###############################################################
#  Generated by:      Cadence Innovus 20.13-s083_1
#  OS:                Linux x86_64(Host ID rice-503-20-north)
#  Generated on:      Sat Jun 11 21:53:26 2022
#  Design:            user_proj_example
#  Command:           write_lef_abstract -specifyTopLayer 5 -PGPinLayers {5 6} -extractBlockObs -stripePin results/user_proj_example.lef
###############################################################

VERSION 5.8 ;

BUSBITCHARS "[]" ;
DIVIDERCHAR "/" ;

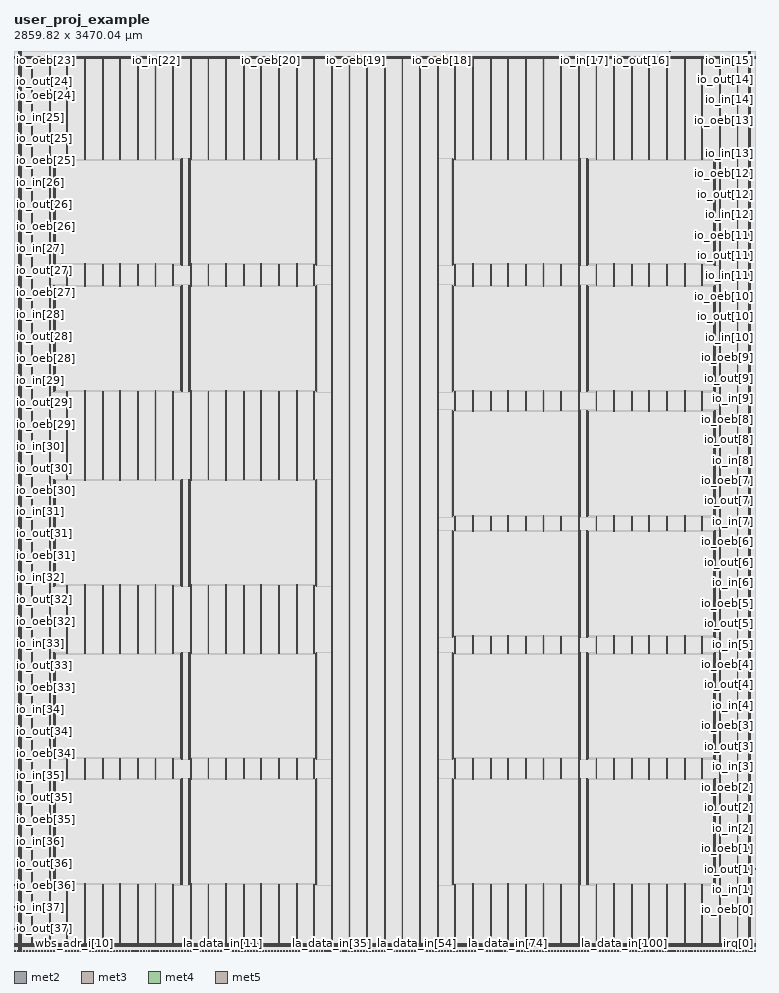
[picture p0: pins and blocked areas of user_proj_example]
MACRO user_proj_example
  CLASS BLOCK ;
  SIZE 2859.820000 BY 3470.040000 ;
  FOREIGN user_proj_example 0.000000 0.000000 ;
  ORIGIN 0 0 ;
  SYMMETRY X Y R90 ;
  PIN wb_clk_i
    DIRECTION INPUT ;
    USE SIGNAL ;
    ANTENNAPARTIALMETALAREA 4.1174 LAYER met2  ;
    ANTENNAPARTIALMETALSIDEAREA 20.426 LAYER met2  ;
    ANTENNAPARTIALCUTAREA 0.04 LAYER via2  ;
    ANTENNAPARTIALMETALAREA 8.6748 LAYER met3  ;
    ANTENNAPARTIALMETALSIDEAREA 46.736 LAYER met3  ;
    ANTENNAMODEL OXIDE1 ;
    ANTENNAGATEAREA 0.576 LAYER met3  ;
    ANTENNAMAXAREACAR 16.2276 LAYER met3  ;
    ANTENNAMAXSIDEAREACAR 83.9896 LAYER met3  ;
    ANTENNAMAXCUTCAR 0.158681 LAYER via3  ;
    PORT
      LAYER met2 ;
        RECT 0.620000 0.000000 0.760000 0.485000 ;
    END
  END wb_clk_i
  PIN wb_rst_i
    DIRECTION INPUT ;
    USE SIGNAL ;
    ANTENNAPARTIALMETALAREA 4.9795 LAYER met2  ;
    ANTENNAPARTIALMETALSIDEAREA 24.6715 LAYER met2  ;
    ANTENNAMODEL OXIDE1 ;
    ANTENNAGATEAREA 0.315 LAYER met2  ;
    ANTENNAMAXAREACAR 17.281 LAYER met2  ;
    ANTENNAMAXSIDEAREACAR 82.5778 LAYER met2  ;
    ANTENNAMAXCUTCAR 0.163175 LAYER via2  ;
    PORT
      LAYER met2 ;
        RECT 6.140000 0.000000 6.280000 0.485000 ;
    END
  END wb_rst_i
  PIN wbs_stb_i
    DIRECTION INPUT ;
    USE SIGNAL ;
    ANTENNAPARTIALMETALAREA 4.3959 LAYER met2  ;
    ANTENNAPARTIALMETALSIDEAREA 21.8715 LAYER met2  ;
    ANTENNAMODEL OXIDE1 ;
    ANTENNAGATEAREA 0.2475 LAYER met2  ;
    ANTENNAMAXAREACAR 24.3469 LAYER met2  ;
    ANTENNAMAXSIDEAREACAR 115.984 LAYER met2  ;
    ANTENNAMAXCUTCAR 0.207677 LAYER via2  ;
    PORT
      LAYER met2 ;
        RECT 23.620000 0.000000 23.760000 0.485000 ;
    END
  END wbs_stb_i
  PIN wbs_cyc_i
    DIRECTION INPUT ;
    USE SIGNAL ;
    ANTENNAPARTIALMETALAREA 4.5863 LAYER met2  ;
    ANTENNAPARTIALMETALSIDEAREA 22.8235 LAYER met2  ;
    ANTENNAMODEL OXIDE1 ;
    ANTENNAGATEAREA 0.2475 LAYER met2  ;
    ANTENNAMAXAREACAR 26.3545 LAYER met2  ;
    ANTENNAMAXSIDEAREACAR 129.685 LAYER met2  ;
    ANTENNAMAXCUTCAR 0.207677 LAYER via2  ;
    PORT
      LAYER met2 ;
        RECT 17.640000 0.000000 17.780000 0.485000 ;
    END
  END wbs_cyc_i
  PIN wbs_we_i
    DIRECTION INPUT ;
    USE SIGNAL ;
    ANTENNAPARTIALMETALAREA 5.5507 LAYER met2  ;
    ANTENNAPARTIALMETALSIDEAREA 27.5275 LAYER met2  ;
    ANTENNAMODEL OXIDE1 ;
    ANTENNAGATEAREA 0.159 LAYER met2  ;
    ANTENNAMAXAREACAR 37.6255 LAYER met2  ;
    ANTENNAMAXSIDEAREACAR 183 LAYER met2  ;
    ANTENNAMAXCUTCAR 0.32327 LAYER via2  ;
    PORT
      LAYER met2 ;
        RECT 29.600000 0.000000 29.740000 0.485000 ;
    END
  END wbs_we_i
  PIN wbs_sel_i[3]
    DIRECTION INPUT ;
    USE SIGNAL ;
    PORT
      LAYER met2 ;
        RECT 122.060000 0.000000 122.200000 0.485000 ;
    END
  END wbs_sel_i[3]
  PIN wbs_sel_i[2]
    DIRECTION INPUT ;
    USE SIGNAL ;
    PORT
      LAYER met2 ;
        RECT 99.060000 0.000000 99.200000 0.485000 ;
    END
  END wbs_sel_i[2]
  PIN wbs_sel_i[1]
    DIRECTION INPUT ;
    USE SIGNAL ;
    PORT
      LAYER met2 ;
        RECT 75.600000 0.000000 75.740000 0.485000 ;
    END
  END wbs_sel_i[1]
  PIN wbs_sel_i[0]
    DIRECTION INPUT ;
    USE SIGNAL ;
    PORT
      LAYER met2 ;
        RECT 52.600000 0.000000 52.740000 0.485000 ;
    END
  END wbs_sel_i[0]
  PIN wbs_dat_i[31]
    DIRECTION INPUT ;
    USE SIGNAL ;
    ANTENNAPARTIALMETALAREA 8.2991 LAYER met2  ;
    ANTENNAPARTIALMETALSIDEAREA 41.3875 LAYER met2  ;
    ANTENNAMODEL OXIDE1 ;
    ANTENNAGATEAREA 0.126 LAYER met2  ;
    ANTENNAMAXAREACAR 87.297 LAYER met2  ;
    ANTENNAMAXSIDEAREACAR 409.46 LAYER met2  ;
    ANTENNAMAXCUTCAR 0.407937 LAYER via2  ;
    PORT
      LAYER met2 ;
        RECT 603.680000 0.000000 603.820000 0.485000 ;
    END
  END wbs_dat_i[31]
  PIN wbs_dat_i[30]
    DIRECTION INPUT ;
    USE SIGNAL ;
    ANTENNAPARTIALMETALAREA 7.8735 LAYER met2  ;
    ANTENNAPARTIALMETALSIDEAREA 39.2595 LAYER met2  ;
    ANTENNAMODEL OXIDE1 ;
    ANTENNAGATEAREA 0.126 LAYER met2  ;
    ANTENNAMAXAREACAR 73.797 LAYER met2  ;
    ANTENNAMAXSIDEAREACAR 341.96 LAYER met2  ;
    ANTENNAMAXCUTCAR 0.407937 LAYER via2  ;
    PORT
      LAYER met2 ;
        RECT 586.200000 0.000000 586.340000 0.485000 ;
    END
  END wbs_dat_i[30]
  PIN wbs_dat_i[29]
    DIRECTION INPUT ;
    USE SIGNAL ;
    ANTENNAPARTIALMETALAREA 6.3951 LAYER met2  ;
    ANTENNAPARTIALMETALSIDEAREA 31.8675 LAYER met2  ;
    ANTENNAMODEL OXIDE1 ;
    ANTENNAGATEAREA 0.126 LAYER met2  ;
    ANTENNAMAXAREACAR 62.5748 LAYER met2  ;
    ANTENNAMAXSIDEAREACAR 285.849 LAYER met2  ;
    ANTENNAMAXCUTCAR 0.407937 LAYER via2  ;
    PORT
      LAYER met2 ;
        RECT 568.720000 0.000000 568.860000 0.485000 ;
    END
  END wbs_dat_i[29]
  PIN wbs_dat_i[28]
    DIRECTION INPUT ;
    USE SIGNAL ;
    ANTENNAPARTIALMETALAREA 7.9379 LAYER met2  ;
    ANTENNAPARTIALMETALSIDEAREA 39.5815 LAYER met2  ;
    ANTENNAMODEL OXIDE1 ;
    ANTENNAGATEAREA 0.126 LAYER met2  ;
    ANTENNAMAXAREACAR 88.8637 LAYER met2  ;
    ANTENNAMAXSIDEAREACAR 417.294 LAYER met2  ;
    ANTENNAMAXCUTCAR 0.407937 LAYER via2  ;
    PORT
      LAYER met2 ;
        RECT 551.240000 0.000000 551.380000 0.485000 ;
    END
  END wbs_dat_i[28]
  PIN wbs_dat_i[27]
    DIRECTION INPUT ;
    USE SIGNAL ;
    ANTENNAPARTIALMETALAREA 9.652 LAYER met2  ;
    ANTENNAPARTIALMETALSIDEAREA 48.034 LAYER met2  ;
    ANTENNAMODEL OXIDE1 ;
    ANTENNAGATEAREA 0.126 LAYER met2  ;
    ANTENNAMAXAREACAR 83.4272 LAYER met2  ;
    ANTENNAMAXSIDEAREACAR 389.71 LAYER met2  ;
    ANTENNAMAXCUTCAR 0.407937 LAYER via2  ;
    PORT
      LAYER met2 ;
        RECT 533.760000 0.000000 533.900000 0.485000 ;
    END
  END wbs_dat_i[27]
  PIN wbs_dat_i[26]
    DIRECTION INPUT ;
    USE SIGNAL ;
    ANTENNAPARTIALMETALAREA 9.9187 LAYER met2  ;
    ANTENNAPARTIALMETALSIDEAREA 49.3675 LAYER met2  ;
    ANTENNAMODEL OXIDE1 ;
    ANTENNAGATEAREA 0.126 LAYER met2  ;
    ANTENNAMAXAREACAR 85.5438 LAYER met2  ;
    ANTENNAMAXSIDEAREACAR 400.294 LAYER met2  ;
    ANTENNAMAXCUTCAR 0.407937 LAYER via2  ;
    PORT
      LAYER met2 ;
        RECT 516.740000 0.000000 516.880000 0.485000 ;
    END
  END wbs_dat_i[26]
  PIN wbs_dat_i[25]
    DIRECTION INPUT ;
    USE SIGNAL ;
    ANTENNAPARTIALMETALAREA 7.1831 LAYER met2  ;
    ANTENNAPARTIALMETALSIDEAREA 35.6895 LAYER met2  ;
    ANTENNAMODEL OXIDE1 ;
    ANTENNAGATEAREA 0.126 LAYER met2  ;
    ANTENNAMAXAREACAR 63.8327 LAYER met2  ;
    ANTENNAMAXSIDEAREACAR 291.738 LAYER met2  ;
    ANTENNAMAXCUTCAR 0.407937 LAYER via2  ;
    PORT
      LAYER met2 ;
        RECT 499.260000 0.000000 499.400000 0.485000 ;
    END
  END wbs_dat_i[25]
  PIN wbs_dat_i[24]
    DIRECTION INPUT ;
    USE SIGNAL ;
    ANTENNAPARTIALMETALAREA 6.8499 LAYER met2  ;
    ANTENNAPARTIALMETALSIDEAREA 34.0235 LAYER met2  ;
    ANTENNAMODEL OXIDE1 ;
    ANTENNAGATEAREA 0.126 LAYER met2  ;
    ANTENNAMAXAREACAR 80.101 LAYER met2  ;
    ANTENNAMAXSIDEAREACAR 372.544 LAYER met2  ;
    ANTENNAMAXCUTCAR 0.407937 LAYER via2  ;
    PORT
      LAYER met2 ;
        RECT 481.780000 0.000000 481.920000 0.485000 ;
    END
  END wbs_dat_i[24]
  PIN wbs_dat_i[23]
    DIRECTION INPUT ;
    USE SIGNAL ;
    ANTENNAPARTIALMETALAREA 7.9923 LAYER met2  ;
    ANTENNAPARTIALMETALSIDEAREA 39.7355 LAYER met2  ;
    ANTENNAMODEL OXIDE1 ;
    ANTENNAGATEAREA 0.126 LAYER met2  ;
    ANTENNAMAXAREACAR 70.651 LAYER met2  ;
    ANTENNAMAXSIDEAREACAR 325.294 LAYER met2  ;
    ANTENNAMAXCUTCAR 0.407937 LAYER via2  ;
    PORT
      LAYER met2 ;
        RECT 464.300000 0.000000 464.440000 0.485000 ;
    END
  END wbs_dat_i[23]
  PIN wbs_dat_i[22]
    DIRECTION INPUT ;
    USE SIGNAL ;
    ANTENNAPARTIALMETALAREA 7.9112 LAYER met2  ;
    ANTENNAPARTIALMETALSIDEAREA 39.277 LAYER met2  ;
    ANTENNAPARTIALCUTAREA 0.04 LAYER via2  ;
    ANTENNAPARTIALMETALAREA 0.2509 LAYER met3  ;
    ANTENNAPARTIALMETALSIDEAREA 1.808 LAYER met3  ;
    ANTENNAPARTIALCUTAREA 0.04 LAYER via3  ;
    ANTENNAPARTIALMETALAREA 4.1448 LAYER met4  ;
    ANTENNAPARTIALMETALSIDEAREA 22.576 LAYER met4  ;
    ANTENNAMODEL OXIDE1 ;
    ANTENNAGATEAREA 0.126 LAYER met4  ;
    ANTENNAMAXAREACAR 70.3264 LAYER met4  ;
    ANTENNAMAXSIDEAREACAR 342.262 LAYER met4  ;
    ANTENNAMAXCUTCAR 1.04286 LAYER via4  ;
    PORT
      LAYER met2 ;
        RECT 446.820000 0.000000 446.960000 0.485000 ;
    END
  END wbs_dat_i[22]
  PIN wbs_dat_i[21]
    DIRECTION INPUT ;
    USE SIGNAL ;
    ANTENNAPARTIALMETALAREA 6.9451 LAYER met2  ;
    ANTENNAPARTIALMETALSIDEAREA 34.4995 LAYER met2  ;
    ANTENNAMODEL OXIDE1 ;
    ANTENNAGATEAREA 0.126 LAYER met2  ;
    ANTENNAMAXAREACAR 86.6065 LAYER met2  ;
    ANTENNAMAXSIDEAREACAR 405.071 LAYER met2  ;
    ANTENNAMAXCUTCAR 0.407937 LAYER via2  ;
    PORT
      LAYER met2 ;
        RECT 429.800000 0.000000 429.940000 0.485000 ;
    END
  END wbs_dat_i[21]
  PIN wbs_dat_i[20]
    DIRECTION INPUT ;
    USE SIGNAL ;
    ANTENNAPARTIALMETALAREA 10.1666 LAYER met2  ;
    ANTENNAPARTIALMETALSIDEAREA 50.554 LAYER met2  ;
    ANTENNAPARTIALCUTAREA 0.04 LAYER via2  ;
    ANTENNAPARTIALMETALAREA 0.2509 LAYER met3  ;
    ANTENNAPARTIALMETALSIDEAREA 1.808 LAYER met3  ;
    ANTENNAPARTIALCUTAREA 0.04 LAYER via3  ;
    ANTENNAPARTIALMETALAREA 3.9618 LAYER met4  ;
    ANTENNAPARTIALMETALSIDEAREA 21.6 LAYER met4  ;
    ANTENNAMODEL OXIDE1 ;
    ANTENNAGATEAREA 0.126 LAYER met4  ;
    ANTENNAMAXAREACAR 103.864 LAYER met4  ;
    ANTENNAMAXSIDEAREACAR 510.405 LAYER met4  ;
    ANTENNAMAXCUTCAR 1.04286 LAYER via4  ;
    PORT
      LAYER met2 ;
        RECT 412.320000 0.000000 412.460000 0.485000 ;
    END
  END wbs_dat_i[20]
  PIN wbs_dat_i[19]
    DIRECTION INPUT ;
    USE SIGNAL ;
    ANTENNAPARTIALMETALAREA 0.8365 LAYER met2  ;
    ANTENNAPARTIALMETALSIDEAREA 4.0215 LAYER met2  ;
    ANTENNAPARTIALCUTAREA 0.04 LAYER via2  ;
    ANTENNAPARTIALMETALAREA 30.919 LAYER met3  ;
    ANTENNAPARTIALMETALSIDEAREA 165.368 LAYER met3  ;
    ANTENNAPARTIALCUTAREA 0.04 LAYER via3  ;
    ANTENNAPARTIALMETALAREA 0.6516 LAYER met4  ;
    ANTENNAPARTIALMETALSIDEAREA 4.416 LAYER met4  ;
    ANTENNAMODEL OXIDE1 ;
    ANTENNAGATEAREA 0.126 LAYER met4  ;
    ANTENNAMAXAREACAR 97.6891 LAYER met4  ;
    ANTENNAMAXSIDEAREACAR 477.952 LAYER met4  ;
    ANTENNAMAXCUTCAR 1.04286 LAYER via4  ;
    PORT
      LAYER met2 ;
        RECT 394.840000 0.000000 394.980000 0.485000 ;
    END
  END wbs_dat_i[19]
  PIN wbs_dat_i[18]
    DIRECTION INPUT ;
    USE SIGNAL ;
    ANTENNAPARTIALMETALAREA 0.3598 LAYER met2  ;
    ANTENNAPARTIALMETALSIDEAREA 1.638 LAYER met2  ;
    ANTENNAPARTIALCUTAREA 0.04 LAYER via2  ;
    ANTENNAPARTIALMETALAREA 44.719 LAYER met3  ;
    ANTENNAPARTIALMETALSIDEAREA 238.968 LAYER met3  ;
    ANTENNAPARTIALCUTAREA 0.04 LAYER via3  ;
    ANTENNAPARTIALMETALAREA 0.6516 LAYER met4  ;
    ANTENNAPARTIALMETALSIDEAREA 4.416 LAYER met4  ;
    ANTENNAMODEL OXIDE1 ;
    ANTENNAGATEAREA 0.126 LAYER met4  ;
    ANTENNAMAXAREACAR 126.784 LAYER met4  ;
    ANTENNAMAXSIDEAREACAR 624 LAYER met4  ;
    ANTENNAMAXCUTCAR 1.04286 LAYER via4  ;
    PORT
      LAYER met2 ;
        RECT 377.360000 0.000000 377.500000 0.485000 ;
    END
  END wbs_dat_i[18]
  PIN wbs_dat_i[17]
    DIRECTION INPUT ;
    USE SIGNAL ;
    ANTENNAPARTIALMETALAREA 1.876 LAYER met2  ;
    ANTENNAPARTIALMETALSIDEAREA 9.219 LAYER met2  ;
    ANTENNAPARTIALCUTAREA 0.04 LAYER via2  ;
    ANTENNAPARTIALMETALAREA 53.599 LAYER met3  ;
    ANTENNAPARTIALMETALSIDEAREA 286.328 LAYER met3  ;
    ANTENNAPARTIALCUTAREA 0.04 LAYER via3  ;
    ANTENNAPARTIALMETALAREA 0.6516 LAYER met4  ;
    ANTENNAPARTIALMETALSIDEAREA 4.416 LAYER met4  ;
    ANTENNAMODEL OXIDE1 ;
    ANTENNAGATEAREA 0.126 LAYER met4  ;
    ANTENNAMAXAREACAR 87.7597 LAYER met4  ;
    ANTENNAMAXSIDEAREACAR 427.782 LAYER met4  ;
    ANTENNAMAXCUTCAR 1.04286 LAYER via4  ;
    PORT
      LAYER met2 ;
        RECT 359.880000 0.000000 360.020000 0.485000 ;
    END
  END wbs_dat_i[17]
  PIN wbs_dat_i[16]
    DIRECTION INPUT ;
    USE SIGNAL ;
    ANTENNAPARTIALMETALAREA 7.9924 LAYER met2  ;
    ANTENNAPARTIALMETALSIDEAREA 39.683 LAYER met2  ;
    ANTENNAPARTIALCUTAREA 0.04 LAYER via2  ;
    ANTENNAPARTIALMETALAREA 0.255 LAYER met3  ;
    ANTENNAPARTIALMETALSIDEAREA 1.808 LAYER met3  ;
    ANTENNAPARTIALCUTAREA 0.04 LAYER via3  ;
    ANTENNAPARTIALMETALAREA 5.9748 LAYER met4  ;
    ANTENNAPARTIALMETALSIDEAREA 32.336 LAYER met4  ;
    ANTENNAMODEL OXIDE1 ;
    ANTENNAGATEAREA 0.126 LAYER met4  ;
    ANTENNAMAXAREACAR 59.1216 LAYER met4  ;
    ANTENNAMAXSIDEAREACAR 292.389 LAYER met4  ;
    ANTENNAMAXCUTCAR 1.04286 LAYER via4  ;
    PORT
      LAYER met2 ;
        RECT 342.400000 0.000000 342.540000 0.485000 ;
    END
  END wbs_dat_i[16]
  PIN wbs_dat_i[15]
    DIRECTION INPUT ;
    USE SIGNAL ;
    ANTENNAPARTIALMETALAREA 1.5344 LAYER met2  ;
    ANTENNAPARTIALMETALSIDEAREA 7.511 LAYER met2  ;
    ANTENNAPARTIALCUTAREA 0.04 LAYER via2  ;
    ANTENNAPARTIALMETALAREA 66.295 LAYER met3  ;
    ANTENNAPARTIALMETALSIDEAREA 354.04 LAYER met3  ;
    ANTENNAPARTIALCUTAREA 0.04 LAYER via3  ;
    ANTENNAPARTIALMETALAREA 0.6516 LAYER met4  ;
    ANTENNAPARTIALMETALSIDEAREA 4.416 LAYER met4  ;
    ANTENNAMODEL OXIDE1 ;
    ANTENNAGATEAREA 0.126 LAYER met4  ;
    ANTENNAMAXAREACAR 107.018 LAYER met4  ;
    ANTENNAMAXSIDEAREACAR 525.167 LAYER met4  ;
    ANTENNAMAXCUTCAR 1.04286 LAYER via4  ;
    PORT
      LAYER met2 ;
        RECT 325.380000 0.000000 325.520000 0.485000 ;
    END
  END wbs_dat_i[15]
  PIN wbs_dat_i[14]
    DIRECTION INPUT ;
    USE SIGNAL ;
    ANTENNAPARTIALMETALAREA 7.4209 LAYER met2  ;
    ANTENNAPARTIALMETALSIDEAREA 36.7605 LAYER met2  ;
    ANTENNAMODEL OXIDE1 ;
    ANTENNAGATEAREA 0.126 LAYER met2  ;
    ANTENNAMAXAREACAR 65.72 LAYER met2  ;
    ANTENNAMAXSIDEAREACAR 300.238 LAYER met2  ;
    ANTENNAMAXCUTCAR 0.407937 LAYER via2  ;
    PORT
      LAYER met2 ;
        RECT 307.900000 0.000000 308.040000 0.485000 ;
    END
  END wbs_dat_i[14]
  PIN wbs_dat_i[13]
    DIRECTION INPUT ;
    USE SIGNAL ;
    ANTENNAPARTIALMETALAREA 6.829 LAYER met2  ;
    ANTENNAPARTIALMETALSIDEAREA 33.866 LAYER met2  ;
    ANTENNAPARTIALCUTAREA 0.04 LAYER via2  ;
    ANTENNAPARTIALMETALAREA 0.255 LAYER met3  ;
    ANTENNAPARTIALMETALSIDEAREA 1.808 LAYER met3  ;
    ANTENNAPARTIALCUTAREA 0.04 LAYER via3  ;
    ANTENNAPARTIALMETALAREA 6.1578 LAYER met4  ;
    ANTENNAPARTIALMETALSIDEAREA 33.312 LAYER met4  ;
    ANTENNAMODEL OXIDE1 ;
    ANTENNAGATEAREA 0.126 LAYER met4  ;
    ANTENNAMAXAREACAR 85.2589 LAYER met4  ;
    ANTENNAMAXSIDEAREACAR 423.024 LAYER met4  ;
    ANTENNAMAXCUTCAR 1.04286 LAYER via4  ;
    PORT
      LAYER met2 ;
        RECT 290.420000 0.000000 290.560000 0.485000 ;
    END
  END wbs_dat_i[13]
  PIN wbs_dat_i[12]
    DIRECTION INPUT ;
    USE SIGNAL ;
    ANTENNAPARTIALMETALAREA 7.5569 LAYER met2  ;
    ANTENNAPARTIALMETALSIDEAREA 37.5585 LAYER met2  ;
    ANTENNAMODEL OXIDE1 ;
    ANTENNAGATEAREA 0.126 LAYER met2  ;
    ANTENNAMAXAREACAR 67.1954 LAYER met2  ;
    ANTENNAMAXSIDEAREACAR 308.016 LAYER met2  ;
    ANTENNAMAXCUTCAR 0.407937 LAYER via2  ;
    PORT
      LAYER met2 ;
        RECT 272.940000 0.000000 273.080000 0.485000 ;
    END
  END wbs_dat_i[12]
  PIN wbs_dat_i[11]
    DIRECTION INPUT ;
    USE SIGNAL ;
    ANTENNAPARTIALMETALAREA 5.6655 LAYER met2  ;
    ANTENNAPARTIALMETALSIDEAREA 28.1015 LAYER met2  ;
    ANTENNAMODEL OXIDE1 ;
    ANTENNAGATEAREA 0.126 LAYER met2  ;
    ANTENNAMAXAREACAR 65.3399 LAYER met2  ;
    ANTENNAMAXSIDEAREACAR 298.738 LAYER met2  ;
    ANTENNAMAXCUTCAR 0.407937 LAYER via2  ;
    PORT
      LAYER met2 ;
        RECT 255.460000 0.000000 255.600000 0.485000 ;
    END
  END wbs_dat_i[11]
  PIN wbs_dat_i[10]
    DIRECTION INPUT ;
    USE SIGNAL ;
    ANTENNAPARTIALMETALAREA 7.8636 LAYER met2  ;
    ANTENNAPARTIALMETALSIDEAREA 39.039 LAYER met2  ;
    ANTENNAPARTIALCUTAREA 0.04 LAYER via2  ;
    ANTENNAPARTIALMETALAREA 0.255 LAYER met3  ;
    ANTENNAPARTIALMETALSIDEAREA 1.808 LAYER met3  ;
    ANTENNAPARTIALCUTAREA 0.04 LAYER via3  ;
    ANTENNAPARTIALMETALAREA 5.9748 LAYER met4  ;
    ANTENNAPARTIALMETALSIDEAREA 32.336 LAYER met4  ;
    ANTENNAMODEL OXIDE1 ;
    ANTENNAGATEAREA 0.126 LAYER met4  ;
    ANTENNAMAXAREACAR 81.6177 LAYER met4  ;
    ANTENNAMAXSIDEAREACAR 404.333 LAYER met4  ;
    ANTENNAMAXCUTCAR 1.04286 LAYER via4  ;
    PORT
      LAYER met2 ;
        RECT 237.980000 0.000000 238.120000 0.485000 ;
    END
  END wbs_dat_i[10]
  PIN wbs_dat_i[9]
    DIRECTION INPUT ;
    USE SIGNAL ;
    ANTENNAPARTIALMETALAREA 2.2386 LAYER met2  ;
    ANTENNAPARTIALMETALSIDEAREA 11.032 LAYER met2  ;
    ANTENNAPARTIALCUTAREA 0.04 LAYER via2  ;
    ANTENNAPARTIALMETALAREA 93.343 LAYER met3  ;
    ANTENNAPARTIALMETALSIDEAREA 498.296 LAYER met3  ;
    ANTENNAPARTIALCUTAREA 0.04 LAYER via3  ;
    ANTENNAPARTIALMETALAREA 0.6516 LAYER met4  ;
    ANTENNAPARTIALMETALSIDEAREA 4.416 LAYER met4  ;
    ANTENNAMODEL OXIDE1 ;
    ANTENNAGATEAREA 0.126 LAYER met4  ;
    ANTENNAMAXAREACAR 81.4383 LAYER met4  ;
    ANTENNAMAXSIDEAREACAR 396.54 LAYER met4  ;
    ANTENNAMAXCUTCAR 1.04286 LAYER via4  ;
    PORT
      LAYER met2 ;
        RECT 220.960000 0.000000 221.100000 0.485000 ;
    END
  END wbs_dat_i[9]
  PIN wbs_dat_i[8]
    DIRECTION INPUT ;
    USE SIGNAL ;
    ANTENNAPARTIALMETALAREA 8.0092 LAYER met2  ;
    ANTENNAPARTIALMETALSIDEAREA 39.767 LAYER met2  ;
    ANTENNAPARTIALCUTAREA 0.04 LAYER via2  ;
    ANTENNAPARTIALMETALAREA 0.2509 LAYER met3  ;
    ANTENNAPARTIALMETALSIDEAREA 1.808 LAYER met3  ;
    ANTENNAPARTIALCUTAREA 0.04 LAYER via3  ;
    ANTENNAPARTIALMETALAREA 4.1448 LAYER met4  ;
    ANTENNAPARTIALMETALSIDEAREA 22.576 LAYER met4  ;
    ANTENNAMODEL OXIDE1 ;
    ANTENNAGATEAREA 0.126 LAYER met4  ;
    ANTENNAMAXAREACAR 58.4502 LAYER met4  ;
    ANTENNAMAXSIDEAREACAR 283.817 LAYER met4  ;
    ANTENNAMAXCUTCAR 1.04286 LAYER via4  ;
    PORT
      LAYER met2 ;
        RECT 203.480000 0.000000 203.620000 0.485000 ;
    END
  END wbs_dat_i[8]
  PIN wbs_dat_i[7]
    DIRECTION INPUT ;
    USE SIGNAL ;
    ANTENNAPARTIALMETALAREA 7.9112 LAYER met2  ;
    ANTENNAPARTIALMETALSIDEAREA 39.277 LAYER met2  ;
    ANTENNAPARTIALCUTAREA 0.04 LAYER via2  ;
    ANTENNAPARTIALMETALAREA 0.2509 LAYER met3  ;
    ANTENNAPARTIALMETALSIDEAREA 1.808 LAYER met3  ;
    ANTENNAPARTIALCUTAREA 0.04 LAYER via3  ;
    ANTENNAPARTIALMETALAREA 4.1448 LAYER met4  ;
    ANTENNAPARTIALMETALSIDEAREA 22.576 LAYER met4  ;
    ANTENNAMODEL OXIDE1 ;
    ANTENNAGATEAREA 0.126 LAYER met4  ;
    ANTENNAMAXAREACAR 82.4946 LAYER met4  ;
    ANTENNAMAXSIDEAREACAR 404.04 LAYER met4  ;
    ANTENNAMAXCUTCAR 1.04286 LAYER via4  ;
    PORT
      LAYER met2 ;
        RECT 186.000000 0.000000 186.140000 0.485000 ;
    END
  END wbs_dat_i[7]
  PIN wbs_dat_i[6]
    DIRECTION INPUT ;
    USE SIGNAL ;
    ANTENNAPARTIALMETALAREA 8.3731 LAYER met2  ;
    ANTENNAPARTIALMETALSIDEAREA 41.6395 LAYER met2  ;
    ANTENNAMODEL OXIDE1 ;
    ANTENNAGATEAREA 0.126 LAYER met2  ;
    ANTENNAMAXAREACAR 127.701 LAYER met2  ;
    ANTENNAMAXSIDEAREACAR 610.544 LAYER met2  ;
    ANTENNAMAXCUTCAR 0.407937 LAYER via2  ;
    PORT
      LAYER met2 ;
        RECT 168.520000 0.000000 168.660000 0.485000 ;
    END
  END wbs_dat_i[6]
  PIN wbs_dat_i[5]
    DIRECTION INPUT ;
    USE SIGNAL ;
    ANTENNAPARTIALMETALAREA 8.4263 LAYER met2  ;
    ANTENNAPARTIALMETALSIDEAREA 41.9055 LAYER met2  ;
    ANTENNAMODEL OXIDE1 ;
    ANTENNAGATEAREA 0.126 LAYER met2  ;
    ANTENNAMAXAREACAR 74.0954 LAYER met2  ;
    ANTENNAMAXSIDEAREACAR 342.516 LAYER met2  ;
    ANTENNAMAXCUTCAR 0.407937 LAYER via2  ;
    PORT
      LAYER met2 ;
        RECT 151.040000 0.000000 151.180000 0.485000 ;
    END
  END wbs_dat_i[5]
  PIN wbs_dat_i[4]
    DIRECTION INPUT ;
    USE SIGNAL ;
    ANTENNAPARTIALMETALAREA 9.0004 LAYER met2  ;
    ANTENNAPARTIALMETALSIDEAREA 44.723 LAYER met2  ;
    ANTENNAPARTIALCUTAREA 0.04 LAYER via2  ;
    ANTENNAPARTIALMETALAREA 0.2509 LAYER met3  ;
    ANTENNAPARTIALMETALSIDEAREA 1.808 LAYER met3  ;
    ANTENNAPARTIALCUTAREA 0.04 LAYER via3  ;
    ANTENNAPARTIALMETALAREA 3.9618 LAYER met4  ;
    ANTENNAPARTIALMETALSIDEAREA 21.6 LAYER met4  ;
    ANTENNAMODEL OXIDE1 ;
    ANTENNAGATEAREA 0.126 LAYER met4  ;
    ANTENNAMAXAREACAR 51.5978 LAYER met4  ;
    ANTENNAMAXSIDEAREACAR 249.071 LAYER met4  ;
    ANTENNAMAXCUTCAR 1.04286 LAYER via4  ;
    PORT
      LAYER met2 ;
        RECT 133.560000 0.000000 133.700000 0.485000 ;
    END
  END wbs_dat_i[4]
  PIN wbs_dat_i[3]
    DIRECTION INPUT ;
    USE SIGNAL ;
    ANTENNAPARTIALMETALAREA 9.8779 LAYER met2  ;
    ANTENNAPARTIALMETALSIDEAREA 49.0455 LAYER met2  ;
    ANTENNAMODEL OXIDE1 ;
    ANTENNAGATEAREA 0.126 LAYER met2  ;
    ANTENNAMAXAREACAR 84.9145 LAYER met2  ;
    ANTENNAMAXSIDEAREACAR 396.21 LAYER met2  ;
    ANTENNAMAXCUTCAR 0.407937 LAYER via2  ;
    PORT
      LAYER met2 ;
        RECT 110.560000 0.000000 110.700000 0.485000 ;
    END
  END wbs_dat_i[3]
  PIN wbs_dat_i[2]
    DIRECTION INPUT ;
    USE SIGNAL ;
    ANTENNADIFFAREA 0.4347 LAYER met2  ;
    ANTENNAPARTIALMETALAREA 11.6099 LAYER met2  ;
    ANTENNAPARTIALMETALSIDEAREA 57.8235 LAYER met2  ;
    ANTENNAMODEL OXIDE1 ;
    ANTENNAGATEAREA 0.126 LAYER met2  ;
    ANTENNAMAXAREACAR 117.458 LAYER met2  ;
    ANTENNAMAXSIDEAREACAR 558.794 LAYER met2  ;
    ANTENNAMAXCUTCAR 0.407937 LAYER via2  ;
    PORT
      LAYER met2 ;
        RECT 87.560000 0.000000 87.700000 0.485000 ;
    END
  END wbs_dat_i[2]
  PIN wbs_dat_i[1]
    DIRECTION INPUT ;
    USE SIGNAL ;
    ANTENNAPARTIALMETALAREA 9.5419 LAYER met2  ;
    ANTENNAPARTIALMETALSIDEAREA 47.3655 LAYER met2  ;
    ANTENNAMODEL OXIDE1 ;
    ANTENNAGATEAREA 0.126 LAYER met2  ;
    ANTENNAMAXAREACAR 84.4827 LAYER met2  ;
    ANTENNAMAXSIDEAREACAR 393.516 LAYER met2  ;
    ANTENNAMAXCUTCAR 0.407937 LAYER via2  ;
    PORT
      LAYER met2 ;
        RECT 64.100000 0.000000 64.240000 0.485000 ;
    END
  END wbs_dat_i[1]
  PIN wbs_dat_i[0]
    DIRECTION INPUT ;
    USE SIGNAL ;
    ANTENNAPARTIALMETALAREA 6.7547 LAYER met2  ;
    ANTENNAPARTIALMETALSIDEAREA 33.5475 LAYER met2  ;
    ANTENNAMODEL OXIDE1 ;
    ANTENNAGATEAREA 0.126 LAYER met2  ;
    ANTENNAMAXAREACAR 62.9454 LAYER met2  ;
    ANTENNAMAXSIDEAREACAR 286.766 LAYER met2  ;
    ANTENNAMAXCUTCAR 0.407937 LAYER via2  ;
    PORT
      LAYER met2 ;
        RECT 41.100000 0.000000 41.240000 0.485000 ;
    END
  END wbs_dat_i[0]
  PIN wbs_adr_i[31]
    DIRECTION INPUT ;
    USE SIGNAL ;
    ANTENNAPARTIALMETALAREA 5.2695 LAYER met2  ;
    ANTENNAPARTIALMETALSIDEAREA 26.2395 LAYER met2  ;
    ANTENNAMODEL OXIDE1 ;
    ANTENNAGATEAREA 0.126 LAYER met2  ;
    ANTENNAMAXAREACAR 76.6526 LAYER met2  ;
    ANTENNAMAXSIDEAREACAR 356.238 LAYER met2  ;
    ANTENNAMAXCUTCAR 0.407937 LAYER via2  ;
    PORT
      LAYER met2 ;
        RECT 597.700000 0.000000 597.840000 0.485000 ;
    END
  END wbs_adr_i[31]
  PIN wbs_adr_i[30]
    DIRECTION INPUT ;
    USE SIGNAL ;
    ANTENNAPARTIALMETALAREA 5.8267 LAYER met2  ;
    ANTENNAPARTIALMETALSIDEAREA 29.0255 LAYER met2  ;
    ANTENNAMODEL OXIDE1 ;
    ANTENNAGATEAREA 0.126 LAYER met2  ;
    ANTENNAMAXAREACAR 53.4637 LAYER met2  ;
    ANTENNAMAXSIDEAREACAR 240.294 LAYER met2  ;
    ANTENNAMAXCUTCAR 0.407937 LAYER via2  ;
    PORT
      LAYER met2 ;
        RECT 580.220000 0.000000 580.360000 0.485000 ;
    END
  END wbs_adr_i[30]
  PIN wbs_adr_i[29]
    DIRECTION INPUT ;
    USE SIGNAL ;
    ANTENNAPARTIALMETALAREA 6.1907 LAYER met2  ;
    ANTENNAPARTIALMETALSIDEAREA 30.8455 LAYER met2  ;
    ANTENNAMODEL OXIDE1 ;
    ANTENNAGATEAREA 0.126 LAYER met2  ;
    ANTENNAMAXAREACAR 57.8859 LAYER met2  ;
    ANTENNAMAXSIDEAREACAR 262.405 LAYER met2  ;
    ANTENNAMAXCUTCAR 0.407937 LAYER via2  ;
    PORT
      LAYER met2 ;
        RECT 563.200000 0.000000 563.340000 0.485000 ;
    END
  END wbs_adr_i[29]
  PIN wbs_adr_i[28]
    DIRECTION INPUT ;
    USE SIGNAL ;
    ANTENNAPARTIALMETALAREA 5.3535 LAYER met2  ;
    ANTENNAPARTIALMETALSIDEAREA 26.6595 LAYER met2  ;
    ANTENNAMODEL OXIDE1 ;
    ANTENNAGATEAREA 0.126 LAYER met2  ;
    ANTENNAMAXAREACAR 71.1748 LAYER met2  ;
    ANTENNAMAXSIDEAREACAR 328.849 LAYER met2  ;
    ANTENNAMAXCUTCAR 0.407937 LAYER via2  ;
    PORT
      LAYER met2 ;
        RECT 545.720000 0.000000 545.860000 0.485000 ;
    END
  END wbs_adr_i[28]
  PIN wbs_adr_i[27]
    DIRECTION INPUT ;
    USE SIGNAL ;
    ANTENNAPARTIALMETALAREA 5.6335 LAYER met2  ;
    ANTENNAPARTIALMETALSIDEAREA 28.0595 LAYER met2  ;
    ANTENNAMODEL OXIDE1 ;
    ANTENNAGATEAREA 0.126 LAYER met2  ;
    ANTENNAMAXAREACAR 51.5343 LAYER met2  ;
    ANTENNAMAXSIDEAREACAR 231.183 LAYER met2  ;
    ANTENNAMAXCUTCAR 0.407937 LAYER via2  ;
    PORT
      LAYER met2 ;
        RECT 528.240000 0.000000 528.380000 0.485000 ;
    END
  END wbs_adr_i[27]
  PIN wbs_adr_i[26]
    DIRECTION INPUT ;
    USE SIGNAL ;
    ANTENNAPARTIALMETALAREA 5.0959 LAYER met2  ;
    ANTENNAPARTIALMETALSIDEAREA 25.3715 LAYER met2  ;
    ANTENNAMODEL OXIDE1 ;
    ANTENNAGATEAREA 0.126 LAYER met2  ;
    ANTENNAMAXAREACAR 50.2192 LAYER met2  ;
    ANTENNAMAXSIDEAREACAR 224.071 LAYER met2  ;
    ANTENNAMAXCUTCAR 0.407937 LAYER via2  ;
    PORT
      LAYER met2 ;
        RECT 510.760000 0.000000 510.900000 0.485000 ;
    END
  END wbs_adr_i[26]
  PIN wbs_adr_i[25]
    DIRECTION INPUT ;
    USE SIGNAL ;
    ANTENNAPARTIALMETALAREA 6.8816 LAYER met2  ;
    ANTENNAPARTIALMETALSIDEAREA 34.3 LAYER met2  ;
    ANTENNAMODEL OXIDE1 ;
    ANTENNAGATEAREA 0.126 LAYER met2  ;
    ANTENNAMAXAREACAR 72.1748 LAYER met2  ;
    ANTENNAMAXSIDEAREACAR 333.849 LAYER met2  ;
    ANTENNAMAXCUTCAR 0.407937 LAYER via2  ;
    PORT
      LAYER met2 ;
        RECT 493.280000 0.000000 493.420000 0.485000 ;
    END
  END wbs_adr_i[25]
  PIN wbs_adr_i[24]
    DIRECTION INPUT ;
    USE SIGNAL ;
    ANTENNAPARTIALMETALAREA 6.3599 LAYER met2  ;
    ANTENNAPARTIALMETALSIDEAREA 31.5735 LAYER met2  ;
    ANTENNAMODEL OXIDE1 ;
    ANTENNAGATEAREA 0.126 LAYER met2  ;
    ANTENNAMAXAREACAR 80.4288 LAYER met2  ;
    ANTENNAMAXSIDEAREACAR 374.183 LAYER met2  ;
    ANTENNAMAXCUTCAR 0.407937 LAYER via2  ;
    PORT
      LAYER met2 ;
        RECT 475.800000 0.000000 475.940000 0.485000 ;
    END
  END wbs_adr_i[24]
  PIN wbs_adr_i[23]
    DIRECTION INPUT ;
    USE SIGNAL ;
    ANTENNAPARTIALMETALAREA 5.9667 LAYER met2  ;
    ANTENNAPARTIALMETALSIDEAREA 29.7255 LAYER met2  ;
    ANTENNAMODEL OXIDE1 ;
    ANTENNAGATEAREA 0.126 LAYER met2  ;
    ANTENNAMAXAREACAR 104.164 LAYER met2  ;
    ANTENNAMAXSIDEAREACAR 493.794 LAYER met2  ;
    ANTENNAMAXCUTCAR 0.407937 LAYER via2  ;
    PORT
      LAYER met2 ;
        RECT 458.780000 0.000000 458.920000 0.485000 ;
    END
  END wbs_adr_i[23]
  PIN wbs_adr_i[22]
    DIRECTION INPUT ;
    USE SIGNAL ;
    ANTENNAPARTIALMETALAREA 5.3001 LAYER met2  ;
    ANTENNAPARTIALMETALSIDEAREA 26.2745 LAYER met2  ;
    ANTENNAMODEL OXIDE1 ;
    ANTENNAGATEAREA 0.126 LAYER met2  ;
    ANTENNAMAXAREACAR 48.8883 LAYER met2  ;
    ANTENNAMAXSIDEAREACAR 217.016 LAYER met2  ;
    ANTENNAMAXCUTCAR 0.407937 LAYER via2  ;
    PORT
      LAYER met2 ;
        RECT 441.300000 0.000000 441.440000 0.485000 ;
    END
  END wbs_adr_i[22]
  PIN wbs_adr_i[21]
    DIRECTION INPUT ;
    USE SIGNAL ;
    ANTENNAPARTIALMETALAREA 5.2527 LAYER met2  ;
    ANTENNAPARTIALMETALSIDEAREA 26.1555 LAYER met2  ;
    ANTENNAMODEL OXIDE1 ;
    ANTENNAGATEAREA 0.126 LAYER met2  ;
    ANTENNAMAXAREACAR 121.897 LAYER met2  ;
    ANTENNAMAXSIDEAREACAR 582.46 LAYER met2  ;
    ANTENNAMAXCUTCAR 0.407937 LAYER via2  ;
    PORT
      LAYER met2 ;
        RECT 423.820000 0.000000 423.960000 0.485000 ;
    END
  END wbs_adr_i[21]
  PIN wbs_adr_i[20]
    DIRECTION INPUT ;
    USE SIGNAL ;
    ANTENNAPARTIALMETALAREA 5.8839 LAYER met2  ;
    ANTENNAPARTIALMETALSIDEAREA 29.1935 LAYER met2  ;
    ANTENNAMODEL OXIDE1 ;
    ANTENNAGATEAREA 0.126 LAYER met2  ;
    ANTENNAMAXAREACAR 53.5216 LAYER met2  ;
    ANTENNAMAXSIDEAREACAR 240.183 LAYER met2  ;
    ANTENNAMAXCUTCAR 0.407937 LAYER via2  ;
    PORT
      LAYER met2 ;
        RECT 406.340000 0.000000 406.480000 0.485000 ;
    END
  END wbs_adr_i[20]
  PIN wbs_adr_i[19]
    DIRECTION INPUT ;
    USE SIGNAL ;
    ANTENNAPARTIALMETALAREA 8.0399 LAYER met2  ;
    ANTENNAPARTIALMETALSIDEAREA 39.9735 LAYER met2  ;
    ANTENNAMODEL OXIDE1 ;
    ANTENNAGATEAREA 0.126 LAYER met2  ;
    ANTENNAMAXAREACAR 82.5177 LAYER met2  ;
    ANTENNAMAXSIDEAREACAR 384.627 LAYER met2  ;
    ANTENNAMAXCUTCAR 0.407937 LAYER via2  ;
    PORT
      LAYER met2 ;
        RECT 388.860000 0.000000 389.000000 0.485000 ;
    END
  END wbs_adr_i[19]
  PIN wbs_adr_i[18]
    DIRECTION INPUT ;
    USE SIGNAL ;
    ANTENNAPARTIALMETALAREA 8.2595 LAYER met2  ;
    ANTENNAPARTIALMETALSIDEAREA 40.9535 LAYER met2  ;
    ANTENNAMODEL OXIDE1 ;
    ANTENNAGATEAREA 0.126 LAYER met2  ;
    ANTENNAMAXAREACAR 77.3716 LAYER met2  ;
    ANTENNAMAXSIDEAREACAR 357.96 LAYER met2  ;
    ANTENNAMAXCUTCAR 0.407937 LAYER via2  ;
    PORT
      LAYER met2 ;
        RECT 371.380000 0.000000 371.520000 0.485000 ;
    END
  END wbs_adr_i[18]
  PIN wbs_adr_i[17]
    DIRECTION INPUT ;
    USE SIGNAL ;
    ANTENNAPARTIALMETALAREA 9.9881 LAYER met2  ;
    ANTENNAPARTIALMETALSIDEAREA 49.6615 LAYER met2  ;
    ANTENNAPARTIALCUTAREA 0.04 LAYER via2  ;
    ANTENNAPARTIALMETALAREA 3.8448 LAYER met3  ;
    ANTENNAPARTIALMETALSIDEAREA 20.976 LAYER met3  ;
    ANTENNAMODEL OXIDE1 ;
    ANTENNAGATEAREA 0.126 LAYER met3  ;
    ANTENNAMAXAREACAR 46.8335 LAYER met3  ;
    ANTENNAMAXSIDEAREACAR 220.548 LAYER met3  ;
    ANTENNAMAXCUTCAR 0.725397 LAYER via3  ;
    PORT
      LAYER met2 ;
        RECT 354.360000 0.000000 354.500000 0.485000 ;
    END
  END wbs_adr_i[17]
  PIN wbs_adr_i[16]
    DIRECTION INPUT ;
    USE SIGNAL ;
    ANTENNAPARTIALMETALAREA 8.6587 LAYER met2  ;
    ANTENNAPARTIALMETALSIDEAREA 43.0675 LAYER met2  ;
    ANTENNAMODEL OXIDE1 ;
    ANTENNAGATEAREA 0.126 LAYER met2  ;
    ANTENNAMAXAREACAR 87.4288 LAYER met2  ;
    ANTENNAMAXSIDEAREACAR 409.183 LAYER met2  ;
    ANTENNAMAXCUTCAR 0.407937 LAYER via2  ;
    PORT
      LAYER met2 ;
        RECT 336.880000 0.000000 337.020000 0.485000 ;
    END
  END wbs_adr_i[16]
  PIN wbs_adr_i[15]
    DIRECTION INPUT ;
    USE SIGNAL ;
    ANTENNAPARTIALMETALAREA 9.0211 LAYER met2  ;
    ANTENNAPARTIALMETALSIDEAREA 44.7615 LAYER met2  ;
    ANTENNAMODEL OXIDE1 ;
    ANTENNAGATEAREA 0.126 LAYER met2  ;
    ANTENNAMAXAREACAR 80.3494 LAYER met2  ;
    ANTENNAMAXSIDEAREACAR 372.849 LAYER met2  ;
    ANTENNAMAXCUTCAR 0.407937 LAYER via2  ;
    PORT
      LAYER met2 ;
        RECT 319.400000 0.000000 319.540000 0.485000 ;
    END
  END wbs_adr_i[15]
  PIN wbs_adr_i[14]
    DIRECTION INPUT ;
    USE SIGNAL ;
    ANTENNAPARTIALMETALAREA 7.7896 LAYER met2  ;
    ANTENNAPARTIALMETALSIDEAREA 38.787 LAYER met2  ;
    ANTENNAPARTIALCUTAREA 0.04 LAYER via2  ;
    ANTENNAPARTIALMETALAREA 0.2509 LAYER met3  ;
    ANTENNAPARTIALMETALSIDEAREA 1.808 LAYER met3  ;
    ANTENNAPARTIALCUTAREA 0.04 LAYER via3  ;
    ANTENNAPARTIALMETALAREA 4.1448 LAYER met4  ;
    ANTENNAPARTIALMETALSIDEAREA 22.576 LAYER met4  ;
    ANTENNAMODEL OXIDE1 ;
    ANTENNAGATEAREA 0.126 LAYER met4  ;
    ANTENNAMAXAREACAR 90.1486 LAYER met4  ;
    ANTENNAMAXSIDEAREACAR 441.373 LAYER met4  ;
    ANTENNAMAXCUTCAR 1.04286 LAYER via4  ;
    PORT
      LAYER met2 ;
        RECT 301.920000 0.000000 302.060000 0.485000 ;
    END
  END wbs_adr_i[14]
  PIN wbs_adr_i[13]
    DIRECTION INPUT ;
    USE SIGNAL ;
    ANTENNAPARTIALMETALAREA 6.8791 LAYER met2  ;
    ANTENNAPARTIALMETALSIDEAREA 34.0515 LAYER met2  ;
    ANTENNAMODEL OXIDE1 ;
    ANTENNAGATEAREA 0.126 LAYER met2  ;
    ANTENNAMAXAREACAR 63.3494 LAYER met2  ;
    ANTENNAMAXSIDEAREACAR 287.849 LAYER met2  ;
    ANTENNAMAXCUTCAR 0.407937 LAYER via2  ;
    PORT
      LAYER met2 ;
        RECT 284.440000 0.000000 284.580000 0.485000 ;
    END
  END wbs_adr_i[13]
  PIN wbs_adr_i[12]
    DIRECTION INPUT ;
    USE SIGNAL ;
    ANTENNAPARTIALMETALAREA 6.8023 LAYER met2  ;
    ANTENNAPARTIALMETALSIDEAREA 33.7855 LAYER met2  ;
    ANTENNAMODEL OXIDE1 ;
    ANTENNAGATEAREA 0.126 LAYER met2  ;
    ANTENNAMAXAREACAR 96.3232 LAYER met2  ;
    ANTENNAMAXSIDEAREACAR 453.655 LAYER met2  ;
    ANTENNAMAXCUTCAR 0.407937 LAYER via2  ;
    PORT
      LAYER met2 ;
        RECT 266.960000 0.000000 267.100000 0.485000 ;
    END
  END wbs_adr_i[12]
  PIN wbs_adr_i[11]
    DIRECTION INPUT ;
    USE SIGNAL ;
    ANTENNAPARTIALMETALAREA 8.729 LAYER met2  ;
    ANTENNAPARTIALMETALSIDEAREA 43.484 LAYER met2  ;
    ANTENNAPARTIALCUTAREA 0.04 LAYER via2  ;
    ANTENNAPARTIALMETALAREA 0.255 LAYER met3  ;
    ANTENNAPARTIALMETALSIDEAREA 1.808 LAYER met3  ;
    ANTENNAPARTIALCUTAREA 0.04 LAYER via3  ;
    ANTENNAPARTIALMETALAREA 4.1448 LAYER met4  ;
    ANTENNAPARTIALMETALSIDEAREA 22.576 LAYER met4  ;
    ANTENNAMODEL OXIDE1 ;
    ANTENNAGATEAREA 0.126 LAYER met4  ;
    ANTENNAMAXAREACAR 63.8018 LAYER met4  ;
    ANTENNAMAXSIDEAREACAR 308.54 LAYER met4  ;
    ANTENNAMAXCUTCAR 1.04286 LAYER via4  ;
    PORT
      LAYER met2 ;
        RECT 249.940000 0.000000 250.080000 0.485000 ;
    END
  END wbs_adr_i[11]
  PIN wbs_adr_i[10]
    DIRECTION INPUT ;
    USE SIGNAL ;
    ANTENNADIFFAREA 0.4347 LAYER met2  ;
    ANTENNAPARTIALMETALAREA 11.0321 LAYER met2  ;
    ANTENNAPARTIALMETALSIDEAREA 54.7085 LAYER met2  ;
    ANTENNAMODEL OXIDE1 ;
    ANTENNAGATEAREA 0.126 LAYER met2  ;
    ANTENNAMAXAREACAR 99.3764 LAYER met2  ;
    ANTENNAMAXSIDEAREACAR 467.127 LAYER met2  ;
    ANTENNAMAXCUTCAR 0.407937 LAYER via2  ;
    PORT
      LAYER met2 ;
        RECT 232.460000 0.000000 232.600000 0.485000 ;
    END
  END wbs_adr_i[10]
  PIN wbs_adr_i[9]
    DIRECTION INPUT ;
    USE SIGNAL ;
    ANTENNAPARTIALMETALAREA 9.0997 LAYER met2  ;
    ANTENNAPARTIALMETALSIDEAREA 45.2725 LAYER met2  ;
    ANTENNAMODEL OXIDE1 ;
    ANTENNAGATEAREA 0.126 LAYER met2  ;
    ANTENNAMAXAREACAR 79.4399 LAYER met2  ;
    ANTENNAMAXSIDEAREACAR 369.238 LAYER met2  ;
    ANTENNAMAXCUTCAR 0.407937 LAYER via2  ;
    PORT
      LAYER met2 ;
        RECT 214.980000 0.000000 215.120000 0.485000 ;
    END
  END wbs_adr_i[9]
  PIN wbs_adr_i[8]
    DIRECTION INPUT ;
    USE SIGNAL ;
    ANTENNAPARTIALMETALAREA 7.7896 LAYER met2  ;
    ANTENNAPARTIALMETALSIDEAREA 38.787 LAYER met2  ;
    ANTENNAPARTIALCUTAREA 0.04 LAYER via2  ;
    ANTENNAPARTIALMETALAREA 0.255 LAYER met3  ;
    ANTENNAPARTIALMETALSIDEAREA 1.808 LAYER met3  ;
    ANTENNAPARTIALCUTAREA 0.04 LAYER via3  ;
    ANTENNAPARTIALMETALAREA 4.1448 LAYER met4  ;
    ANTENNAPARTIALMETALSIDEAREA 22.576 LAYER met4  ;
    ANTENNAMODEL OXIDE1 ;
    ANTENNAGATEAREA 0.126 LAYER met4  ;
    ANTENNAMAXAREACAR 77.4923 LAYER met4  ;
    ANTENNAMAXSIDEAREACAR 377.929 LAYER met4  ;
    ANTENNAMAXCUTCAR 1.04286 LAYER via4  ;
    PORT
      LAYER met2 ;
        RECT 197.500000 0.000000 197.640000 0.485000 ;
    END
  END wbs_adr_i[8]
  PIN wbs_adr_i[7]
    DIRECTION INPUT ;
    USE SIGNAL ;
    ANTENNAPARTIALMETALAREA 9.5631 LAYER met2  ;
    ANTENNAPARTIALMETALSIDEAREA 47.5895 LAYER met2  ;
    ANTENNAMODEL OXIDE1 ;
    ANTENNAGATEAREA 0.126 LAYER met2  ;
    ANTENNAMAXAREACAR 86.1843 LAYER met2  ;
    ANTENNAMAXSIDEAREACAR 402.96 LAYER met2  ;
    ANTENNAMAXCUTCAR 0.407937 LAYER via2  ;
    PORT
      LAYER met2 ;
        RECT 180.020000 0.000000 180.160000 0.485000 ;
    END
  END wbs_adr_i[7]
  PIN wbs_adr_i[6]
    DIRECTION INPUT ;
    USE SIGNAL ;
    ANTENNAPARTIALMETALAREA 7.1342 LAYER met2  ;
    ANTENNAPARTIALMETALSIDEAREA 35.392 LAYER met2  ;
    ANTENNAPARTIALCUTAREA 0.04 LAYER via2  ;
    ANTENNAPARTIALMETALAREA 0.255 LAYER met3  ;
    ANTENNAPARTIALMETALSIDEAREA 1.808 LAYER met3  ;
    ANTENNAPARTIALCUTAREA 0.04 LAYER via3  ;
    ANTENNAPARTIALMETALAREA 6.1578 LAYER met4  ;
    ANTENNAPARTIALMETALSIDEAREA 33.312 LAYER met4  ;
    ANTENNAMODEL OXIDE1 ;
    ANTENNAGATEAREA 0.126 LAYER met4  ;
    ANTENNAMAXAREACAR 75.0812 LAYER met4  ;
    ANTENNAMAXSIDEAREACAR 372.135 LAYER met4  ;
    ANTENNAMAXCUTCAR 1.04286 LAYER via4  ;
    PORT
      LAYER met2 ;
        RECT 163.000000 0.000000 163.140000 0.485000 ;
    END
  END wbs_adr_i[6]
  PIN wbs_adr_i[5]
    DIRECTION INPUT ;
    USE SIGNAL ;
    ANTENNAPARTIALMETALAREA 7.9616 LAYER met2  ;
    ANTENNAPARTIALMETALSIDEAREA 39.529 LAYER met2  ;
    ANTENNAPARTIALCUTAREA 0.04 LAYER via2  ;
    ANTENNAPARTIALMETALAREA 0.255 LAYER met3  ;
    ANTENNAPARTIALMETALSIDEAREA 1.808 LAYER met3  ;
    ANTENNAPARTIALCUTAREA 0.04 LAYER via3  ;
    ANTENNAPARTIALMETALAREA 1.9488 LAYER met4  ;
    ANTENNAPARTIALMETALSIDEAREA 10.864 LAYER met4  ;
    ANTENNAMODEL OXIDE1 ;
    ANTENNAGATEAREA 0.126 LAYER met4  ;
    ANTENNAMAXAREACAR 38.9875 LAYER met4  ;
    ANTENNAMAXSIDEAREACAR 180.532 LAYER met4  ;
    ANTENNAMAXCUTCAR 1.04286 LAYER via4  ;
    PORT
      LAYER met2 ;
        RECT 145.520000 0.000000 145.660000 0.485000 ;
    END
  END wbs_adr_i[5]
  PIN wbs_adr_i[4]
    DIRECTION INPUT ;
    USE SIGNAL ;
    ANTENNAPARTIALMETALAREA 6.2381 LAYER met2  ;
    ANTENNAPARTIALMETALSIDEAREA 30.9645 LAYER met2  ;
    ANTENNAMODEL OXIDE1 ;
    ANTENNAGATEAREA 0.126 LAYER met2  ;
    ANTENNAMAXAREACAR 99.8843 LAYER met2  ;
    ANTENNAMAXSIDEAREACAR 471.46 LAYER met2  ;
    ANTENNAMAXCUTCAR 0.407937 LAYER via2  ;
    PORT
      LAYER met2 ;
        RECT 128.040000 0.000000 128.180000 0.485000 ;
    END
  END wbs_adr_i[4]
  PIN wbs_adr_i[3]
    DIRECTION INPUT ;
    USE SIGNAL ;
    ANTENNAPARTIALMETALAREA 10.1498 LAYER met2  ;
    ANTENNAPARTIALMETALSIDEAREA 50.47 LAYER met2  ;
    ANTENNAPARTIALCUTAREA 0.04 LAYER via2  ;
    ANTENNAPARTIALMETALAREA 0.255 LAYER met3  ;
    ANTENNAPARTIALMETALSIDEAREA 1.808 LAYER met3  ;
    ANTENNAPARTIALCUTAREA 0.04 LAYER via3  ;
    ANTENNAPARTIALMETALAREA 1.7658 LAYER met4  ;
    ANTENNAPARTIALMETALSIDEAREA 9.888 LAYER met4  ;
    ANTENNAMODEL OXIDE1 ;
    ANTENNAGATEAREA 0.126 LAYER met4  ;
    ANTENNAMAXAREACAR 25.3573 LAYER met4  ;
    ANTENNAMAXSIDEAREACAR 111.897 LAYER met4  ;
    ANTENNAMAXCUTCAR 1.04286 LAYER via4  ;
    PORT
      LAYER met2 ;
        RECT 104.580000 0.000000 104.720000 0.485000 ;
    END
  END wbs_adr_i[3]
  PIN wbs_adr_i[2]
    DIRECTION INPUT ;
    USE SIGNAL ;
    ANTENNAPARTIALMETALAREA 8.8183 LAYER met2  ;
    ANTENNAPARTIALMETALSIDEAREA 43.8655 LAYER met2  ;
    ANTENNAMODEL OXIDE1 ;
    ANTENNAGATEAREA 0.126 LAYER met2  ;
    ANTENNAMAXAREACAR 77.2066 LAYER met2  ;
    ANTENNAMAXSIDEAREACAR 358.071 LAYER met2  ;
    ANTENNAMAXCUTCAR 0.407937 LAYER via2  ;
    PORT
      LAYER met2 ;
        RECT 81.580000 0.000000 81.720000 0.485000 ;
    END
  END wbs_adr_i[2]
  PIN wbs_adr_i[1]
    DIRECTION INPUT ;
    USE SIGNAL ;
    ANTENNAPARTIALMETALAREA 5.8026 LAYER met2  ;
    ANTENNAPARTIALMETALSIDEAREA 28.833 LAYER met2  ;
    ANTENNAPARTIALCUTAREA 0.04 LAYER via2  ;
    ANTENNAPARTIALMETALAREA 3.9828 LAYER met3  ;
    ANTENNAPARTIALMETALSIDEAREA 21.712 LAYER met3  ;
    ANTENNAMODEL OXIDE1 ;
    ANTENNAGATEAREA 0.126 LAYER met3  ;
    ANTENNAMAXAREACAR 41.3272 LAYER met3  ;
    ANTENNAMAXSIDEAREACAR 194.167 LAYER met3  ;
    ANTENNAMAXCUTCAR 0.725397 LAYER via3  ;
    PORT
      LAYER met2 ;
        RECT 58.580000 0.000000 58.720000 0.485000 ;
    END
  END wbs_adr_i[1]
  PIN wbs_adr_i[0]
    DIRECTION INPUT ;
    USE SIGNAL ;
    ANTENNAPARTIALMETALAREA 7.6575 LAYER met2  ;
    ANTENNAPARTIALMETALSIDEAREA 37.9435 LAYER met2  ;
    ANTENNAMODEL OXIDE1 ;
    ANTENNAGATEAREA 0.126 LAYER met2  ;
    ANTENNAMAXAREACAR 69.5272 LAYER met2  ;
    ANTENNAMAXSIDEAREACAR 318.738 LAYER met2  ;
    ANTENNAMAXCUTCAR 0.407937 LAYER via2  ;
    PORT
      LAYER met2 ;
        RECT 35.120000 0.000000 35.260000 0.485000 ;
    END
  END wbs_adr_i[0]
  PIN wbs_ack_o
    DIRECTION OUTPUT ;
    USE SIGNAL ;
    ANTENNADIFFAREA 0.4455 LAYER met2  ;
    ANTENNAPARTIALMETALAREA 13.0325 LAYER met2  ;
    ANTENNAPARTIALMETALSIDEAREA 65.0545 LAYER met2  ;
    PORT
      LAYER met2 ;
        RECT 12.120000 0.000000 12.260000 0.485000 ;
    END
  END wbs_ack_o
  PIN wbs_dat_o[31]
    DIRECTION OUTPUT ;
    USE SIGNAL ;
    ANTENNADIFFAREA 0.4455 LAYER met2  ;
    ANTENNAPARTIALMETALAREA 25.8159 LAYER met2  ;
    ANTENNAPARTIALMETALSIDEAREA 128.971 LAYER met2  ;
    PORT
      LAYER met2 ;
        RECT 609.200000 0.000000 609.340000 0.485000 ;
    END
  END wbs_dat_o[31]
  PIN wbs_dat_o[30]
    DIRECTION OUTPUT ;
    USE SIGNAL ;
    ANTENNADIFFAREA 0.4455 LAYER met2  ;
    ANTENNAPARTIALMETALAREA 27.0395 LAYER met2  ;
    ANTENNAPARTIALMETALSIDEAREA 135.09 LAYER met2  ;
    PORT
      LAYER met2 ;
        RECT 592.180000 0.000000 592.320000 0.485000 ;
    END
  END wbs_dat_o[30]
  PIN wbs_dat_o[29]
    DIRECTION OUTPUT ;
    USE SIGNAL ;
    ANTENNADIFFAREA 0.4455 LAYER met2  ;
    ANTENNAPARTIALMETALAREA 27.9227 LAYER met2  ;
    ANTENNAPARTIALMETALSIDEAREA 139.387 LAYER met2  ;
    PORT
      LAYER met2 ;
        RECT 574.700000 0.000000 574.840000 0.485000 ;
    END
  END wbs_dat_o[29]
  PIN wbs_dat_o[28]
    DIRECTION OUTPUT ;
    USE SIGNAL ;
    ANTENNADIFFAREA 0.4455 LAYER met2  ;
    ANTENNAPARTIALMETALAREA 26.6039 LAYER met2  ;
    ANTENNAPARTIALMETALSIDEAREA 132.794 LAYER met2  ;
    PORT
      LAYER met2 ;
        RECT 557.220000 0.000000 557.360000 0.485000 ;
    END
  END wbs_dat_o[28]
  PIN wbs_dat_o[27]
    DIRECTION OUTPUT ;
    USE SIGNAL ;
    ANTENNADIFFAREA 0.4455 LAYER met2  ;
    ANTENNAPARTIALMETALAREA 27.6987 LAYER met2  ;
    ANTENNAPARTIALMETALSIDEAREA 138.268 LAYER met2  ;
    PORT
      LAYER met2 ;
        RECT 539.740000 0.000000 539.880000 0.485000 ;
    END
  END wbs_dat_o[27]
  PIN wbs_dat_o[26]
    DIRECTION OUTPUT ;
    USE SIGNAL ;
    ANTENNADIFFAREA 0.4455 LAYER met2  ;
    ANTENNAPARTIALMETALAREA 29.581 LAYER met2  ;
    ANTENNAPARTIALMETALSIDEAREA 147.679 LAYER met2  ;
    PORT
      LAYER met2 ;
        RECT 522.260000 0.000000 522.400000 0.485000 ;
    END
  END wbs_dat_o[26]
  PIN wbs_dat_o[25]
    DIRECTION OUTPUT ;
    USE SIGNAL ;
    ANTENNADIFFAREA 0.4455 LAYER met2  ;
    ANTENNAPARTIALMETALAREA 26.7287 LAYER met2  ;
    ANTENNAPARTIALMETALSIDEAREA 133.536 LAYER met2  ;
    PORT
      LAYER met2 ;
        RECT 504.780000 0.000000 504.920000 0.485000 ;
    END
  END wbs_dat_o[25]
  PIN wbs_dat_o[24]
    DIRECTION OUTPUT ;
    USE SIGNAL ;
    ANTENNADIFFAREA 0.4455 LAYER met2  ;
    ANTENNAPARTIALMETALAREA 26.8659 LAYER met2  ;
    ANTENNAPARTIALMETALSIDEAREA 134.221 LAYER met2  ;
    PORT
      LAYER met2 ;
        RECT 487.760000 0.000000 487.900000 0.485000 ;
    END
  END wbs_dat_o[24]
  PIN wbs_dat_o[23]
    DIRECTION OUTPUT ;
    USE SIGNAL ;
    ANTENNADIFFAREA 0.4455 LAYER met2  ;
    ANTENNAPARTIALMETALAREA 26.6251 LAYER met2  ;
    ANTENNAPARTIALMETALSIDEAREA 133.018 LAYER met2  ;
    PORT
      LAYER met2 ;
        RECT 470.280000 0.000000 470.420000 0.485000 ;
    END
  END wbs_dat_o[23]
  PIN wbs_dat_o[22]
    DIRECTION OUTPUT ;
    USE SIGNAL ;
    ANTENNAPARTIALMETALAREA 0.3591 LAYER met2  ;
    ANTENNAPARTIALMETALSIDEAREA 1.6345 LAYER met2  ;
    ANTENNAPARTIALCUTAREA 0.04 LAYER via2  ;
    ANTENNADIFFAREA 0.4455 LAYER met3  ;
    ANTENNAPARTIALMETALAREA 27.8828 LAYER met3  ;
    ANTENNAPARTIALMETALSIDEAREA 149.16 LAYER met3  ;
    PORT
      LAYER met2 ;
        RECT 452.800000 0.000000 452.940000 0.485000 ;
    END
  END wbs_dat_o[22]
  PIN wbs_dat_o[21]
    DIRECTION OUTPUT ;
    USE SIGNAL ;
    ANTENNADIFFAREA 0.4455 LAYER met2  ;
    ANTENNAPARTIALMETALAREA 28.5291 LAYER met2  ;
    ANTENNAPARTIALMETALSIDEAREA 142.538 LAYER met2  ;
    PORT
      LAYER met2 ;
        RECT 435.320000 0.000000 435.460000 0.485000 ;
    END
  END wbs_dat_o[21]
  PIN wbs_dat_o[20]
    DIRECTION OUTPUT ;
    USE SIGNAL ;
    ANTENNAPARTIALMETALAREA 0.5306 LAYER met2  ;
    ANTENNAPARTIALMETALSIDEAREA 2.492 LAYER met2  ;
    ANTENNAPARTIALCUTAREA 0.04 LAYER via2  ;
    ANTENNADIFFAREA 0.4455 LAYER met3  ;
    ANTENNAPARTIALMETALAREA 28.8228 LAYER met3  ;
    ANTENNAPARTIALMETALSIDEAREA 154.192 LAYER met3  ;
    PORT
      LAYER met2 ;
        RECT 417.840000 0.000000 417.980000 0.485000 ;
    END
  END wbs_dat_o[20]
  PIN wbs_dat_o[19]
    DIRECTION OUTPUT ;
    USE SIGNAL ;
    ANTENNAPARTIALMETALAREA 0.8722 LAYER met2  ;
    ANTENNAPARTIALMETALSIDEAREA 4.2 LAYER met2  ;
    ANTENNAPARTIALCUTAREA 0.04 LAYER via2  ;
    ANTENNADIFFAREA 0.4455 LAYER met3  ;
    ANTENNAPARTIALMETALAREA 35.7228 LAYER met3  ;
    ANTENNAPARTIALMETALSIDEAREA 190.992 LAYER met3  ;
    PORT
      LAYER met2 ;
        RECT 400.360000 0.000000 400.500000 0.485000 ;
    END
  END wbs_dat_o[19]
  PIN wbs_dat_o[18]
    DIRECTION OUTPUT ;
    USE SIGNAL ;
    ANTENNAPARTIALMETALAREA 0.1099 LAYER met2  ;
    ANTENNAPARTIALMETALSIDEAREA 0.3885 LAYER met2  ;
    ANTENNAPARTIALCUTAREA 0.04 LAYER via2  ;
    ANTENNADIFFAREA 0.4455 LAYER met3  ;
    ANTENNAPARTIALMETALAREA 97.8228 LAYER met3  ;
    ANTENNAPARTIALMETALSIDEAREA 522.192 LAYER met3  ;
    PORT
      LAYER met2 ;
        RECT 383.340000 0.000000 383.480000 0.485000 ;
    END
  END wbs_dat_o[18]
  PIN wbs_dat_o[17]
    DIRECTION OUTPUT ;
    USE SIGNAL ;
    ANTENNAPARTIALMETALAREA 1.9824 LAYER met2  ;
    ANTENNAPARTIALMETALSIDEAREA 9.751 LAYER met2  ;
    ANTENNAPARTIALCUTAREA 0.04 LAYER via2  ;
    ANTENNADIFFAREA 0.4455 LAYER met3  ;
    ANTENNAPARTIALMETALAREA 103.154 LAYER met3  ;
    ANTENNAPARTIALMETALSIDEAREA 550.624 LAYER met3  ;
    PORT
      LAYER met2 ;
        RECT 365.860000 0.000000 366.000000 0.485000 ;
    END
  END wbs_dat_o[17]
  PIN wbs_dat_o[16]
    DIRECTION OUTPUT ;
    USE SIGNAL ;
    ANTENNAPARTIALMETALAREA 1.043 LAYER met2  ;
    ANTENNAPARTIALMETALSIDEAREA 5.054 LAYER met2  ;
    ANTENNAPARTIALCUTAREA 0.04 LAYER via2  ;
    ANTENNADIFFAREA 0.4455 LAYER met3  ;
    ANTENNAPARTIALMETALAREA 98.5128 LAYER met3  ;
    ANTENNAPARTIALMETALSIDEAREA 525.872 LAYER met3  ;
    PORT
      LAYER met2 ;
        RECT 348.380000 0.000000 348.520000 0.485000 ;
    END
  END wbs_dat_o[16]
  PIN wbs_dat_o[15]
    DIRECTION OUTPUT ;
    USE SIGNAL ;
    ANTENNAPARTIALMETALAREA 1.2992 LAYER met2  ;
    ANTENNAPARTIALMETALSIDEAREA 6.335 LAYER met2  ;
    ANTENNAPARTIALCUTAREA 0.04 LAYER via2  ;
    ANTENNADIFFAREA 0.4455 LAYER met3  ;
    ANTENNAPARTIALMETALAREA 100.673 LAYER met3  ;
    ANTENNAPARTIALMETALSIDEAREA 537.392 LAYER met3  ;
    PORT
      LAYER met2 ;
        RECT 330.900000 0.000000 331.040000 0.485000 ;
    END
  END wbs_dat_o[15]
  PIN wbs_dat_o[14]
    DIRECTION OUTPUT ;
    USE SIGNAL ;
    ANTENNAPARTIALMETALAREA 1.6408 LAYER met2  ;
    ANTENNAPARTIALMETALSIDEAREA 8.043 LAYER met2  ;
    ANTENNAPARTIALCUTAREA 0.04 LAYER via2  ;
    ANTENNADIFFAREA 0.4455 LAYER met3  ;
    ANTENNAPARTIALMETALAREA 120.131 LAYER met3  ;
    ANTENNAPARTIALMETALSIDEAREA 641.168 LAYER met3  ;
    PORT
      LAYER met2 ;
        RECT 313.420000 0.000000 313.560000 0.485000 ;
    END
  END wbs_dat_o[14]
  PIN wbs_dat_o[13]
    DIRECTION OUTPUT ;
    USE SIGNAL ;
    ANTENNADIFFAREA 0.4455 LAYER met2  ;
    ANTENNAPARTIALMETALAREA 28.7935 LAYER met2  ;
    ANTENNAPARTIALMETALSIDEAREA 143.742 LAYER met2  ;
    PORT
      LAYER met2 ;
        RECT 296.400000 0.000000 296.540000 0.485000 ;
    END
  END wbs_dat_o[13]
  PIN wbs_dat_o[12]
    DIRECTION OUTPUT ;
    USE SIGNAL ;
    ANTENNADIFFAREA 0.4455 LAYER met2  ;
    ANTENNAPARTIALMETALAREA 26.1615 LAYER met2  ;
    ANTENNAPARTIALMETALSIDEAREA 130.581 LAYER met2  ;
    PORT
      LAYER met2 ;
        RECT 278.920000 0.000000 279.060000 0.485000 ;
    END
  END wbs_dat_o[12]
  PIN wbs_dat_o[11]
    DIRECTION OUTPUT ;
    USE SIGNAL ;
    ANTENNADIFFAREA 0.4455 LAYER met2  ;
    ANTENNAPARTIALMETALAREA 29.3339 LAYER met2  ;
    ANTENNAPARTIALMETALSIDEAREA 146.443 LAYER met2  ;
    PORT
      LAYER met2 ;
        RECT 261.440000 0.000000 261.580000 0.485000 ;
    END
  END wbs_dat_o[11]
  PIN wbs_dat_o[10]
    DIRECTION OUTPUT ;
    USE SIGNAL ;
    ANTENNADIFFAREA 0.4455 LAYER met2  ;
    ANTENNAPARTIALMETALAREA 28.2083 LAYER met2  ;
    ANTENNAPARTIALMETALSIDEAREA 140.816 LAYER met2  ;
    PORT
      LAYER met2 ;
        RECT 243.960000 0.000000 244.100000 0.485000 ;
    END
  END wbs_dat_o[10]
  PIN wbs_dat_o[9]
    DIRECTION OUTPUT ;
    USE SIGNAL ;
    ANTENNADIFFAREA 0.4455 LAYER met2  ;
    ANTENNAPARTIALMETALAREA 27.6035 LAYER met2  ;
    ANTENNAPARTIALMETALSIDEAREA 137.792 LAYER met2  ;
    PORT
      LAYER met2 ;
        RECT 226.480000 0.000000 226.620000 0.485000 ;
    END
  END wbs_dat_o[9]
  PIN wbs_dat_o[8]
    DIRECTION OUTPUT ;
    USE SIGNAL ;
    ANTENNADIFFAREA 0.4455 LAYER met2  ;
    ANTENNAPARTIALMETALAREA 28.1483 LAYER met2  ;
    ANTENNAPARTIALMETALSIDEAREA 140.633 LAYER met2  ;
    PORT
      LAYER met2 ;
        RECT 209.000000 0.000000 209.140000 0.485000 ;
    END
  END wbs_dat_o[8]
  PIN wbs_dat_o[7]
    DIRECTION OUTPUT ;
    USE SIGNAL ;
    ANTENNADIFFAREA 0.4455 LAYER met2  ;
    ANTENNAPARTIALMETALAREA 29.4195 LAYER met2  ;
    ANTENNAPARTIALMETALSIDEAREA 146.99 LAYER met2  ;
    PORT
      LAYER met2 ;
        RECT 191.980000 0.000000 192.120000 0.485000 ;
    END
  END wbs_dat_o[7]
  PIN wbs_dat_o[6]
    DIRECTION OUTPUT ;
    USE SIGNAL ;
    ANTENNADIFFAREA 0.4455 LAYER met2  ;
    ANTENNAPARTIALMETALAREA 26.5087 LAYER met2  ;
    ANTENNAPARTIALMETALSIDEAREA 132.318 LAYER met2  ;
    PORT
      LAYER met2 ;
        RECT 174.500000 0.000000 174.640000 0.485000 ;
    END
  END wbs_dat_o[6]
  PIN wbs_dat_o[5]
    DIRECTION OUTPUT ;
    USE SIGNAL ;
    ANTENNADIFFAREA 0.3406 LAYER met2  ;
    ANTENNAPARTIALMETALAREA 23.2931 LAYER met2  ;
    ANTENNAPARTIALMETALSIDEAREA 116.358 LAYER met2  ;
    PORT
      LAYER met2 ;
        RECT 157.020000 0.000000 157.160000 0.485000 ;
    END
  END wbs_dat_o[5]
  PIN wbs_dat_o[4]
    DIRECTION OUTPUT ;
    USE SIGNAL ;
    ANTENNADIFFAREA 0.3406 LAYER met2  ;
    ANTENNAPARTIALMETALAREA 22.3411 LAYER met2  ;
    ANTENNAPARTIALMETALSIDEAREA 111.598 LAYER met2  ;
    PORT
      LAYER met2 ;
        RECT 139.540000 0.000000 139.680000 0.485000 ;
    END
  END wbs_dat_o[4]
  PIN wbs_dat_o[3]
    DIRECTION OUTPUT ;
    USE SIGNAL ;
    ANTENNADIFFAREA 0.3406 LAYER met2  ;
    ANTENNAPARTIALMETALAREA 27.0227 LAYER met2  ;
    ANTENNAPARTIALMETALSIDEAREA 135.006 LAYER met2  ;
    PORT
      LAYER met2 ;
        RECT 116.540000 0.000000 116.680000 0.485000 ;
    END
  END wbs_dat_o[3]
  PIN wbs_dat_o[2]
    DIRECTION OUTPUT ;
    USE SIGNAL ;
    ANTENNADIFFAREA 0.3406 LAYER met2  ;
    ANTENNAPARTIALMETALAREA 23.9119 LAYER met2  ;
    ANTENNAPARTIALMETALSIDEAREA 119.452 LAYER met2  ;
    PORT
      LAYER met2 ;
        RECT 93.080000 0.000000 93.220000 0.485000 ;
    END
  END wbs_dat_o[2]
  PIN wbs_dat_o[1]
    DIRECTION OUTPUT ;
    USE SIGNAL ;
    ANTENNADIFFAREA 0.3406 LAYER met2  ;
    ANTENNAPARTIALMETALAREA 23.0535 LAYER met2  ;
    ANTENNAPARTIALMETALSIDEAREA 115.042 LAYER met2  ;
    PORT
      LAYER met2 ;
        RECT 70.080000 0.000000 70.220000 0.485000 ;
    END
  END wbs_dat_o[1]
  PIN wbs_dat_o[0]
    DIRECTION OUTPUT ;
    USE SIGNAL ;
    ANTENNADIFFAREA 0.3406 LAYER met2  ;
    ANTENNAPARTIALMETALAREA 19.0355 LAYER met2  ;
    ANTENNAPARTIALMETALSIDEAREA 94.9515 LAYER met2  ;
    PORT
      LAYER met2 ;
        RECT 46.620000 0.000000 46.760000 0.485000 ;
    END
  END wbs_dat_o[0]
  PIN la_data_in[127]
    DIRECTION INPUT ;
    USE SIGNAL ;
    PORT
      LAYER met2 ;
        RECT 2825.020000 0.000000 2825.160000 0.485000 ;
    END
  END la_data_in[127]
  PIN la_data_in[126]
    DIRECTION INPUT ;
    USE SIGNAL ;
    PORT
      LAYER met2 ;
        RECT 2807.540000 0.000000 2807.680000 0.485000 ;
    END
  END la_data_in[126]
  PIN la_data_in[125]
    DIRECTION INPUT ;
    USE SIGNAL ;
    PORT
      LAYER met2 ;
        RECT 2790.060000 0.000000 2790.200000 0.485000 ;
    END
  END la_data_in[125]
  PIN la_data_in[124]
    DIRECTION INPUT ;
    USE SIGNAL ;
    PORT
      LAYER met2 ;
        RECT 2772.580000 0.000000 2772.720000 0.485000 ;
    END
  END la_data_in[124]
  PIN la_data_in[123]
    DIRECTION INPUT ;
    USE SIGNAL ;
    PORT
      LAYER met2 ;
        RECT 2755.560000 0.000000 2755.700000 0.485000 ;
    END
  END la_data_in[123]
  PIN la_data_in[122]
    DIRECTION INPUT ;
    USE SIGNAL ;
    PORT
      LAYER met2 ;
        RECT 2738.080000 0.000000 2738.220000 0.485000 ;
    END
  END la_data_in[122]
  PIN la_data_in[121]
    DIRECTION INPUT ;
    USE SIGNAL ;
    PORT
      LAYER met2 ;
        RECT 2720.600000 0.000000 2720.740000 0.485000 ;
    END
  END la_data_in[121]
  PIN la_data_in[120]
    DIRECTION INPUT ;
    USE SIGNAL ;
    PORT
      LAYER met2 ;
        RECT 2703.120000 0.000000 2703.260000 0.485000 ;
    END
  END la_data_in[120]
  PIN la_data_in[119]
    DIRECTION INPUT ;
    USE SIGNAL ;
    PORT
      LAYER met2 ;
        RECT 2685.640000 0.000000 2685.780000 0.485000 ;
    END
  END la_data_in[119]
  PIN la_data_in[118]
    DIRECTION INPUT ;
    USE SIGNAL ;
    PORT
      LAYER met2 ;
        RECT 2668.160000 0.000000 2668.300000 0.485000 ;
    END
  END la_data_in[118]
  PIN la_data_in[117]
    DIRECTION INPUT ;
    USE SIGNAL ;
    PORT
      LAYER met2 ;
        RECT 2651.140000 0.000000 2651.280000 0.485000 ;
    END
  END la_data_in[117]
  PIN la_data_in[116]
    DIRECTION INPUT ;
    USE SIGNAL ;
    PORT
      LAYER met2 ;
        RECT 2633.660000 0.000000 2633.800000 0.485000 ;
    END
  END la_data_in[116]
  PIN la_data_in[115]
    DIRECTION INPUT ;
    USE SIGNAL ;
    PORT
      LAYER met2 ;
        RECT 2616.180000 0.000000 2616.320000 0.485000 ;
    END
  END la_data_in[115]
  PIN la_data_in[114]
    DIRECTION INPUT ;
    USE SIGNAL ;
    PORT
      LAYER met2 ;
        RECT 2598.700000 0.000000 2598.840000 0.485000 ;
    END
  END la_data_in[114]
  PIN la_data_in[113]
    DIRECTION INPUT ;
    USE SIGNAL ;
    PORT
      LAYER met2 ;
        RECT 2581.220000 0.000000 2581.360000 0.485000 ;
    END
  END la_data_in[113]
  PIN la_data_in[112]
    DIRECTION INPUT ;
    USE SIGNAL ;
    PORT
      LAYER met2 ;
        RECT 2563.740000 0.000000 2563.880000 0.485000 ;
    END
  END la_data_in[112]
  PIN la_data_in[111]
    DIRECTION INPUT ;
    USE SIGNAL ;
    PORT
      LAYER met2 ;
        RECT 2546.720000 0.000000 2546.860000 0.485000 ;
    END
  END la_data_in[111]
  PIN la_data_in[110]
    DIRECTION INPUT ;
    USE SIGNAL ;
    PORT
      LAYER met2 ;
        RECT 2529.240000 0.000000 2529.380000 0.485000 ;
    END
  END la_data_in[110]
  PIN la_data_in[109]
    DIRECTION INPUT ;
    USE SIGNAL ;
    PORT
      LAYER met2 ;
        RECT 2511.760000 0.000000 2511.900000 0.485000 ;
    END
  END la_data_in[109]
  PIN la_data_in[108]
    DIRECTION INPUT ;
    USE SIGNAL ;
    PORT
      LAYER met2 ;
        RECT 2494.280000 0.000000 2494.420000 0.485000 ;
    END
  END la_data_in[108]
  PIN la_data_in[107]
    DIRECTION INPUT ;
    USE SIGNAL ;
    PORT
      LAYER met2 ;
        RECT 2476.800000 0.000000 2476.940000 0.485000 ;
    END
  END la_data_in[107]
  PIN la_data_in[106]
    DIRECTION INPUT ;
    USE SIGNAL ;
    PORT
      LAYER met2 ;
        RECT 2459.780000 0.000000 2459.920000 0.485000 ;
    END
  END la_data_in[106]
  PIN la_data_in[105]
    DIRECTION INPUT ;
    USE SIGNAL ;
    PORT
      LAYER met2 ;
        RECT 2442.300000 0.000000 2442.440000 0.485000 ;
    END
  END la_data_in[105]
  PIN la_data_in[104]
    DIRECTION INPUT ;
    USE SIGNAL ;
    PORT
      LAYER met2 ;
        RECT 2424.820000 0.000000 2424.960000 0.485000 ;
    END
  END la_data_in[104]
  PIN la_data_in[103]
    DIRECTION INPUT ;
    USE SIGNAL ;
    PORT
      LAYER met2 ;
        RECT 2407.340000 0.000000 2407.480000 0.485000 ;
    END
  END la_data_in[103]
  PIN la_data_in[102]
    DIRECTION INPUT ;
    USE SIGNAL ;
    PORT
      LAYER met2 ;
        RECT 2389.860000 0.000000 2390.000000 0.485000 ;
    END
  END la_data_in[102]
  PIN la_data_in[101]
    DIRECTION INPUT ;
    USE SIGNAL ;
    PORT
      LAYER met2 ;
        RECT 2372.380000 0.000000 2372.520000 0.485000 ;
    END
  END la_data_in[101]
  PIN la_data_in[100]
    DIRECTION INPUT ;
    USE SIGNAL ;
    PORT
      LAYER met2 ;
        RECT 2355.360000 0.000000 2355.500000 0.485000 ;
    END
  END la_data_in[100]
  PIN la_data_in[99]
    DIRECTION INPUT ;
    USE SIGNAL ;
    PORT
      LAYER met2 ;
        RECT 2337.880000 0.000000 2338.020000 0.485000 ;
    END
  END la_data_in[99]
  PIN la_data_in[98]
    DIRECTION INPUT ;
    USE SIGNAL ;
    PORT
      LAYER met2 ;
        RECT 2320.400000 0.000000 2320.540000 0.485000 ;
    END
  END la_data_in[98]
  PIN la_data_in[97]
    DIRECTION INPUT ;
    USE SIGNAL ;
    PORT
      LAYER met2 ;
        RECT 2302.920000 0.000000 2303.060000 0.485000 ;
    END
  END la_data_in[97]
  PIN la_data_in[96]
    DIRECTION INPUT ;
    USE SIGNAL ;
    PORT
      LAYER met2 ;
        RECT 2285.440000 0.000000 2285.580000 0.485000 ;
    END
  END la_data_in[96]
  PIN la_data_in[95]
    DIRECTION INPUT ;
    USE SIGNAL ;
    PORT
      LAYER met2 ;
        RECT 2267.960000 0.000000 2268.100000 0.485000 ;
    END
  END la_data_in[95]
  PIN la_data_in[94]
    DIRECTION INPUT ;
    USE SIGNAL ;
    PORT
      LAYER met2 ;
        RECT 2250.940000 0.000000 2251.080000 0.485000 ;
    END
  END la_data_in[94]
  PIN la_data_in[93]
    DIRECTION INPUT ;
    USE SIGNAL ;
    PORT
      LAYER met2 ;
        RECT 2233.460000 0.000000 2233.600000 0.485000 ;
    END
  END la_data_in[93]
  PIN la_data_in[92]
    DIRECTION INPUT ;
    USE SIGNAL ;
    PORT
      LAYER met2 ;
        RECT 2215.980000 0.000000 2216.120000 0.485000 ;
    END
  END la_data_in[92]
  PIN la_data_in[91]
    DIRECTION INPUT ;
    USE SIGNAL ;
    PORT
      LAYER met2 ;
        RECT 2198.500000 0.000000 2198.640000 0.485000 ;
    END
  END la_data_in[91]
  PIN la_data_in[90]
    DIRECTION INPUT ;
    USE SIGNAL ;
    PORT
      LAYER met2 ;
        RECT 2181.020000 0.000000 2181.160000 0.485000 ;
    END
  END la_data_in[90]
  PIN la_data_in[89]
    DIRECTION INPUT ;
    USE SIGNAL ;
    PORT
      LAYER met2 ;
        RECT 2163.540000 0.000000 2163.680000 0.485000 ;
    END
  END la_data_in[89]
  PIN la_data_in[88]
    DIRECTION INPUT ;
    USE SIGNAL ;
    PORT
      LAYER met2 ;
        RECT 2146.520000 0.000000 2146.660000 0.485000 ;
    END
  END la_data_in[88]
  PIN la_data_in[87]
    DIRECTION INPUT ;
    USE SIGNAL ;
    PORT
      LAYER met2 ;
        RECT 2129.040000 0.000000 2129.180000 0.485000 ;
    END
  END la_data_in[87]
  PIN la_data_in[86]
    DIRECTION INPUT ;
    USE SIGNAL ;
    PORT
      LAYER met2 ;
        RECT 2111.560000 0.000000 2111.700000 0.485000 ;
    END
  END la_data_in[86]
  PIN la_data_in[85]
    DIRECTION INPUT ;
    USE SIGNAL ;
    PORT
      LAYER met2 ;
        RECT 2094.080000 0.000000 2094.220000 0.485000 ;
    END
  END la_data_in[85]
  PIN la_data_in[84]
    DIRECTION INPUT ;
    USE SIGNAL ;
    PORT
      LAYER met2 ;
        RECT 2076.600000 0.000000 2076.740000 0.485000 ;
    END
  END la_data_in[84]
  PIN la_data_in[83]
    DIRECTION INPUT ;
    USE SIGNAL ;
    PORT
      LAYER met2 ;
        RECT 2059.580000 0.000000 2059.720000 0.485000 ;
    END
  END la_data_in[83]
  PIN la_data_in[82]
    DIRECTION INPUT ;
    USE SIGNAL ;
    PORT
      LAYER met2 ;
        RECT 2042.100000 0.000000 2042.240000 0.485000 ;
    END
  END la_data_in[82]
  PIN la_data_in[81]
    DIRECTION INPUT ;
    USE SIGNAL ;
    PORT
      LAYER met2 ;
        RECT 2024.620000 0.000000 2024.760000 0.485000 ;
    END
  END la_data_in[81]
  PIN la_data_in[80]
    DIRECTION INPUT ;
    USE SIGNAL ;
    PORT
      LAYER met2 ;
        RECT 2007.140000 0.000000 2007.280000 0.485000 ;
    END
  END la_data_in[80]
  PIN la_data_in[79]
    DIRECTION INPUT ;
    USE SIGNAL ;
    PORT
      LAYER met2 ;
        RECT 1989.660000 0.000000 1989.800000 0.485000 ;
    END
  END la_data_in[79]
  PIN la_data_in[78]
    DIRECTION INPUT ;
    USE SIGNAL ;
    PORT
      LAYER met2 ;
        RECT 1972.180000 0.000000 1972.320000 0.485000 ;
    END
  END la_data_in[78]
  PIN la_data_in[77]
    DIRECTION INPUT ;
    USE SIGNAL ;
    PORT
      LAYER met2 ;
        RECT 1955.160000 0.000000 1955.300000 0.485000 ;
    END
  END la_data_in[77]
  PIN la_data_in[76]
    DIRECTION INPUT ;
    USE SIGNAL ;
    PORT
      LAYER met2 ;
        RECT 1937.680000 0.000000 1937.820000 0.485000 ;
    END
  END la_data_in[76]
  PIN la_data_in[75]
    DIRECTION INPUT ;
    USE SIGNAL ;
    PORT
      LAYER met2 ;
        RECT 1920.200000 0.000000 1920.340000 0.485000 ;
    END
  END la_data_in[75]
  PIN la_data_in[74]
    DIRECTION INPUT ;
    USE SIGNAL ;
    PORT
      LAYER met2 ;
        RECT 1902.720000 0.000000 1902.860000 0.485000 ;
    END
  END la_data_in[74]
  PIN la_data_in[73]
    DIRECTION INPUT ;
    USE SIGNAL ;
    PORT
      LAYER met2 ;
        RECT 1885.240000 0.000000 1885.380000 0.485000 ;
    END
  END la_data_in[73]
  PIN la_data_in[72]
    DIRECTION INPUT ;
    USE SIGNAL ;
    PORT
      LAYER met2 ;
        RECT 1867.760000 0.000000 1867.900000 0.485000 ;
    END
  END la_data_in[72]
  PIN la_data_in[71]
    DIRECTION INPUT ;
    USE SIGNAL ;
    PORT
      LAYER met2 ;
        RECT 1850.740000 0.000000 1850.880000 0.485000 ;
    END
  END la_data_in[71]
  PIN la_data_in[70]
    DIRECTION INPUT ;
    USE SIGNAL ;
    PORT
      LAYER met2 ;
        RECT 1833.260000 0.000000 1833.400000 0.485000 ;
    END
  END la_data_in[70]
  PIN la_data_in[69]
    DIRECTION INPUT ;
    USE SIGNAL ;
    PORT
      LAYER met2 ;
        RECT 1815.780000 0.000000 1815.920000 0.485000 ;
    END
  END la_data_in[69]
  PIN la_data_in[68]
    DIRECTION INPUT ;
    USE SIGNAL ;
    PORT
      LAYER met2 ;
        RECT 1798.300000 0.000000 1798.440000 0.485000 ;
    END
  END la_data_in[68]
  PIN la_data_in[67]
    DIRECTION INPUT ;
    USE SIGNAL ;
    PORT
      LAYER met2 ;
        RECT 1780.820000 0.000000 1780.960000 0.485000 ;
    END
  END la_data_in[67]
  PIN la_data_in[66]
    DIRECTION INPUT ;
    USE SIGNAL ;
    PORT
      LAYER met2 ;
        RECT 1763.340000 0.000000 1763.480000 0.485000 ;
    END
  END la_data_in[66]
  PIN la_data_in[65]
    DIRECTION INPUT ;
    USE SIGNAL ;
    PORT
      LAYER met2 ;
        RECT 1746.320000 0.000000 1746.460000 0.485000 ;
    END
  END la_data_in[65]
  PIN la_data_in[64]
    DIRECTION INPUT ;
    USE SIGNAL ;
    PORT
      LAYER met2 ;
        RECT 1728.840000 0.000000 1728.980000 0.485000 ;
    END
  END la_data_in[64]
  PIN la_data_in[63]
    DIRECTION INPUT ;
    USE SIGNAL ;
    PORT
      LAYER met2 ;
        RECT 1711.360000 0.000000 1711.500000 0.485000 ;
    END
  END la_data_in[63]
  PIN la_data_in[62]
    DIRECTION INPUT ;
    USE SIGNAL ;
    PORT
      LAYER met2 ;
        RECT 1693.880000 0.000000 1694.020000 0.485000 ;
    END
  END la_data_in[62]
  PIN la_data_in[61]
    DIRECTION INPUT ;
    USE SIGNAL ;
    PORT
      LAYER met2 ;
        RECT 1676.400000 0.000000 1676.540000 0.485000 ;
    END
  END la_data_in[61]
  PIN la_data_in[60]
    DIRECTION INPUT ;
    USE SIGNAL ;
    PORT
      LAYER met2 ;
        RECT 1659.380000 0.000000 1659.520000 0.485000 ;
    END
  END la_data_in[60]
  PIN la_data_in[59]
    DIRECTION INPUT ;
    USE SIGNAL ;
    PORT
      LAYER met2 ;
        RECT 1641.900000 0.000000 1642.040000 0.485000 ;
    END
  END la_data_in[59]
  PIN la_data_in[58]
    DIRECTION INPUT ;
    USE SIGNAL ;
    PORT
      LAYER met2 ;
        RECT 1624.420000 0.000000 1624.560000 0.485000 ;
    END
  END la_data_in[58]
  PIN la_data_in[57]
    DIRECTION INPUT ;
    USE SIGNAL ;
    PORT
      LAYER met2 ;
        RECT 1606.940000 0.000000 1607.080000 0.485000 ;
    END
  END la_data_in[57]
  PIN la_data_in[56]
    DIRECTION INPUT ;
    USE SIGNAL ;
    PORT
      LAYER met2 ;
        RECT 1589.460000 0.000000 1589.600000 0.485000 ;
    END
  END la_data_in[56]
  PIN la_data_in[55]
    DIRECTION INPUT ;
    USE SIGNAL ;
    PORT
      LAYER met2 ;
        RECT 1571.980000 0.000000 1572.120000 0.485000 ;
    END
  END la_data_in[55]
  PIN la_data_in[54]
    DIRECTION INPUT ;
    USE SIGNAL ;
    PORT
      LAYER met2 ;
        RECT 1554.960000 0.000000 1555.100000 0.485000 ;
    END
  END la_data_in[54]
  PIN la_data_in[53]
    DIRECTION INPUT ;
    USE SIGNAL ;
    PORT
      LAYER met2 ;
        RECT 1537.480000 0.000000 1537.620000 0.485000 ;
    END
  END la_data_in[53]
  PIN la_data_in[52]
    DIRECTION INPUT ;
    USE SIGNAL ;
    PORT
      LAYER met2 ;
        RECT 1520.000000 0.000000 1520.140000 0.485000 ;
    END
  END la_data_in[52]
  PIN la_data_in[51]
    DIRECTION INPUT ;
    USE SIGNAL ;
    PORT
      LAYER met2 ;
        RECT 1502.520000 0.000000 1502.660000 0.485000 ;
    END
  END la_data_in[51]
  PIN la_data_in[50]
    DIRECTION INPUT ;
    USE SIGNAL ;
    PORT
      LAYER met2 ;
        RECT 1485.040000 0.000000 1485.180000 0.485000 ;
    END
  END la_data_in[50]
  PIN la_data_in[49]
    DIRECTION INPUT ;
    USE SIGNAL ;
    PORT
      LAYER met2 ;
        RECT 1467.560000 0.000000 1467.700000 0.485000 ;
    END
  END la_data_in[49]
  PIN la_data_in[48]
    DIRECTION INPUT ;
    USE SIGNAL ;
    PORT
      LAYER met2 ;
        RECT 1450.540000 0.000000 1450.680000 0.485000 ;
    END
  END la_data_in[48]
  PIN la_data_in[47]
    DIRECTION INPUT ;
    USE SIGNAL ;
    PORT
      LAYER met2 ;
        RECT 1433.060000 0.000000 1433.200000 0.485000 ;
    END
  END la_data_in[47]
  PIN la_data_in[46]
    DIRECTION INPUT ;
    USE SIGNAL ;
    PORT
      LAYER met2 ;
        RECT 1415.580000 0.000000 1415.720000 0.485000 ;
    END
  END la_data_in[46]
  PIN la_data_in[45]
    DIRECTION INPUT ;
    USE SIGNAL ;
    PORT
      LAYER met2 ;
        RECT 1398.100000 0.000000 1398.240000 0.485000 ;
    END
  END la_data_in[45]
  PIN la_data_in[44]
    DIRECTION INPUT ;
    USE SIGNAL ;
    PORT
      LAYER met2 ;
        RECT 1380.620000 0.000000 1380.760000 0.485000 ;
    END
  END la_data_in[44]
  PIN la_data_in[43]
    DIRECTION INPUT ;
    USE SIGNAL ;
    PORT
      LAYER met2 ;
        RECT 1363.600000 0.000000 1363.740000 0.485000 ;
    END
  END la_data_in[43]
  PIN la_data_in[42]
    DIRECTION INPUT ;
    USE SIGNAL ;
    PORT
      LAYER met2 ;
        RECT 1346.120000 0.000000 1346.260000 0.485000 ;
    END
  END la_data_in[42]
  PIN la_data_in[41]
    DIRECTION INPUT ;
    USE SIGNAL ;
    PORT
      LAYER met2 ;
        RECT 1328.640000 0.000000 1328.780000 0.485000 ;
    END
  END la_data_in[41]
  PIN la_data_in[40]
    DIRECTION INPUT ;
    USE SIGNAL ;
    PORT
      LAYER met2 ;
        RECT 1311.160000 0.000000 1311.300000 0.485000 ;
    END
  END la_data_in[40]
  PIN la_data_in[39]
    DIRECTION INPUT ;
    USE SIGNAL ;
    ANTENNAPARTIALMETALAREA 28.1034 LAYER met2  ;
    ANTENNAPARTIALMETALSIDEAREA 140.238 LAYER met2  ;
    ANTENNAPARTIALCUTAREA 0.04 LAYER via2  ;
    ANTENNAPARTIALMETALAREA 0.255 LAYER met3  ;
    ANTENNAPARTIALMETALSIDEAREA 1.808 LAYER met3  ;
    ANTENNAPARTIALCUTAREA 0.04 LAYER via3  ;
    ANTENNAPARTIALMETALAREA 4.1448 LAYER met4  ;
    ANTENNAPARTIALMETALSIDEAREA 22.576 LAYER met4  ;
    ANTENNAMODEL OXIDE1 ;
    ANTENNAGATEAREA 0.2475 LAYER met4  ;
    ANTENNAMAXAREACAR 21.7149 LAYER met4  ;
    ANTENNAMAXSIDEAREACAR 115.531 LAYER met4  ;
    ANTENNAMAXCUTCAR 0.530909 LAYER via4  ;
    PORT
      LAYER met2 ;
        RECT 1293.680000 0.000000 1293.820000 0.485000 ;
    END
  END la_data_in[39]
  PIN la_data_in[38]
    DIRECTION INPUT ;
    USE SIGNAL ;
    ANTENNAPARTIALMETALAREA 29.0542 LAYER met2  ;
    ANTENNAPARTIALMETALSIDEAREA 145.11 LAYER met2  ;
    ANTENNAPARTIALCUTAREA 0.04 LAYER via2  ;
    ANTENNAPARTIALMETALAREA 0.2509 LAYER met3  ;
    ANTENNAPARTIALMETALSIDEAREA 1.808 LAYER met3  ;
    ANTENNAPARTIALCUTAREA 0.04 LAYER via3  ;
    ANTENNAPARTIALMETALAREA 3.9618 LAYER met4  ;
    ANTENNAPARTIALMETALSIDEAREA 21.6 LAYER met4  ;
    ANTENNAMODEL OXIDE1 ;
    ANTENNAGATEAREA 0.2475 LAYER met4  ;
    ANTENNAMAXAREACAR 40.1271 LAYER met4  ;
    ANTENNAMAXSIDEAREACAR 207.156 LAYER met4  ;
    ANTENNAMAXCUTCAR 0.530909 LAYER via4  ;
    PORT
      LAYER met2 ;
        RECT 1276.200000 0.000000 1276.340000 0.485000 ;
    END
  END la_data_in[38]
  PIN la_data_in[37]
    DIRECTION INPUT ;
    USE SIGNAL ;
    ANTENNAPARTIALMETALAREA 30.3156 LAYER met2  ;
    ANTENNAPARTIALMETALSIDEAREA 151.417 LAYER met2  ;
    ANTENNAPARTIALCUTAREA 0.04 LAYER via2  ;
    ANTENNAPARTIALMETALAREA 0.2509 LAYER met3  ;
    ANTENNAPARTIALMETALSIDEAREA 1.808 LAYER met3  ;
    ANTENNAPARTIALCUTAREA 0.04 LAYER via3  ;
    ANTENNAPARTIALMETALAREA 3.9618 LAYER met4  ;
    ANTENNAPARTIALMETALSIDEAREA 21.6 LAYER met4  ;
    ANTENNAMODEL OXIDE1 ;
    ANTENNAGATEAREA 0.2475 LAYER met4  ;
    ANTENNAMAXAREACAR 28.4493 LAYER met4  ;
    ANTENNAMAXSIDEAREACAR 149.568 LAYER met4  ;
    ANTENNAMAXCUTCAR 0.530909 LAYER via4  ;
    PORT
      LAYER met2 ;
        RECT 1259.180000 0.000000 1259.320000 0.485000 ;
    END
  END la_data_in[37]
  PIN la_data_in[36]
    DIRECTION INPUT ;
    USE SIGNAL ;
    ANTENNAPARTIALMETALAREA 35.119 LAYER met2  ;
    ANTENNAPARTIALMETALSIDEAREA 175.434 LAYER met2  ;
    ANTENNAPARTIALCUTAREA 0.04 LAYER via2  ;
    ANTENNAPARTIALMETALAREA 0.255 LAYER met3  ;
    ANTENNAPARTIALMETALSIDEAREA 1.808 LAYER met3  ;
    ANTENNAPARTIALCUTAREA 0.04 LAYER via3  ;
    ANTENNAPARTIALMETALAREA 3.7788 LAYER met4  ;
    ANTENNAPARTIALMETALSIDEAREA 20.624 LAYER met4  ;
    ANTENNAMODEL OXIDE1 ;
    ANTENNAGATEAREA 0.2475 LAYER met4  ;
    ANTENNAMAXAREACAR 40.6121 LAYER met4  ;
    ANTENNAMAXSIDEAREACAR 210.053 LAYER met4  ;
    ANTENNAMAXCUTCAR 0.530909 LAYER via4  ;
    PORT
      LAYER met2 ;
        RECT 1241.700000 0.000000 1241.840000 0.485000 ;
    END
  END la_data_in[36]
  PIN la_data_in[35]
    DIRECTION INPUT ;
    USE SIGNAL ;
    ANTENNAPARTIALMETALAREA 33.3618 LAYER met2  ;
    ANTENNAPARTIALMETALSIDEAREA 166.53 LAYER met2  ;
    ANTENNAPARTIALCUTAREA 0.04 LAYER via2  ;
    ANTENNAPARTIALMETALAREA 0.255 LAYER met3  ;
    ANTENNAPARTIALMETALSIDEAREA 1.808 LAYER met3  ;
    ANTENNAPARTIALCUTAREA 0.04 LAYER via3  ;
    ANTENNAPARTIALMETALAREA 5.9748 LAYER met4  ;
    ANTENNAPARTIALMETALSIDEAREA 32.336 LAYER met4  ;
    ANTENNAMODEL OXIDE1 ;
    ANTENNAGATEAREA 0.2475 LAYER met4  ;
    ANTENNAMAXAREACAR 47.1204 LAYER met4  ;
    ANTENNAMAXSIDEAREACAR 245.552 LAYER met4  ;
    ANTENNAMAXCUTCAR 0.530909 LAYER via4  ;
    PORT
      LAYER met2 ;
        RECT 1224.220000 0.000000 1224.360000 0.485000 ;
    END
  END la_data_in[35]
  PIN la_data_in[34]
    DIRECTION INPUT ;
    USE SIGNAL ;
    ANTENNAPARTIALMETALAREA 38.5979 LAYER met2  ;
    ANTENNAPARTIALMETALSIDEAREA 192.882 LAYER met2  ;
    ANTENNAMODEL OXIDE1 ;
    ANTENNAGATEAREA 0.495 LAYER met2  ;
    ANTENNAMAXAREACAR 79.9098 LAYER met2  ;
    ANTENNAMAXSIDEAREACAR 392.988 LAYER met2  ;
    ANTENNAMAXCUTCAR 0.103838 LAYER via2  ;
    PORT
      LAYER met2 ;
        RECT 1206.740000 0.000000 1206.880000 0.485000 ;
    END
  END la_data_in[34]
  PIN la_data_in[33]
    DIRECTION INPUT ;
    USE SIGNAL ;
    ANTENNAPARTIALMETALAREA 32.8972 LAYER met2  ;
    ANTENNAPARTIALMETALSIDEAREA 164.325 LAYER met2  ;
    ANTENNAPARTIALCUTAREA 0.04 LAYER via2  ;
    ANTENNAPARTIALMETALAREA 0.2509 LAYER met3  ;
    ANTENNAPARTIALMETALSIDEAREA 1.808 LAYER met3  ;
    ANTENNAPARTIALCUTAREA 0.04 LAYER via3  ;
    ANTENNAPARTIALMETALAREA 4.1448 LAYER met4  ;
    ANTENNAPARTIALMETALSIDEAREA 22.576 LAYER met4  ;
    ANTENNAMODEL OXIDE1 ;
    ANTENNAGATEAREA 0.2475 LAYER met4  ;
    ANTENNAMAXAREACAR 31.44 LAYER met4  ;
    ANTENNAMAXSIDEAREACAR 164.768 LAYER met4  ;
    ANTENNAMAXCUTCAR 0.530909 LAYER via4  ;
    PORT
      LAYER met2 ;
        RECT 1189.260000 0.000000 1189.400000 0.485000 ;
    END
  END la_data_in[33]
  PIN la_data_in[32]
    DIRECTION INPUT ;
    USE SIGNAL ;
    ANTENNAPARTIALMETALAREA 30.1224 LAYER met2  ;
    ANTENNAPARTIALMETALSIDEAREA 150.451 LAYER met2  ;
    ANTENNAPARTIALCUTAREA 0.04 LAYER via2  ;
    ANTENNAPARTIALMETALAREA 0.469 LAYER met3  ;
    ANTENNAPARTIALMETALSIDEAREA 2.968 LAYER met3  ;
    ANTENNAPARTIALCUTAREA 0.04 LAYER via3  ;
    ANTENNAPARTIALMETALAREA 6.6906 LAYER met4  ;
    ANTENNAPARTIALMETALSIDEAREA 36.624 LAYER met4  ;
    ANTENNAMODEL OXIDE1 ;
    ANTENNAGATEAREA 0.2475 LAYER met4  ;
    ANTENNAMAXAREACAR 58.579 LAYER met4  ;
    ANTENNAMAXSIDEAREACAR 306.683 LAYER met4  ;
    ANTENNAMAXCUTCAR 0.530909 LAYER via4  ;
    PORT
      LAYER met2 ;
        RECT 1171.780000 0.000000 1171.920000 0.485000 ;
    END
  END la_data_in[32]
  PIN la_data_in[31]
    DIRECTION INPUT ;
    USE SIGNAL ;
    ANTENNAPARTIALMETALAREA 29.9936 LAYER met2  ;
    ANTENNAPARTIALMETALSIDEAREA 149.807 LAYER met2  ;
    ANTENNAPARTIALCUTAREA 0.04 LAYER via2  ;
    ANTENNAPARTIALMETALAREA 0.2509 LAYER met3  ;
    ANTENNAPARTIALMETALSIDEAREA 1.808 LAYER met3  ;
    ANTENNAPARTIALCUTAREA 0.04 LAYER via3  ;
    ANTENNAPARTIALMETALAREA 4.5588 LAYER met4  ;
    ANTENNAPARTIALMETALSIDEAREA 24.784 LAYER met4  ;
    ANTENNAMODEL OXIDE1 ;
    ANTENNAGATEAREA 0.2475 LAYER met4  ;
    ANTENNAMAXAREACAR 38.4921 LAYER met4  ;
    ANTENNAMAXSIDEAREACAR 200.586 LAYER met4  ;
    ANTENNAMAXCUTCAR 0.530909 LAYER via4  ;
    PORT
      LAYER met2 ;
        RECT 1154.760000 0.000000 1154.900000 0.485000 ;
    END
  END la_data_in[31]
  PIN la_data_in[30]
    DIRECTION INPUT ;
    USE SIGNAL ;
    ANTENNAPARTIALMETALAREA 25.2546 LAYER met2  ;
    ANTENNAPARTIALMETALSIDEAREA 126.112 LAYER met2  ;
    ANTENNAPARTIALCUTAREA 0.04 LAYER via2  ;
    ANTENNAPARTIALMETALAREA 0.255 LAYER met3  ;
    ANTENNAPARTIALMETALSIDEAREA 1.808 LAYER met3  ;
    ANTENNAPARTIALCUTAREA 0.04 LAYER via3  ;
    ANTENNAPARTIALMETALAREA 6.1578 LAYER met4  ;
    ANTENNAPARTIALMETALSIDEAREA 33.312 LAYER met4  ;
    ANTENNAMODEL OXIDE1 ;
    ANTENNAGATEAREA 0.2475 LAYER met4  ;
    ANTENNAMAXAREACAR 42.3164 LAYER met4  ;
    ANTENNAMAXSIDEAREACAR 221.778 LAYER met4  ;
    ANTENNAMAXCUTCAR 0.530909 LAYER via4  ;
    PORT
      LAYER met2 ;
        RECT 1137.280000 0.000000 1137.420000 0.485000 ;
    END
  END la_data_in[30]
  PIN la_data_in[29]
    DIRECTION INPUT ;
    USE SIGNAL ;
    ANTENNAPARTIALMETALAREA 12.7008 LAYER met2  ;
    ANTENNAPARTIALMETALSIDEAREA 63.343 LAYER met2  ;
    ANTENNAPARTIALCUTAREA 0.04 LAYER via2  ;
    ANTENNAPARTIALMETALAREA 0.255 LAYER met3  ;
    ANTENNAPARTIALMETALSIDEAREA 1.808 LAYER met3  ;
    ANTENNAPARTIALCUTAREA 0.04 LAYER via3  ;
    ANTENNAPARTIALMETALAREA 6.1578 LAYER met4  ;
    ANTENNAPARTIALMETALSIDEAREA 33.312 LAYER met4  ;
    ANTENNAMODEL OXIDE1 ;
    ANTENNAGATEAREA 0.2475 LAYER met4  ;
    ANTENNAMAXAREACAR 92.9339 LAYER met4  ;
    ANTENNAMAXSIDEAREACAR 474.065 LAYER met4  ;
    ANTENNAMAXCUTCAR 0.530909 LAYER via4  ;
    PORT
      LAYER met2 ;
        RECT 1119.800000 0.000000 1119.940000 0.485000 ;
    END
  END la_data_in[29]
  PIN la_data_in[28]
    DIRECTION INPUT ;
    USE SIGNAL ;
    ANTENNAPARTIALMETALAREA 30.1224 LAYER met2  ;
    ANTENNAPARTIALMETALSIDEAREA 150.451 LAYER met2  ;
    ANTENNAPARTIALCUTAREA 0.04 LAYER via2  ;
    ANTENNAPARTIALMETALAREA 0.2509 LAYER met3  ;
    ANTENNAPARTIALMETALSIDEAREA 1.808 LAYER met3  ;
    ANTENNAPARTIALCUTAREA 0.04 LAYER via3  ;
    ANTENNAPARTIALMETALAREA 4.1448 LAYER met4  ;
    ANTENNAPARTIALMETALSIDEAREA 22.576 LAYER met4  ;
    ANTENNAMODEL OXIDE1 ;
    ANTENNAGATEAREA 0.2475 LAYER met4  ;
    ANTENNAMAXAREACAR 35.6568 LAYER met4  ;
    ANTENNAMAXSIDEAREACAR 185.051 LAYER met4  ;
    ANTENNAMAXCUTCAR 0.530909 LAYER via4  ;
    PORT
      LAYER met2 ;
        RECT 1102.320000 0.000000 1102.460000 0.485000 ;
    END
  END la_data_in[28]
  PIN la_data_in[27]
    DIRECTION INPUT ;
    USE SIGNAL ;
    ANTENNAPARTIALMETALAREA 3.9466 LAYER met2  ;
    ANTENNAPARTIALMETALSIDEAREA 19.572 LAYER met2  ;
    ANTENNAPARTIALCUTAREA 0.04 LAYER via2  ;
    ANTENNAPARTIALMETALAREA 0.255 LAYER met3  ;
    ANTENNAPARTIALMETALSIDEAREA 1.808 LAYER met3  ;
    ANTENNAPARTIALCUTAREA 0.04 LAYER via3  ;
    ANTENNAPARTIALMETALAREA 6.1578 LAYER met4  ;
    ANTENNAPARTIALMETALSIDEAREA 33.312 LAYER met4  ;
    ANTENNAMODEL OXIDE1 ;
    ANTENNAGATEAREA 0.126 LAYER met4  ;
    ANTENNAMAXAREACAR 93.6389 LAYER met4  ;
    ANTENNAMAXSIDEAREACAR 479.921 LAYER met4  ;
    ANTENNAMAXCUTCAR 1.04286 LAYER via4  ;
    PORT
      LAYER met2 ;
        RECT 1084.840000 0.000000 1084.980000 0.485000 ;
    END
  END la_data_in[27]
  PIN la_data_in[26]
    DIRECTION INPUT ;
    USE SIGNAL ;
    ANTENNAPARTIALMETALAREA 8.7631 LAYER met2  ;
    ANTENNAPARTIALMETALSIDEAREA 43.5365 LAYER met2  ;
    ANTENNAPARTIALCUTAREA 0.04 LAYER via2  ;
    ANTENNAPARTIALMETALAREA 0.2509 LAYER met3  ;
    ANTENNAPARTIALMETALSIDEAREA 1.808 LAYER met3  ;
    ANTENNAPARTIALCUTAREA 0.04 LAYER via3  ;
    ANTENNAPARTIALMETALAREA 3.9618 LAYER met4  ;
    ANTENNAPARTIALMETALSIDEAREA 21.6 LAYER met4  ;
    ANTENNAMODEL OXIDE1 ;
    ANTENNAGATEAREA 0.126 LAYER met4  ;
    ANTENNAMAXAREACAR 67.9548 LAYER met4  ;
    ANTENNAMAXSIDEAREACAR 340.683 LAYER met4  ;
    ANTENNAMAXCUTCAR 1.04286 LAYER via4  ;
    PORT
      LAYER met2 ;
        RECT 1067.360000 0.000000 1067.500000 0.485000 ;
    END
  END la_data_in[26]
  PIN la_data_in[25]
    DIRECTION INPUT ;
    USE SIGNAL ;
    ANTENNAPARTIALMETALAREA 36.9878 LAYER met2  ;
    ANTENNAPARTIALMETALSIDEAREA 184.66 LAYER met2  ;
    ANTENNAPARTIALCUTAREA 0.04 LAYER via2  ;
    ANTENNAPARTIALMETALAREA 1.9128 LAYER met3  ;
    ANTENNAPARTIALMETALSIDEAREA 10.672 LAYER met3  ;
    ANTENNAMODEL OXIDE1 ;
    ANTENNAGATEAREA 0.495 LAYER met3  ;
    ANTENNAMAXAREACAR 4.83293 LAYER met3  ;
    ANTENNAMAXSIDEAREACAR 24.9051 LAYER met3  ;
    ANTENNAMAXCUTCAR 0.184646 LAYER via3  ;
    PORT
      LAYER met2 ;
        RECT 1050.340000 0.000000 1050.480000 0.485000 ;
    END
  END la_data_in[25]
  PIN la_data_in[24]
    DIRECTION INPUT ;
    USE SIGNAL ;
    ANTENNAPARTIALMETALAREA 9.7538 LAYER met2  ;
    ANTENNAPARTIALMETALSIDEAREA 48.608 LAYER met2  ;
    ANTENNAPARTIALCUTAREA 0.04 LAYER via2  ;
    ANTENNAPARTIALMETALAREA 0.255 LAYER met3  ;
    ANTENNAPARTIALMETALSIDEAREA 1.808 LAYER met3  ;
    ANTENNAPARTIALCUTAREA 0.04 LAYER via3  ;
    ANTENNAPARTIALMETALAREA 5.9748 LAYER met4  ;
    ANTENNAPARTIALMETALSIDEAREA 32.336 LAYER met4  ;
    ANTENNAMODEL OXIDE1 ;
    ANTENNAGATEAREA 0.2475 LAYER met4  ;
    ANTENNAMAXAREACAR 151.73 LAYER met4  ;
    ANTENNAMAXSIDEAREACAR 767.798 LAYER met4  ;
    ANTENNAMAXCUTCAR 0.530909 LAYER via4  ;
    PORT
      LAYER met2 ;
        RECT 1032.860000 0.000000 1033.000000 0.485000 ;
    END
  END la_data_in[24]
  PIN la_data_in[23]
    DIRECTION INPUT ;
    USE SIGNAL ;
    ANTENNAPARTIALMETALAREA 39.5511 LAYER met2  ;
    ANTENNAPARTIALMETALSIDEAREA 197.53 LAYER met2  ;
    ANTENNAMODEL OXIDE1 ;
    ANTENNAGATEAREA 0.495 LAYER met2  ;
    ANTENNAMAXAREACAR 83.381 LAYER met2  ;
    ANTENNAMAXSIDEAREACAR 413.802 LAYER met2  ;
    ANTENNAMAXCUTCAR 0.103838 LAYER via2  ;
    PORT
      LAYER met2 ;
        RECT 1015.380000 0.000000 1015.520000 0.485000 ;
    END
  END la_data_in[23]
  PIN la_data_in[22]
    DIRECTION INPUT ;
    USE SIGNAL ;
    ANTENNAPARTIALMETALAREA 23.247 LAYER met2  ;
    ANTENNAPARTIALMETALSIDEAREA 116.074 LAYER met2  ;
    ANTENNAPARTIALCUTAREA 0.04 LAYER via2  ;
    ANTENNADIFFAREA 0.4347 LAYER met3  ;
    ANTENNAPARTIALMETALAREA 16.4028 LAYER met3  ;
    ANTENNAPARTIALMETALSIDEAREA 87.952 LAYER met3  ;
    ANTENNAMODEL OXIDE1 ;
    ANTENNAGATEAREA 0.315 LAYER met3  ;
    ANTENNAMAXAREACAR 159.04 LAYER met3  ;
    ANTENNAMAXSIDEAREACAR 785.137 LAYER met3  ;
    ANTENNAMAXCUTCAR 0.290159 LAYER via3  ;
    PORT
      LAYER met2 ;
        RECT 997.900000 0.000000 998.040000 0.485000 ;
    END
  END la_data_in[22]
  PIN la_data_in[21]
    DIRECTION INPUT ;
    USE SIGNAL ;
    ANTENNAPARTIALMETALAREA 44.9454 LAYER met2  ;
    ANTENNAPARTIALMETALSIDEAREA 224.448 LAYER met2  ;
    ANTENNAPARTIALCUTAREA 0.04 LAYER via2  ;
    ANTENNAPARTIALMETALAREA 0.331 LAYER met3  ;
    ANTENNAPARTIALMETALSIDEAREA 2.232 LAYER met3  ;
    ANTENNAPARTIALCUTAREA 0.04 LAYER via3  ;
    ANTENNAPARTIALMETALAREA 6.3888 LAYER met4  ;
    ANTENNAPARTIALMETALSIDEAREA 34.544 LAYER met4  ;
    ANTENNAMODEL OXIDE1 ;
    ANTENNAGATEAREA 0.315 LAYER met4  ;
    ANTENNAMAXAREACAR 26.9416 LAYER met4  ;
    ANTENNAMAXSIDEAREACAR 140.692 LAYER met4  ;
    ANTENNAMAXCUTCAR 0.417143 LAYER via4  ;
    PORT
      LAYER met2 ;
        RECT 980.420000 0.000000 980.560000 0.485000 ;
    END
  END la_data_in[21]
  PIN la_data_in[20]
    DIRECTION INPUT ;
    USE SIGNAL ;
    ANTENNAPARTIALMETALAREA 35.004 LAYER met2  ;
    ANTENNAPARTIALMETALSIDEAREA 174.741 LAYER met2  ;
    ANTENNAPARTIALCUTAREA 0.04 LAYER via2  ;
    ANTENNAPARTIALMETALAREA 0.2509 LAYER met3  ;
    ANTENNAPARTIALMETALSIDEAREA 1.808 LAYER met3  ;
    ANTENNAPARTIALCUTAREA 0.04 LAYER via3  ;
    ANTENNAPARTIALMETALAREA 3.7788 LAYER met4  ;
    ANTENNAPARTIALMETALSIDEAREA 20.624 LAYER met4  ;
    ANTENNAMODEL OXIDE1 ;
    ANTENNAGATEAREA 0.159 LAYER met4  ;
    ANTENNAMAXAREACAR 30.3481 LAYER met4  ;
    ANTENNAMAXSIDEAREACAR 161.321 LAYER met4  ;
    ANTENNAMAXCUTCAR 0.826415 LAYER via4  ;
    PORT
      LAYER met2 ;
        RECT 963.400000 0.000000 963.540000 0.485000 ;
    END
  END la_data_in[20]
  PIN la_data_in[19]
    DIRECTION INPUT ;
    USE SIGNAL ;
    ANTENNAPARTIALMETALAREA 25.1998 LAYER met2  ;
    ANTENNAPARTIALMETALSIDEAREA 125.72 LAYER met2  ;
    ANTENNAPARTIALCUTAREA 0.04 LAYER via2  ;
    ANTENNAPARTIALMETALAREA 0.255 LAYER met3  ;
    ANTENNAPARTIALMETALSIDEAREA 1.808 LAYER met3  ;
    ANTENNAPARTIALCUTAREA 0.04 LAYER via3  ;
    ANTENNAPARTIALMETALAREA 6.5718 LAYER met4  ;
    ANTENNAPARTIALMETALSIDEAREA 35.52 LAYER met4  ;
    ANTENNAMODEL OXIDE1 ;
    ANTENNAGATEAREA 0.126 LAYER met4  ;
    ANTENNAMAXAREACAR 86.2571 LAYER met4  ;
    ANTENNAMAXSIDEAREACAR 438.936 LAYER met4  ;
    ANTENNAMAXCUTCAR 1.04286 LAYER via4  ;
    PORT
      LAYER met2 ;
        RECT 945.920000 0.000000 946.060000 0.485000 ;
    END
  END la_data_in[19]
  PIN la_data_in[18]
    DIRECTION INPUT ;
    USE SIGNAL ;
    ANTENNAPARTIALMETALAREA 28.1244 LAYER met2  ;
    ANTENNAPARTIALMETALSIDEAREA 140.343 LAYER met2  ;
    ANTENNAPARTIALCUTAREA 0.04 LAYER via2  ;
    ANTENNAPARTIALMETALAREA 0.255 LAYER met3  ;
    ANTENNAPARTIALMETALSIDEAREA 1.808 LAYER met3  ;
    ANTENNAPARTIALCUTAREA 0.04 LAYER via3  ;
    ANTENNAPARTIALMETALAREA 4.1448 LAYER met4  ;
    ANTENNAPARTIALMETALSIDEAREA 22.576 LAYER met4  ;
    ANTENNAMODEL OXIDE1 ;
    ANTENNAGATEAREA 0.126 LAYER met4  ;
    ANTENNAMAXAREACAR 59.273 LAYER met4  ;
    ANTENNAMAXSIDEAREACAR 297.595 LAYER met4  ;
    ANTENNAMAXCUTCAR 1.04286 LAYER via4  ;
    PORT
      LAYER met2 ;
        RECT 928.440000 0.000000 928.580000 0.485000 ;
    END
  END la_data_in[18]
  PIN la_data_in[17]
    DIRECTION INPUT ;
    USE SIGNAL ;
    ANTENNAPARTIALMETALAREA 28.0294 LAYER met2  ;
    ANTENNAPARTIALMETALSIDEAREA 139.986 LAYER met2  ;
    ANTENNAPARTIALCUTAREA 0.04 LAYER via2  ;
    ANTENNAPARTIALMETALAREA 0.255 LAYER met3  ;
    ANTENNAPARTIALMETALSIDEAREA 1.808 LAYER met3  ;
    ANTENNAPARTIALCUTAREA 0.04 LAYER via3  ;
    ANTENNAPARTIALMETALAREA 4.1448 LAYER met4  ;
    ANTENNAPARTIALMETALSIDEAREA 22.576 LAYER met4  ;
    ANTENNAMODEL OXIDE1 ;
    ANTENNAGATEAREA 0.126 LAYER met4  ;
    ANTENNAMAXAREACAR 60.9714 LAYER met4  ;
    ANTENNAMAXSIDEAREACAR 305.151 LAYER met4  ;
    ANTENNAMAXCUTCAR 1.04286 LAYER via4  ;
    PORT
      LAYER met2 ;
        RECT 910.960000 0.000000 911.100000 0.485000 ;
    END
  END la_data_in[17]
  PIN la_data_in[16]
    DIRECTION INPUT ;
    USE SIGNAL ;
    ANTENNAPARTIALMETALAREA 26.2456 LAYER met2  ;
    ANTENNAPARTIALMETALSIDEAREA 130.949 LAYER met2  ;
    ANTENNAPARTIALCUTAREA 0.04 LAYER via2  ;
    ANTENNAPARTIALMETALAREA 0.255 LAYER met3  ;
    ANTENNAPARTIALMETALSIDEAREA 1.808 LAYER met3  ;
    ANTENNAPARTIALCUTAREA 0.04 LAYER via3  ;
    ANTENNAPARTIALMETALAREA 6.1578 LAYER met4  ;
    ANTENNAPARTIALMETALSIDEAREA 33.312 LAYER met4  ;
    ANTENNAMODEL OXIDE1 ;
    ANTENNAGATEAREA 0.315 LAYER met4  ;
    ANTENNAMAXAREACAR 34.5819 LAYER met4  ;
    ANTENNAMAXSIDEAREACAR 178.959 LAYER met4  ;
    ANTENNAMAXCUTCAR 0.417143 LAYER via4  ;
    PORT
      LAYER met2 ;
        RECT 893.480000 0.000000 893.620000 0.485000 ;
    END
  END la_data_in[16]
  PIN la_data_in[15]
    DIRECTION INPUT ;
    USE SIGNAL ;
    ANTENNADIFFAREA 0.4347 LAYER met2  ;
    ANTENNAPARTIALMETALAREA 31.4955 LAYER met2  ;
    ANTENNAPARTIALMETALSIDEAREA 157.252 LAYER met2  ;
    ANTENNAMODEL OXIDE1 ;
    ANTENNAGATEAREA 0.126 LAYER met2  ;
    ANTENNAMAXAREACAR 269.502 LAYER met2  ;
    ANTENNAMAXSIDEAREACAR 1272.72 LAYER met2  ;
    ANTENNAMAXCUTCAR 0.407937 LAYER via2  ;
    PORT
      LAYER met2 ;
        RECT 876.000000 0.000000 876.140000 0.485000 ;
    END
  END la_data_in[15]
  PIN la_data_in[14]
    DIRECTION INPUT ;
    USE SIGNAL ;
    ANTENNAPARTIALMETALAREA 31.4396 LAYER met2  ;
    ANTENNAPARTIALMETALSIDEAREA 156.919 LAYER met2  ;
    ANTENNAPARTIALCUTAREA 0.04 LAYER via2  ;
    ANTENNAPARTIALMETALAREA 0.255 LAYER met3  ;
    ANTENNAPARTIALMETALSIDEAREA 1.808 LAYER met3  ;
    ANTENNAPARTIALCUTAREA 0.04 LAYER via3  ;
    ANTENNAPARTIALMETALAREA 1.3998 LAYER met4  ;
    ANTENNAPARTIALMETALSIDEAREA 7.936 LAYER met4  ;
    ANTENNAMODEL OXIDE1 ;
    ANTENNAGATEAREA 0.126 LAYER met4  ;
    ANTENNAMAXAREACAR 24.9131 LAYER met4  ;
    ANTENNAMAXSIDEAREACAR 125.817 LAYER met4  ;
    ANTENNAMAXCUTCAR 1.04286 LAYER via4  ;
    PORT
      LAYER met2 ;
        RECT 858.980000 0.000000 859.120000 0.485000 ;
    END
  END la_data_in[14]
  PIN la_data_in[13]
    DIRECTION INPUT ;
    USE SIGNAL ;
    ANTENNAPARTIALMETALAREA 29.1758 LAYER met2  ;
    ANTENNAPARTIALMETALSIDEAREA 145.6 LAYER met2  ;
    ANTENNAPARTIALCUTAREA 0.04 LAYER via2  ;
    ANTENNAPARTIALMETALAREA 0.255 LAYER met3  ;
    ANTENNAPARTIALMETALSIDEAREA 1.808 LAYER met3  ;
    ANTENNAPARTIALCUTAREA 0.04 LAYER via3  ;
    ANTENNAPARTIALMETALAREA 4.1928 LAYER met4  ;
    ANTENNAPARTIALMETALSIDEAREA 22.832 LAYER met4  ;
    ANTENNAMODEL OXIDE1 ;
    ANTENNAGATEAREA 0.126 LAYER met4  ;
    ANTENNAMAXAREACAR 54.0079 LAYER met4  ;
    ANTENNAMAXSIDEAREACAR 269.024 LAYER met4  ;
    ANTENNAMAXCUTCAR 1.04286 LAYER via4  ;
    PORT
      LAYER met2 ;
        RECT 841.500000 0.000000 841.640000 0.485000 ;
    END
  END la_data_in[13]
  PIN la_data_in[12]
    DIRECTION INPUT ;
    USE SIGNAL ;
    ANTENNAPARTIALMETALAREA 0.4452 LAYER met2  ;
    ANTENNAPARTIALMETALSIDEAREA 2.065 LAYER met2  ;
    ANTENNAPARTIALCUTAREA 0.04 LAYER via2  ;
    ANTENNAPARTIALMETALAREA 92.515 LAYER met3  ;
    ANTENNAPARTIALMETALSIDEAREA 493.88 LAYER met3  ;
    ANTENNAPARTIALCUTAREA 0.04 LAYER via3  ;
    ANTENNAPARTIALMETALAREA 1.47985 LAYER met4  ;
    ANTENNAPARTIALMETALSIDEAREA 4.2 LAYER met4  ;
    ANTENNAPARTIALCUTAREA 0.64 LAYER via4  ;
    ANTENNAPARTIALMETALAREA 21.328 LAYER met5  ;
    ANTENNAPARTIALMETALSIDEAREA 35.832 LAYER met5  ;
    ANTENNAMODEL OXIDE1 ;
    ANTENNAGATEAREA 0.126 LAYER met5  ;
    ANTENNAMAXAREACAR 267.316 LAYER met5  ;
    ANTENNAMAXSIDEAREACAR 760.413 LAYER met5  ;
    PORT
      LAYER met2 ;
        RECT 824.020000 0.000000 824.160000 0.485000 ;
    END
  END la_data_in[12]
  PIN la_data_in[11]
    DIRECTION INPUT ;
    USE SIGNAL ;
    ANTENNAPARTIALMETALAREA 0.1099 LAYER met2  ;
    ANTENNAPARTIALMETALSIDEAREA 0.3885 LAYER met2  ;
    ANTENNAPARTIALCUTAREA 0.04 LAYER via2  ;
    ANTENNAPARTIALMETALAREA 116.389 LAYER met3  ;
    ANTENNAPARTIALMETALSIDEAREA 621.208 LAYER met3  ;
    ANTENNAPARTIALCUTAREA 0.04 LAYER via3  ;
    ANTENNAPARTIALMETALAREA 4.7964 LAYER met4  ;
    ANTENNAPARTIALMETALSIDEAREA 26.992 LAYER met4  ;
    ANTENNAMODEL OXIDE1 ;
    ANTENNAGATEAREA 0.126 LAYER met4  ;
    ANTENNAMAXAREACAR 56.8476 LAYER met4  ;
    ANTENNAMAXSIDEAREACAR 300.929 LAYER met4  ;
    ANTENNAMAXCUTCAR 1.04286 LAYER via4  ;
    PORT
      LAYER met2 ;
        RECT 806.540000 0.000000 806.680000 0.485000 ;
    END
  END la_data_in[11]
  PIN la_data_in[10]
    DIRECTION INPUT ;
    USE SIGNAL ;
    ANTENNAPARTIALMETALAREA 9.7802 LAYER met2  ;
    ANTENNAPARTIALMETALSIDEAREA 48.622 LAYER met2  ;
    ANTENNAPARTIALCUTAREA 0.04 LAYER via2  ;
    ANTENNAPARTIALMETALAREA 0.255 LAYER met3  ;
    ANTENNAPARTIALMETALSIDEAREA 1.808 LAYER met3  ;
    ANTENNAPARTIALCUTAREA 0.04 LAYER via3  ;
    ANTENNADIFFAREA 0.4347 LAYER met4  ;
    ANTENNAPARTIALMETALAREA 5.9748 LAYER met4  ;
    ANTENNAPARTIALMETALSIDEAREA 32.336 LAYER met4  ;
    ANTENNAMODEL OXIDE1 ;
    ANTENNAGATEAREA 0.126 LAYER met4  ;
    ANTENNAMAXAREACAR 209.785 LAYER met4  ;
    ANTENNAMAXSIDEAREACAR 999.579 LAYER met4  ;
    ANTENNAMAXCUTCAR 1.04286 LAYER via4  ;
    PORT
      LAYER met2 ;
        RECT 789.060000 0.000000 789.200000 0.485000 ;
    END
  END la_data_in[10]
  PIN la_data_in[9]
    DIRECTION INPUT ;
    USE SIGNAL ;
    ANTENNAPARTIALMETALAREA 19.404 LAYER met2  ;
    ANTENNAPARTIALMETALSIDEAREA 96.859 LAYER met2  ;
    ANTENNAPARTIALCUTAREA 0.04 LAYER via2  ;
    ANTENNAPARTIALMETALAREA 0.255 LAYER met3  ;
    ANTENNAPARTIALMETALSIDEAREA 1.808 LAYER met3  ;
    ANTENNAPARTIALCUTAREA 0.04 LAYER via3  ;
    ANTENNAPARTIALMETALAREA 3.9618 LAYER met4  ;
    ANTENNAPARTIALMETALSIDEAREA 21.6 LAYER met4  ;
    ANTENNAMODEL OXIDE1 ;
    ANTENNAGATEAREA 0.126 LAYER met4  ;
    ANTENNAMAXAREACAR 44.0266 LAYER met4  ;
    ANTENNAMAXSIDEAREACAR 227.762 LAYER met4  ;
    ANTENNAMAXCUTCAR 1.04286 LAYER via4  ;
    PORT
      LAYER met2 ;
        RECT 771.580000 0.000000 771.720000 0.485000 ;
    END
  END la_data_in[9]
  PIN la_data_in[8]
    DIRECTION INPUT ;
    USE SIGNAL ;
    ANTENNAPARTIALMETALAREA 21.2828 LAYER met2  ;
    ANTENNAPARTIALMETALSIDEAREA 106.253 LAYER met2  ;
    ANTENNAPARTIALCUTAREA 0.04 LAYER via2  ;
    ANTENNAPARTIALMETALAREA 0.2509 LAYER met3  ;
    ANTENNAPARTIALMETALSIDEAREA 1.808 LAYER met3  ;
    ANTENNAPARTIALCUTAREA 0.04 LAYER via3  ;
    ANTENNAPARTIALMETALAREA 4.1448 LAYER met4  ;
    ANTENNAPARTIALMETALSIDEAREA 22.576 LAYER met4  ;
    ANTENNAMODEL OXIDE1 ;
    ANTENNAGATEAREA 0.126 LAYER met4  ;
    ANTENNAMAXAREACAR 47.5722 LAYER met4  ;
    ANTENNAMAXSIDEAREACAR 238.317 LAYER met4  ;
    ANTENNAMAXCUTCAR 1.04286 LAYER via4  ;
    PORT
      LAYER met2 ;
        RECT 754.560000 0.000000 754.700000 0.485000 ;
    END
  END la_data_in[8]
  PIN la_data_in[7]
    DIRECTION INPUT ;
    USE SIGNAL ;
    ANTENNAPARTIALMETALAREA 24.1864 LAYER met2  ;
    ANTENNAPARTIALMETALSIDEAREA 120.771 LAYER met2  ;
    ANTENNAPARTIALCUTAREA 0.04 LAYER via2  ;
    ANTENNAPARTIALMETALAREA 0.676 LAYER met3  ;
    ANTENNAPARTIALMETALSIDEAREA 4.072 LAYER met3  ;
    ANTENNAPARTIALCUTAREA 0.04 LAYER via3  ;
    ANTENNAPARTIALMETALAREA 4.1448 LAYER met4  ;
    ANTENNAPARTIALMETALSIDEAREA 22.576 LAYER met4  ;
    ANTENNAMODEL OXIDE1 ;
    ANTENNAGATEAREA 0.126 LAYER met4  ;
    ANTENNAMAXAREACAR 55.5937 LAYER met4  ;
    ANTENNAMAXSIDEAREACAR 284.19 LAYER met4  ;
    ANTENNAMAXCUTCAR 1.04286 LAYER via4  ;
    PORT
      LAYER met2 ;
        RECT 737.080000 0.000000 737.220000 0.485000 ;
    END
  END la_data_in[7]
  PIN la_data_in[6]
    DIRECTION INPUT ;
    USE SIGNAL ;
    ANTENNAPARTIALMETALAREA 7.7896 LAYER met2  ;
    ANTENNAPARTIALMETALSIDEAREA 38.787 LAYER met2  ;
    ANTENNAPARTIALCUTAREA 0.04 LAYER via2  ;
    ANTENNAPARTIALMETALAREA 0.255 LAYER met3  ;
    ANTENNAPARTIALMETALSIDEAREA 1.808 LAYER met3  ;
    ANTENNAPARTIALCUTAREA 0.04 LAYER via3  ;
    ANTENNADIFFAREA 0.4347 LAYER met4  ;
    ANTENNAPARTIALMETALAREA 5.9748 LAYER met4  ;
    ANTENNAPARTIALMETALSIDEAREA 32.336 LAYER met4  ;
    ANTENNAMODEL OXIDE1 ;
    ANTENNAGATEAREA 0.126 LAYER met4  ;
    ANTENNAMAXAREACAR 172.967 LAYER met4  ;
    ANTENNAMAXSIDEAREACAR 813.317 LAYER met4  ;
    ANTENNAMAXCUTCAR 1.04286 LAYER via4  ;
    PORT
      LAYER met2 ;
        RECT 719.600000 0.000000 719.740000 0.485000 ;
    END
  END la_data_in[6]
  PIN la_data_in[5]
    DIRECTION INPUT ;
    USE SIGNAL ;
    ANTENNAPARTIALMETALAREA 12.572 LAYER met2  ;
    ANTENNAPARTIALMETALSIDEAREA 62.699 LAYER met2  ;
    ANTENNAPARTIALCUTAREA 0.04 LAYER via2  ;
    ANTENNAPARTIALMETALAREA 0.2509 LAYER met3  ;
    ANTENNAPARTIALMETALSIDEAREA 1.808 LAYER met3  ;
    ANTENNAPARTIALCUTAREA 0.04 LAYER via3  ;
    ANTENNAPARTIALMETALAREA 3.9618 LAYER met4  ;
    ANTENNAPARTIALMETALSIDEAREA 21.6 LAYER met4  ;
    ANTENNAMODEL OXIDE1 ;
    ANTENNAGATEAREA 0.126 LAYER met4  ;
    ANTENNAMAXAREACAR 52.0595 LAYER met4  ;
    ANTENNAMAXSIDEAREACAR 261.087 LAYER met4  ;
    ANTENNAMAXCUTCAR 1.04286 LAYER via4  ;
    PORT
      LAYER met2 ;
        RECT 702.120000 0.000000 702.260000 0.485000 ;
    END
  END la_data_in[5]
  PIN la_data_in[4]
    DIRECTION INPUT ;
    USE SIGNAL ;
    ANTENNAPARTIALMETALAREA 11.6326 LAYER met2  ;
    ANTENNAPARTIALMETALSIDEAREA 58.002 LAYER met2  ;
    ANTENNAPARTIALCUTAREA 0.04 LAYER via2  ;
    ANTENNAPARTIALMETALAREA 0.255 LAYER met3  ;
    ANTENNAPARTIALMETALSIDEAREA 1.808 LAYER met3  ;
    ANTENNAPARTIALCUTAREA 0.04 LAYER via3  ;
    ANTENNAPARTIALMETALAREA 4.5588 LAYER met4  ;
    ANTENNAPARTIALMETALSIDEAREA 24.784 LAYER met4  ;
    ANTENNAMODEL OXIDE1 ;
    ANTENNAGATEAREA 0.126 LAYER met4  ;
    ANTENNAMAXAREACAR 55.0762 LAYER met4  ;
    ANTENNAMAXSIDEAREACAR 281.405 LAYER met4  ;
    ANTENNAMAXCUTCAR 1.04286 LAYER via4  ;
    PORT
      LAYER met2 ;
        RECT 684.640000 0.000000 684.780000 0.485000 ;
    END
  END la_data_in[4]
  PIN la_data_in[3]
    DIRECTION INPUT ;
    USE SIGNAL ;
    ANTENNAPARTIALMETALAREA 8.9866 LAYER met2  ;
    ANTENNAPARTIALMETALSIDEAREA 44.772 LAYER met2  ;
    ANTENNAPARTIALCUTAREA 0.04 LAYER via2  ;
    ANTENNAPARTIALMETALAREA 0.2509 LAYER met3  ;
    ANTENNAPARTIALMETALSIDEAREA 1.808 LAYER met3  ;
    ANTENNAPARTIALCUTAREA 0.04 LAYER via3  ;
    ANTENNAPARTIALMETALAREA 3.9618 LAYER met4  ;
    ANTENNAPARTIALMETALSIDEAREA 21.6 LAYER met4  ;
    ANTENNAMODEL OXIDE1 ;
    ANTENNAGATEAREA 0.126 LAYER met4  ;
    ANTENNAMAXAREACAR 46.5123 LAYER met4  ;
    ANTENNAMAXSIDEAREACAR 239.817 LAYER met4  ;
    ANTENNAMAXCUTCAR 1.04286 LAYER via4  ;
    PORT
      LAYER met2 ;
        RECT 667.160000 0.000000 667.300000 0.485000 ;
    END
  END la_data_in[3]
  PIN la_data_in[2]
    DIRECTION INPUT ;
    USE SIGNAL ;
    ANTENNAPARTIALMETALAREA 8.729 LAYER met2  ;
    ANTENNAPARTIALMETALSIDEAREA 43.484 LAYER met2  ;
    ANTENNAPARTIALCUTAREA 0.04 LAYER via2  ;
    ANTENNAPARTIALMETALAREA 0.255 LAYER met3  ;
    ANTENNAPARTIALMETALSIDEAREA 1.808 LAYER met3  ;
    ANTENNAPARTIALCUTAREA 0.04 LAYER via3  ;
    ANTENNAPARTIALMETALAREA 3.9618 LAYER met4  ;
    ANTENNAPARTIALMETALSIDEAREA 21.6 LAYER met4  ;
    ANTENNAMODEL OXIDE1 ;
    ANTENNAGATEAREA 0.126 LAYER met4  ;
    ANTENNAMAXAREACAR 62.8064 LAYER met4  ;
    ANTENNAMAXSIDEAREACAR 319.413 LAYER met4  ;
    ANTENNAMAXCUTCAR 1.04286 LAYER via4  ;
    PORT
      LAYER met2 ;
        RECT 650.140000 0.000000 650.280000 0.485000 ;
    END
  END la_data_in[2]
  PIN la_data_in[1]
    DIRECTION INPUT ;
    USE SIGNAL ;
    ANTENNAPARTIALMETALAREA 14.5515 LAYER met2  ;
    ANTENNAPARTIALMETALSIDEAREA 72.6495 LAYER met2  ;
    ANTENNAMODEL OXIDE1 ;
    ANTENNAGATEAREA 0.315 LAYER met2  ;
    ANTENNAMAXAREACAR 47.3054 LAYER met2  ;
    ANTENNAMAXSIDEAREACAR 233.289 LAYER met2  ;
    ANTENNAMAXCUTCAR 0.163175 LAYER via2  ;
    PORT
      LAYER met2 ;
        RECT 632.660000 0.000000 632.800000 0.485000 ;
    END
  END la_data_in[1]
  PIN la_data_in[0]
    DIRECTION INPUT ;
    USE SIGNAL ;
    ANTENNAPARTIALMETALAREA 10.7435 LAYER met2  ;
    ANTENNAPARTIALMETALSIDEAREA 53.6095 LAYER met2  ;
    ANTENNAMODEL OXIDE1 ;
    ANTENNAGATEAREA 0.159 LAYER met2  ;
    ANTENNAMAXAREACAR 86.0808 LAYER met2  ;
    ANTENNAMAXSIDEAREACAR 426.019 LAYER met2  ;
    ANTENNAMAXCUTCAR 0.32327 LAYER via2  ;
    PORT
      LAYER met2 ;
        RECT 615.180000 0.000000 615.320000 0.485000 ;
    END
  END la_data_in[0]
  PIN la_data_out[127]
    DIRECTION OUTPUT ;
    USE SIGNAL ;
    ANTENNADIFFAREA 0.336 LAYER met2  ;
    ANTENNAPARTIALMETALAREA 4.4435 LAYER met2  ;
    ANTENNAPARTIALMETALSIDEAREA 22.1095 LAYER met2  ;
    PORT
      LAYER met2 ;
        RECT 2830.540000 0.000000 2830.680000 0.485000 ;
    END
  END la_data_out[127]
  PIN la_data_out[126]
    DIRECTION OUTPUT ;
    USE SIGNAL ;
    ANTENNADIFFAREA 0.336 LAYER met2  ;
    ANTENNAPARTIALMETALAREA 4.4435 LAYER met2  ;
    ANTENNAPARTIALMETALSIDEAREA 22.1095 LAYER met2  ;
    PORT
      LAYER met2 ;
        RECT 2813.520000 0.000000 2813.660000 0.485000 ;
    END
  END la_data_out[126]
  PIN la_data_out[125]
    DIRECTION OUTPUT ;
    USE SIGNAL ;
    ANTENNADIFFAREA 0.336 LAYER met2  ;
    ANTENNAPARTIALMETALAREA 4.4435 LAYER met2  ;
    ANTENNAPARTIALMETALSIDEAREA 22.1095 LAYER met2  ;
    PORT
      LAYER met2 ;
        RECT 2796.040000 0.000000 2796.180000 0.485000 ;
    END
  END la_data_out[125]
  PIN la_data_out[124]
    DIRECTION OUTPUT ;
    USE SIGNAL ;
    ANTENNADIFFAREA 0.336 LAYER met2  ;
    ANTENNAPARTIALMETALAREA 4.4435 LAYER met2  ;
    ANTENNAPARTIALMETALSIDEAREA 22.1095 LAYER met2  ;
    PORT
      LAYER met2 ;
        RECT 2778.560000 0.000000 2778.700000 0.485000 ;
    END
  END la_data_out[124]
  PIN la_data_out[123]
    DIRECTION OUTPUT ;
    USE SIGNAL ;
    ANTENNADIFFAREA 0.336 LAYER met2  ;
    ANTENNAPARTIALMETALAREA 4.4435 LAYER met2  ;
    ANTENNAPARTIALMETALSIDEAREA 22.1095 LAYER met2  ;
    PORT
      LAYER met2 ;
        RECT 2761.080000 0.000000 2761.220000 0.485000 ;
    END
  END la_data_out[123]
  PIN la_data_out[122]
    DIRECTION OUTPUT ;
    USE SIGNAL ;
    ANTENNADIFFAREA 0.336 LAYER met2  ;
    ANTENNAPARTIALMETALAREA 4.4435 LAYER met2  ;
    ANTENNAPARTIALMETALSIDEAREA 22.1095 LAYER met2  ;
    PORT
      LAYER met2 ;
        RECT 2743.600000 0.000000 2743.740000 0.485000 ;
    END
  END la_data_out[122]
  PIN la_data_out[121]
    DIRECTION OUTPUT ;
    USE SIGNAL ;
    ANTENNADIFFAREA 0.336 LAYER met2  ;
    ANTENNAPARTIALMETALAREA 4.4435 LAYER met2  ;
    ANTENNAPARTIALMETALSIDEAREA 22.1095 LAYER met2  ;
    PORT
      LAYER met2 ;
        RECT 2726.580000 0.000000 2726.720000 0.485000 ;
    END
  END la_data_out[121]
  PIN la_data_out[120]
    DIRECTION OUTPUT ;
    USE SIGNAL ;
    ANTENNADIFFAREA 0.336 LAYER met2  ;
    ANTENNAPARTIALMETALAREA 4.4435 LAYER met2  ;
    ANTENNAPARTIALMETALSIDEAREA 22.1095 LAYER met2  ;
    PORT
      LAYER met2 ;
        RECT 2709.100000 0.000000 2709.240000 0.485000 ;
    END
  END la_data_out[120]
  PIN la_data_out[119]
    DIRECTION OUTPUT ;
    USE SIGNAL ;
    ANTENNADIFFAREA 0.336 LAYER met2  ;
    ANTENNAPARTIALMETALAREA 4.4435 LAYER met2  ;
    ANTENNAPARTIALMETALSIDEAREA 22.1095 LAYER met2  ;
    PORT
      LAYER met2 ;
        RECT 2691.620000 0.000000 2691.760000 0.485000 ;
    END
  END la_data_out[119]
  PIN la_data_out[118]
    DIRECTION OUTPUT ;
    USE SIGNAL ;
    ANTENNADIFFAREA 0.336 LAYER met2  ;
    ANTENNAPARTIALMETALAREA 4.4435 LAYER met2  ;
    ANTENNAPARTIALMETALSIDEAREA 22.1095 LAYER met2  ;
    PORT
      LAYER met2 ;
        RECT 2674.140000 0.000000 2674.280000 0.485000 ;
    END
  END la_data_out[118]
  PIN la_data_out[117]
    DIRECTION OUTPUT ;
    USE SIGNAL ;
    ANTENNADIFFAREA 0.336 LAYER met2  ;
    ANTENNAPARTIALMETALAREA 4.8243 LAYER met2  ;
    ANTENNAPARTIALMETALSIDEAREA 24.0135 LAYER met2  ;
    PORT
      LAYER met2 ;
        RECT 2656.660000 0.000000 2656.800000 0.485000 ;
    END
  END la_data_out[117]
  PIN la_data_out[116]
    DIRECTION OUTPUT ;
    USE SIGNAL ;
    ANTENNADIFFAREA 0.336 LAYER met2  ;
    ANTENNAPARTIALMETALAREA 4.4435 LAYER met2  ;
    ANTENNAPARTIALMETALSIDEAREA 22.1095 LAYER met2  ;
    PORT
      LAYER met2 ;
        RECT 2639.180000 0.000000 2639.320000 0.485000 ;
    END
  END la_data_out[116]
  PIN la_data_out[115]
    DIRECTION OUTPUT ;
    USE SIGNAL ;
    ANTENNADIFFAREA 0.336 LAYER met2  ;
    ANTENNAPARTIALMETALAREA 4.4435 LAYER met2  ;
    ANTENNAPARTIALMETALSIDEAREA 22.1095 LAYER met2  ;
    PORT
      LAYER met2 ;
        RECT 2622.160000 0.000000 2622.300000 0.485000 ;
    END
  END la_data_out[115]
  PIN la_data_out[114]
    DIRECTION OUTPUT ;
    USE SIGNAL ;
    ANTENNADIFFAREA 0.336 LAYER met2  ;
    ANTENNAPARTIALMETALAREA 4.4435 LAYER met2  ;
    ANTENNAPARTIALMETALSIDEAREA 22.1095 LAYER met2  ;
    PORT
      LAYER met2 ;
        RECT 2604.680000 0.000000 2604.820000 0.485000 ;
    END
  END la_data_out[114]
  PIN la_data_out[113]
    DIRECTION OUTPUT ;
    USE SIGNAL ;
    ANTENNADIFFAREA 0.336 LAYER met2  ;
    ANTENNAPARTIALMETALAREA 4.5079 LAYER met2  ;
    ANTENNAPARTIALMETALSIDEAREA 22.4315 LAYER met2  ;
    PORT
      LAYER met2 ;
        RECT 2587.200000 0.000000 2587.340000 0.485000 ;
    END
  END la_data_out[113]
  PIN la_data_out[112]
    DIRECTION OUTPUT ;
    USE SIGNAL ;
    ANTENNADIFFAREA 0.336 LAYER met2  ;
    ANTENNAPARTIALMETALAREA 4.4435 LAYER met2  ;
    ANTENNAPARTIALMETALSIDEAREA 22.1095 LAYER met2  ;
    PORT
      LAYER met2 ;
        RECT 2569.720000 0.000000 2569.860000 0.485000 ;
    END
  END la_data_out[112]
  PIN la_data_out[111]
    DIRECTION OUTPUT ;
    USE SIGNAL ;
    ANTENNADIFFAREA 0.336 LAYER met2  ;
    ANTENNAPARTIALMETALAREA 4.4435 LAYER met2  ;
    ANTENNAPARTIALMETALSIDEAREA 22.1095 LAYER met2  ;
    PORT
      LAYER met2 ;
        RECT 2552.240000 0.000000 2552.380000 0.485000 ;
    END
  END la_data_out[111]
  PIN la_data_out[110]
    DIRECTION OUTPUT ;
    USE SIGNAL ;
    ANTENNADIFFAREA 0.336 LAYER met2  ;
    ANTENNAPARTIALMETALAREA 4.4435 LAYER met2  ;
    ANTENNAPARTIALMETALSIDEAREA 22.1095 LAYER met2  ;
    PORT
      LAYER met2 ;
        RECT 2534.760000 0.000000 2534.900000 0.485000 ;
    END
  END la_data_out[110]
  PIN la_data_out[109]
    DIRECTION OUTPUT ;
    USE SIGNAL ;
    ANTENNADIFFAREA 0.336 LAYER met2  ;
    ANTENNAPARTIALMETALAREA 4.7256 LAYER met2  ;
    ANTENNAPARTIALMETALSIDEAREA 23.52 LAYER met2  ;
    PORT
      LAYER met2 ;
        RECT 2517.740000 0.000000 2517.880000 0.485000 ;
    END
  END la_data_out[109]
  PIN la_data_out[108]
    DIRECTION OUTPUT ;
    USE SIGNAL ;
    ANTENNADIFFAREA 0.336 LAYER met2  ;
    ANTENNAPARTIALMETALAREA 4.4435 LAYER met2  ;
    ANTENNAPARTIALMETALSIDEAREA 22.1095 LAYER met2  ;
    PORT
      LAYER met2 ;
        RECT 2500.260000 0.000000 2500.400000 0.485000 ;
    END
  END la_data_out[108]
  PIN la_data_out[107]
    DIRECTION OUTPUT ;
    USE SIGNAL ;
    ANTENNADIFFAREA 0.336 LAYER met2  ;
    ANTENNAPARTIALMETALAREA 4.4435 LAYER met2  ;
    ANTENNAPARTIALMETALSIDEAREA 22.1095 LAYER met2  ;
    PORT
      LAYER met2 ;
        RECT 2482.780000 0.000000 2482.920000 0.485000 ;
    END
  END la_data_out[107]
  PIN la_data_out[106]
    DIRECTION OUTPUT ;
    USE SIGNAL ;
    ANTENNADIFFAREA 0.336 LAYER met2  ;
    ANTENNAPARTIALMETALAREA 4.4435 LAYER met2  ;
    ANTENNAPARTIALMETALSIDEAREA 22.1095 LAYER met2  ;
    PORT
      LAYER met2 ;
        RECT 2465.300000 0.000000 2465.440000 0.485000 ;
    END
  END la_data_out[106]
  PIN la_data_out[105]
    DIRECTION OUTPUT ;
    USE SIGNAL ;
    ANTENNADIFFAREA 0.336 LAYER met2  ;
    ANTENNAPARTIALMETALAREA 4.5079 LAYER met2  ;
    ANTENNAPARTIALMETALSIDEAREA 22.4315 LAYER met2  ;
    PORT
      LAYER met2 ;
        RECT 2447.820000 0.000000 2447.960000 0.485000 ;
    END
  END la_data_out[105]
  PIN la_data_out[104]
    DIRECTION OUTPUT ;
    USE SIGNAL ;
    ANTENNADIFFAREA 0.336 LAYER met2  ;
    ANTENNAPARTIALMETALAREA 4.4435 LAYER met2  ;
    ANTENNAPARTIALMETALSIDEAREA 22.1095 LAYER met2  ;
    PORT
      LAYER met2 ;
        RECT 2430.340000 0.000000 2430.480000 0.485000 ;
    END
  END la_data_out[104]
  PIN la_data_out[103]
    DIRECTION OUTPUT ;
    USE SIGNAL ;
    ANTENNADIFFAREA 0.336 LAYER met2  ;
    ANTENNAPARTIALMETALAREA 4.4435 LAYER met2  ;
    ANTENNAPARTIALMETALSIDEAREA 22.1095 LAYER met2  ;
    PORT
      LAYER met2 ;
        RECT 2413.320000 0.000000 2413.460000 0.485000 ;
    END
  END la_data_out[103]
  PIN la_data_out[102]
    DIRECTION OUTPUT ;
    USE SIGNAL ;
    ANTENNADIFFAREA 0.336 LAYER met2  ;
    ANTENNAPARTIALMETALAREA 4.4435 LAYER met2  ;
    ANTENNAPARTIALMETALSIDEAREA 22.1095 LAYER met2  ;
    PORT
      LAYER met2 ;
        RECT 2395.840000 0.000000 2395.980000 0.485000 ;
    END
  END la_data_out[102]
  PIN la_data_out[101]
    DIRECTION OUTPUT ;
    USE SIGNAL ;
    ANTENNADIFFAREA 0.336 LAYER met2  ;
    ANTENNAPARTIALMETALAREA 4.4435 LAYER met2  ;
    ANTENNAPARTIALMETALSIDEAREA 22.1095 LAYER met2  ;
    PORT
      LAYER met2 ;
        RECT 2378.360000 0.000000 2378.500000 0.485000 ;
    END
  END la_data_out[101]
  PIN la_data_out[100]
    DIRECTION OUTPUT ;
    USE SIGNAL ;
    ANTENNADIFFAREA 0.336 LAYER met2  ;
    ANTENNAPARTIALMETALAREA 4.4435 LAYER met2  ;
    ANTENNAPARTIALMETALSIDEAREA 22.1095 LAYER met2  ;
    PORT
      LAYER met2 ;
        RECT 2360.880000 0.000000 2361.020000 0.485000 ;
    END
  END la_data_out[100]
  PIN la_data_out[99]
    DIRECTION OUTPUT ;
    USE SIGNAL ;
    ANTENNADIFFAREA 0.336 LAYER met2  ;
    ANTENNAPARTIALMETALAREA 4.4435 LAYER met2  ;
    ANTENNAPARTIALMETALSIDEAREA 22.1095 LAYER met2  ;
    PORT
      LAYER met2 ;
        RECT 2343.400000 0.000000 2343.540000 0.485000 ;
    END
  END la_data_out[99]
  PIN la_data_out[98]
    DIRECTION OUTPUT ;
    USE SIGNAL ;
    ANTENNADIFFAREA 0.336 LAYER met2  ;
    ANTENNAPARTIALMETALAREA 4.4435 LAYER met2  ;
    ANTENNAPARTIALMETALSIDEAREA 22.1095 LAYER met2  ;
    PORT
      LAYER met2 ;
        RECT 2326.380000 0.000000 2326.520000 0.485000 ;
    END
  END la_data_out[98]
  PIN la_data_out[97]
    DIRECTION OUTPUT ;
    USE SIGNAL ;
    ANTENNADIFFAREA 0.336 LAYER met2  ;
    ANTENNAPARTIALMETALAREA 4.8243 LAYER met2  ;
    ANTENNAPARTIALMETALSIDEAREA 24.0135 LAYER met2  ;
    PORT
      LAYER met2 ;
        RECT 2308.900000 0.000000 2309.040000 0.485000 ;
    END
  END la_data_out[97]
  PIN la_data_out[96]
    DIRECTION OUTPUT ;
    USE SIGNAL ;
    ANTENNADIFFAREA 0.336 LAYER met2  ;
    ANTENNAPARTIALMETALAREA 4.4435 LAYER met2  ;
    ANTENNAPARTIALMETALSIDEAREA 22.1095 LAYER met2  ;
    PORT
      LAYER met2 ;
        RECT 2291.420000 0.000000 2291.560000 0.485000 ;
    END
  END la_data_out[96]
  PIN la_data_out[95]
    DIRECTION OUTPUT ;
    USE SIGNAL ;
    ANTENNADIFFAREA 0.336 LAYER met2  ;
    ANTENNAPARTIALMETALAREA 4.4435 LAYER met2  ;
    ANTENNAPARTIALMETALSIDEAREA 22.1095 LAYER met2  ;
    PORT
      LAYER met2 ;
        RECT 2273.940000 0.000000 2274.080000 0.485000 ;
    END
  END la_data_out[95]
  PIN la_data_out[94]
    DIRECTION OUTPUT ;
    USE SIGNAL ;
    ANTENNADIFFAREA 0.336 LAYER met2  ;
    ANTENNAPARTIALMETALAREA 4.4435 LAYER met2  ;
    ANTENNAPARTIALMETALSIDEAREA 22.1095 LAYER met2  ;
    PORT
      LAYER met2 ;
        RECT 2256.460000 0.000000 2256.600000 0.485000 ;
    END
  END la_data_out[94]
  PIN la_data_out[93]
    DIRECTION OUTPUT ;
    USE SIGNAL ;
    ANTENNADIFFAREA 0.336 LAYER met2  ;
    ANTENNAPARTIALMETALAREA 4.8243 LAYER met2  ;
    ANTENNAPARTIALMETALSIDEAREA 24.0135 LAYER met2  ;
    PORT
      LAYER met2 ;
        RECT 2238.980000 0.000000 2239.120000 0.485000 ;
    END
  END la_data_out[93]
  PIN la_data_out[92]
    DIRECTION OUTPUT ;
    USE SIGNAL ;
    ANTENNADIFFAREA 0.336 LAYER met2  ;
    ANTENNAPARTIALMETALAREA 4.4435 LAYER met2  ;
    ANTENNAPARTIALMETALSIDEAREA 22.1095 LAYER met2  ;
    PORT
      LAYER met2 ;
        RECT 2221.960000 0.000000 2222.100000 0.485000 ;
    END
  END la_data_out[92]
  PIN la_data_out[91]
    DIRECTION OUTPUT ;
    USE SIGNAL ;
    ANTENNADIFFAREA 0.336 LAYER met2  ;
    ANTENNAPARTIALMETALAREA 4.4435 LAYER met2  ;
    ANTENNAPARTIALMETALSIDEAREA 22.1095 LAYER met2  ;
    PORT
      LAYER met2 ;
        RECT 2204.480000 0.000000 2204.620000 0.485000 ;
    END
  END la_data_out[91]
  PIN la_data_out[90]
    DIRECTION OUTPUT ;
    USE SIGNAL ;
    ANTENNADIFFAREA 0.336 LAYER met2  ;
    ANTENNAPARTIALMETALAREA 4.4435 LAYER met2  ;
    ANTENNAPARTIALMETALSIDEAREA 22.1095 LAYER met2  ;
    PORT
      LAYER met2 ;
        RECT 2187.000000 0.000000 2187.140000 0.485000 ;
    END
  END la_data_out[90]
  PIN la_data_out[89]
    DIRECTION OUTPUT ;
    USE SIGNAL ;
    ANTENNADIFFAREA 0.336 LAYER met2  ;
    ANTENNAPARTIALMETALAREA 4.4435 LAYER met2  ;
    ANTENNAPARTIALMETALSIDEAREA 22.1095 LAYER met2  ;
    PORT
      LAYER met2 ;
        RECT 2169.520000 0.000000 2169.660000 0.485000 ;
    END
  END la_data_out[89]
  PIN la_data_out[88]
    DIRECTION OUTPUT ;
    USE SIGNAL ;
    ANTENNADIFFAREA 0.336 LAYER met2  ;
    ANTENNAPARTIALMETALAREA 4.4435 LAYER met2  ;
    ANTENNAPARTIALMETALSIDEAREA 22.1095 LAYER met2  ;
    PORT
      LAYER met2 ;
        RECT 2152.040000 0.000000 2152.180000 0.485000 ;
    END
  END la_data_out[88]
  PIN la_data_out[87]
    DIRECTION OUTPUT ;
    USE SIGNAL ;
    ANTENNADIFFAREA 0.336 LAYER met2  ;
    ANTENNAPARTIALMETALAREA 4.4435 LAYER met2  ;
    ANTENNAPARTIALMETALSIDEAREA 22.1095 LAYER met2  ;
    PORT
      LAYER met2 ;
        RECT 2134.560000 0.000000 2134.700000 0.485000 ;
    END
  END la_data_out[87]
  PIN la_data_out[86]
    DIRECTION OUTPUT ;
    USE SIGNAL ;
    ANTENNADIFFAREA 0.336 LAYER met2  ;
    ANTENNAPARTIALMETALAREA 4.4435 LAYER met2  ;
    ANTENNAPARTIALMETALSIDEAREA 22.1095 LAYER met2  ;
    PORT
      LAYER met2 ;
        RECT 2117.540000 0.000000 2117.680000 0.485000 ;
    END
  END la_data_out[86]
  PIN la_data_out[85]
    DIRECTION OUTPUT ;
    USE SIGNAL ;
    ANTENNADIFFAREA 0.336 LAYER met2  ;
    ANTENNAPARTIALMETALAREA 4.4435 LAYER met2  ;
    ANTENNAPARTIALMETALSIDEAREA 22.1095 LAYER met2  ;
    PORT
      LAYER met2 ;
        RECT 2100.060000 0.000000 2100.200000 0.485000 ;
    END
  END la_data_out[85]
  PIN la_data_out[84]
    DIRECTION OUTPUT ;
    USE SIGNAL ;
    ANTENNADIFFAREA 0.336 LAYER met2  ;
    ANTENNAPARTIALMETALAREA 4.4435 LAYER met2  ;
    ANTENNAPARTIALMETALSIDEAREA 22.1095 LAYER met2  ;
    PORT
      LAYER met2 ;
        RECT 2082.580000 0.000000 2082.720000 0.485000 ;
    END
  END la_data_out[84]
  PIN la_data_out[83]
    DIRECTION OUTPUT ;
    USE SIGNAL ;
    ANTENNADIFFAREA 0.336 LAYER met2  ;
    ANTENNAPARTIALMETALAREA 4.4435 LAYER met2  ;
    ANTENNAPARTIALMETALSIDEAREA 22.1095 LAYER met2  ;
    PORT
      LAYER met2 ;
        RECT 2065.100000 0.000000 2065.240000 0.485000 ;
    END
  END la_data_out[83]
  PIN la_data_out[82]
    DIRECTION OUTPUT ;
    USE SIGNAL ;
    ANTENNADIFFAREA 0.336 LAYER met2  ;
    ANTENNAPARTIALMETALAREA 4.4435 LAYER met2  ;
    ANTENNAPARTIALMETALSIDEAREA 22.1095 LAYER met2  ;
    PORT
      LAYER met2 ;
        RECT 2047.620000 0.000000 2047.760000 0.485000 ;
    END
  END la_data_out[82]
  PIN la_data_out[81]
    DIRECTION OUTPUT ;
    USE SIGNAL ;
    ANTENNADIFFAREA 0.336 LAYER met2  ;
    ANTENNAPARTIALMETALAREA 4.4435 LAYER met2  ;
    ANTENNAPARTIALMETALSIDEAREA 22.1095 LAYER met2  ;
    PORT
      LAYER met2 ;
        RECT 2030.140000 0.000000 2030.280000 0.485000 ;
    END
  END la_data_out[81]
  PIN la_data_out[80]
    DIRECTION OUTPUT ;
    USE SIGNAL ;
    ANTENNADIFFAREA 0.336 LAYER met2  ;
    ANTENNAPARTIALMETALAREA 4.4435 LAYER met2  ;
    ANTENNAPARTIALMETALSIDEAREA 22.1095 LAYER met2  ;
    PORT
      LAYER met2 ;
        RECT 2013.120000 0.000000 2013.260000 0.485000 ;
    END
  END la_data_out[80]
  PIN la_data_out[79]
    DIRECTION OUTPUT ;
    USE SIGNAL ;
    ANTENNADIFFAREA 0.336 LAYER met2  ;
    ANTENNAPARTIALMETALAREA 4.4435 LAYER met2  ;
    ANTENNAPARTIALMETALSIDEAREA 22.1095 LAYER met2  ;
    PORT
      LAYER met2 ;
        RECT 1995.640000 0.000000 1995.780000 0.485000 ;
    END
  END la_data_out[79]
  PIN la_data_out[78]
    DIRECTION OUTPUT ;
    USE SIGNAL ;
    ANTENNADIFFAREA 0.336 LAYER met2  ;
    ANTENNAPARTIALMETALAREA 4.4435 LAYER met2  ;
    ANTENNAPARTIALMETALSIDEAREA 22.1095 LAYER met2  ;
    PORT
      LAYER met2 ;
        RECT 1978.160000 0.000000 1978.300000 0.485000 ;
    END
  END la_data_out[78]
  PIN la_data_out[77]
    DIRECTION OUTPUT ;
    USE SIGNAL ;
    ANTENNADIFFAREA 0.336 LAYER met2  ;
    ANTENNAPARTIALMETALAREA 16.2959 LAYER met2  ;
    ANTENNAPARTIALMETALSIDEAREA 81.3715 LAYER met2  ;
    PORT
      LAYER met2 ;
        RECT 1960.680000 0.000000 1960.820000 0.485000 ;
    END
  END la_data_out[77]
  PIN la_data_out[76]
    DIRECTION OUTPUT ;
    USE SIGNAL ;
    ANTENNADIFFAREA 0.336 LAYER met2  ;
    ANTENNAPARTIALMETALAREA 5.2527 LAYER met2  ;
    ANTENNAPARTIALMETALSIDEAREA 26.1555 LAYER met2  ;
    PORT
      LAYER met2 ;
        RECT 1943.200000 0.000000 1943.340000 0.485000 ;
    END
  END la_data_out[76]
  PIN la_data_out[75]
    DIRECTION OUTPUT ;
    USE SIGNAL ;
    ANTENNADIFFAREA 0.4455 LAYER met2  ;
    ANTENNAPARTIALMETALAREA 6.3951 LAYER met2  ;
    ANTENNAPARTIALMETALSIDEAREA 31.8675 LAYER met2  ;
    PORT
      LAYER met2 ;
        RECT 1926.180000 0.000000 1926.320000 0.485000 ;
    END
  END la_data_out[75]
  PIN la_data_out[74]
    DIRECTION OUTPUT ;
    USE SIGNAL ;
    ANTENNADIFFAREA 0.336 LAYER met2  ;
    ANTENNAPARTIALMETALAREA 5.6335 LAYER met2  ;
    ANTENNAPARTIALMETALSIDEAREA 28.0595 LAYER met2  ;
    PORT
      LAYER met2 ;
        RECT 1908.700000 0.000000 1908.840000 0.485000 ;
    END
  END la_data_out[74]
  PIN la_data_out[73]
    DIRECTION OUTPUT ;
    USE SIGNAL ;
    ANTENNADIFFAREA 0.336 LAYER met2  ;
    ANTENNAPARTIALMETALAREA 7.5851 LAYER met2  ;
    ANTENNAPARTIALMETALSIDEAREA 37.8175 LAYER met2  ;
    PORT
      LAYER met2 ;
        RECT 1891.220000 0.000000 1891.360000 0.485000 ;
    END
  END la_data_out[73]
  PIN la_data_out[72]
    DIRECTION OUTPUT ;
    USE SIGNAL ;
    ANTENNADIFFAREA 0.336 LAYER met2  ;
    ANTENNAPARTIALMETALAREA 9.0607 LAYER met2  ;
    ANTENNAPARTIALMETALSIDEAREA 45.1955 LAYER met2  ;
    PORT
      LAYER met2 ;
        RECT 1873.740000 0.000000 1873.880000 0.485000 ;
    END
  END la_data_out[72]
  PIN la_data_out[71]
    DIRECTION OUTPUT ;
    USE SIGNAL ;
    ANTENNADIFFAREA 0.336 LAYER met2  ;
    ANTENNAPARTIALMETALAREA 7.9659 LAYER met2  ;
    ANTENNAPARTIALMETALSIDEAREA 39.7215 LAYER met2  ;
    PORT
      LAYER met2 ;
        RECT 1856.260000 0.000000 1856.400000 0.485000 ;
    END
  END la_data_out[71]
  PIN la_data_out[70]
    DIRECTION OUTPUT ;
    USE SIGNAL ;
    ANTENNADIFFAREA 0.4455 LAYER met2  ;
    ANTENNAPARTIALMETALAREA 11.1127 LAYER met2  ;
    ANTENNAPARTIALMETALSIDEAREA 55.2195 LAYER met2  ;
    PORT
      LAYER met2 ;
        RECT 1838.780000 0.000000 1838.920000 0.485000 ;
    END
  END la_data_out[70]
  PIN la_data_out[69]
    DIRECTION OUTPUT ;
    USE SIGNAL ;
    ANTENNADIFFAREA 0.4455 LAYER met2  ;
    ANTENNAPARTIALMETALAREA 8.7275 LAYER met2  ;
    ANTENNAPARTIALMETALSIDEAREA 43.5295 LAYER met2  ;
    PORT
      LAYER met2 ;
        RECT 1821.760000 0.000000 1821.900000 0.485000 ;
    END
  END la_data_out[69]
  PIN la_data_out[68]
    DIRECTION OUTPUT ;
    USE SIGNAL ;
    ANTENNADIFFAREA 0.336 LAYER met2  ;
    ANTENNAPARTIALMETALAREA 6.8445 LAYER met2  ;
    ANTENNAPARTIALMETALSIDEAREA 34.1145 LAYER met2  ;
    PORT
      LAYER met2 ;
        RECT 1804.280000 0.000000 1804.420000 0.485000 ;
    END
  END la_data_out[68]
  PIN la_data_out[67]
    DIRECTION OUTPUT ;
    USE SIGNAL ;
    ANTENNADIFFAREA 0.336 LAYER met2  ;
    ANTENNAPARTIALMETALAREA 5.7075 LAYER met2  ;
    ANTENNAPARTIALMETALSIDEAREA 28.3115 LAYER met2  ;
    PORT
      LAYER met2 ;
        RECT 1786.800000 0.000000 1786.940000 0.485000 ;
    END
  END la_data_out[67]
  PIN la_data_out[66]
    DIRECTION OUTPUT ;
    USE SIGNAL ;
    ANTENNADIFFAREA 0.336 LAYER met2  ;
    ANTENNAPARTIALMETALAREA 9.9703 LAYER met2  ;
    ANTENNAPARTIALMETALSIDEAREA 49.5075 LAYER met2  ;
    PORT
      LAYER met2 ;
        RECT 1769.320000 0.000000 1769.460000 0.485000 ;
    END
  END la_data_out[66]
  PIN la_data_out[65]
    DIRECTION OUTPUT ;
    USE SIGNAL ;
    ANTENNADIFFAREA 0.4455 LAYER met2  ;
    ANTENNAPARTIALMETALAREA 23.6051 LAYER met2  ;
    ANTENNAPARTIALMETALSIDEAREA 117.8 LAYER met2  ;
    PORT
      LAYER met2 ;
        RECT 1751.840000 0.000000 1751.980000 0.485000 ;
    END
  END la_data_out[65]
  PIN la_data_out[64]
    DIRECTION OUTPUT ;
    USE SIGNAL ;
    ANTENNADIFFAREA 0.336 LAYER met2  ;
    ANTENNAPARTIALMETALAREA 40.4415 LAYER met2  ;
    ANTENNAPARTIALMETALSIDEAREA 201.982 LAYER met2  ;
    PORT
      LAYER met2 ;
        RECT 1734.360000 0.000000 1734.500000 0.485000 ;
    END
  END la_data_out[64]
  PIN la_data_out[63]
    DIRECTION OUTPUT ;
    USE SIGNAL ;
    ANTENNAPARTIALMETALAREA 36.0624 LAYER met2  ;
    ANTENNAPARTIALMETALSIDEAREA 180.033 LAYER met2  ;
    ANTENNAPARTIALCUTAREA 0.04 LAYER via2  ;
    ANTENNADIFFAREA 0.336 LAYER met3  ;
    ANTENNAPARTIALMETALAREA 8.9508 LAYER met3  ;
    ANTENNAPARTIALMETALSIDEAREA 48.208 LAYER met3  ;
    PORT
      LAYER met2 ;
        RECT 1717.340000 0.000000 1717.480000 0.485000 ;
    END
  END la_data_out[63]
  PIN la_data_out[62]
    DIRECTION OUTPUT ;
    USE SIGNAL ;
    ANTENNADIFFAREA 0.336 LAYER met2  ;
    ANTENNAPARTIALMETALAREA 30.4975 LAYER met2  ;
    ANTENNAPARTIALMETALSIDEAREA 152.38 LAYER met2  ;
    PORT
      LAYER met2 ;
        RECT 1699.860000 0.000000 1700.000000 0.485000 ;
    END
  END la_data_out[62]
  PIN la_data_out[61]
    DIRECTION OUTPUT ;
    USE SIGNAL ;
    ANTENNADIFFAREA 0.336 LAYER met2  ;
    ANTENNAPARTIALMETALAREA 32.6351 LAYER met2  ;
    ANTENNAPARTIALMETALSIDEAREA 162.95 LAYER met2  ;
    PORT
      LAYER met2 ;
        RECT 1682.380000 0.000000 1682.520000 0.485000 ;
    END
  END la_data_out[61]
  PIN la_data_out[60]
    DIRECTION OUTPUT ;
    USE SIGNAL ;
    ANTENNADIFFAREA 0.336 LAYER met2  ;
    ANTENNAPARTIALMETALAREA 18.9615 LAYER met2  ;
    ANTENNAPARTIALMETALSIDEAREA 94.6995 LAYER met2  ;
    PORT
      LAYER met2 ;
        RECT 1664.900000 0.000000 1665.040000 0.485000 ;
    END
  END la_data_out[60]
  PIN la_data_out[59]
    DIRECTION OUTPUT ;
    USE SIGNAL ;
    ANTENNAPARTIALMETALAREA 61.6154 LAYER met2  ;
    ANTENNAPARTIALMETALSIDEAREA 307.916 LAYER met2  ;
    ANTENNAPARTIALCUTAREA 0.04 LAYER via2  ;
    ANTENNADIFFAREA 0.4455 LAYER met3  ;
    ANTENNAPARTIALMETALAREA 20.5428 LAYER met3  ;
    ANTENNAPARTIALMETALSIDEAREA 110.032 LAYER met3  ;
    PORT
      LAYER met2 ;
        RECT 1647.420000 0.000000 1647.560000 0.485000 ;
    END
  END la_data_out[59]
  PIN la_data_out[58]
    DIRECTION OUTPUT ;
    USE SIGNAL ;
    ANTENNADIFFAREA 0.6626 LAYER met2  ;
    ANTENNAPARTIALMETALAREA 77.9419 LAYER met2  ;
    ANTENNAPARTIALMETALSIDEAREA 389.483 LAYER met2  ;
    PORT
      LAYER met2 ;
        RECT 1629.940000 0.000000 1630.080000 0.485000 ;
    END
  END la_data_out[58]
  PIN la_data_out[57]
    DIRECTION OUTPUT ;
    USE SIGNAL ;
    ANTENNAPARTIALMETALAREA 58.1336 LAYER met2  ;
    ANTENNAPARTIALMETALSIDEAREA 290.507 LAYER met2  ;
    ANTENNAPARTIALCUTAREA 0.04 LAYER via2  ;
    ANTENNAPARTIALMETALAREA 2.608 LAYER met3  ;
    ANTENNAPARTIALMETALSIDEAREA 14.376 LAYER met3  ;
    ANTENNAPARTIALCUTAREA 0.04 LAYER via3  ;
    ANTENNADIFFAREA 0.6626 LAYER met4  ;
    ANTENNAPARTIALMETALAREA 37.5228 LAYER met4  ;
    ANTENNAPARTIALMETALSIDEAREA 200.592 LAYER met4  ;
    PORT
      LAYER met2 ;
        RECT 1612.920000 0.000000 1613.060000 0.485000 ;
    END
  END la_data_out[57]
  PIN la_data_out[56]
    DIRECTION OUTPUT ;
    USE SIGNAL ;
    ANTENNADIFFAREA 0.336 LAYER met2  ;
    ANTENNAPARTIALMETALAREA 49.3779 LAYER met2  ;
    ANTENNAPARTIALMETALSIDEAREA 246.782 LAYER met2  ;
    PORT
      LAYER met2 ;
        RECT 1595.440000 0.000000 1595.580000 0.485000 ;
    END
  END la_data_out[56]
  PIN la_data_out[55]
    DIRECTION OUTPUT ;
    USE SIGNAL ;
    ANTENNAPARTIALMETALAREA 52.1976 LAYER met2  ;
    ANTENNAPARTIALMETALSIDEAREA 260.827 LAYER met2  ;
    ANTENNAPARTIALCUTAREA 0.04 LAYER via2  ;
    ANTENNAPARTIALMETALAREA 0.883 LAYER met3  ;
    ANTENNAPARTIALMETALSIDEAREA 5.176 LAYER met3  ;
    ANTENNAPARTIALCUTAREA 0.04 LAYER via3  ;
    ANTENNADIFFAREA 0.4455 LAYER met4  ;
    ANTENNAPARTIALMETALAREA 54.2868 LAYER met4  ;
    ANTENNAPARTIALMETALSIDEAREA 290 LAYER met4  ;
    PORT
      LAYER met2 ;
        RECT 1577.960000 0.000000 1578.100000 0.485000 ;
    END
  END la_data_out[55]
  PIN la_data_out[54]
    DIRECTION OUTPUT ;
    USE SIGNAL ;
    ANTENNADIFFAREA 0.336 LAYER met2  ;
    ANTENNAPARTIALMETALAREA 54.7091 LAYER met2  ;
    ANTENNAPARTIALMETALSIDEAREA 273.438 LAYER met2  ;
    PORT
      LAYER met2 ;
        RECT 1560.480000 0.000000 1560.620000 0.485000 ;
    END
  END la_data_out[54]
  PIN la_data_out[53]
    DIRECTION OUTPUT ;
    USE SIGNAL ;
    ANTENNADIFFAREA 0.336 LAYER met2  ;
    ANTENNAPARTIALMETALAREA 54.0763 LAYER met2  ;
    ANTENNAPARTIALMETALSIDEAREA 270.273 LAYER met2  ;
    PORT
      LAYER met2 ;
        RECT 1543.000000 0.000000 1543.140000 0.485000 ;
    END
  END la_data_out[53]
  PIN la_data_out[52]
    DIRECTION OUTPUT ;
    USE SIGNAL ;
    ANTENNADIFFAREA 0.336 LAYER met2  ;
    ANTENNAPARTIALMETALAREA 50.1395 LAYER met2  ;
    ANTENNAPARTIALMETALSIDEAREA 250.59 LAYER met2  ;
    PORT
      LAYER met2 ;
        RECT 1525.980000 0.000000 1526.120000 0.485000 ;
    END
  END la_data_out[52]
  PIN la_data_out[51]
    DIRECTION OUTPUT ;
    USE SIGNAL ;
    ANTENNADIFFAREA 0.336 LAYER met2  ;
    ANTENNAPARTIALMETALAREA 52.4243 LAYER met2  ;
    ANTENNAPARTIALMETALSIDEAREA 262.013 LAYER met2  ;
    PORT
      LAYER met2 ;
        RECT 1508.500000 0.000000 1508.640000 0.485000 ;
    END
  END la_data_out[51]
  PIN la_data_out[50]
    DIRECTION OUTPUT ;
    USE SIGNAL ;
    ANTENNADIFFAREA 0.336 LAYER met2  ;
    ANTENNAPARTIALMETALAREA 53.2503 LAYER met2  ;
    ANTENNAPARTIALMETALSIDEAREA 266.143 LAYER met2  ;
    PORT
      LAYER met2 ;
        RECT 1491.020000 0.000000 1491.160000 0.485000 ;
    END
  END la_data_out[50]
  PIN la_data_out[49]
    DIRECTION OUTPUT ;
    USE SIGNAL ;
    ANTENNADIFFAREA 0.336 LAYER met2  ;
    ANTENNAPARTIALMETALAREA 59.0267 LAYER met2  ;
    ANTENNAPARTIALMETALSIDEAREA 295.026 LAYER met2  ;
    PORT
      LAYER met2 ;
        RECT 1473.540000 0.000000 1473.680000 0.485000 ;
    END
  END la_data_out[49]
  PIN la_data_out[48]
    DIRECTION OUTPUT ;
    USE SIGNAL ;
    ANTENNADIFFAREA 0.336 LAYER met2  ;
    ANTENNAPARTIALMETALAREA 53.6143 LAYER met2  ;
    ANTENNAPARTIALMETALSIDEAREA 267.964 LAYER met2  ;
    PORT
      LAYER met2 ;
        RECT 1456.060000 0.000000 1456.200000 0.485000 ;
    END
  END la_data_out[48]
  PIN la_data_out[47]
    DIRECTION OUTPUT ;
    USE SIGNAL ;
    ANTENNADIFFAREA 0.336 LAYER met2  ;
    ANTENNAPARTIALMETALAREA 54.3283 LAYER met2  ;
    ANTENNAPARTIALMETALSIDEAREA 271.534 LAYER met2  ;
    PORT
      LAYER met2 ;
        RECT 1438.580000 0.000000 1438.720000 0.485000 ;
    END
  END la_data_out[47]
  PIN la_data_out[46]
    DIRECTION OUTPUT ;
    USE SIGNAL ;
    ANTENNADIFFAREA 0.336 LAYER met2  ;
    ANTENNAPARTIALMETALAREA 53.4099 LAYER met2  ;
    ANTENNAPARTIALMETALSIDEAREA 266.941 LAYER met2  ;
    PORT
      LAYER met2 ;
        RECT 1421.560000 0.000000 1421.700000 0.485000 ;
    END
  END la_data_out[46]
  PIN la_data_out[45]
    DIRECTION OUTPUT ;
    USE SIGNAL ;
    ANTENNADIFFAREA 0.336 LAYER met2  ;
    ANTENNAPARTIALMETALAREA 52.9535 LAYER met2  ;
    ANTENNAPARTIALMETALSIDEAREA 264.66 LAYER met2  ;
    PORT
      LAYER met2 ;
        RECT 1404.080000 0.000000 1404.220000 0.485000 ;
    END
  END la_data_out[45]
  PIN la_data_out[44]
    DIRECTION OUTPUT ;
    USE SIGNAL ;
    ANTENNADIFFAREA 0.336 LAYER met2  ;
    ANTENNAPARTIALMETALAREA 51.6627 LAYER met2  ;
    ANTENNAPARTIALMETALSIDEAREA 258.206 LAYER met2  ;
    PORT
      LAYER met2 ;
        RECT 1386.600000 0.000000 1386.740000 0.485000 ;
    END
  END la_data_out[44]
  PIN la_data_out[43]
    DIRECTION OUTPUT ;
    USE SIGNAL ;
    ANTENNADIFFAREA 0.336 LAYER met2  ;
    ANTENNAPARTIALMETALAREA 51.7579 LAYER met2  ;
    ANTENNAPARTIALMETALSIDEAREA 258.682 LAYER met2  ;
    PORT
      LAYER met2 ;
        RECT 1369.120000 0.000000 1369.260000 0.485000 ;
    END
  END la_data_out[43]
  PIN la_data_out[42]
    DIRECTION OUTPUT ;
    USE SIGNAL ;
    ANTENNADIFFAREA 0.3406 LAYER met2  ;
    ANTENNAPARTIALMETALAREA 28.3639 LAYER met2  ;
    ANTENNAPARTIALMETALSIDEAREA 141.712 LAYER met2  ;
    PORT
      LAYER met2 ;
        RECT 1351.640000 0.000000 1351.780000 0.485000 ;
    END
  END la_data_out[42]
  PIN la_data_out[41]
    DIRECTION OUTPUT ;
    USE SIGNAL ;
    ANTENNADIFFAREA 0.6626 LAYER met2  ;
    ANTENNAPARTIALMETALAREA 43.6993 LAYER met2  ;
    ANTENNAPARTIALMETALSIDEAREA 216.954 LAYER met2  ;
    ANTENNAMODEL OXIDE1 ;
    ANTENNAGATEAREA 3.687 LAYER met2  ;
    ANTENNAMAXAREACAR 35.5296 LAYER met2  ;
    ANTENNAMAXSIDEAREACAR 174.602 LAYER met2  ;
    ANTENNAMAXCUTCAR 0.32327 LAYER via2  ;
    PORT
      LAYER met2 ;
        RECT 1334.160000 0.000000 1334.300000 0.485000 ;
    END
  END la_data_out[41]
  PIN la_data_out[40]
    DIRECTION OUTPUT ;
    USE SIGNAL ;
    ANTENNAPARTIALMETALAREA 0.2744 LAYER met2  ;
    ANTENNAPARTIALMETALSIDEAREA 1.211 LAYER met2  ;
    ANTENNAPARTIALCUTAREA 0.04 LAYER via2  ;
    ANTENNADIFFAREA 2.0904 LAYER met3  ;
    ANTENNAPARTIALMETALAREA 118.475 LAYER met3  ;
    ANTENNAPARTIALMETALSIDEAREA 632.336 LAYER met3  ;
    PORT
      LAYER met2 ;
        RECT 1317.140000 0.000000 1317.280000 0.485000 ;
    END
  END la_data_out[40]
  PIN la_data_out[39]
    DIRECTION OUTPUT ;
    USE SIGNAL ;
    ANTENNADIFFAREA 0.336 LAYER met2  ;
    ANTENNAPARTIALMETALAREA 4.4435 LAYER met2  ;
    ANTENNAPARTIALMETALSIDEAREA 22.1095 LAYER met2  ;
    PORT
      LAYER met2 ;
        RECT 1299.660000 0.000000 1299.800000 0.485000 ;
    END
  END la_data_out[39]
  PIN la_data_out[38]
    DIRECTION OUTPUT ;
    USE SIGNAL ;
    ANTENNADIFFAREA 0.336 LAYER met2  ;
    ANTENNAPARTIALMETALAREA 4.4435 LAYER met2  ;
    ANTENNAPARTIALMETALSIDEAREA 22.1095 LAYER met2  ;
    PORT
      LAYER met2 ;
        RECT 1282.180000 0.000000 1282.320000 0.485000 ;
    END
  END la_data_out[38]
  PIN la_data_out[37]
    DIRECTION OUTPUT ;
    USE SIGNAL ;
    ANTENNADIFFAREA 0.336 LAYER met2  ;
    ANTENNAPARTIALMETALAREA 4.4435 LAYER met2  ;
    ANTENNAPARTIALMETALSIDEAREA 22.1095 LAYER met2  ;
    PORT
      LAYER met2 ;
        RECT 1264.700000 0.000000 1264.840000 0.485000 ;
    END
  END la_data_out[37]
  PIN la_data_out[36]
    DIRECTION OUTPUT ;
    USE SIGNAL ;
    ANTENNADIFFAREA 0.336 LAYER met2  ;
    ANTENNAPARTIALMETALAREA 4.4435 LAYER met2  ;
    ANTENNAPARTIALMETALSIDEAREA 22.1095 LAYER met2  ;
    PORT
      LAYER met2 ;
        RECT 1247.220000 0.000000 1247.360000 0.485000 ;
    END
  END la_data_out[36]
  PIN la_data_out[35]
    DIRECTION OUTPUT ;
    USE SIGNAL ;
    ANTENNADIFFAREA 0.336 LAYER met2  ;
    ANTENNAPARTIALMETALAREA 4.8243 LAYER met2  ;
    ANTENNAPARTIALMETALSIDEAREA 24.0135 LAYER met2  ;
    PORT
      LAYER met2 ;
        RECT 1230.200000 0.000000 1230.340000 0.485000 ;
    END
  END la_data_out[35]
  PIN la_data_out[34]
    DIRECTION OUTPUT ;
    USE SIGNAL ;
    ANTENNADIFFAREA 0.336 LAYER met2  ;
    ANTENNAPARTIALMETALAREA 4.4435 LAYER met2  ;
    ANTENNAPARTIALMETALSIDEAREA 22.1095 LAYER met2  ;
    PORT
      LAYER met2 ;
        RECT 1212.720000 0.000000 1212.860000 0.485000 ;
    END
  END la_data_out[34]
  PIN la_data_out[33]
    DIRECTION OUTPUT ;
    USE SIGNAL ;
    ANTENNADIFFAREA 0.336 LAYER met2  ;
    ANTENNAPARTIALMETALAREA 4.7011 LAYER met2  ;
    ANTENNAPARTIALMETALSIDEAREA 23.3975 LAYER met2  ;
    PORT
      LAYER met2 ;
        RECT 1195.240000 0.000000 1195.380000 0.485000 ;
    END
  END la_data_out[33]
  PIN la_data_out[32]
    DIRECTION OUTPUT ;
    USE SIGNAL ;
    ANTENNADIFFAREA 0.336 LAYER met2  ;
    ANTENNAPARTIALMETALAREA 4.4435 LAYER met2  ;
    ANTENNAPARTIALMETALSIDEAREA 22.1095 LAYER met2  ;
    PORT
      LAYER met2 ;
        RECT 1177.760000 0.000000 1177.900000 0.485000 ;
    END
  END la_data_out[32]
  PIN la_data_out[31]
    DIRECTION OUTPUT ;
    USE SIGNAL ;
    ANTENNADIFFAREA 0.336 LAYER met2  ;
    ANTENNAPARTIALMETALAREA 4.8243 LAYER met2  ;
    ANTENNAPARTIALMETALSIDEAREA 24.0135 LAYER met2  ;
    PORT
      LAYER met2 ;
        RECT 1160.280000 0.000000 1160.420000 0.485000 ;
    END
  END la_data_out[31]
  PIN la_data_out[30]
    DIRECTION OUTPUT ;
    USE SIGNAL ;
    ANTENNADIFFAREA 0.336 LAYER met2  ;
    ANTENNAPARTIALMETALAREA 4.4435 LAYER met2  ;
    ANTENNAPARTIALMETALSIDEAREA 22.1095 LAYER met2  ;
    PORT
      LAYER met2 ;
        RECT 1142.800000 0.000000 1142.940000 0.485000 ;
    END
  END la_data_out[30]
  PIN la_data_out[29]
    DIRECTION OUTPUT ;
    USE SIGNAL ;
    ANTENNADIFFAREA 0.336 LAYER met2  ;
    ANTENNAPARTIALMETALAREA 4.4435 LAYER met2  ;
    ANTENNAPARTIALMETALSIDEAREA 22.1095 LAYER met2  ;
    PORT
      LAYER met2 ;
        RECT 1125.780000 0.000000 1125.920000 0.485000 ;
    END
  END la_data_out[29]
  PIN la_data_out[28]
    DIRECTION OUTPUT ;
    USE SIGNAL ;
    ANTENNADIFFAREA 0.336 LAYER met2  ;
    ANTENNAPARTIALMETALAREA 4.4435 LAYER met2  ;
    ANTENNAPARTIALMETALSIDEAREA 22.1095 LAYER met2  ;
    PORT
      LAYER met2 ;
        RECT 1108.300000 0.000000 1108.440000 0.485000 ;
    END
  END la_data_out[28]
  PIN la_data_out[27]
    DIRECTION OUTPUT ;
    USE SIGNAL ;
    ANTENNADIFFAREA 0.336 LAYER met2  ;
    ANTENNAPARTIALMETALAREA 4.5723 LAYER met2  ;
    ANTENNAPARTIALMETALSIDEAREA 22.7535 LAYER met2  ;
    PORT
      LAYER met2 ;
        RECT 1090.820000 0.000000 1090.960000 0.485000 ;
    END
  END la_data_out[27]
  PIN la_data_out[26]
    DIRECTION OUTPUT ;
    USE SIGNAL ;
    ANTENNADIFFAREA 0.336 LAYER met2  ;
    ANTENNAPARTIALMETALAREA 4.4435 LAYER met2  ;
    ANTENNAPARTIALMETALSIDEAREA 22.1095 LAYER met2  ;
    PORT
      LAYER met2 ;
        RECT 1073.340000 0.000000 1073.480000 0.485000 ;
    END
  END la_data_out[26]
  PIN la_data_out[25]
    DIRECTION OUTPUT ;
    USE SIGNAL ;
    ANTENNADIFFAREA 0.336 LAYER met2  ;
    ANTENNAPARTIALMETALAREA 4.4435 LAYER met2  ;
    ANTENNAPARTIALMETALSIDEAREA 22.1095 LAYER met2  ;
    PORT
      LAYER met2 ;
        RECT 1055.860000 0.000000 1056.000000 0.485000 ;
    END
  END la_data_out[25]
  PIN la_data_out[24]
    DIRECTION OUTPUT ;
    USE SIGNAL ;
    ANTENNADIFFAREA 0.336 LAYER met2  ;
    ANTENNAPARTIALMETALAREA 4.4435 LAYER met2  ;
    ANTENNAPARTIALMETALSIDEAREA 22.1095 LAYER met2  ;
    PORT
      LAYER met2 ;
        RECT 1038.380000 0.000000 1038.520000 0.485000 ;
    END
  END la_data_out[24]
  PIN la_data_out[23]
    DIRECTION OUTPUT ;
    USE SIGNAL ;
    ANTENNADIFFAREA 0.336 LAYER met2  ;
    ANTENNAPARTIALMETALAREA 5.0819 LAYER met2  ;
    ANTENNAPARTIALMETALSIDEAREA 25.3015 LAYER met2  ;
    PORT
      LAYER met2 ;
        RECT 1021.360000 0.000000 1021.500000 0.485000 ;
    END
  END la_data_out[23]
  PIN la_data_out[22]
    DIRECTION OUTPUT ;
    USE SIGNAL ;
    ANTENNADIFFAREA 0.336 LAYER met2  ;
    ANTENNAPARTIALMETALAREA 4.4435 LAYER met2  ;
    ANTENNAPARTIALMETALSIDEAREA 22.1095 LAYER met2  ;
    PORT
      LAYER met2 ;
        RECT 1003.880000 0.000000 1004.020000 0.485000 ;
    END
  END la_data_out[22]
  PIN la_data_out[21]
    DIRECTION OUTPUT ;
    USE SIGNAL ;
    ANTENNADIFFAREA 0.336 LAYER met2  ;
    ANTENNAPARTIALMETALAREA 4.4435 LAYER met2  ;
    ANTENNAPARTIALMETALSIDEAREA 22.1095 LAYER met2  ;
    PORT
      LAYER met2 ;
        RECT 986.400000 0.000000 986.540000 0.485000 ;
    END
  END la_data_out[21]
  PIN la_data_out[20]
    DIRECTION OUTPUT ;
    USE SIGNAL ;
    ANTENNADIFFAREA 0.336 LAYER met2  ;
    ANTENNAPARTIALMETALAREA 4.4435 LAYER met2  ;
    ANTENNAPARTIALMETALSIDEAREA 22.1095 LAYER met2  ;
    PORT
      LAYER met2 ;
        RECT 968.920000 0.000000 969.060000 0.485000 ;
    END
  END la_data_out[20]
  PIN la_data_out[19]
    DIRECTION OUTPUT ;
    USE SIGNAL ;
    ANTENNADIFFAREA 0.336 LAYER met2  ;
    ANTENNAPARTIALMETALAREA 4.4435 LAYER met2  ;
    ANTENNAPARTIALMETALSIDEAREA 22.1095 LAYER met2  ;
    PORT
      LAYER met2 ;
        RECT 951.440000 0.000000 951.580000 0.485000 ;
    END
  END la_data_out[19]
  PIN la_data_out[18]
    DIRECTION OUTPUT ;
    USE SIGNAL ;
    ANTENNADIFFAREA 0.336 LAYER met2  ;
    ANTENNAPARTIALMETALAREA 4.4435 LAYER met2  ;
    ANTENNAPARTIALMETALSIDEAREA 22.1095 LAYER met2  ;
    PORT
      LAYER met2 ;
        RECT 933.960000 0.000000 934.100000 0.485000 ;
    END
  END la_data_out[18]
  PIN la_data_out[17]
    DIRECTION OUTPUT ;
    USE SIGNAL ;
    ANTENNADIFFAREA 0.336 LAYER met2  ;
    ANTENNAPARTIALMETALAREA 4.4435 LAYER met2  ;
    ANTENNAPARTIALMETALSIDEAREA 22.1095 LAYER met2  ;
    PORT
      LAYER met2 ;
        RECT 916.940000 0.000000 917.080000 0.485000 ;
    END
  END la_data_out[17]
  PIN la_data_out[16]
    DIRECTION OUTPUT ;
    USE SIGNAL ;
    ANTENNADIFFAREA 0.336 LAYER met2  ;
    ANTENNAPARTIALMETALAREA 4.4435 LAYER met2  ;
    ANTENNAPARTIALMETALSIDEAREA 22.1095 LAYER met2  ;
    PORT
      LAYER met2 ;
        RECT 899.460000 0.000000 899.600000 0.485000 ;
    END
  END la_data_out[16]
  PIN la_data_out[15]
    DIRECTION OUTPUT ;
    USE SIGNAL ;
    ANTENNADIFFAREA 0.336 LAYER met2  ;
    ANTENNAPARTIALMETALAREA 4.4435 LAYER met2  ;
    ANTENNAPARTIALMETALSIDEAREA 22.1095 LAYER met2  ;
    PORT
      LAYER met2 ;
        RECT 881.980000 0.000000 882.120000 0.485000 ;
    END
  END la_data_out[15]
  PIN la_data_out[14]
    DIRECTION OUTPUT ;
    USE SIGNAL ;
    ANTENNADIFFAREA 0.336 LAYER met2  ;
    ANTENNAPARTIALMETALAREA 4.4435 LAYER met2  ;
    ANTENNAPARTIALMETALSIDEAREA 22.1095 LAYER met2  ;
    PORT
      LAYER met2 ;
        RECT 864.500000 0.000000 864.640000 0.485000 ;
    END
  END la_data_out[14]
  PIN la_data_out[13]
    DIRECTION OUTPUT ;
    USE SIGNAL ;
    ANTENNADIFFAREA 0.336 LAYER met2  ;
    ANTENNAPARTIALMETALAREA 4.4435 LAYER met2  ;
    ANTENNAPARTIALMETALSIDEAREA 22.1095 LAYER met2  ;
    PORT
      LAYER met2 ;
        RECT 847.020000 0.000000 847.160000 0.485000 ;
    END
  END la_data_out[13]
  PIN la_data_out[12]
    DIRECTION OUTPUT ;
    USE SIGNAL ;
    ANTENNADIFFAREA 0.336 LAYER met2  ;
    ANTENNAPARTIALMETALAREA 4.4435 LAYER met2  ;
    ANTENNAPARTIALMETALSIDEAREA 22.1095 LAYER met2  ;
    PORT
      LAYER met2 ;
        RECT 830.000000 0.000000 830.140000 0.485000 ;
    END
  END la_data_out[12]
  PIN la_data_out[11]
    DIRECTION OUTPUT ;
    USE SIGNAL ;
    ANTENNADIFFAREA 0.336 LAYER met2  ;
    ANTENNAPARTIALMETALAREA 4.8243 LAYER met2  ;
    ANTENNAPARTIALMETALSIDEAREA 24.0135 LAYER met2  ;
    PORT
      LAYER met2 ;
        RECT 812.520000 0.000000 812.660000 0.485000 ;
    END
  END la_data_out[11]
  PIN la_data_out[10]
    DIRECTION OUTPUT ;
    USE SIGNAL ;
    ANTENNADIFFAREA 0.336 LAYER met2  ;
    ANTENNAPARTIALMETALAREA 4.4435 LAYER met2  ;
    ANTENNAPARTIALMETALSIDEAREA 22.1095 LAYER met2  ;
    PORT
      LAYER met2 ;
        RECT 795.040000 0.000000 795.180000 0.485000 ;
    END
  END la_data_out[10]
  PIN la_data_out[9]
    DIRECTION OUTPUT ;
    USE SIGNAL ;
    ANTENNADIFFAREA 0.336 LAYER met2  ;
    ANTENNAPARTIALMETALAREA 4.4435 LAYER met2  ;
    ANTENNAPARTIALMETALSIDEAREA 22.1095 LAYER met2  ;
    PORT
      LAYER met2 ;
        RECT 777.560000 0.000000 777.700000 0.485000 ;
    END
  END la_data_out[9]
  PIN la_data_out[8]
    DIRECTION OUTPUT ;
    USE SIGNAL ;
    ANTENNADIFFAREA 0.336 LAYER met2  ;
    ANTENNAPARTIALMETALAREA 4.4435 LAYER met2  ;
    ANTENNAPARTIALMETALSIDEAREA 22.1095 LAYER met2  ;
    PORT
      LAYER met2 ;
        RECT 760.080000 0.000000 760.220000 0.485000 ;
    END
  END la_data_out[8]
  PIN la_data_out[7]
    DIRECTION OUTPUT ;
    USE SIGNAL ;
    ANTENNADIFFAREA 0.336 LAYER met2  ;
    ANTENNAPARTIALMETALAREA 4.4435 LAYER met2  ;
    ANTENNAPARTIALMETALSIDEAREA 22.1095 LAYER met2  ;
    PORT
      LAYER met2 ;
        RECT 742.600000 0.000000 742.740000 0.485000 ;
    END
  END la_data_out[7]
  PIN la_data_out[6]
    DIRECTION OUTPUT ;
    USE SIGNAL ;
    ANTENNADIFFAREA 0.336 LAYER met2  ;
    ANTENNAPARTIALMETALAREA 4.4435 LAYER met2  ;
    ANTENNAPARTIALMETALSIDEAREA 22.1095 LAYER met2  ;
    PORT
      LAYER met2 ;
        RECT 725.580000 0.000000 725.720000 0.485000 ;
    END
  END la_data_out[6]
  PIN la_data_out[5]
    DIRECTION OUTPUT ;
    USE SIGNAL ;
    ANTENNADIFFAREA 0.336 LAYER met2  ;
    ANTENNAPARTIALMETALAREA 4.6367 LAYER met2  ;
    ANTENNAPARTIALMETALSIDEAREA 23.0755 LAYER met2  ;
    PORT
      LAYER met2 ;
        RECT 708.100000 0.000000 708.240000 0.485000 ;
    END
  END la_data_out[5]
  PIN la_data_out[4]
    DIRECTION OUTPUT ;
    USE SIGNAL ;
    ANTENNADIFFAREA 0.336 LAYER met2  ;
    ANTENNAPARTIALMETALAREA 4.8243 LAYER met2  ;
    ANTENNAPARTIALMETALSIDEAREA 24.0135 LAYER met2  ;
    PORT
      LAYER met2 ;
        RECT 690.620000 0.000000 690.760000 0.485000 ;
    END
  END la_data_out[4]
  PIN la_data_out[3]
    DIRECTION OUTPUT ;
    USE SIGNAL ;
    ANTENNADIFFAREA 0.336 LAYER met2  ;
    ANTENNAPARTIALMETALAREA 4.5723 LAYER met2  ;
    ANTENNAPARTIALMETALSIDEAREA 22.7535 LAYER met2  ;
    PORT
      LAYER met2 ;
        RECT 673.140000 0.000000 673.280000 0.485000 ;
    END
  END la_data_out[3]
  PIN la_data_out[2]
    DIRECTION OUTPUT ;
    USE SIGNAL ;
    ANTENNADIFFAREA 0.336 LAYER met2  ;
    ANTENNAPARTIALMETALAREA 4.5723 LAYER met2  ;
    ANTENNAPARTIALMETALSIDEAREA 22.7535 LAYER met2  ;
    PORT
      LAYER met2 ;
        RECT 655.660000 0.000000 655.800000 0.485000 ;
    END
  END la_data_out[2]
  PIN la_data_out[1]
    DIRECTION OUTPUT ;
    USE SIGNAL ;
    ANTENNADIFFAREA 0.336 LAYER met2  ;
    ANTENNAPARTIALMETALAREA 4.4435 LAYER met2  ;
    ANTENNAPARTIALMETALSIDEAREA 22.1095 LAYER met2  ;
    PORT
      LAYER met2 ;
        RECT 638.180000 0.000000 638.320000 0.485000 ;
    END
  END la_data_out[1]
  PIN la_data_out[0]
    DIRECTION OUTPUT ;
    USE SIGNAL ;
    ANTENNADIFFAREA 0.336 LAYER met2  ;
    ANTENNAPARTIALMETALAREA 4.4435 LAYER met2  ;
    ANTENNAPARTIALMETALSIDEAREA 22.1095 LAYER met2  ;
    PORT
      LAYER met2 ;
        RECT 621.160000 0.000000 621.300000 0.485000 ;
    END
  END la_data_out[0]
  PIN la_oenb[127]
    DIRECTION INPUT ;
    USE SIGNAL ;
    PORT
      LAYER met2 ;
        RECT 2836.520000 0.000000 2836.660000 0.485000 ;
    END
  END la_oenb[127]
  PIN la_oenb[126]
    DIRECTION INPUT ;
    USE SIGNAL ;
    PORT
      LAYER met2 ;
        RECT 2819.040000 0.000000 2819.180000 0.485000 ;
    END
  END la_oenb[126]
  PIN la_oenb[125]
    DIRECTION INPUT ;
    USE SIGNAL ;
    PORT
      LAYER met2 ;
        RECT 2801.560000 0.000000 2801.700000 0.485000 ;
    END
  END la_oenb[125]
  PIN la_oenb[124]
    DIRECTION INPUT ;
    USE SIGNAL ;
    PORT
      LAYER met2 ;
        RECT 2784.540000 0.000000 2784.680000 0.485000 ;
    END
  END la_oenb[124]
  PIN la_oenb[123]
    DIRECTION INPUT ;
    USE SIGNAL ;
    PORT
      LAYER met2 ;
        RECT 2767.060000 0.000000 2767.200000 0.485000 ;
    END
  END la_oenb[123]
  PIN la_oenb[122]
    DIRECTION INPUT ;
    USE SIGNAL ;
    PORT
      LAYER met2 ;
        RECT 2749.580000 0.000000 2749.720000 0.485000 ;
    END
  END la_oenb[122]
  PIN la_oenb[121]
    DIRECTION INPUT ;
    USE SIGNAL ;
    PORT
      LAYER met2 ;
        RECT 2732.100000 0.000000 2732.240000 0.485000 ;
    END
  END la_oenb[121]
  PIN la_oenb[120]
    DIRECTION INPUT ;
    USE SIGNAL ;
    PORT
      LAYER met2 ;
        RECT 2714.620000 0.000000 2714.760000 0.485000 ;
    END
  END la_oenb[120]
  PIN la_oenb[119]
    DIRECTION INPUT ;
    USE SIGNAL ;
    PORT
      LAYER met2 ;
        RECT 2697.140000 0.000000 2697.280000 0.485000 ;
    END
  END la_oenb[119]
  PIN la_oenb[118]
    DIRECTION INPUT ;
    USE SIGNAL ;
    PORT
      LAYER met2 ;
        RECT 2680.120000 0.000000 2680.260000 0.485000 ;
    END
  END la_oenb[118]
  PIN la_oenb[117]
    DIRECTION INPUT ;
    USE SIGNAL ;
    PORT
      LAYER met2 ;
        RECT 2662.640000 0.000000 2662.780000 0.485000 ;
    END
  END la_oenb[117]
  PIN la_oenb[116]
    DIRECTION INPUT ;
    USE SIGNAL ;
    PORT
      LAYER met2 ;
        RECT 2645.160000 0.000000 2645.300000 0.485000 ;
    END
  END la_oenb[116]
  PIN la_oenb[115]
    DIRECTION INPUT ;
    USE SIGNAL ;
    PORT
      LAYER met2 ;
        RECT 2627.680000 0.000000 2627.820000 0.485000 ;
    END
  END la_oenb[115]
  PIN la_oenb[114]
    DIRECTION INPUT ;
    USE SIGNAL ;
    PORT
      LAYER met2 ;
        RECT 2610.200000 0.000000 2610.340000 0.485000 ;
    END
  END la_oenb[114]
  PIN la_oenb[113]
    DIRECTION INPUT ;
    USE SIGNAL ;
    PORT
      LAYER met2 ;
        RECT 2593.180000 0.000000 2593.320000 0.485000 ;
    END
  END la_oenb[113]
  PIN la_oenb[112]
    DIRECTION INPUT ;
    USE SIGNAL ;
    PORT
      LAYER met2 ;
        RECT 2575.700000 0.000000 2575.840000 0.485000 ;
    END
  END la_oenb[112]
  PIN la_oenb[111]
    DIRECTION INPUT ;
    USE SIGNAL ;
    PORT
      LAYER met2 ;
        RECT 2558.220000 0.000000 2558.360000 0.485000 ;
    END
  END la_oenb[111]
  PIN la_oenb[110]
    DIRECTION INPUT ;
    USE SIGNAL ;
    PORT
      LAYER met2 ;
        RECT 2540.740000 0.000000 2540.880000 0.485000 ;
    END
  END la_oenb[110]
  PIN la_oenb[109]
    DIRECTION INPUT ;
    USE SIGNAL ;
    PORT
      LAYER met2 ;
        RECT 2523.260000 0.000000 2523.400000 0.485000 ;
    END
  END la_oenb[109]
  PIN la_oenb[108]
    DIRECTION INPUT ;
    USE SIGNAL ;
    PORT
      LAYER met2 ;
        RECT 2505.780000 0.000000 2505.920000 0.485000 ;
    END
  END la_oenb[108]
  PIN la_oenb[107]
    DIRECTION INPUT ;
    USE SIGNAL ;
    PORT
      LAYER met2 ;
        RECT 2488.760000 0.000000 2488.900000 0.485000 ;
    END
  END la_oenb[107]
  PIN la_oenb[106]
    DIRECTION INPUT ;
    USE SIGNAL ;
    PORT
      LAYER met2 ;
        RECT 2471.280000 0.000000 2471.420000 0.485000 ;
    END
  END la_oenb[106]
  PIN la_oenb[105]
    DIRECTION INPUT ;
    USE SIGNAL ;
    PORT
      LAYER met2 ;
        RECT 2453.800000 0.000000 2453.940000 0.485000 ;
    END
  END la_oenb[105]
  PIN la_oenb[104]
    DIRECTION INPUT ;
    USE SIGNAL ;
    PORT
      LAYER met2 ;
        RECT 2436.320000 0.000000 2436.460000 0.485000 ;
    END
  END la_oenb[104]
  PIN la_oenb[103]
    DIRECTION INPUT ;
    USE SIGNAL ;
    PORT
      LAYER met2 ;
        RECT 2418.840000 0.000000 2418.980000 0.485000 ;
    END
  END la_oenb[103]
  PIN la_oenb[102]
    DIRECTION INPUT ;
    USE SIGNAL ;
    PORT
      LAYER met2 ;
        RECT 2401.360000 0.000000 2401.500000 0.485000 ;
    END
  END la_oenb[102]
  PIN la_oenb[101]
    DIRECTION INPUT ;
    USE SIGNAL ;
    PORT
      LAYER met2 ;
        RECT 2384.340000 0.000000 2384.480000 0.485000 ;
    END
  END la_oenb[101]
  PIN la_oenb[100]
    DIRECTION INPUT ;
    USE SIGNAL ;
    PORT
      LAYER met2 ;
        RECT 2366.860000 0.000000 2367.000000 0.485000 ;
    END
  END la_oenb[100]
  PIN la_oenb[99]
    DIRECTION INPUT ;
    USE SIGNAL ;
    PORT
      LAYER met2 ;
        RECT 2349.380000 0.000000 2349.520000 0.485000 ;
    END
  END la_oenb[99]
  PIN la_oenb[98]
    DIRECTION INPUT ;
    USE SIGNAL ;
    PORT
      LAYER met2 ;
        RECT 2331.900000 0.000000 2332.040000 0.485000 ;
    END
  END la_oenb[98]
  PIN la_oenb[97]
    DIRECTION INPUT ;
    USE SIGNAL ;
    PORT
      LAYER met2 ;
        RECT 2314.420000 0.000000 2314.560000 0.485000 ;
    END
  END la_oenb[97]
  PIN la_oenb[96]
    DIRECTION INPUT ;
    USE SIGNAL ;
    PORT
      LAYER met2 ;
        RECT 2296.940000 0.000000 2297.080000 0.485000 ;
    END
  END la_oenb[96]
  PIN la_oenb[95]
    DIRECTION INPUT ;
    USE SIGNAL ;
    PORT
      LAYER met2 ;
        RECT 2279.920000 0.000000 2280.060000 0.485000 ;
    END
  END la_oenb[95]
  PIN la_oenb[94]
    DIRECTION INPUT ;
    USE SIGNAL ;
    PORT
      LAYER met2 ;
        RECT 2262.440000 0.000000 2262.580000 0.485000 ;
    END
  END la_oenb[94]
  PIN la_oenb[93]
    DIRECTION INPUT ;
    USE SIGNAL ;
    PORT
      LAYER met2 ;
        RECT 2244.960000 0.000000 2245.100000 0.485000 ;
    END
  END la_oenb[93]
  PIN la_oenb[92]
    DIRECTION INPUT ;
    USE SIGNAL ;
    PORT
      LAYER met2 ;
        RECT 2227.480000 0.000000 2227.620000 0.485000 ;
    END
  END la_oenb[92]
  PIN la_oenb[91]
    DIRECTION INPUT ;
    USE SIGNAL ;
    PORT
      LAYER met2 ;
        RECT 2210.000000 0.000000 2210.140000 0.485000 ;
    END
  END la_oenb[91]
  PIN la_oenb[90]
    DIRECTION INPUT ;
    USE SIGNAL ;
    PORT
      LAYER met2 ;
        RECT 2192.980000 0.000000 2193.120000 0.485000 ;
    END
  END la_oenb[90]
  PIN la_oenb[89]
    DIRECTION INPUT ;
    USE SIGNAL ;
    PORT
      LAYER met2 ;
        RECT 2175.500000 0.000000 2175.640000 0.485000 ;
    END
  END la_oenb[89]
  PIN la_oenb[88]
    DIRECTION INPUT ;
    USE SIGNAL ;
    PORT
      LAYER met2 ;
        RECT 2158.020000 0.000000 2158.160000 0.485000 ;
    END
  END la_oenb[88]
  PIN la_oenb[87]
    DIRECTION INPUT ;
    USE SIGNAL ;
    PORT
      LAYER met2 ;
        RECT 2140.540000 0.000000 2140.680000 0.485000 ;
    END
  END la_oenb[87]
  PIN la_oenb[86]
    DIRECTION INPUT ;
    USE SIGNAL ;
    PORT
      LAYER met2 ;
        RECT 2123.060000 0.000000 2123.200000 0.485000 ;
    END
  END la_oenb[86]
  PIN la_oenb[85]
    DIRECTION INPUT ;
    USE SIGNAL ;
    PORT
      LAYER met2 ;
        RECT 2105.580000 0.000000 2105.720000 0.485000 ;
    END
  END la_oenb[85]
  PIN la_oenb[84]
    DIRECTION INPUT ;
    USE SIGNAL ;
    PORT
      LAYER met2 ;
        RECT 2088.560000 0.000000 2088.700000 0.485000 ;
    END
  END la_oenb[84]
  PIN la_oenb[83]
    DIRECTION INPUT ;
    USE SIGNAL ;
    PORT
      LAYER met2 ;
        RECT 2071.080000 0.000000 2071.220000 0.485000 ;
    END
  END la_oenb[83]
  PIN la_oenb[82]
    DIRECTION INPUT ;
    USE SIGNAL ;
    PORT
      LAYER met2 ;
        RECT 2053.600000 0.000000 2053.740000 0.485000 ;
    END
  END la_oenb[82]
  PIN la_oenb[81]
    DIRECTION INPUT ;
    USE SIGNAL ;
    PORT
      LAYER met2 ;
        RECT 2036.120000 0.000000 2036.260000 0.485000 ;
    END
  END la_oenb[81]
  PIN la_oenb[80]
    DIRECTION INPUT ;
    USE SIGNAL ;
    PORT
      LAYER met2 ;
        RECT 2018.640000 0.000000 2018.780000 0.485000 ;
    END
  END la_oenb[80]
  PIN la_oenb[79]
    DIRECTION INPUT ;
    USE SIGNAL ;
    PORT
      LAYER met2 ;
        RECT 2001.160000 0.000000 2001.300000 0.485000 ;
    END
  END la_oenb[79]
  PIN la_oenb[78]
    DIRECTION INPUT ;
    USE SIGNAL ;
    PORT
      LAYER met2 ;
        RECT 1984.140000 0.000000 1984.280000 0.485000 ;
    END
  END la_oenb[78]
  PIN la_oenb[77]
    DIRECTION INPUT ;
    USE SIGNAL ;
    PORT
      LAYER met2 ;
        RECT 1966.660000 0.000000 1966.800000 0.485000 ;
    END
  END la_oenb[77]
  PIN la_oenb[76]
    DIRECTION INPUT ;
    USE SIGNAL ;
    PORT
      LAYER met2 ;
        RECT 1949.180000 0.000000 1949.320000 0.485000 ;
    END
  END la_oenb[76]
  PIN la_oenb[75]
    DIRECTION INPUT ;
    USE SIGNAL ;
    PORT
      LAYER met2 ;
        RECT 1931.700000 0.000000 1931.840000 0.485000 ;
    END
  END la_oenb[75]
  PIN la_oenb[74]
    DIRECTION INPUT ;
    USE SIGNAL ;
    PORT
      LAYER met2 ;
        RECT 1914.220000 0.000000 1914.360000 0.485000 ;
    END
  END la_oenb[74]
  PIN la_oenb[73]
    DIRECTION INPUT ;
    USE SIGNAL ;
    PORT
      LAYER met2 ;
        RECT 1896.740000 0.000000 1896.880000 0.485000 ;
    END
  END la_oenb[73]
  PIN la_oenb[72]
    DIRECTION INPUT ;
    USE SIGNAL ;
    PORT
      LAYER met2 ;
        RECT 1879.720000 0.000000 1879.860000 0.485000 ;
    END
  END la_oenb[72]
  PIN la_oenb[71]
    DIRECTION INPUT ;
    USE SIGNAL ;
    PORT
      LAYER met2 ;
        RECT 1862.240000 0.000000 1862.380000 0.485000 ;
    END
  END la_oenb[71]
  PIN la_oenb[70]
    DIRECTION INPUT ;
    USE SIGNAL ;
    PORT
      LAYER met2 ;
        RECT 1844.760000 0.000000 1844.900000 0.485000 ;
    END
  END la_oenb[70]
  PIN la_oenb[69]
    DIRECTION INPUT ;
    USE SIGNAL ;
    PORT
      LAYER met2 ;
        RECT 1827.280000 0.000000 1827.420000 0.485000 ;
    END
  END la_oenb[69]
  PIN la_oenb[68]
    DIRECTION INPUT ;
    USE SIGNAL ;
    PORT
      LAYER met2 ;
        RECT 1809.800000 0.000000 1809.940000 0.485000 ;
    END
  END la_oenb[68]
  PIN la_oenb[67]
    DIRECTION INPUT ;
    USE SIGNAL ;
    PORT
      LAYER met2 ;
        RECT 1792.780000 0.000000 1792.920000 0.485000 ;
    END
  END la_oenb[67]
  PIN la_oenb[66]
    DIRECTION INPUT ;
    USE SIGNAL ;
    PORT
      LAYER met2 ;
        RECT 1775.300000 0.000000 1775.440000 0.485000 ;
    END
  END la_oenb[66]
  PIN la_oenb[65]
    DIRECTION INPUT ;
    USE SIGNAL ;
    PORT
      LAYER met2 ;
        RECT 1757.820000 0.000000 1757.960000 0.485000 ;
    END
  END la_oenb[65]
  PIN la_oenb[64]
    DIRECTION INPUT ;
    USE SIGNAL ;
    PORT
      LAYER met2 ;
        RECT 1740.340000 0.000000 1740.480000 0.485000 ;
    END
  END la_oenb[64]
  PIN la_oenb[63]
    DIRECTION INPUT ;
    USE SIGNAL ;
    PORT
      LAYER met2 ;
        RECT 1722.860000 0.000000 1723.000000 0.485000 ;
    END
  END la_oenb[63]
  PIN la_oenb[62]
    DIRECTION INPUT ;
    USE SIGNAL ;
    PORT
      LAYER met2 ;
        RECT 1705.380000 0.000000 1705.520000 0.485000 ;
    END
  END la_oenb[62]
  PIN la_oenb[61]
    DIRECTION INPUT ;
    USE SIGNAL ;
    PORT
      LAYER met2 ;
        RECT 1688.360000 0.000000 1688.500000 0.485000 ;
    END
  END la_oenb[61]
  PIN la_oenb[60]
    DIRECTION INPUT ;
    USE SIGNAL ;
    PORT
      LAYER met2 ;
        RECT 1670.880000 0.000000 1671.020000 0.485000 ;
    END
  END la_oenb[60]
  PIN la_oenb[59]
    DIRECTION INPUT ;
    USE SIGNAL ;
    PORT
      LAYER met2 ;
        RECT 1653.400000 0.000000 1653.540000 0.485000 ;
    END
  END la_oenb[59]
  PIN la_oenb[58]
    DIRECTION INPUT ;
    USE SIGNAL ;
    PORT
      LAYER met2 ;
        RECT 1635.920000 0.000000 1636.060000 0.485000 ;
    END
  END la_oenb[58]
  PIN la_oenb[57]
    DIRECTION INPUT ;
    USE SIGNAL ;
    PORT
      LAYER met2 ;
        RECT 1618.440000 0.000000 1618.580000 0.485000 ;
    END
  END la_oenb[57]
  PIN la_oenb[56]
    DIRECTION INPUT ;
    USE SIGNAL ;
    PORT
      LAYER met2 ;
        RECT 1600.960000 0.000000 1601.100000 0.485000 ;
    END
  END la_oenb[56]
  PIN la_oenb[55]
    DIRECTION INPUT ;
    USE SIGNAL ;
    PORT
      LAYER met2 ;
        RECT 1583.940000 0.000000 1584.080000 0.485000 ;
    END
  END la_oenb[55]
  PIN la_oenb[54]
    DIRECTION INPUT ;
    USE SIGNAL ;
    PORT
      LAYER met2 ;
        RECT 1566.460000 0.000000 1566.600000 0.485000 ;
    END
  END la_oenb[54]
  PIN la_oenb[53]
    DIRECTION INPUT ;
    USE SIGNAL ;
    PORT
      LAYER met2 ;
        RECT 1548.980000 0.000000 1549.120000 0.485000 ;
    END
  END la_oenb[53]
  PIN la_oenb[52]
    DIRECTION INPUT ;
    USE SIGNAL ;
    PORT
      LAYER met2 ;
        RECT 1531.500000 0.000000 1531.640000 0.485000 ;
    END
  END la_oenb[52]
  PIN la_oenb[51]
    DIRECTION INPUT ;
    USE SIGNAL ;
    PORT
      LAYER met2 ;
        RECT 1514.020000 0.000000 1514.160000 0.485000 ;
    END
  END la_oenb[51]
  PIN la_oenb[50]
    DIRECTION INPUT ;
    USE SIGNAL ;
    PORT
      LAYER met2 ;
        RECT 1496.540000 0.000000 1496.680000 0.485000 ;
    END
  END la_oenb[50]
  PIN la_oenb[49]
    DIRECTION INPUT ;
    USE SIGNAL ;
    PORT
      LAYER met2 ;
        RECT 1479.520000 0.000000 1479.660000 0.485000 ;
    END
  END la_oenb[49]
  PIN la_oenb[48]
    DIRECTION INPUT ;
    USE SIGNAL ;
    PORT
      LAYER met2 ;
        RECT 1462.040000 0.000000 1462.180000 0.485000 ;
    END
  END la_oenb[48]
  PIN la_oenb[47]
    DIRECTION INPUT ;
    USE SIGNAL ;
    PORT
      LAYER met2 ;
        RECT 1444.560000 0.000000 1444.700000 0.485000 ;
    END
  END la_oenb[47]
  PIN la_oenb[46]
    DIRECTION INPUT ;
    USE SIGNAL ;
    PORT
      LAYER met2 ;
        RECT 1427.080000 0.000000 1427.220000 0.485000 ;
    END
  END la_oenb[46]
  PIN la_oenb[45]
    DIRECTION INPUT ;
    USE SIGNAL ;
    PORT
      LAYER met2 ;
        RECT 1409.600000 0.000000 1409.740000 0.485000 ;
    END
  END la_oenb[45]
  PIN la_oenb[44]
    DIRECTION INPUT ;
    USE SIGNAL ;
    PORT
      LAYER met2 ;
        RECT 1392.580000 0.000000 1392.720000 0.485000 ;
    END
  END la_oenb[44]
  PIN la_oenb[43]
    DIRECTION INPUT ;
    USE SIGNAL ;
    PORT
      LAYER met2 ;
        RECT 1375.100000 0.000000 1375.240000 0.485000 ;
    END
  END la_oenb[43]
  PIN la_oenb[42]
    DIRECTION INPUT ;
    USE SIGNAL ;
    PORT
      LAYER met2 ;
        RECT 1357.620000 0.000000 1357.760000 0.485000 ;
    END
  END la_oenb[42]
  PIN la_oenb[41]
    DIRECTION INPUT ;
    USE SIGNAL ;
    PORT
      LAYER met2 ;
        RECT 1340.140000 0.000000 1340.280000 0.485000 ;
    END
  END la_oenb[41]
  PIN la_oenb[40]
    DIRECTION INPUT ;
    USE SIGNAL ;
    PORT
      LAYER met2 ;
        RECT 1322.660000 0.000000 1322.800000 0.485000 ;
    END
  END la_oenb[40]
  PIN la_oenb[39]
    DIRECTION INPUT ;
    USE SIGNAL ;
    PORT
      LAYER met2 ;
        RECT 1305.180000 0.000000 1305.320000 0.485000 ;
    END
  END la_oenb[39]
  PIN la_oenb[38]
    DIRECTION INPUT ;
    USE SIGNAL ;
    PORT
      LAYER met2 ;
        RECT 1288.160000 0.000000 1288.300000 0.485000 ;
    END
  END la_oenb[38]
  PIN la_oenb[37]
    DIRECTION INPUT ;
    USE SIGNAL ;
    PORT
      LAYER met2 ;
        RECT 1270.680000 0.000000 1270.820000 0.485000 ;
    END
  END la_oenb[37]
  PIN la_oenb[36]
    DIRECTION INPUT ;
    USE SIGNAL ;
    PORT
      LAYER met2 ;
        RECT 1253.200000 0.000000 1253.340000 0.485000 ;
    END
  END la_oenb[36]
  PIN la_oenb[35]
    DIRECTION INPUT ;
    USE SIGNAL ;
    PORT
      LAYER met2 ;
        RECT 1235.720000 0.000000 1235.860000 0.485000 ;
    END
  END la_oenb[35]
  PIN la_oenb[34]
    DIRECTION INPUT ;
    USE SIGNAL ;
    PORT
      LAYER met2 ;
        RECT 1218.240000 0.000000 1218.380000 0.485000 ;
    END
  END la_oenb[34]
  PIN la_oenb[33]
    DIRECTION INPUT ;
    USE SIGNAL ;
    PORT
      LAYER met2 ;
        RECT 1200.760000 0.000000 1200.900000 0.485000 ;
    END
  END la_oenb[33]
  PIN la_oenb[32]
    DIRECTION INPUT ;
    USE SIGNAL ;
    PORT
      LAYER met2 ;
        RECT 1183.740000 0.000000 1183.880000 0.485000 ;
    END
  END la_oenb[32]
  PIN la_oenb[31]
    DIRECTION INPUT ;
    USE SIGNAL ;
    PORT
      LAYER met2 ;
        RECT 1166.260000 0.000000 1166.400000 0.485000 ;
    END
  END la_oenb[31]
  PIN la_oenb[30]
    DIRECTION INPUT ;
    USE SIGNAL ;
    PORT
      LAYER met2 ;
        RECT 1148.780000 0.000000 1148.920000 0.485000 ;
    END
  END la_oenb[30]
  PIN la_oenb[29]
    DIRECTION INPUT ;
    USE SIGNAL ;
    PORT
      LAYER met2 ;
        RECT 1131.300000 0.000000 1131.440000 0.485000 ;
    END
  END la_oenb[29]
  PIN la_oenb[28]
    DIRECTION INPUT ;
    USE SIGNAL ;
    PORT
      LAYER met2 ;
        RECT 1113.820000 0.000000 1113.960000 0.485000 ;
    END
  END la_oenb[28]
  PIN la_oenb[27]
    DIRECTION INPUT ;
    USE SIGNAL ;
    PORT
      LAYER met2 ;
        RECT 1096.800000 0.000000 1096.940000 0.485000 ;
    END
  END la_oenb[27]
  PIN la_oenb[26]
    DIRECTION INPUT ;
    USE SIGNAL ;
    PORT
      LAYER met2 ;
        RECT 1079.320000 0.000000 1079.460000 0.485000 ;
    END
  END la_oenb[26]
  PIN la_oenb[25]
    DIRECTION INPUT ;
    USE SIGNAL ;
    PORT
      LAYER met2 ;
        RECT 1061.840000 0.000000 1061.980000 0.485000 ;
    END
  END la_oenb[25]
  PIN la_oenb[24]
    DIRECTION INPUT ;
    USE SIGNAL ;
    PORT
      LAYER met2 ;
        RECT 1044.360000 0.000000 1044.500000 0.485000 ;
    END
  END la_oenb[24]
  PIN la_oenb[23]
    DIRECTION INPUT ;
    USE SIGNAL ;
    PORT
      LAYER met2 ;
        RECT 1026.880000 0.000000 1027.020000 0.485000 ;
    END
  END la_oenb[23]
  PIN la_oenb[22]
    DIRECTION INPUT ;
    USE SIGNAL ;
    PORT
      LAYER met2 ;
        RECT 1009.400000 0.000000 1009.540000 0.485000 ;
    END
  END la_oenb[22]
  PIN la_oenb[21]
    DIRECTION INPUT ;
    USE SIGNAL ;
    PORT
      LAYER met2 ;
        RECT 992.380000 0.000000 992.520000 0.485000 ;
    END
  END la_oenb[21]
  PIN la_oenb[20]
    DIRECTION INPUT ;
    USE SIGNAL ;
    PORT
      LAYER met2 ;
        RECT 974.900000 0.000000 975.040000 0.485000 ;
    END
  END la_oenb[20]
  PIN la_oenb[19]
    DIRECTION INPUT ;
    USE SIGNAL ;
    PORT
      LAYER met2 ;
        RECT 957.420000 0.000000 957.560000 0.485000 ;
    END
  END la_oenb[19]
  PIN la_oenb[18]
    DIRECTION INPUT ;
    USE SIGNAL ;
    PORT
      LAYER met2 ;
        RECT 939.940000 0.000000 940.080000 0.485000 ;
    END
  END la_oenb[18]
  PIN la_oenb[17]
    DIRECTION INPUT ;
    USE SIGNAL ;
    PORT
      LAYER met2 ;
        RECT 922.460000 0.000000 922.600000 0.485000 ;
    END
  END la_oenb[17]
  PIN la_oenb[16]
    DIRECTION INPUT ;
    USE SIGNAL ;
    PORT
      LAYER met2 ;
        RECT 904.980000 0.000000 905.120000 0.485000 ;
    END
  END la_oenb[16]
  PIN la_oenb[15]
    DIRECTION INPUT ;
    USE SIGNAL ;
    PORT
      LAYER met2 ;
        RECT 887.960000 0.000000 888.100000 0.485000 ;
    END
  END la_oenb[15]
  PIN la_oenb[14]
    DIRECTION INPUT ;
    USE SIGNAL ;
    PORT
      LAYER met2 ;
        RECT 870.480000 0.000000 870.620000 0.485000 ;
    END
  END la_oenb[14]
  PIN la_oenb[13]
    DIRECTION INPUT ;
    USE SIGNAL ;
    PORT
      LAYER met2 ;
        RECT 853.000000 0.000000 853.140000 0.485000 ;
    END
  END la_oenb[13]
  PIN la_oenb[12]
    DIRECTION INPUT ;
    USE SIGNAL ;
    PORT
      LAYER met2 ;
        RECT 835.520000 0.000000 835.660000 0.485000 ;
    END
  END la_oenb[12]
  PIN la_oenb[11]
    DIRECTION INPUT ;
    USE SIGNAL ;
    PORT
      LAYER met2 ;
        RECT 818.040000 0.000000 818.180000 0.485000 ;
    END
  END la_oenb[11]
  PIN la_oenb[10]
    DIRECTION INPUT ;
    USE SIGNAL ;
    PORT
      LAYER met2 ;
        RECT 800.560000 0.000000 800.700000 0.485000 ;
    END
  END la_oenb[10]
  PIN la_oenb[9]
    DIRECTION INPUT ;
    USE SIGNAL ;
    PORT
      LAYER met2 ;
        RECT 783.540000 0.000000 783.680000 0.485000 ;
    END
  END la_oenb[9]
  PIN la_oenb[8]
    DIRECTION INPUT ;
    USE SIGNAL ;
    PORT
      LAYER met2 ;
        RECT 766.060000 0.000000 766.200000 0.485000 ;
    END
  END la_oenb[8]
  PIN la_oenb[7]
    DIRECTION INPUT ;
    USE SIGNAL ;
    PORT
      LAYER met2 ;
        RECT 748.580000 0.000000 748.720000 0.485000 ;
    END
  END la_oenb[7]
  PIN la_oenb[6]
    DIRECTION INPUT ;
    USE SIGNAL ;
    PORT
      LAYER met2 ;
        RECT 731.100000 0.000000 731.240000 0.485000 ;
    END
  END la_oenb[6]
  PIN la_oenb[5]
    DIRECTION INPUT ;
    USE SIGNAL ;
    PORT
      LAYER met2 ;
        RECT 713.620000 0.000000 713.760000 0.485000 ;
    END
  END la_oenb[5]
  PIN la_oenb[4]
    DIRECTION INPUT ;
    USE SIGNAL ;
    PORT
      LAYER met2 ;
        RECT 696.600000 0.000000 696.740000 0.485000 ;
    END
  END la_oenb[4]
  PIN la_oenb[3]
    DIRECTION INPUT ;
    USE SIGNAL ;
    PORT
      LAYER met2 ;
        RECT 679.120000 0.000000 679.260000 0.485000 ;
    END
  END la_oenb[3]
  PIN la_oenb[2]
    DIRECTION INPUT ;
    USE SIGNAL ;
    PORT
      LAYER met2 ;
        RECT 661.640000 0.000000 661.780000 0.485000 ;
    END
  END la_oenb[2]
  PIN la_oenb[1]
    DIRECTION INPUT ;
    USE SIGNAL ;
    PORT
      LAYER met2 ;
        RECT 644.160000 0.000000 644.300000 0.485000 ;
    END
  END la_oenb[1]
  PIN la_oenb[0]
    DIRECTION INPUT ;
    USE SIGNAL ;
    PORT
      LAYER met2 ;
        RECT 626.680000 0.000000 626.820000 0.485000 ;
    END
  END la_oenb[0]
  PIN io_in[37]
    DIRECTION INPUT ;
    USE SIGNAL ;
    ANTENNAPARTIALMETALAREA 7.6164 LAYER met3  ;
    ANTENNAPARTIALMETALSIDEAREA 40.616 LAYER met3  ;
    ANTENNAMODEL OXIDE1 ;
    ANTENNAGATEAREA 0.159 LAYER met3  ;
    ANTENNAMAXAREACAR 83.4041 LAYER met3  ;
    ANTENNAMAXSIDEAREACAR 426.692 LAYER met3  ;
    ANTENNAMAXCUTCAR 0.574843 LAYER via3  ;
    PORT
      LAYER met3 ;
        RECT 0.000000 169.490000 0.800000 169.790000 ;
    END
  END io_in[37]
  PIN io_in[36]
    DIRECTION INPUT ;
    USE SIGNAL ;
    ANTENNAPARTIALMETALAREA 1.3813 LAYER met3  ;
    ANTENNAPARTIALMETALSIDEAREA 7.832 LAYER met3  ;
    ANTENNAPARTIALCUTAREA 0.04 LAYER via3  ;
    ANTENNAPARTIALMETALAREA 3.9618 LAYER met4  ;
    ANTENNAPARTIALMETALSIDEAREA 21.6 LAYER met4  ;
    ANTENNAMODEL OXIDE1 ;
    ANTENNAGATEAREA 0.315 LAYER met4  ;
    ANTENNAMAXAREACAR 68.3886 LAYER met4  ;
    ANTENNAMAXSIDEAREACAR 345.733 LAYER met4  ;
    ANTENNAMAXCUTCAR 0.417143 LAYER via4  ;
    PORT
      LAYER met3 ;
        RECT 0.000000 423.250000 0.800000 423.550000 ;
    END
  END io_in[36]
  PIN io_in[35]
    DIRECTION INPUT ;
    USE SIGNAL ;
    ANTENNAPARTIALMETALAREA 0.6913 LAYER met3  ;
    ANTENNAPARTIALMETALSIDEAREA 4.152 LAYER met3  ;
    ANTENNAPARTIALCUTAREA 0.04 LAYER via3  ;
    ANTENNAPARTIALMETALAREA 4.1448 LAYER met4  ;
    ANTENNAPARTIALMETALSIDEAREA 22.576 LAYER met4  ;
    ANTENNAMODEL OXIDE1 ;
    ANTENNAGATEAREA 0.315 LAYER met4  ;
    ANTENNAMAXAREACAR 50.0673 LAYER met4  ;
    ANTENNAMAXSIDEAREACAR 254.321 LAYER met4  ;
    ANTENNAMAXCUTCAR 0.417143 LAYER via4  ;
    PORT
      LAYER met3 ;
        RECT 0.000000 677.010000 0.800000 677.310000 ;
    END
  END io_in[35]
  PIN io_in[34]
    DIRECTION INPUT ;
    USE SIGNAL ;
    ANTENNAPARTIALMETALAREA 0.4194 LAYER met3  ;
    ANTENNAPARTIALMETALSIDEAREA 2.68 LAYER met3  ;
    ANTENNAPARTIALCUTAREA 0.04 LAYER via3  ;
    ANTENNAPARTIALMETALAREA 3.9618 LAYER met4  ;
    ANTENNAPARTIALMETALSIDEAREA 21.6 LAYER met4  ;
    ANTENNAMODEL OXIDE1 ;
    ANTENNAGATEAREA 0.315 LAYER met4  ;
    ANTENNAMAXAREACAR 34.846 LAYER met4  ;
    ANTENNAMAXSIDEAREACAR 177.956 LAYER met4  ;
    ANTENNAMAXCUTCAR 0.417143 LAYER via4  ;
    PORT
      LAYER met3 ;
        RECT 0.000000 930.770000 0.800000 931.070000 ;
    END
  END io_in[34]
  PIN io_in[33]
    DIRECTION INPUT ;
    USE SIGNAL ;
    ANTENNAPARTIALMETALAREA 0.6954 LAYER met3  ;
    ANTENNAPARTIALMETALSIDEAREA 4.152 LAYER met3  ;
    ANTENNAPARTIALCUTAREA 0.04 LAYER via3  ;
    ANTENNAPARTIALMETALAREA 8.1708 LAYER met4  ;
    ANTENNAPARTIALMETALSIDEAREA 44.048 LAYER met4  ;
    ANTENNAMODEL OXIDE1 ;
    ANTENNAGATEAREA 0.159 LAYER met4  ;
    ANTENNAMAXAREACAR 132.012 LAYER met4  ;
    ANTENNAMAXSIDEAREACAR 678.717 LAYER met4  ;
    ANTENNAMAXCUTCAR 0.826415 LAYER via4  ;
    PORT
      LAYER met3 ;
        RECT 0.000000 1184.530000 0.800000 1184.830000 ;
    END
  END io_in[33]
  PIN io_in[32]
    DIRECTION INPUT ;
    USE SIGNAL ;
    ANTENNAPARTIALMETALAREA 0.6354 LAYER met3  ;
    ANTENNAPARTIALMETALSIDEAREA 3.832 LAYER met3  ;
    ANTENNAPARTIALCUTAREA 0.04 LAYER via3  ;
    ANTENNAPARTIALMETALAREA 4.1448 LAYER met4  ;
    ANTENNAPARTIALMETALSIDEAREA 22.576 LAYER met4  ;
    ANTENNAMODEL OXIDE1 ;
    ANTENNAGATEAREA 0.159 LAYER met4  ;
    ANTENNAMAXAREACAR 65.8003 LAYER met4  ;
    ANTENNAMAXSIDEAREACAR 339.22 LAYER met4  ;
    ANTENNAMAXCUTCAR 0.826415 LAYER via4  ;
    PORT
      LAYER met3 ;
        RECT 0.000000 1438.900000 0.800000 1439.200000 ;
    END
  END io_in[32]
  PIN io_in[31]
    DIRECTION INPUT ;
    USE SIGNAL ;
    ANTENNAPARTIALMETALAREA 1.2433 LAYER met3  ;
    ANTENNAPARTIALMETALSIDEAREA 7.096 LAYER met3  ;
    ANTENNAPARTIALCUTAREA 0.04 LAYER via3  ;
    ANTENNAPARTIALMETALAREA 3.9618 LAYER met4  ;
    ANTENNAPARTIALMETALSIDEAREA 21.6 LAYER met4  ;
    ANTENNAMODEL OXIDE1 ;
    ANTENNAGATEAREA 0.159 LAYER met4  ;
    ANTENNAMAXAREACAR 43.2261 LAYER met4  ;
    ANTENNAMAXSIDEAREACAR 225.352 LAYER met4  ;
    ANTENNAMAXCUTCAR 0.826415 LAYER via4  ;
    PORT
      LAYER met3 ;
        RECT 0.000000 1692.660000 0.800000 1692.960000 ;
    END
  END io_in[31]
  PIN io_in[30]
    DIRECTION INPUT ;
    USE SIGNAL ;
    ANTENNAPARTIALMETALAREA 10.3126 LAYER met3  ;
    ANTENNAPARTIALMETALSIDEAREA 54.992 LAYER met3  ;
    ANTENNAPARTIALCUTAREA 0.04 LAYER via3  ;
    ANTENNAPARTIALMETALAREA 4.7964 LAYER met4  ;
    ANTENNAPARTIALMETALSIDEAREA 26.992 LAYER met4  ;
    ANTENNAMODEL OXIDE1 ;
    ANTENNAGATEAREA 0.159 LAYER met4  ;
    ANTENNAMAXAREACAR 64.2292 LAYER met4  ;
    ANTENNAMAXSIDEAREACAR 334.233 LAYER met4  ;
    ANTENNAMAXCUTCAR 0.826415 LAYER via4  ;
    PORT
      LAYER met3 ;
        RECT 0.000000 1946.420000 0.800000 1946.720000 ;
    END
  END io_in[30]
  PIN io_in[29]
    DIRECTION INPUT ;
    USE SIGNAL ;
    ANTENNAPARTIALMETALAREA 0.4194 LAYER met3  ;
    ANTENNAPARTIALMETALSIDEAREA 2.68 LAYER met3  ;
    ANTENNAPARTIALCUTAREA 0.04 LAYER via3  ;
    ANTENNAPARTIALMETALAREA 4.1448 LAYER met4  ;
    ANTENNAPARTIALMETALSIDEAREA 22.576 LAYER met4  ;
    ANTENNAMODEL OXIDE1 ;
    ANTENNAGATEAREA 0.159 LAYER met4  ;
    ANTENNAMAXAREACAR 59.2758 LAYER met4  ;
    ANTENNAMAXSIDEAREACAR 306.597 LAYER met4  ;
    ANTENNAMAXCUTCAR 0.826415 LAYER via4  ;
    PORT
      LAYER met3 ;
        RECT 0.000000 2200.180000 0.800000 2200.480000 ;
    END
  END io_in[29]
  PIN io_in[28]
    DIRECTION INPUT ;
    USE SIGNAL ;
    ANTENNAPARTIALMETALAREA 1.3813 LAYER met3  ;
    ANTENNAPARTIALMETALSIDEAREA 7.832 LAYER met3  ;
    ANTENNAPARTIALCUTAREA 0.04 LAYER via3  ;
    ANTENNAPARTIALMETALAREA 3.9618 LAYER met4  ;
    ANTENNAPARTIALMETALSIDEAREA 21.6 LAYER met4  ;
    ANTENNAMODEL OXIDE1 ;
    ANTENNAGATEAREA 0.159 LAYER met4  ;
    ANTENNAMAXAREACAR 52.6777 LAYER met4  ;
    ANTENNAMAXSIDEAREACAR 273.12 LAYER met4  ;
    ANTENNAMAXCUTCAR 0.826415 LAYER via4  ;
    PORT
      LAYER met3 ;
        RECT 0.000000 2453.940000 0.800000 2454.240000 ;
    END
  END io_in[28]
  PIN io_in[27]
    DIRECTION INPUT ;
    USE SIGNAL ;
    ANTENNAPARTIALMETALAREA 10.3126 LAYER met3  ;
    ANTENNAPARTIALMETALSIDEAREA 54.992 LAYER met3  ;
    ANTENNAPARTIALCUTAREA 0.04 LAYER via3  ;
    ANTENNAPARTIALMETALAREA 4.7964 LAYER met4  ;
    ANTENNAPARTIALMETALSIDEAREA 26.992 LAYER met4  ;
    ANTENNAMODEL OXIDE1 ;
    ANTENNAGATEAREA 0.159 LAYER met4  ;
    ANTENNAMAXAREACAR 47.3928 LAYER met4  ;
    ANTENNAMAXSIDEAREACAR 254.465 LAYER met4  ;
    ANTENNAMAXCUTCAR 0.826415 LAYER via4  ;
    PORT
      LAYER met3 ;
        RECT 0.000000 2707.700000 0.800000 2708.000000 ;
    END
  END io_in[27]
  PIN io_in[26]
    DIRECTION INPUT ;
    USE SIGNAL ;
    ANTENNAPARTIALMETALAREA 0.4194 LAYER met3  ;
    ANTENNAPARTIALMETALSIDEAREA 2.68 LAYER met3  ;
    ANTENNAPARTIALCUTAREA 0.04 LAYER via3  ;
    ANTENNAPARTIALMETALAREA 3.9618 LAYER met4  ;
    ANTENNAPARTIALMETALSIDEAREA 21.6 LAYER met4  ;
    ANTENNAMODEL OXIDE1 ;
    ANTENNAGATEAREA 0.159 LAYER met4  ;
    ANTENNAMAXAREACAR 71.7676 LAYER met4  ;
    ANTENNAMAXSIDEAREACAR 362.868 LAYER met4  ;
    ANTENNAMAXCUTCAR 0.826415 LAYER via4  ;
    PORT
      LAYER met3 ;
        RECT 0.000000 2961.460000 0.800000 2961.760000 ;
    END
  END io_in[26]
  PIN io_in[25]
    DIRECTION INPUT ;
    USE SIGNAL ;
    ANTENNAPARTIALMETALAREA 0.1644 LAYER met3  ;
    ANTENNAPARTIALMETALSIDEAREA 0.872 LAYER met3  ;
    ANTENNAMODEL OXIDE1 ;
    ANTENNAGATEAREA 0.495 LAYER met3  ;
    ANTENNAMAXAREACAR 79.9014 LAYER met3  ;
    ANTENNAMAXSIDEAREACAR 398.507 LAYER met3  ;
    ANTENNAMAXCUTCAR 0.184646 LAYER via3  ;
    PORT
      LAYER met3 ;
        RECT 0.000000 3215.220000 0.800000 3215.520000 ;
    END
  END io_in[25]
  PIN io_in[24]
    DIRECTION INPUT ;
    USE SIGNAL ;
    ANTENNAPARTIALMETALAREA 0.4404 LAYER met3  ;
    ANTENNAPARTIALMETALSIDEAREA 2.344 LAYER met3  ;
    ANTENNAMODEL OXIDE1 ;
    ANTENNAGATEAREA 0.315 LAYER met3  ;
    ANTENNAMAXAREACAR 35.2606 LAYER met3  ;
    ANTENNAMAXSIDEAREACAR 172.352 LAYER met3  ;
    ANTENNAMAXCUTCAR 0.290159 LAYER via3  ;
    PORT
      LAYER met3 ;
        RECT 0.000000 3469.590000 0.800000 3469.890000 ;
    END
  END io_in[24]
  PIN io_in[23]
    DIRECTION INPUT ;
    USE SIGNAL ;
    ANTENNAPARTIALMETALAREA 31.8206 LAYER met2  ;
    ANTENNAPARTIALMETALSIDEAREA 158.942 LAYER met2  ;
    ANTENNAPARTIALCUTAREA 0.04 LAYER via2  ;
    ANTENNAPARTIALMETALAREA 0.255 LAYER met3  ;
    ANTENNAPARTIALMETALSIDEAREA 1.808 LAYER met3  ;
    ANTENNAPARTIALCUTAREA 0.04 LAYER via3  ;
    ANTENNAPARTIALMETALAREA 8.1708 LAYER met4  ;
    ANTENNAPARTIALMETALSIDEAREA 44.048 LAYER met4  ;
    ANTENNAMODEL OXIDE1 ;
    ANTENNAGATEAREA 0.159 LAYER met4  ;
    ANTENNAMAXAREACAR 84.867 LAYER met4  ;
    ANTENNAMAXSIDEAREACAR 441.509 LAYER met4  ;
    ANTENNAMAXCUTCAR 0.826415 LAYER via4  ;
    PORT
      LAYER met2 ;
        RECT 220.040000 3469.555000 220.180000 3470.040000 ;
    END
  END io_in[23]
  PIN io_in[22]
    DIRECTION INPUT ;
    USE SIGNAL ;
    ANTENNAPARTIALMETALAREA 43.082 LAYER met2  ;
    ANTENNAPARTIALMETALSIDEAREA 215.131 LAYER met2  ;
    ANTENNAPARTIALCUTAREA 0.04 LAYER via2  ;
    ANTENNAPARTIALMETALAREA 0.991 LAYER met3  ;
    ANTENNAPARTIALMETALSIDEAREA 5.752 LAYER met3  ;
    ANTENNAPARTIALCUTAREA 0.04 LAYER via3  ;
    ANTENNAPARTIALMETALAREA 3.7788 LAYER met4  ;
    ANTENNAPARTIALMETALSIDEAREA 20.624 LAYER met4  ;
    ANTENNAMODEL OXIDE1 ;
    ANTENNAGATEAREA 0.495 LAYER met4  ;
    ANTENNAMAXAREACAR 11.3002 LAYER met4  ;
    ANTENNAMAXSIDEAREACAR 60.5051 LAYER met4  ;
    ANTENNAMAXCUTCAR 0.265455 LAYER via4  ;
    PORT
      LAYER met2 ;
        RECT 549.860000 3469.555000 550.000000 3470.040000 ;
    END
  END io_in[22]
  PIN io_in[21]
    DIRECTION INPUT ;
    USE SIGNAL ;
    ANTENNAPARTIALMETALAREA 36.8382 LAYER met2  ;
    ANTENNAPARTIALMETALSIDEAREA 184.03 LAYER met2  ;
    ANTENNAPARTIALCUTAREA 0.04 LAYER via2  ;
    ANTENNAPARTIALMETALAREA 90.556 LAYER met3  ;
    ANTENNAPARTIALMETALSIDEAREA 483.432 LAYER met3  ;
    ANTENNAPARTIALCUTAREA 0.04 LAYER via3  ;
    ANTENNADIFFAREA 0.4347 LAYER met4  ;
    ANTENNAPARTIALMETALAREA 41.8668 LAYER met4  ;
    ANTENNAPARTIALMETALSIDEAREA 223.76 LAYER met4  ;
    ANTENNAMODEL OXIDE1 ;
    ANTENNAGATEAREA 0.315 LAYER met4  ;
    ANTENNAMAXAREACAR 147.889 LAYER met4  ;
    ANTENNAMAXSIDEAREACAR 759.479 LAYER met4  ;
    ANTENNAMAXCUTCAR 0.417143 LAYER via4  ;
    PORT
      LAYER met2 ;
        RECT 879.680000 3469.555000 879.820000 3470.040000 ;
    END
  END io_in[21]
  PIN io_in[20]
    DIRECTION INPUT ;
    USE SIGNAL ;
    ANTENNAPARTIALMETALAREA 8.0794 LAYER met2  ;
    ANTENNAPARTIALMETALSIDEAREA 40.236 LAYER met2  ;
    ANTENNAPARTIALCUTAREA 0.04 LAYER via2  ;
    ANTENNAPARTIALMETALAREA 2.125 LAYER met3  ;
    ANTENNAPARTIALMETALSIDEAREA 11.8 LAYER met3  ;
    ANTENNAPARTIALCUTAREA 0.04 LAYER via3  ;
    ANTENNADIFFAREA 0.4347 LAYER met4  ;
    ANTENNAPARTIALMETALAREA 91.4358 LAYER met4  ;
    ANTENNAPARTIALMETALSIDEAREA 488.128 LAYER met4  ;
    ANTENNAMODEL OXIDE1 ;
    ANTENNAGATEAREA 0.576 LAYER met4  ;
    ANTENNAMAXAREACAR 202.054 LAYER met4  ;
    ANTENNAMAXSIDEAREACAR 1048.29 LAYER met4  ;
    ANTENNAMAXCUTCAR 0.228125 LAYER via4  ;
    PORT
      LAYER met2 ;
        RECT 1209.500000 3469.555000 1209.640000 3470.040000 ;
    END
  END io_in[20]
  PIN io_in[19]
    DIRECTION INPUT ;
    USE SIGNAL ;
    ANTENNAPARTIALMETALAREA 0.1386 LAYER met2  ;
    ANTENNAPARTIALMETALSIDEAREA 0.532 LAYER met2  ;
    ANTENNAPARTIALCUTAREA 0.04 LAYER via2  ;
    ANTENNAPARTIALMETALAREA 1.642 LAYER met3  ;
    ANTENNAPARTIALMETALSIDEAREA 9.224 LAYER met3  ;
    ANTENNAPARTIALCUTAREA 0.04 LAYER via3  ;
    ANTENNADIFFAREA 0.4347 LAYER met4  ;
    ANTENNAPARTIALMETALAREA 156.044 LAYER met4  ;
    ANTENNAPARTIALMETALSIDEAREA 832.704 LAYER met4  ;
    ANTENNAMODEL OXIDE1 ;
    ANTENNAGATEAREA 0.576 LAYER met4  ;
    ANTENNAMAXAREACAR 277.211 LAYER met4  ;
    ANTENNAMAXSIDEAREACAR 1461.74 LAYER met4  ;
    ANTENNAMAXCUTCAR 0.228125 LAYER via4  ;
    PORT
      LAYER met2 ;
        RECT 1539.780000 3469.555000 1539.920000 3470.040000 ;
    END
  END io_in[19]
  PIN io_in[18]
    DIRECTION INPUT ;
    USE SIGNAL ;
    ANTENNAPARTIALMETALAREA 50.2556 LAYER met2  ;
    ANTENNAPARTIALMETALSIDEAREA 250.999 LAYER met2  ;
    ANTENNAPARTIALCUTAREA 0.04 LAYER via2  ;
    ANTENNAPARTIALMETALAREA 0.255 LAYER met3  ;
    ANTENNAPARTIALMETALSIDEAREA 1.808 LAYER met3  ;
    ANTENNAPARTIALCUTAREA 0.04 LAYER via3  ;
    ANTENNAPARTIALMETALAREA 6.1578 LAYER met4  ;
    ANTENNAPARTIALMETALSIDEAREA 33.312 LAYER met4  ;
    ANTENNAMODEL OXIDE1 ;
    ANTENNAGATEAREA 0.576 LAYER met4  ;
    ANTENNAMAXAREACAR 20.625 LAYER met4  ;
    ANTENNAMAXSIDEAREACAR 105.191 LAYER met4  ;
    ANTENNAMAXCUTCAR 0.228125 LAYER via4  ;
    PORT
      LAYER met2 ;
        RECT 1869.600000 3469.555000 1869.740000 3470.040000 ;
    END
  END io_in[18]
  PIN io_in[17]
    DIRECTION INPUT ;
    USE SIGNAL ;
    ANTENNAPARTIALMETALAREA 46.3386 LAYER met2  ;
    ANTENNAPARTIALMETALSIDEAREA 231.532 LAYER met2  ;
    ANTENNAPARTIALCUTAREA 0.04 LAYER via2  ;
    ANTENNAPARTIALMETALAREA 0.2509 LAYER met3  ;
    ANTENNAPARTIALMETALSIDEAREA 1.808 LAYER met3  ;
    ANTENNAPARTIALCUTAREA 0.04 LAYER via3  ;
    ANTENNAPARTIALMETALAREA 4.1448 LAYER met4  ;
    ANTENNAPARTIALMETALSIDEAREA 22.576 LAYER met4  ;
    ANTENNAMODEL OXIDE1 ;
    ANTENNAGATEAREA 0.495 LAYER met4  ;
    ANTENNAMAXAREACAR 11.6244 LAYER met4  ;
    ANTENNAMAXSIDEAREACAR 61.6424 LAYER met4  ;
    ANTENNAMAXCUTCAR 0.265455 LAYER via4  ;
    PORT
      LAYER met2 ;
        RECT 2199.420000 3469.555000 2199.560000 3470.040000 ;
    END
  END io_in[17]
  PIN io_in[16]
    DIRECTION INPUT ;
    USE SIGNAL ;
    ANTENNAPARTIALMETALAREA 9.3939 LAYER met2  ;
    ANTENNAPARTIALMETALSIDEAREA 46.8615 LAYER met2  ;
    ANTENNAMODEL OXIDE1 ;
    ANTENNAGATEAREA 0.99 LAYER met2  ;
    ANTENNAMAXAREACAR 43.497 LAYER met2  ;
    ANTENNAMAXSIDEAREACAR 215.619 LAYER met2  ;
    ANTENNAMAXCUTCAR 0.0519192 LAYER via2  ;
    PORT
      LAYER met2 ;
        RECT 2529.240000 3469.555000 2529.380000 3470.040000 ;
    END
  END io_in[16]
  PIN io_in[15]
    DIRECTION INPUT ;
    USE SIGNAL ;
    ANTENNAPARTIALMETALAREA 52.2746 LAYER met2  ;
    ANTENNAPARTIALMETALSIDEAREA 261.212 LAYER met2  ;
    ANTENNAPARTIALCUTAREA 0.04 LAYER via2  ;
    ANTENNAPARTIALMETALAREA 0.255 LAYER met3  ;
    ANTENNAPARTIALMETALSIDEAREA 1.808 LAYER met3  ;
    ANTENNAPARTIALCUTAREA 0.04 LAYER via3  ;
    ANTENNAPARTIALMETALAREA 3.9618 LAYER met4  ;
    ANTENNAPARTIALMETALSIDEAREA 21.6 LAYER met4  ;
    ANTENNAMODEL OXIDE1 ;
    ANTENNAGATEAREA 0.159 LAYER met4  ;
    ANTENNAMAXAREACAR 90.1664 LAYER met4  ;
    ANTENNAMAXSIDEAREACAR 460.667 LAYER met4  ;
    ANTENNAMAXCUTCAR 0.826415 LAYER via4  ;
    PORT
      LAYER met2 ;
        RECT 2859.060000 3469.555000 2859.200000 3470.040000 ;
    END
  END io_in[15]
  PIN io_in[14]
    DIRECTION INPUT ;
    USE SIGNAL ;
    ANTENNAPARTIALMETALAREA 9.6864 LAYER met3  ;
    ANTENNAPARTIALMETALSIDEAREA 51.656 LAYER met3  ;
    ANTENNAMODEL OXIDE1 ;
    ANTENNAGATEAREA 0.315 LAYER met3  ;
    ANTENNAMAXAREACAR 37.9464 LAYER met3  ;
    ANTENNAMAXSIDEAREACAR 195.565 LAYER met3  ;
    ANTENNAMAXCUTCAR 0.290159 LAYER via3  ;
    PORT
      LAYER met3 ;
        RECT 2859.020000 3312.210000 2859.820000 3312.510000 ;
    END
  END io_in[14]
  PIN io_in[13]
    DIRECTION INPUT ;
    USE SIGNAL ;
    ANTENNAPARTIALMETALAREA 8.9964 LAYER met3  ;
    ANTENNAPARTIALMETALSIDEAREA 47.976 LAYER met3  ;
    ANTENNAMODEL OXIDE1 ;
    ANTENNAGATEAREA 0.495 LAYER met3  ;
    ANTENNAMAXAREACAR 26.6576 LAYER met3  ;
    ANTENNAMAXSIDEAREACAR 136.626 LAYER met3  ;
    ANTENNAMAXCUTCAR 0.184646 LAYER via3  ;
    PORT
      LAYER met3 ;
        RECT 2859.020000 3075.530000 2859.820000 3075.830000 ;
    END
  END io_in[13]
  PIN io_in[12]
    DIRECTION INPUT ;
    USE SIGNAL ;
    ANTENNAPARTIALMETALAREA 1.2474 LAYER met3  ;
    ANTENNAPARTIALMETALSIDEAREA 7.096 LAYER met3  ;
    ANTENNAPARTIALCUTAREA 0.04 LAYER via3  ;
    ANTENNAPARTIALMETALAREA 4.5108 LAYER met4  ;
    ANTENNAPARTIALMETALSIDEAREA 24.528 LAYER met4  ;
    ANTENNAMODEL OXIDE1 ;
    ANTENNAGATEAREA 0.159 LAYER met4  ;
    ANTENNAMAXAREACAR 66.2116 LAYER met4  ;
    ANTENNAMAXSIDEAREACAR 341.811 LAYER met4  ;
    ANTENNAMAXCUTCAR 0.826415 LAYER via4  ;
    PORT
      LAYER met3 ;
        RECT 2859.020000 2838.850000 2859.820000 2839.150000 ;
    END
  END io_in[12]
  PIN io_in[11]
    DIRECTION INPUT ;
    USE SIGNAL ;
    ANTENNAPARTIALMETALAREA 168.656 LAYER met3  ;
    ANTENNAPARTIALMETALSIDEAREA 899.488 LAYER met3  ;
    ANTENNAPARTIALCUTAREA 0.04 LAYER via3  ;
    ANTENNAPARTIALMETALAREA 0.8106 LAYER met4  ;
    ANTENNAPARTIALMETALSIDEAREA 5.264 LAYER met4  ;
    ANTENNAMODEL OXIDE1 ;
    ANTENNAGATEAREA 0.159 LAYER met4  ;
    ANTENNAMAXAREACAR 27.9374 LAYER met4  ;
    ANTENNAMAXSIDEAREACAR 145.126 LAYER met4  ;
    ANTENNAMAXCUTCAR 0.826415 LAYER via4  ;
    PORT
      LAYER met3 ;
        RECT 2859.020000 2602.780000 2859.820000 2603.080000 ;
    END
  END io_in[11]
  PIN io_in[10]
    DIRECTION INPUT ;
    USE SIGNAL ;
    ANTENNAPARTIALMETALAREA 0.5533 LAYER met3  ;
    ANTENNAPARTIALMETALSIDEAREA 3.416 LAYER met3  ;
    ANTENNAPARTIALCUTAREA 0.04 LAYER via3  ;
    ANTENNAPARTIALMETALAREA 4.1448 LAYER met4  ;
    ANTENNAPARTIALMETALSIDEAREA 22.576 LAYER met4  ;
    ANTENNAMODEL OXIDE1 ;
    ANTENNAGATEAREA 0.315 LAYER met4  ;
    ANTENNAMAXAREACAR 41.6762 LAYER met4  ;
    ANTENNAMAXSIDEAREACAR 212.365 LAYER met4  ;
    ANTENNAMAXCUTCAR 0.417143 LAYER via4  ;
    PORT
      LAYER met3 ;
        RECT 2859.020000 2366.100000 2859.820000 2366.400000 ;
    END
  END io_in[10]
  PIN io_in[9]
    DIRECTION INPUT ;
    USE SIGNAL ;
    ANTENNAPARTIALMETALAREA 7.8924 LAYER met3  ;
    ANTENNAPARTIALMETALSIDEAREA 42.088 LAYER met3  ;
    ANTENNAMODEL OXIDE1 ;
    ANTENNAGATEAREA 0.495 LAYER met3  ;
    ANTENNAMAXAREACAR 76.1653 LAYER met3  ;
    ANTENNAMAXSIDEAREACAR 385.03 LAYER met3  ;
    ANTENNAMAXCUTCAR 0.184646 LAYER via3  ;
    PORT
      LAYER met3 ;
        RECT 2859.020000 2129.420000 2859.820000 2129.720000 ;
    END
  END io_in[9]
  PIN io_in[8]
    DIRECTION INPUT ;
    USE SIGNAL ;
    ANTENNAPARTIALMETALAREA 120.9 LAYER met3  ;
    ANTENNAPARTIALMETALSIDEAREA 645.264 LAYER met3  ;
    ANTENNAPARTIALCUTAREA 0.04 LAYER via3  ;
    ANTENNAPARTIALMETALAREA 0.6516 LAYER met4  ;
    ANTENNAPARTIALMETALSIDEAREA 4.416 LAYER met4  ;
    ANTENNAMODEL OXIDE1 ;
    ANTENNAGATEAREA 0.495 LAYER met4  ;
    ANTENNAMAXAREACAR 8.45838 LAYER met4  ;
    ANTENNAMAXSIDEAREACAR 43.9455 LAYER met4  ;
    ANTENNAMAXCUTCAR 0.265455 LAYER via4  ;
    PORT
      LAYER met3 ;
        RECT 2859.020000 1892.740000 2859.820000 1893.040000 ;
    END
  END io_in[8]
  PIN io_in[7]
    DIRECTION INPUT ;
    USE SIGNAL ;
    ANTENNAPARTIALMETALAREA 130.695 LAYER met3  ;
    ANTENNAPARTIALMETALSIDEAREA 697.504 LAYER met3  ;
    ANTENNAPARTIALCUTAREA 0.04 LAYER via3  ;
    ANTENNAPARTIALMETALAREA 0.6516 LAYER met4  ;
    ANTENNAPARTIALMETALSIDEAREA 4.416 LAYER met4  ;
    ANTENNAMODEL OXIDE1 ;
    ANTENNAGATEAREA 0.213 LAYER met4  ;
    ANTENNAMAXAREACAR 18.9028 LAYER met4  ;
    ANTENNAMAXSIDEAREACAR 100.15 LAYER met4  ;
    ANTENNAMAXCUTCAR 0.616901 LAYER via4  ;
    PORT
      LAYER met3 ;
        RECT 2859.020000 1656.670000 2859.820000 1656.970000 ;
    END
  END io_in[7]
  PIN io_in[6]
    DIRECTION INPUT ;
    USE SIGNAL ;
    ANTENNADIFFAREA 0.4347 LAYER met3  ;
    ANTENNAPARTIALMETALAREA 0.7464 LAYER met3  ;
    ANTENNAPARTIALMETALSIDEAREA 3.976 LAYER met3  ;
    ANTENNAMODEL OXIDE1 ;
    ANTENNAGATEAREA 0.159 LAYER met3  ;
    ANTENNAMAXAREACAR 222.765 LAYER met3  ;
    ANTENNAMAXSIDEAREACAR 1059.79 LAYER met3  ;
    ANTENNAMAXCUTCAR 0.574843 LAYER via3  ;
    PORT
      LAYER met3 ;
        RECT 2859.020000 1419.990000 2859.820000 1420.290000 ;
    END
  END io_in[6]
  PIN io_in[5]
    DIRECTION INPUT ;
    USE SIGNAL ;
    ANTENNAPARTIALMETALAREA 15.2064 LAYER met3  ;
    ANTENNAPARTIALMETALSIDEAREA 81.096 LAYER met3  ;
    ANTENNAMODEL OXIDE1 ;
    ANTENNAGATEAREA 0.495 LAYER met3  ;
    ANTENNAMAXAREACAR 33.9335 LAYER met3  ;
    ANTENNAMAXSIDEAREACAR 177.251 LAYER met3  ;
    ANTENNAMAXCUTCAR 0.184646 LAYER via3  ;
    PORT
      LAYER met3 ;
        RECT 2859.020000 1183.310000 2859.820000 1183.610000 ;
    END
  END io_in[5]
  PIN io_in[4]
    DIRECTION INPUT ;
    USE SIGNAL ;
    ANTENNAPARTIALMETALAREA 13.2796 LAYER met3  ;
    ANTENNAPARTIALMETALSIDEAREA 70.816 LAYER met3  ;
    ANTENNAPARTIALCUTAREA 0.04 LAYER via3  ;
    ANTENNAPARTIALMETALAREA 4.6134 LAYER met4  ;
    ANTENNAPARTIALMETALSIDEAREA 26.016 LAYER met4  ;
    ANTENNAMODEL OXIDE1 ;
    ANTENNAGATEAREA 0.159 LAYER met4  ;
    ANTENNAMAXAREACAR 55.628 LAYER met4  ;
    ANTENNAMAXSIDEAREACAR 290.101 LAYER met4  ;
    ANTENNAMAXCUTCAR 0.826415 LAYER via4  ;
    PORT
      LAYER met3 ;
        RECT 2859.020000 946.630000 2859.820000 946.930000 ;
    END
  END io_in[4]
  PIN io_in[3]
    DIRECTION INPUT ;
    USE SIGNAL ;
    ANTENNAPARTIALMETALAREA 18.7944 LAYER met3  ;
    ANTENNAPARTIALMETALSIDEAREA 100.232 LAYER met3  ;
    ANTENNAMODEL OXIDE1 ;
    ANTENNAGATEAREA 0.315 LAYER met3  ;
    ANTENNAMAXAREACAR 87.334 LAYER met3  ;
    ANTENNAMAXSIDEAREACAR 452.73 LAYER met3  ;
    ANTENNAMAXCUTCAR 0.290159 LAYER via3  ;
    PORT
      LAYER met3 ;
        RECT 2859.020000 710.560000 2859.820000 710.860000 ;
    END
  END io_in[3]
  PIN io_in[2]
    DIRECTION INPUT ;
    USE SIGNAL ;
    ANTENNAPARTIALMETALAREA 1.5444 LAYER met3  ;
    ANTENNAPARTIALMETALSIDEAREA 8.232 LAYER met3  ;
    ANTENNAMODEL OXIDE1 ;
    ANTENNAGATEAREA 0.495 LAYER met3  ;
    ANTENNAMAXAREACAR 63.7065 LAYER met3  ;
    ANTENNAMAXSIDEAREACAR 318.36 LAYER met3  ;
    ANTENNAMAXCUTCAR 0.184646 LAYER via3  ;
    PORT
      LAYER met3 ;
        RECT 2859.020000 473.880000 2859.820000 474.180000 ;
    END
  END io_in[2]
  PIN io_in[1]
    DIRECTION INPUT ;
    USE SIGNAL ;
    ANTENNAPARTIALMETALAREA 15.0684 LAYER met3  ;
    ANTENNAPARTIALMETALSIDEAREA 80.36 LAYER met3  ;
    ANTENNAMODEL OXIDE1 ;
    ANTENNAGATEAREA 0.576 LAYER met3  ;
    ANTENNAMAXAREACAR 68.4753 LAYER met3  ;
    ANTENNAMAXSIDEAREACAR 348.776 LAYER met3  ;
    ANTENNAMAXCUTCAR 0.158681 LAYER via3  ;
    PORT
      LAYER met3 ;
        RECT 2859.020000 237.200000 2859.820000 237.500000 ;
    END
  END io_in[1]
  PIN io_in[0]
    DIRECTION INPUT ;
    USE SIGNAL ;
    ANTENNAPARTIALMETALAREA 12.5844 LAYER met3  ;
    ANTENNAPARTIALMETALSIDEAREA 67.112 LAYER met3  ;
    ANTENNAMODEL OXIDE1 ;
    ANTENNAGATEAREA 0.576 LAYER met3  ;
    ANTENNAMAXAREACAR 31.1665 LAYER met3  ;
    ANTENNAMAXSIDEAREACAR 160.911 LAYER met3  ;
    ANTENNAMAXCUTCAR 0.158681 LAYER via3  ;
    PORT
      LAYER met3 ;
        RECT 2859.020000 0.520000 2859.820000 0.820000 ;
    END
  END io_in[0]
  PIN io_out[37]
    DIRECTION OUTPUT ;
    USE SIGNAL ;
    ANTENNADIFFAREA 0.336 LAYER met3  ;
    ANTENNAPARTIALMETALAREA 0.3804 LAYER met3  ;
    ANTENNAPARTIALMETALSIDEAREA 2.024 LAYER met3  ;
    PORT
      LAYER met3 ;
        RECT 0.000000 84.700000 0.800000 85.000000 ;
    END
  END io_out[37]
  PIN io_out[36]
    DIRECTION OUTPUT ;
    USE SIGNAL ;
    ANTENNADIFFAREA 0.336 LAYER met3  ;
    ANTENNAPARTIALMETALAREA 1.9584 LAYER met3  ;
    ANTENNAPARTIALMETALSIDEAREA 10.44 LAYER met3  ;
    PORT
      LAYER met3 ;
        RECT 0.000000 338.460000 0.800000 338.760000 ;
    END
  END io_out[36]
  PIN io_out[35]
    DIRECTION OUTPUT ;
    USE SIGNAL ;
    ANTENNADIFFAREA 0.336 LAYER met3  ;
    ANTENNAPARTIALMETALAREA 14.3784 LAYER met3  ;
    ANTENNAPARTIALMETALSIDEAREA 76.68 LAYER met3  ;
    PORT
      LAYER met3 ;
        RECT 0.000000 592.220000 0.800000 592.520000 ;
    END
  END io_out[35]
  PIN io_out[34]
    DIRECTION OUTPUT ;
    USE SIGNAL ;
    ANTENNADIFFAREA 0.336 LAYER met3  ;
    ANTENNAPARTIALMETALAREA 6.0984 LAYER met3  ;
    ANTENNAPARTIALMETALSIDEAREA 32.52 LAYER met3  ;
    PORT
      LAYER met3 ;
        RECT 0.000000 846.590000 0.800000 846.890000 ;
    END
  END io_out[34]
  PIN io_out[33]
    DIRECTION OUTPUT ;
    USE SIGNAL ;
    ANTENNADIFFAREA 0.4455 LAYER met3  ;
    ANTENNAPARTIALMETALAREA 0.9924 LAYER met3  ;
    ANTENNAPARTIALMETALSIDEAREA 5.288 LAYER met3  ;
    PORT
      LAYER met3 ;
        RECT 0.000000 1100.350000 0.800000 1100.650000 ;
    END
  END io_out[33]
  PIN io_out[32]
    DIRECTION OUTPUT ;
    USE SIGNAL ;
    ANTENNAPARTIALMETALAREA 70.4446 LAYER met3  ;
    ANTENNAPARTIALMETALSIDEAREA 375.696 LAYER met3  ;
    ANTENNAPARTIALCUTAREA 0.04 LAYER via3  ;
    ANTENNADIFFAREA 0.4455 LAYER met4  ;
    ANTENNAPARTIALMETALAREA 19.173 LAYER met4  ;
    ANTENNAPARTIALMETALSIDEAREA 104.608 LAYER met4  ;
    PORT
      LAYER met3 ;
        RECT 0.000000 1354.110000 0.800000 1354.410000 ;
    END
  END io_out[32]
  PIN io_out[31]
    DIRECTION OUTPUT ;
    USE SIGNAL ;
    ANTENNADIFFAREA 0.4455 LAYER met3  ;
    ANTENNAPARTIALMETALAREA 0.4404 LAYER met3  ;
    ANTENNAPARTIALMETALSIDEAREA 2.344 LAYER met3  ;
    PORT
      LAYER met3 ;
        RECT 0.000000 1607.870000 0.800000 1608.170000 ;
    END
  END io_out[31]
  PIN io_out[30]
    DIRECTION OUTPUT ;
    USE SIGNAL ;
    ANTENNAPARTIALMETALAREA 127.187 LAYER met3  ;
    ANTENNAPARTIALMETALSIDEAREA 678.32 LAYER met3  ;
    ANTENNAPARTIALCUTAREA 0.04 LAYER via3  ;
    ANTENNADIFFAREA 0.4455 LAYER met4  ;
    ANTENNAPARTIALMETALAREA 1.5828 LAYER met4  ;
    ANTENNAPARTIALMETALSIDEAREA 8.912 LAYER met4  ;
    PORT
      LAYER met3 ;
        RECT 0.000000 1861.630000 0.800000 1861.930000 ;
    END
  END io_out[30]
  PIN io_out[29]
    DIRECTION OUTPUT ;
    USE SIGNAL ;
    ANTENNADIFFAREA 0.336 LAYER met3  ;
    ANTENNAPARTIALMETALAREA 8.1684 LAYER met3  ;
    ANTENNAPARTIALMETALSIDEAREA 43.56 LAYER met3  ;
    PORT
      LAYER met3 ;
        RECT 0.000000 2115.390000 0.800000 2115.690000 ;
    END
  END io_out[29]
  PIN io_out[28]
    DIRECTION OUTPUT ;
    USE SIGNAL ;
    ANTENNADIFFAREA 0.891 LAYER met3  ;
    ANTENNAPARTIALMETALAREA 15.7362 LAYER met3  ;
    ANTENNAPARTIALMETALSIDEAREA 84.392 LAYER met3  ;
    PORT
      LAYER met3 ;
        RECT 0.000000 2369.150000 0.800000 2369.450000 ;
    END
  END io_out[28]
  PIN io_out[27]
    DIRECTION OUTPUT ;
    USE SIGNAL ;
    ANTENNADIFFAREA 0.891 LAYER met3  ;
    ANTENNAPARTIALMETALAREA 6.0984 LAYER met3  ;
    ANTENNAPARTIALMETALSIDEAREA 32.52 LAYER met3  ;
    PORT
      LAYER met3 ;
        RECT 0.000000 2622.910000 0.800000 2623.210000 ;
    END
  END io_out[27]
  PIN io_out[26]
    DIRECTION OUTPUT ;
    USE SIGNAL ;
    ANTENNADIFFAREA 0.891 LAYER met3  ;
    ANTENNAPARTIALMETALAREA 0.4404 LAYER met3  ;
    ANTENNAPARTIALMETALSIDEAREA 2.344 LAYER met3  ;
    PORT
      LAYER met3 ;
        RECT 0.000000 2877.280000 0.800000 2877.580000 ;
    END
  END io_out[26]
  PIN io_out[25]
    DIRECTION OUTPUT ;
    USE SIGNAL ;
    ANTENNADIFFAREA 0.336 LAYER met3  ;
    ANTENNAPARTIALMETALAREA 6.0984 LAYER met3  ;
    ANTENNAPARTIALMETALSIDEAREA 32.52 LAYER met3  ;
    PORT
      LAYER met3 ;
        RECT 0.000000 3131.040000 0.800000 3131.340000 ;
    END
  END io_out[25]
  PIN io_out[24]
    DIRECTION OUTPUT ;
    USE SIGNAL ;
    ANTENNADIFFAREA 0.336 LAYER met3  ;
    ANTENNAPARTIALMETALAREA 10.7904 LAYER met3  ;
    ANTENNAPARTIALMETALSIDEAREA 57.544 LAYER met3  ;
    PORT
      LAYER met3 ;
        RECT 0.000000 3384.800000 0.800000 3385.100000 ;
    END
  END io_out[24]
  PIN io_out[23]
    DIRECTION OUTPUT ;
    USE SIGNAL ;
    ANTENNADIFFAREA 0.6626 LAYER met2  ;
    ANTENNAPARTIALMETALAREA 69.5127 LAYER met2  ;
    ANTENNAPARTIALMETALSIDEAREA 347.455 LAYER met2  ;
    PORT
      LAYER met2 ;
        RECT 110.100000 3469.555000 110.240000 3470.040000 ;
    END
  END io_out[23]
  PIN io_out[22]
    DIRECTION OUTPUT ;
    USE SIGNAL ;
    ANTENNADIFFAREA 1.3365 LAYER met2  ;
    ANTENNAPARTIALMETALAREA 4.4699 LAYER met2  ;
    ANTENNAPARTIALMETALSIDEAREA 22.1235 LAYER met2  ;
    PORT
      LAYER met2 ;
        RECT 439.920000 3469.555000 440.060000 3470.040000 ;
    END
  END io_out[22]
  PIN io_out[21]
    DIRECTION OUTPUT ;
    USE SIGNAL ;
    ANTENNADIFFAREA 0.4455 LAYER met2  ;
    ANTENNAPARTIALMETALAREA 19.6755 LAYER met2  ;
    ANTENNAPARTIALMETALSIDEAREA 98.2695 LAYER met2  ;
    PORT
      LAYER met2 ;
        RECT 769.740000 3469.555000 769.880000 3470.040000 ;
    END
  END io_out[21]
  PIN io_out[20]
    DIRECTION OUTPUT ;
    USE SIGNAL ;
    ANTENNAPARTIALMETALAREA 43.1158 LAYER met2  ;
    ANTENNAPARTIALMETALSIDEAREA 215.418 LAYER met2  ;
    ANTENNAPARTIALCUTAREA 0.04 LAYER via2  ;
    ANTENNAPARTIALMETALAREA 33.217 LAYER met3  ;
    ANTENNAPARTIALMETALSIDEAREA 177.624 LAYER met3  ;
    ANTENNAPARTIALCUTAREA 0.04 LAYER via3  ;
    ANTENNADIFFAREA 0.4455 LAYER met4  ;
    ANTENNAPARTIALMETALAREA 22.6278 LAYER met4  ;
    ANTENNAPARTIALMETALSIDEAREA 121.152 LAYER met4  ;
    PORT
      LAYER met2 ;
        RECT 1099.560000 3469.555000 1099.700000 3470.040000 ;
    END
  END io_out[20]
  PIN io_out[19]
    DIRECTION OUTPUT ;
    USE SIGNAL ;
    ANTENNAPARTIALMETALAREA 0.2016 LAYER met2  ;
    ANTENNAPARTIALMETALSIDEAREA 0.847 LAYER met2  ;
    ANTENNAPARTIALCUTAREA 0.04 LAYER via2  ;
    ANTENNAPARTIALMETALAREA 1.021 LAYER met3  ;
    ANTENNAPARTIALMETALSIDEAREA 5.912 LAYER met3  ;
    ANTENNAPARTIALCUTAREA 0.04 LAYER via3  ;
    ANTENNADIFFAREA 0.6626 LAYER met4  ;
    ANTENNAPARTIALMETALAREA 195.763 LAYER met4  ;
    ANTENNAPARTIALMETALSIDEAREA 1045.01 LAYER met4  ;
    PORT
      LAYER met2 ;
        RECT 1429.380000 3469.555000 1429.520000 3470.040000 ;
    END
  END io_out[19]
  PIN io_out[18]
    DIRECTION OUTPUT ;
    USE SIGNAL ;
    ANTENNADIFFAREA 0.4455 LAYER met2  ;
    ANTENNAPARTIALMETALAREA 4.7767 LAYER met2  ;
    ANTENNAPARTIALMETALSIDEAREA 23.7755 LAYER met2  ;
    PORT
      LAYER met2 ;
        RECT 1759.660000 3469.555000 1759.800000 3470.040000 ;
    END
  END io_out[18]
  PIN io_out[17]
    DIRECTION OUTPUT ;
    USE SIGNAL ;
    ANTENNADIFFAREA 0.336 LAYER met2  ;
    ANTENNAPARTIALMETALAREA 6.7071 LAYER met2  ;
    ANTENNAPARTIALMETALSIDEAREA 33.3095 LAYER met2  ;
    PORT
      LAYER met2 ;
        RECT 2089.480000 3469.555000 2089.620000 3470.040000 ;
    END
  END io_out[17]
  PIN io_out[16]
    DIRECTION OUTPUT ;
    USE SIGNAL ;
    ANTENNADIFFAREA 0.336 LAYER met2  ;
    ANTENNAPARTIALMETALAREA 24.6259 LAYER met2  ;
    ANTENNAPARTIALMETALSIDEAREA 123.022 LAYER met2  ;
    PORT
      LAYER met2 ;
        RECT 2419.300000 3469.555000 2419.440000 3470.040000 ;
    END
  END io_out[16]
  PIN io_out[15]
    DIRECTION OUTPUT ;
    USE SIGNAL ;
    ANTENNADIFFAREA 0.336 LAYER met2  ;
    ANTENNAPARTIALMETALAREA 69.4651 LAYER met2  ;
    ANTENNAPARTIALMETALSIDEAREA 347.217 LAYER met2  ;
    PORT
      LAYER met2 ;
        RECT 2749.120000 3469.555000 2749.260000 3470.040000 ;
    END
  END io_out[15]
  PIN io_out[14]
    DIRECTION OUTPUT ;
    USE SIGNAL ;
    ANTENNADIFFAREA 1.3365 LAYER met3  ;
    ANTENNAPARTIALMETALAREA 15.0684 LAYER met3  ;
    ANTENNAPARTIALMETALSIDEAREA 80.36 LAYER met3  ;
    PORT
      LAYER met3 ;
        RECT 2859.020000 3390.900000 2859.820000 3391.200000 ;
    END
  END io_out[14]
  PIN io_out[13]
    DIRECTION OUTPUT ;
    USE SIGNAL ;
    ANTENNADIFFAREA 0.336 LAYER met3  ;
    ANTENNAPARTIALMETALAREA 0.5634 LAYER met3  ;
    ANTENNAPARTIALMETALSIDEAREA 3 LAYER met3  ;
    PORT
      LAYER met3 ;
        RECT 2859.020000 3154.220000 2859.820000 3154.520000 ;
    END
  END io_out[13]
  PIN io_out[12]
    DIRECTION OUTPUT ;
    USE SIGNAL ;
    ANTENNADIFFAREA 0.4455 LAYER met3  ;
    ANTENNAPARTIALMETALAREA 0.1644 LAYER met3  ;
    ANTENNAPARTIALMETALSIDEAREA 0.872 LAYER met3  ;
    PORT
      LAYER met3 ;
        RECT 2859.020000 2918.150000 2859.820000 2918.450000 ;
    END
  END io_out[12]
  PIN io_out[11]
    DIRECTION OUTPUT ;
    USE SIGNAL ;
    ANTENNADIFFAREA 0.4455 LAYER met3  ;
    ANTENNAPARTIALMETALAREA 0.5784 LAYER met3  ;
    ANTENNAPARTIALMETALSIDEAREA 3.08 LAYER met3  ;
    PORT
      LAYER met3 ;
        RECT 2859.020000 2681.470000 2859.820000 2681.770000 ;
    END
  END io_out[11]
  PIN io_out[10]
    DIRECTION OUTPUT ;
    USE SIGNAL ;
    ANTENNADIFFAREA 0.336 LAYER met3  ;
    ANTENNAPARTIALMETALAREA 11.3424 LAYER met3  ;
    ANTENNAPARTIALMETALSIDEAREA 60.488 LAYER met3  ;
    PORT
      LAYER met3 ;
        RECT 2859.020000 2444.790000 2859.820000 2445.090000 ;
    END
  END io_out[10]
  PIN io_out[9]
    DIRECTION OUTPUT ;
    USE SIGNAL ;
    ANTENNADIFFAREA 0.336 LAYER met3  ;
    ANTENNAPARTIALMETALAREA 12.9984 LAYER met3  ;
    ANTENNAPARTIALMETALSIDEAREA 69.32 LAYER met3  ;
    PORT
      LAYER met3 ;
        RECT 2859.020000 2208.110000 2859.820000 2208.410000 ;
    END
  END io_out[9]
  PIN io_out[8]
    DIRECTION OUTPUT ;
    USE SIGNAL ;
    ANTENNADIFFAREA 0.3406 LAYER met3  ;
    ANTENNAPARTIALMETALAREA 1.5444 LAYER met3  ;
    ANTENNAPARTIALMETALSIDEAREA 8.232 LAYER met3  ;
    PORT
      LAYER met3 ;
        RECT 2859.020000 1972.040000 2859.820000 1972.340000 ;
    END
  END io_out[8]
  PIN io_out[7]
    DIRECTION OUTPUT ;
    USE SIGNAL ;
    ANTENNADIFFAREA 0.336 LAYER met3  ;
    ANTENNAPARTIALMETALAREA 9.1344 LAYER met3  ;
    ANTENNAPARTIALMETALSIDEAREA 48.712 LAYER met3  ;
    PORT
      LAYER met3 ;
        RECT 2859.020000 1735.360000 2859.820000 1735.660000 ;
    END
  END io_out[7]
  PIN io_out[6]
    DIRECTION OUTPUT ;
    USE SIGNAL ;
    ANTENNADIFFAREA 0.336 LAYER met3  ;
    ANTENNAPARTIALMETALAREA 10.9284 LAYER met3  ;
    ANTENNAPARTIALMETALSIDEAREA 58.28 LAYER met3  ;
    PORT
      LAYER met3 ;
        RECT 2859.020000 1498.680000 2859.820000 1498.980000 ;
    END
  END io_out[6]
  PIN io_out[5]
    DIRECTION OUTPUT ;
    USE SIGNAL ;
    ANTENNADIFFAREA 0.6626 LAYER met3  ;
    ANTENNAPARTIALMETALAREA 0.4404 LAYER met3  ;
    ANTENNAPARTIALMETALSIDEAREA 2.344 LAYER met3  ;
    PORT
      LAYER met3 ;
        RECT 2859.020000 1262.000000 2859.820000 1262.300000 ;
    END
  END io_out[5]
  PIN io_out[4]
    DIRECTION OUTPUT ;
    USE SIGNAL ;
    ANTENNADIFFAREA 0.6626 LAYER met3  ;
    ANTENNAPARTIALMETALAREA 0.1644 LAYER met3  ;
    ANTENNAPARTIALMETALSIDEAREA 0.872 LAYER met3  ;
    PORT
      LAYER met3 ;
        RECT 2859.020000 1025.930000 2859.820000 1026.230000 ;
    END
  END io_out[4]
  PIN io_out[3]
    DIRECTION OUTPUT ;
    USE SIGNAL ;
    ANTENNADIFFAREA 0.6626 LAYER met3  ;
    ANTENNAPARTIALMETALAREA 0.9924 LAYER met3  ;
    ANTENNAPARTIALMETALSIDEAREA 5.288 LAYER met3  ;
    PORT
      LAYER met3 ;
        RECT 2859.020000 789.250000 2859.820000 789.550000 ;
    END
  END io_out[3]
  PIN io_out[2]
    DIRECTION OUTPUT ;
    USE SIGNAL ;
    ANTENNADIFFAREA 0.4455 LAYER met3  ;
    ANTENNAPARTIALMETALAREA 0.8064 LAYER met3  ;
    ANTENNAPARTIALMETALSIDEAREA 4.296 LAYER met3  ;
    PORT
      LAYER met3 ;
        RECT 2859.020000 552.570000 2859.820000 552.870000 ;
    END
  END io_out[2]
  PIN io_out[1]
    DIRECTION OUTPUT ;
    USE SIGNAL ;
    ANTENNADIFFAREA 0.4455 LAYER met3  ;
    ANTENNAPARTIALMETALAREA 0.1644 LAYER met3  ;
    ANTENNAPARTIALMETALSIDEAREA 0.872 LAYER met3  ;
    PORT
      LAYER met3 ;
        RECT 2859.020000 315.890000 2859.820000 316.190000 ;
    END
  END io_out[1]
  PIN io_out[0]
    DIRECTION OUTPUT ;
    USE SIGNAL ;
    ANTENNADIFFAREA 0.336 LAYER met3  ;
    ANTENNAPARTIALMETALAREA 15.0684 LAYER met3  ;
    ANTENNAPARTIALMETALSIDEAREA 80.36 LAYER met3  ;
    PORT
      LAYER met3 ;
        RECT 2859.020000 79.820000 2859.820000 80.120000 ;
    END
  END io_out[0]
  PIN io_oeb[37]
    DIRECTION OUTPUT ;
    USE SIGNAL ;
    ANTENNADIFFAREA 0.4455 LAYER met3  ;
    ANTENNAPARTIALMETALAREA 0.7068 LAYER met3  ;
    ANTENNAPARTIALMETALSIDEAREA 4.24 LAYER met3  ;
    ANTENNAMODEL OXIDE1 ;
    ANTENNAGATEAREA 0.159 LAYER met3  ;
    ANTENNAMAXAREACAR 4.44528 LAYER met3  ;
    ANTENNAMAXSIDEAREACAR 26.6667 LAYER met3  ;
    PORT
      LAYER met3 ;
        RECT 0.000000 0.520000 0.800000 0.820000 ;
    END
  END io_oeb[37]
  PIN io_oeb[36]
    DIRECTION OUTPUT ;
    USE SIGNAL ;
    ANTENNADIFFAREA 0.4455 LAYER met3  ;
    ANTENNAPARTIALMETALAREA 0.8268 LAYER met3  ;
    ANTENNAPARTIALMETALSIDEAREA 5.36 LAYER met3  ;
    ANTENNAMODEL OXIDE1 ;
    ANTENNAGATEAREA 0.159 LAYER met3  ;
    ANTENNAMAXAREACAR 264.083 LAYER met3  ;
    ANTENNAMAXSIDEAREACAR 1321.65 LAYER met3  ;
    ANTENNAMAXCUTCAR 0.826415 LAYER via3  ;
    PORT
      LAYER met3 ;
        RECT 0.000000 254.280000 0.800000 254.580000 ;
    END
  END io_oeb[36]
  PIN io_oeb[35]
    DIRECTION OUTPUT ;
    USE SIGNAL ;
    ANTENNADIFFAREA 0.4455 LAYER met3  ;
    ANTENNAPARTIALMETALAREA 8.8584 LAYER met3  ;
    ANTENNAPARTIALMETALSIDEAREA 47.24 LAYER met3  ;
    ANTENNAMODEL OXIDE1 ;
    ANTENNAGATEAREA 0.159 LAYER met3  ;
    ANTENNAMAXAREACAR 499.041 LAYER met3  ;
    ANTENNAMAXSIDEAREACAR 2503.87 LAYER met3  ;
    ANTENNAMAXCUTCAR 0.574843 LAYER via3  ;
    PORT
      LAYER met3 ;
        RECT 0.000000 508.040000 0.800000 508.340000 ;
    END
  END io_oeb[35]
  PIN io_oeb[34]
    DIRECTION OUTPUT ;
    USE SIGNAL ;
    ANTENNADIFFAREA 0.4455 LAYER met3  ;
    ANTENNAPARTIALMETALAREA 3.2658 LAYER met3  ;
    ANTENNAPARTIALMETALSIDEAREA 18.336 LAYER met3  ;
    ANTENNAPARTIALCUTAREA 0.04 LAYER via3  ;
    ANTENNADIFFAREA 0.4455 LAYER met4  ;
    ANTENNAPARTIALMETALAREA 3.9618 LAYER met4  ;
    ANTENNAPARTIALMETALSIDEAREA 21.6 LAYER met4  ;
    ANTENNAMODEL OXIDE1 ;
    ANTENNAGATEAREA 0.159 LAYER met4  ;
    ANTENNAMAXAREACAR 24.917 LAYER met4  ;
    ANTENNAMAXSIDEAREACAR 135.849 LAYER met4  ;
    PORT
      LAYER met3 ;
        RECT 0.000000 761.800000 0.800000 762.100000 ;
    END
  END io_oeb[34]
  PIN io_oeb[33]
    DIRECTION OUTPUT ;
    USE SIGNAL ;
    ANTENNAPARTIALMETALAREA 1.9194 LAYER met3  ;
    ANTENNAPARTIALMETALSIDEAREA 11.16 LAYER met3  ;
    ANTENNAMODEL OXIDE1 ;
    ANTENNAGATEAREA 0.159 LAYER met3  ;
    ANTENNAMAXAREACAR 41.0695 LAYER met3  ;
    ANTENNAMAXSIDEAREACAR 209.384 LAYER met3  ;
    ANTENNAPARTIALCUTAREA 0.04 LAYER via3  ;
    ANTENNAMAXCUTCAR 1.07799 LAYER via3  ;
    ANTENNADIFFAREA 0.4455 LAYER met4  ;
    ANTENNAPARTIALMETALAREA 3.9618 LAYER met4  ;
    ANTENNAPARTIALMETALSIDEAREA 21.6 LAYER met4  ;
    ANTENNAGATEAREA 0.159 LAYER met4  ;
    ANTENNAMAXAREACAR 65.9865 LAYER met4  ;
    ANTENNAMAXSIDEAREACAR 345.233 LAYER met4  ;
    ANTENNAMAXCUTCAR 1.07799 LAYER via4  ;
    PORT
      LAYER met3 ;
        RECT 0.000000 1015.560000 0.800000 1015.860000 ;
    END
  END io_oeb[33]
  PIN io_oeb[32]
    DIRECTION OUTPUT ;
    USE SIGNAL ;
    ANTENNADIFFAREA 0.4455 LAYER met3  ;
    ANTENNAPARTIALMETALAREA 3.8067 LAYER met3  ;
    ANTENNAPARTIALMETALSIDEAREA 21.248 LAYER met3  ;
    ANTENNAMODEL OXIDE1 ;
    ANTENNAGATEAREA 0.159 LAYER met3  ;
    ANTENNAMAXAREACAR 59.6487 LAYER met3  ;
    ANTENNAMAXSIDEAREACAR 307.39 LAYER met3  ;
    ANTENNAMAXCUTCAR 0.574843 LAYER via3  ;
    PORT
      LAYER met3 ;
        RECT 0.000000 1269.320000 0.800000 1269.620000 ;
    END
  END io_oeb[32]
  PIN io_oeb[31]
    DIRECTION OUTPUT ;
    USE SIGNAL ;
    ANTENNADIFFAREA 0.4455 LAYER met3  ;
    ANTENNAPARTIALMETALAREA 3.8247 LAYER met3  ;
    ANTENNAPARTIALMETALSIDEAREA 21.344 LAYER met3  ;
    ANTENNAMODEL OXIDE1 ;
    ANTENNAGATEAREA 0.159 LAYER met3  ;
    ANTENNAMAXAREACAR 24.0547 LAYER met3  ;
    ANTENNAMAXSIDEAREACAR 134.239 LAYER met3  ;
    PORT
      LAYER met3 ;
        RECT 0.000000 1523.080000 0.800000 1523.380000 ;
    END
  END io_oeb[31]
  PIN io_oeb[30]
    DIRECTION OUTPUT ;
    USE SIGNAL ;
    ANTENNADIFFAREA 0.4455 LAYER met3  ;
    ANTENNAPARTIALMETALAREA 8.3064 LAYER met3  ;
    ANTENNAPARTIALMETALSIDEAREA 44.296 LAYER met3  ;
    ANTENNAMODEL OXIDE1 ;
    ANTENNAGATEAREA 0.159 LAYER met3  ;
    ANTENNAMAXAREACAR 459.237 LAYER met3  ;
    ANTENNAMAXSIDEAREACAR 2305.08 LAYER met3  ;
    ANTENNAMAXCUTCAR 0.574843 LAYER via3  ;
    PORT
      LAYER met3 ;
        RECT 0.000000 1776.840000 0.800000 1777.140000 ;
    END
  END io_oeb[30]
  PIN io_oeb[29]
    DIRECTION OUTPUT ;
    USE SIGNAL ;
    ANTENNADIFFAREA 0.4455 LAYER met3  ;
    ANTENNAPARTIALMETALAREA 1.4064 LAYER met3  ;
    ANTENNAPARTIALMETALSIDEAREA 7.496 LAYER met3  ;
    ANTENNAMODEL OXIDE1 ;
    ANTENNAGATEAREA 0.159 LAYER met3  ;
    ANTENNAMAXAREACAR 290.362 LAYER met3  ;
    ANTENNAMAXSIDEAREACAR 1449.27 LAYER met3  ;
    ANTENNAMAXCUTCAR 0.574843 LAYER via3  ;
    PORT
      LAYER met3 ;
        RECT 0.000000 2030.600000 0.800000 2030.900000 ;
    END
  END io_oeb[29]
  PIN io_oeb[28]
    DIRECTION OUTPUT ;
    USE SIGNAL ;
    ANTENNADIFFAREA 0.4455 LAYER met3  ;
    ANTENNAPARTIALMETALAREA 1.0548 LAYER met3  ;
    ANTENNAPARTIALMETALSIDEAREA 6.576 LAYER met3  ;
    ANTENNAMODEL OXIDE1 ;
    ANTENNAGATEAREA 0.159 LAYER met3  ;
    ANTENNAMAXAREACAR 269.934 LAYER met3  ;
    ANTENNAMAXSIDEAREACAR 1346.97 LAYER met3  ;
    ANTENNAMAXCUTCAR 0.826415 LAYER via3  ;
    PORT
      LAYER met3 ;
        RECT 0.000000 2284.970000 0.800000 2285.270000 ;
    END
  END io_oeb[28]
  PIN io_oeb[27]
    DIRECTION OUTPUT ;
    USE SIGNAL ;
    ANTENNADIFFAREA 0.4455 LAYER met3  ;
    ANTENNAPARTIALMETALAREA 1.0548 LAYER met3  ;
    ANTENNAPARTIALMETALSIDEAREA 6.576 LAYER met3  ;
    ANTENNAMODEL OXIDE1 ;
    ANTENNAGATEAREA 0.159 LAYER met3  ;
    ANTENNAMAXAREACAR 6.63396 LAYER met3  ;
    ANTENNAMAXSIDEAREACAR 41.3585 LAYER met3  ;
    PORT
      LAYER met3 ;
        RECT 0.000000 2538.730000 0.800000 2539.030000 ;
    END
  END io_oeb[27]
  PIN io_oeb[26]
    DIRECTION OUTPUT ;
    USE SIGNAL ;
    ANTENNADIFFAREA 0.4455 LAYER met3  ;
    ANTENNAPARTIALMETALAREA 8.8584 LAYER met3  ;
    ANTENNAPARTIALMETALSIDEAREA 47.24 LAYER met3  ;
    ANTENNAMODEL OXIDE1 ;
    ANTENNAGATEAREA 0.1965 LAYER met3  ;
    ANTENNAMAXAREACAR 380.074 LAYER met3  ;
    ANTENNAMAXSIDEAREACAR 1911.16 LAYER met3  ;
    ANTENNAMAXCUTCAR 0.46514 LAYER via3  ;
    PORT
      LAYER met3 ;
        RECT 0.000000 2792.490000 0.800000 2792.790000 ;
    END
  END io_oeb[26]
  PIN io_oeb[25]
    DIRECTION OUTPUT ;
    USE SIGNAL ;
    ANTENNADIFFAREA 0.336 LAYER met3  ;
    ANTENNAPARTIALMETALAREA 6.6504 LAYER met3  ;
    ANTENNAPARTIALMETALSIDEAREA 35.464 LAYER met3  ;
    PORT
      LAYER met3 ;
        RECT 0.000000 3046.250000 0.800000 3046.550000 ;
    END
  END io_oeb[25]
  PIN io_oeb[24]
    DIRECTION OUTPUT ;
    USE SIGNAL ;
    ANTENNADIFFAREA 0.3406 LAYER met3  ;
    ANTENNAPARTIALMETALAREA 0.2844 LAYER met3  ;
    ANTENNAPARTIALMETALSIDEAREA 1.992 LAYER met3  ;
    ANTENNAMODEL OXIDE1 ;
    ANTENNAGATEAREA 0.315 LAYER met3  ;
    ANTENNAMAXAREACAR 0.902857 LAYER met3  ;
    ANTENNAMAXSIDEAREACAR 6.32381 LAYER met3  ;
    PORT
      LAYER met3 ;
        RECT 0.000000 3300.010000 0.800000 3300.310000 ;
    END
  END io_oeb[24]
  PIN io_oeb[23]
    DIRECTION OUTPUT ;
    USE SIGNAL ;
    ANTENNADIFFAREA 0.3406 LAYER met2  ;
    ANTENNAPARTIALMETALAREA 24.0393 LAYER met2  ;
    ANTENNAPARTIALMETALSIDEAREA 119.991 LAYER met2  ;
    ANTENNAMODEL OXIDE1 ;
    ANTENNAGATEAREA 0.315 LAYER met2  ;
    ANTENNAMAXAREACAR 91.1991 LAYER met2  ;
    ANTENNAMAXSIDEAREACAR 451.889 LAYER met2  ;
    ANTENNAPARTIALCUTAREA 0.04 LAYER via2  ;
    ANTENNAMAXCUTCAR 0.361587 LAYER via2  ;
    ANTENNADIFFAREA 0.3406 LAYER met3  ;
    ANTENNAPARTIALMETALAREA 0.4044 LAYER met3  ;
    ANTENNAPARTIALMETALSIDEAREA 2.632 LAYER met3  ;
    ANTENNAGATEAREA 0.315 LAYER met3  ;
    ANTENNAMAXAREACAR 92.4829 LAYER met3  ;
    ANTENNAMAXSIDEAREACAR 460.244 LAYER met3  ;
    ANTENNAMAXCUTCAR 0.361587 LAYER via3  ;
    PORT
      LAYER met2 ;
        RECT 0.160000 3469.555000 0.300000 3470.040000 ;
    END
  END io_oeb[23]
  PIN io_oeb[22]
    DIRECTION OUTPUT ;
    USE SIGNAL ;
    ANTENNADIFFAREA 0.336 LAYER met2  ;
    ANTENNAPARTIALMETALAREA 9.5597 LAYER met2  ;
    ANTENNAPARTIALMETALSIDEAREA 47.7785 LAYER met2  ;
    ANTENNAMODEL OXIDE1 ;
    ANTENNAGATEAREA 0.159 LAYER met2  ;
    ANTENNAMAXAREACAR 356.068 LAYER met2  ;
    ANTENNAMAXSIDEAREACAR 1770.02 LAYER met2  ;
    ANTENNAMAXCUTCAR 0.46478 LAYER via2  ;
    PORT
      LAYER met2 ;
        RECT 329.980000 3469.555000 330.120000 3470.040000 ;
    END
  END io_oeb[22]
  PIN io_oeb[21]
    DIRECTION OUTPUT ;
    USE SIGNAL ;
    ANTENNADIFFAREA 0.336 LAYER met2  ;
    ANTENNAPARTIALMETALAREA 9.5597 LAYER met2  ;
    ANTENNAPARTIALMETALSIDEAREA 47.7785 LAYER met2  ;
    ANTENNAMODEL OXIDE1 ;
    ANTENNAGATEAREA 0.159 LAYER met2  ;
    ANTENNAMAXAREACAR 60.1239 LAYER met2  ;
    ANTENNAMAXSIDEAREACAR 300.494 LAYER met2  ;
    PORT
      LAYER met2 ;
        RECT 659.800000 3469.555000 659.940000 3470.040000 ;
    END
  END io_oeb[21]
  PIN io_oeb[20]
    DIRECTION OUTPUT ;
    USE SIGNAL ;
    ANTENNADIFFAREA 0.4455 LAYER met2  ;
    ANTENNAPARTIALMETALAREA 11.5193 LAYER met2  ;
    ANTENNAPARTIALMETALSIDEAREA 57.2425 LAYER met2  ;
    ANTENNAMODEL OXIDE1 ;
    ANTENNAGATEAREA 0.1965 LAYER met2  ;
    ANTENNAMAXAREACAR 58.6224 LAYER met2  ;
    ANTENNAMAXSIDEAREACAR 291.31 LAYER met2  ;
    PORT
      LAYER met2 ;
        RECT 989.620000 3469.555000 989.760000 3470.040000 ;
    END
  END io_oeb[20]
  PIN io_oeb[19]
    DIRECTION OUTPUT ;
    USE SIGNAL ;
    ANTENNADIFFAREA 0.4455 LAYER met2  ;
    ANTENNAPARTIALMETALAREA 11.5193 LAYER met2  ;
    ANTENNAPARTIALMETALSIDEAREA 57.2425 LAYER met2  ;
    ANTENNAMODEL OXIDE1 ;
    ANTENNAGATEAREA 0.1965 LAYER met2  ;
    ANTENNAMAXAREACAR 61.3629 LAYER met2  ;
    ANTENNAMAXSIDEAREACAR 297.461 LAYER met2  ;
    ANTENNAMAXCUTCAR 0.261578 LAYER via2  ;
    PORT
      LAYER met2 ;
        RECT 1319.440000 3469.555000 1319.580000 3470.040000 ;
    END
  END io_oeb[19]
  PIN io_oeb[18]
    DIRECTION OUTPUT ;
    USE SIGNAL ;
    ANTENNADIFFAREA 0.3406 LAYER met2  ;
    ANTENNAPARTIALMETALAREA 5.6983 LAYER met2  ;
    ANTENNAPARTIALMETALSIDEAREA 28.1575 LAYER met2  ;
    ANTENNAMODEL OXIDE1 ;
    ANTENNAGATEAREA 0.1965 LAYER met2  ;
    ANTENNAMAXAREACAR 40.3257 LAYER met2  ;
    ANTENNAMAXSIDEAREACAR 197.14 LAYER met2  ;
    ANTENNAMAXCUTCAR 0.261578 LAYER via2  ;
    PORT
      LAYER met2 ;
        RECT 1649.720000 3469.555000 1649.860000 3470.040000 ;
    END
  END io_oeb[18]
  PIN io_oeb[17]
    DIRECTION OUTPUT ;
    USE SIGNAL ;
    ANTENNADIFFAREA 0.4455 LAYER met2  ;
    ANTENNAPARTIALMETALAREA 5.0213 LAYER met2  ;
    ANTENNAPARTIALMETALSIDEAREA 24.7625 LAYER met2  ;
    PORT
      LAYER met2 ;
        RECT 1979.540000 3469.555000 1979.680000 3470.040000 ;
    END
  END io_oeb[17]
  PIN io_oeb[16]
    DIRECTION OUTPUT ;
    USE SIGNAL ;
    ANTENNADIFFAREA 0.4455 LAYER met2  ;
    ANTENNAPARTIALMETALAREA 5.0549 LAYER met2  ;
    ANTENNAPARTIALMETALSIDEAREA 25.0285 LAYER met2  ;
    PORT
      LAYER met2 ;
        RECT 2309.360000 3469.555000 2309.500000 3470.040000 ;
    END
  END io_oeb[16]
  PIN io_oeb[15]
    DIRECTION OUTPUT ;
    USE SIGNAL ;
    ANTENNADIFFAREA 0.4455 LAYER met2  ;
    ANTENNAPARTIALMETALAREA 35.5268 LAYER met2  ;
    ANTENNAPARTIALMETALSIDEAREA 177.247 LAYER met2  ;
    ANTENNAMODEL OXIDE1 ;
    ANTENNAGATEAREA 0.159 LAYER met2  ;
    ANTENNAMAXAREACAR 228.929 LAYER met2  ;
    ANTENNAMAXSIDEAREACAR 1134.09 LAYER met2  ;
    ANTENNAPARTIALCUTAREA 0.04 LAYER via2  ;
    ANTENNAMAXCUTCAR 0.574843 LAYER via2  ;
    ANTENNADIFFAREA 0.4455 LAYER met3  ;
    ANTENNAPARTIALMETALAREA 3.4404 LAYER met3  ;
    ANTENNAPARTIALMETALSIDEAREA 18.824 LAYER met3  ;
    ANTENNAGATEAREA 0.159 LAYER met3  ;
    ANTENNAMAXAREACAR 250.567 LAYER met3  ;
    ANTENNAMAXSIDEAREACAR 1252.48 LAYER met3  ;
    ANTENNAMAXCUTCAR 0.574843 LAYER via3  ;
    PORT
      LAYER met2 ;
        RECT 2639.180000 3469.555000 2639.320000 3470.040000 ;
    END
  END io_oeb[15]
  PIN io_oeb[14]
    DIRECTION OUTPUT ;
    USE SIGNAL ;
    ANTENNADIFFAREA 0.336 LAYER met3  ;
    ANTENNAPARTIALMETALAREA 16.9824 LAYER met3  ;
    ANTENNAPARTIALMETALSIDEAREA 90.568 LAYER met3  ;
    PORT
      LAYER met3 ;
        RECT 2859.020000 3469.590000 2859.820000 3469.890000 ;
    END
  END io_oeb[14]
  PIN io_oeb[13]
    DIRECTION OUTPUT ;
    USE SIGNAL ;
    ANTENNADIFFAREA 0.4455 LAYER met3  ;
    ANTENNAPARTIALMETALAREA 3.3204 LAYER met3  ;
    ANTENNAPARTIALMETALSIDEAREA 18.184 LAYER met3  ;
    ANTENNAMODEL OXIDE1 ;
    ANTENNAGATEAREA 0.159 LAYER met3  ;
    ANTENNAMAXAREACAR 20.883 LAYER met3  ;
    ANTENNAMAXSIDEAREACAR 114.365 LAYER met3  ;
    PORT
      LAYER met3 ;
        RECT 2859.020000 3233.520000 2859.820000 3233.820000 ;
    END
  END io_oeb[13]
  PIN io_oeb[12]
    DIRECTION OUTPUT ;
    USE SIGNAL ;
    ANTENNADIFFAREA 0.4455 LAYER met3  ;
    ANTENNAPARTIALMETALAREA 13.2201 LAYER met3  ;
    ANTENNAPARTIALMETALSIDEAREA 71.416 LAYER met3  ;
    ANTENNAPARTIALCUTAREA 0.04 LAYER via3  ;
    ANTENNADIFFAREA 0.4455 LAYER met4  ;
    ANTENNAPARTIALMETALAREA 4.1448 LAYER met4  ;
    ANTENNAPARTIALMETALSIDEAREA 22.576 LAYER met4  ;
    ANTENNAMODEL OXIDE1 ;
    ANTENNAGATEAREA 0.159 LAYER met4  ;
    ANTENNAMAXAREACAR 26.0679 LAYER met4  ;
    ANTENNAMAXSIDEAREACAR 141.987 LAYER met4  ;
    PORT
      LAYER met3 ;
        RECT 2859.020000 2996.840000 2859.820000 2997.140000 ;
    END
  END io_oeb[12]
  PIN io_oeb[11]
    DIRECTION OUTPUT ;
    USE SIGNAL ;
    ANTENNADIFFAREA 0.4455 LAYER met3  ;
    ANTENNAPARTIALMETALAREA 13.3401 LAYER met3  ;
    ANTENNAPARTIALMETALSIDEAREA 72.536 LAYER met3  ;
    ANTENNAPARTIALCUTAREA 0.04 LAYER via3  ;
    ANTENNADIFFAREA 0.4455 LAYER met4  ;
    ANTENNAPARTIALMETALAREA 4.1448 LAYER met4  ;
    ANTENNAPARTIALMETALSIDEAREA 22.576 LAYER met4  ;
    ANTENNAMODEL OXIDE1 ;
    ANTENNAGATEAREA 0.159 LAYER met4  ;
    ANTENNAMAXAREACAR 51.8003 LAYER met4  ;
    ANTENNAMAXSIDEAREACAR 269.22 LAYER met4  ;
    ANTENNAMAXCUTCAR 0.826415 LAYER via4  ;
    PORT
      LAYER met3 ;
        RECT 2859.020000 2760.160000 2859.820000 2760.460000 ;
    END
  END io_oeb[11]
  PIN io_oeb[10]
    DIRECTION OUTPUT ;
    USE SIGNAL ;
    ANTENNADIFFAREA 0.4455 LAYER met3  ;
    ANTENNAPARTIALMETALAREA 9.2724 LAYER met3  ;
    ANTENNAPARTIALMETALSIDEAREA 49.448 LAYER met3  ;
    ANTENNAMODEL OXIDE1 ;
    ANTENNAGATEAREA 0.159 LAYER met3  ;
    ANTENNAMAXAREACAR 469.289 LAYER met3  ;
    ANTENNAMAXSIDEAREACAR 2354.59 LAYER met3  ;
    ANTENNAMAXCUTCAR 0.574843 LAYER via3  ;
    PORT
      LAYER met3 ;
        RECT 2859.020000 2523.480000 2859.820000 2523.780000 ;
    END
  END io_oeb[10]
  PIN io_oeb[9]
    DIRECTION OUTPUT ;
    USE SIGNAL ;
    ANTENNADIFFAREA 0.4455 LAYER met3  ;
    ANTENNAPARTIALMETALAREA 18.8061 LAYER met3  ;
    ANTENNAPARTIALMETALSIDEAREA 100.76 LAYER met3  ;
    ANTENNAMODEL OXIDE1 ;
    ANTENNAGATEAREA 0.159 LAYER met3  ;
    ANTENNAMAXAREACAR 118.277 LAYER met3  ;
    ANTENNAMAXSIDEAREACAR 633.711 LAYER met3  ;
    PORT
      LAYER met3 ;
        RECT 2859.020000 2287.410000 2859.820000 2287.710000 ;
    END
  END io_oeb[9]
  PIN io_oeb[8]
    DIRECTION OUTPUT ;
    USE SIGNAL ;
    ANTENNADIFFAREA 0.4455 LAYER met3  ;
    ANTENNAPARTIALMETALAREA 18.9261 LAYER met3  ;
    ANTENNAPARTIALMETALSIDEAREA 101.88 LAYER met3  ;
    ANTENNAMODEL OXIDE1 ;
    ANTENNAGATEAREA 0.159 LAYER met3  ;
    ANTENNAMAXAREACAR 125.128 LAYER met3  ;
    ANTENNAMAXSIDEAREACAR 666.453 LAYER met3  ;
    ANTENNAMAXCUTCAR 0.574843 LAYER via3  ;
    PORT
      LAYER met3 ;
        RECT 2859.020000 2050.730000 2859.820000 2051.030000 ;
    END
  END io_oeb[8]
  PIN io_oeb[7]
    DIRECTION OUTPUT ;
    USE SIGNAL ;
    ANTENNADIFFAREA 0.8802 LAYER met3  ;
    ANTENNAPARTIALMETALAREA 8.1102 LAYER met3  ;
    ANTENNAPARTIALMETALSIDEAREA 43.72 LAYER met3  ;
    ANTENNAMODEL OXIDE1 ;
    ANTENNAGATEAREA 0.159 LAYER met3  ;
    ANTENNAMAXAREACAR 51.0075 LAYER met3  ;
    ANTENNAMAXSIDEAREACAR 274.969 LAYER met3  ;
    PORT
      LAYER met3 ;
        RECT 2859.020000 1814.050000 2859.820000 1814.350000 ;
    END
  END io_oeb[7]
  PIN io_oeb[6]
    DIRECTION OUTPUT ;
    USE SIGNAL ;
    ANTENNADIFFAREA 0.8802 LAYER met3  ;
    ANTENNAPARTIALMETALAREA 8.1552 LAYER met3  ;
    ANTENNAPARTIALMETALSIDEAREA 44.44 LAYER met3  ;
    ANTENNAMODEL OXIDE1 ;
    ANTENNAGATEAREA 0.159 LAYER met3  ;
    ANTENNAMAXAREACAR 496.719 LAYER met3  ;
    ANTENNAMAXSIDEAREACAR 2451.53 LAYER met3  ;
    ANTENNAMAXCUTCAR 0.826415 LAYER via3  ;
    PORT
      LAYER met3 ;
        RECT 2859.020000 1577.370000 2859.820000 1577.670000 ;
    END
  END io_oeb[6]
  PIN io_oeb[5]
    DIRECTION OUTPUT ;
    USE SIGNAL ;
    ANTENNADIFFAREA 0.4455 LAYER met3  ;
    ANTENNAPARTIALMETALAREA 9.6864 LAYER met3  ;
    ANTENNAPARTIALMETALSIDEAREA 51.656 LAYER met3  ;
    ANTENNAMODEL OXIDE1 ;
    ANTENNAGATEAREA 0.159 LAYER met3  ;
    ANTENNAMAXAREACAR 406.714 LAYER met3  ;
    ANTENNAMAXSIDEAREACAR 2048.39 LAYER met3  ;
    ANTENNAMAXCUTCAR 0.574843 LAYER via3  ;
    PORT
      LAYER met3 ;
        RECT 2859.020000 1341.300000 2859.820000 1341.600000 ;
    END
  END io_oeb[5]
  PIN io_oeb[4]
    DIRECTION OUTPUT ;
    USE SIGNAL ;
    ANTENNADIFFAREA 0.4455 LAYER met3  ;
    ANTENNAPARTIALMETALAREA 4.1667 LAYER met3  ;
    ANTENNAPARTIALMETALSIDEAREA 22.688 LAYER met3  ;
    ANTENNAMODEL OXIDE1 ;
    ANTENNAGATEAREA 0.159 LAYER met3  ;
    ANTENNAMAXAREACAR 26.2057 LAYER met3  ;
    ANTENNAMAXSIDEAREACAR 142.692 LAYER met3  ;
    PORT
      LAYER met3 ;
        RECT 2859.020000 1104.620000 2859.820000 1104.920000 ;
    END
  END io_oeb[4]
  PIN io_oeb[3]
    DIRECTION OUTPUT ;
    USE SIGNAL ;
    ANTENNADIFFAREA 0.4455 LAYER met3  ;
    ANTENNAPARTIALMETALAREA 4.2867 LAYER met3  ;
    ANTENNAPARTIALMETALSIDEAREA 23.808 LAYER met3  ;
    ANTENNAMODEL OXIDE1 ;
    ANTENNAGATEAREA 0.159 LAYER met3  ;
    ANTENNAMAXAREACAR 52.1016 LAYER met3  ;
    ANTENNAMAXSIDEAREACAR 270.66 LAYER met3  ;
    ANTENNAMAXCUTCAR 0.574843 LAYER via3  ;
    PORT
      LAYER met3 ;
        RECT 2859.020000 867.940000 2859.820000 868.240000 ;
    END
  END io_oeb[3]
  PIN io_oeb[2]
    DIRECTION OUTPUT ;
    USE SIGNAL ;
    ANTENNADIFFAREA 0.4455 LAYER met3  ;
    ANTENNAPARTIALMETALAREA 9.2724 LAYER met3  ;
    ANTENNAPARTIALMETALSIDEAREA 49.448 LAYER met3  ;
    ANTENNAMODEL OXIDE1 ;
    ANTENNAGATEAREA 0.159 LAYER met3  ;
    ANTENNAMAXAREACAR 478.34 LAYER met3  ;
    ANTENNAMAXSIDEAREACAR 2406.07 LAYER met3  ;
    ANTENNAMAXCUTCAR 0.574843 LAYER via3  ;
    PORT
      LAYER met3 ;
        RECT 2859.020000 631.260000 2859.820000 631.560000 ;
    END
  END io_oeb[2]
  PIN io_oeb[1]
    DIRECTION OUTPUT ;
    USE SIGNAL ;
    ANTENNADIFFAREA 0.336 LAYER met3  ;
    ANTENNAPARTIALMETALAREA 18.0948 LAYER met3  ;
    ANTENNAPARTIALMETALSIDEAREA 96.976 LAYER met3  ;
    ANTENNAMODEL OXIDE1 ;
    ANTENNAGATEAREA 0.159 LAYER met3  ;
    ANTENNAMAXAREACAR 113.804 LAYER met3  ;
    ANTENNAMAXSIDEAREACAR 609.912 LAYER met3  ;
    PORT
      LAYER met3 ;
        RECT 2859.020000 395.190000 2859.820000 395.490000 ;
    END
  END io_oeb[1]
  PIN io_oeb[0]
    DIRECTION OUTPUT ;
    USE SIGNAL ;
    ANTENNADIFFAREA 0.336 LAYER met3  ;
    ANTENNAPARTIALMETALAREA 18.2148 LAYER met3  ;
    ANTENNAPARTIALMETALSIDEAREA 98.096 LAYER met3  ;
    ANTENNAMODEL OXIDE1 ;
    ANTENNAGATEAREA 0.159 LAYER met3  ;
    ANTENNAMAXAREACAR 328.422 LAYER met3  ;
    ANTENNAMAXSIDEAREACAR 1679.8 LAYER met3  ;
    ANTENNAMAXCUTCAR 0.826415 LAYER via3  ;
    PORT
      LAYER met3 ;
        RECT 2859.020000 158.510000 2859.820000 158.810000 ;
    END
  END io_oeb[0]
  PIN irq[2]
    DIRECTION OUTPUT ;
    USE SIGNAL ;
    ANTENNADIFFAREA 0.336 LAYER met2  ;
    ANTENNAPARTIALMETALAREA 4.4911 LAYER met2  ;
    ANTENNAPARTIALMETALSIDEAREA 22.3475 LAYER met2  ;
    PORT
      LAYER met2 ;
        RECT 2859.520000 0.000000 2859.660000 0.485000 ;
    END
  END irq[2]
  PIN irq[1]
    DIRECTION OUTPUT ;
    USE SIGNAL ;
    ANTENNADIFFAREA 0.336 LAYER met2  ;
    ANTENNAPARTIALMETALAREA 5.2051 LAYER met2  ;
    ANTENNAPARTIALMETALSIDEAREA 25.9175 LAYER met2  ;
    PORT
      LAYER met2 ;
        RECT 2854.000000 0.000000 2854.140000 0.485000 ;
    END
  END irq[1]
  PIN irq[0]
    DIRECTION OUTPUT ;
    USE SIGNAL ;
    ANTENNADIFFAREA 0.336 LAYER met2  ;
    ANTENNAPARTIALMETALAREA 4.5863 LAYER met2  ;
    ANTENNAPARTIALMETALSIDEAREA 22.8235 LAYER met2  ;
    PORT
      LAYER met2 ;
        RECT 2848.020000 0.000000 2848.160000 0.485000 ;
    END
  END irq[0]
  PIN user_clock2
    DIRECTION INPUT ;
    USE SIGNAL ;
    ANTENNAPARTIALMETALAREA 0.2744 LAYER met2  ;
    ANTENNAPARTIALMETALSIDEAREA 1.211 LAYER met2  ;
    ANTENNAPARTIALCUTAREA 0.04 LAYER via2  ;
    ANTENNAPARTIALMETALAREA 5.2248 LAYER met3  ;
    ANTENNAPARTIALMETALSIDEAREA 28.336 LAYER met3  ;
    ANTENNAMODEL OXIDE1 ;
    ANTENNAGATEAREA 0.576 LAYER met3  ;
    ANTENNAMAXAREACAR 22.0595 LAYER met3  ;
    ANTENNAMAXSIDEAREACAR 111.943 LAYER met3  ;
    ANTENNAMAXCUTCAR 0.158681 LAYER via3  ;
    PORT
      LAYER met2 ;
        RECT 2842.500000 0.000000 2842.640000 0.485000 ;
    END
  END user_clock2
  PIN vssd1
    DIRECTION INOUT ;
    USE GROUND ;
    PORT
      LAYER met4 ;
        RECT 2837.500000 3466.940000 2840.600000 3470.040000 ;
    END
    PORT
      LAYER met4 ;
        RECT 2837.500000 0.000000 2840.600000 3.100000 ;
    END
    PORT
      LAYER met4 ;
        RECT 19.220000 3466.940000 22.320000 3470.040000 ;
    END
    PORT
      LAYER met4 ;
        RECT 19.220000 0.000000 22.320000 3.100000 ;
    END
    PORT
      LAYER met5 ;
        RECT 2856.720000 3445.640000 2859.820000 3448.740000 ;
    END
    PORT
      LAYER met5 ;
        RECT 0.000000 3445.640000 3.100000 3448.740000 ;
    END
    PORT
      LAYER met5 ;
        RECT 2856.720000 19.260000 2859.820000 22.360000 ;
    END
    PORT
      LAYER met5 ;
        RECT 0.000000 19.260000 3.100000 22.360000 ;
    END

# P/G power stripe data as pin
    PORT
      LAYER met4 ;
        RECT 1428.000000 19.260000 1431.360000 3448.740000 ;
        RECT 19.220000 0.000000 22.320000 3470.040000 ;
        RECT 68.000000 19.260000 71.360000 3448.740000 ;
        RECT 1292.000000 19.260000 1295.360000 3448.740000 ;
        RECT 154.175000 1407.015000 155.975000 1818.915000 ;
        RECT 646.555000 1407.015000 648.355000 1818.915000 ;
        RECT 674.035000 1407.015000 675.835000 1818.915000 ;
        RECT 1166.415000 1407.015000 1168.215000 1818.915000 ;
        RECT 2837.500000 0.000000 2840.600000 3470.040000 ;
        RECT 1564.000000 19.260000 1567.360000 3448.740000 ;
        RECT 2788.000000 19.260000 2791.360000 3448.740000 ;
        RECT 1688.815000 1673.620000 1690.615000 2085.520000 ;
        RECT 2181.195000 1673.620000 2182.995000 2085.520000 ;
        RECT 2208.675000 1673.620000 2210.475000 2085.520000 ;
        RECT 2701.055000 1673.620000 2702.855000 2085.520000 ;
        RECT 1166.415000 738.660000 1168.215000 1150.560000 ;
        RECT 674.035000 738.660000 675.835000 1150.560000 ;
        RECT 646.555000 738.660000 648.355000 1150.560000 ;
        RECT 154.175000 738.660000 155.975000 1150.560000 ;
        RECT 154.175000 254.510000 155.975000 666.410000 ;
        RECT 476.000000 19.260000 479.360000 256.310000 ;
        RECT 340.000000 19.260000 343.360000 256.310000 ;
        RECT 204.000000 19.260000 207.360000 256.310000 ;
        RECT 204.000000 664.610000 207.360000 740.460000 ;
        RECT 340.000000 664.610000 343.360000 740.460000 ;
        RECT 476.000000 664.610000 479.360000 740.460000 ;
        RECT 1166.415000 254.510000 1168.215000 666.410000 ;
        RECT 674.035000 254.510000 675.835000 666.410000 ;
        RECT 646.555000 254.510000 648.355000 666.410000 ;
        RECT 884.000000 19.260000 887.360000 256.310000 ;
        RECT 748.000000 19.260000 751.360000 256.310000 ;
        RECT 612.000000 19.260000 615.360000 256.310000 ;
        RECT 1156.000000 19.260000 1159.360000 256.310000 ;
        RECT 1020.000000 19.260000 1023.360000 256.310000 ;
        RECT 612.000000 664.610000 615.360000 740.460000 ;
        RECT 748.000000 664.610000 751.360000 740.460000 ;
        RECT 884.000000 664.610000 887.360000 740.460000 ;
        RECT 1020.000000 664.610000 1023.360000 740.460000 ;
        RECT 1156.000000 664.610000 1159.360000 740.460000 ;
        RECT 476.000000 1148.760000 479.360000 1408.815000 ;
        RECT 340.000000 1148.760000 343.360000 1408.815000 ;
        RECT 204.000000 1148.760000 207.360000 1408.815000 ;
        RECT 1156.000000 1148.760000 1159.360000 1408.815000 ;
        RECT 1020.000000 1148.760000 1023.360000 1408.815000 ;
        RECT 884.000000 1148.760000 887.360000 1408.815000 ;
        RECT 748.000000 1148.760000 751.360000 1408.815000 ;
        RECT 612.000000 1148.760000 615.360000 1408.815000 ;
        RECT 2701.055000 738.660000 2702.855000 1150.560000 ;
        RECT 2208.675000 738.660000 2210.475000 1150.560000 ;
        RECT 2181.195000 738.660000 2182.995000 1150.560000 ;
        RECT 1688.815000 738.660000 1690.615000 1150.560000 ;
        RECT 2208.675000 254.510000 2210.475000 666.410000 ;
        RECT 2181.195000 254.510000 2182.995000 666.410000 ;
        RECT 1688.815000 254.510000 1690.615000 666.410000 ;
        RECT 1836.000000 19.260000 1839.360000 256.310000 ;
        RECT 1700.000000 19.260000 1703.360000 256.310000 ;
        RECT 2244.000000 19.260000 2247.360000 256.310000 ;
        RECT 2108.000000 19.260000 2111.360000 256.310000 ;
        RECT 1972.000000 19.260000 1975.360000 256.310000 ;
        RECT 1700.000000 664.610000 1703.360000 740.460000 ;
        RECT 1836.000000 664.610000 1839.360000 740.460000 ;
        RECT 1972.000000 664.610000 1975.360000 740.460000 ;
        RECT 2108.000000 664.610000 2111.360000 740.460000 ;
        RECT 2244.000000 664.610000 2247.360000 740.460000 ;
        RECT 2701.055000 254.510000 2702.855000 666.410000 ;
        RECT 2380.000000 19.260000 2383.360000 256.310000 ;
        RECT 2516.000000 19.260000 2519.360000 256.310000 ;
        RECT 2652.000000 19.260000 2655.360000 256.310000 ;
        RECT 2380.000000 664.610000 2383.360000 740.460000 ;
        RECT 2516.000000 664.610000 2519.360000 740.460000 ;
        RECT 2652.000000 664.610000 2655.360000 740.460000 ;
        RECT 2208.675000 1210.055000 2210.475000 1621.955000 ;
        RECT 2181.195000 1210.055000 2182.995000 1621.955000 ;
        RECT 1688.815000 1210.055000 1690.615000 1621.955000 ;
        RECT 1836.000000 1148.760000 1839.360000 1211.855000 ;
        RECT 1700.000000 1148.760000 1703.360000 1211.855000 ;
        RECT 1972.000000 1148.760000 1975.360000 1211.855000 ;
        RECT 2244.000000 1148.760000 2247.360000 1211.855000 ;
        RECT 2108.000000 1148.760000 2111.360000 1211.855000 ;
        RECT 1836.000000 1620.155000 1839.360000 1675.420000 ;
        RECT 1700.000000 1620.155000 1703.360000 1675.420000 ;
        RECT 1972.000000 1620.155000 1975.360000 1675.420000 ;
        RECT 2244.000000 1620.155000 2247.360000 1675.420000 ;
        RECT 2108.000000 1620.155000 2111.360000 1675.420000 ;
        RECT 2701.055000 1210.055000 2702.855000 1621.955000 ;
        RECT 2380.000000 1148.760000 2383.360000 1211.855000 ;
        RECT 2652.000000 1148.760000 2655.360000 1211.855000 ;
        RECT 2516.000000 1148.760000 2519.360000 1211.855000 ;
        RECT 2380.000000 1620.155000 2383.360000 1675.420000 ;
        RECT 2652.000000 1620.155000 2655.360000 1675.420000 ;
        RECT 2516.000000 1620.155000 2519.360000 1675.420000 ;
        RECT 204.000000 2565.660000 207.360000 2645.275000 ;
        RECT 340.000000 2565.660000 343.360000 2645.275000 ;
        RECT 476.000000 2565.660000 479.360000 2645.275000 ;
        RECT 612.000000 2565.660000 615.360000 2645.275000 ;
        RECT 748.000000 2565.660000 751.360000 2645.275000 ;
        RECT 884.000000 2565.660000 887.360000 2645.275000 ;
        RECT 1020.000000 2565.660000 1023.360000 2645.275000 ;
        RECT 1156.000000 2565.660000 1159.360000 2645.275000 ;
        RECT 154.175000 2155.560000 155.975000 2567.460000 ;
        RECT 204.000000 1817.115000 207.360000 2157.360000 ;
        RECT 340.000000 1817.115000 343.360000 2157.360000 ;
        RECT 476.000000 1817.115000 479.360000 2157.360000 ;
        RECT 1166.415000 2155.560000 1168.215000 2567.460000 ;
        RECT 674.035000 2155.560000 675.835000 2567.460000 ;
        RECT 646.555000 2155.560000 648.355000 2567.460000 ;
        RECT 884.000000 1817.115000 887.360000 2157.360000 ;
        RECT 612.000000 1817.115000 615.360000 2157.360000 ;
        RECT 748.000000 1817.115000 751.360000 2157.360000 ;
        RECT 1156.000000 1817.115000 1159.360000 2157.360000 ;
        RECT 1020.000000 1817.115000 1023.360000 2157.360000 ;
        RECT 154.175000 2643.475000 155.975000 3055.375000 ;
        RECT 476.000000 3053.575000 479.360000 3448.740000 ;
        RECT 340.000000 3053.575000 343.360000 3448.740000 ;
        RECT 204.000000 3053.575000 207.360000 3448.740000 ;
        RECT 1166.415000 2643.475000 1168.215000 3055.375000 ;
        RECT 674.035000 2643.475000 675.835000 3055.375000 ;
        RECT 646.555000 2643.475000 648.355000 3055.375000 ;
        RECT 884.000000 3053.575000 887.360000 3448.740000 ;
        RECT 748.000000 3053.575000 751.360000 3448.740000 ;
        RECT 612.000000 3053.575000 615.360000 3448.740000 ;
        RECT 1156.000000 3053.575000 1159.360000 3448.740000 ;
        RECT 1020.000000 3053.575000 1023.360000 3448.740000 ;
        RECT 1700.000000 2565.660000 1703.360000 2645.275000 ;
        RECT 1836.000000 2565.660000 1839.360000 2645.275000 ;
        RECT 1972.000000 2565.660000 1975.360000 2645.275000 ;
        RECT 2108.000000 2565.660000 2111.360000 2645.275000 ;
        RECT 2244.000000 2565.660000 2247.360000 2645.275000 ;
        RECT 2380.000000 2565.660000 2383.360000 2645.275000 ;
        RECT 2516.000000 2565.660000 2519.360000 2645.275000 ;
        RECT 2652.000000 2565.660000 2655.360000 2645.275000 ;
        RECT 2208.675000 2155.560000 2210.475000 2567.460000 ;
        RECT 2181.195000 2155.560000 2182.995000 2567.460000 ;
        RECT 1688.815000 2155.560000 1690.615000 2567.460000 ;
        RECT 1700.000000 2083.720000 1703.360000 2157.360000 ;
        RECT 1836.000000 2083.720000 1839.360000 2157.360000 ;
        RECT 1972.000000 2083.720000 1975.360000 2157.360000 ;
        RECT 2108.000000 2083.720000 2111.360000 2157.360000 ;
        RECT 2244.000000 2083.720000 2247.360000 2157.360000 ;
        RECT 2701.055000 2155.560000 2702.855000 2567.460000 ;
        RECT 2380.000000 2083.720000 2383.360000 2157.360000 ;
        RECT 2516.000000 2083.720000 2519.360000 2157.360000 ;
        RECT 2652.000000 2083.720000 2655.360000 2157.360000 ;
        RECT 2208.675000 2643.475000 2210.475000 3055.375000 ;
        RECT 2181.195000 2643.475000 2182.995000 3055.375000 ;
        RECT 1688.815000 2643.475000 1690.615000 3055.375000 ;
        RECT 1836.000000 3053.575000 1839.360000 3448.740000 ;
        RECT 1700.000000 3053.575000 1703.360000 3448.740000 ;
        RECT 2244.000000 3053.575000 2247.360000 3448.740000 ;
        RECT 2108.000000 3053.575000 2111.360000 3448.740000 ;
        RECT 1972.000000 3053.575000 1975.360000 3448.740000 ;
        RECT 2701.055000 2643.475000 2702.855000 3055.375000 ;
        RECT 2652.000000 3053.575000 2655.360000 3448.740000 ;
        RECT 2516.000000 3053.575000 2519.360000 3448.740000 ;
        RECT 2380.000000 3053.575000 2383.360000 3448.740000 ;
      LAYER met5 ;
        RECT 0.000000 19.260000 2859.820000 22.360000 ;
        RECT 0.000000 3445.640000 2859.820000 3448.740000 ;
    END
# end of P/G power stripe data as pin

  END vssd1
  PIN vccd1
    DIRECTION INOUT ;
    USE POWER ;
    PORT
      LAYER met4 ;
        RECT 2831.300000 3466.940000 2834.400000 3470.040000 ;
    END
    PORT
      LAYER met4 ;
        RECT 2831.300000 0.000000 2834.400000 3.100000 ;
    END
    PORT
      LAYER met4 ;
        RECT 25.420000 3466.940000 28.520000 3470.040000 ;
    END
    PORT
      LAYER met4 ;
        RECT 25.420000 0.000000 28.520000 3.100000 ;
    END
    PORT
      LAYER met5 ;
        RECT 2856.720000 3439.440000 2859.820000 3442.540000 ;
    END
    PORT
      LAYER met5 ;
        RECT 0.000000 3439.440000 3.100000 3442.540000 ;
    END
    PORT
      LAYER met5 ;
        RECT 2856.720000 25.460000 2859.820000 28.560000 ;
    END
    PORT
      LAYER met5 ;
        RECT 0.000000 25.460000 3.100000 28.560000 ;
    END

# P/G power stripe data as pin
    PORT
      LAYER met4 ;
        RECT 25.420000 0.000000 28.520000 3470.040000 ;
        RECT 136.000000 25.460000 139.360000 3442.540000 ;
        RECT 1224.000000 25.460000 1227.360000 3442.540000 ;
        RECT 1360.000000 25.460000 1363.360000 3442.540000 ;
        RECT 157.775000 1410.615000 159.575000 1815.315000 ;
        RECT 642.955000 1410.615000 644.755000 1815.315000 ;
        RECT 677.635000 1410.615000 679.435000 1815.315000 ;
        RECT 1162.815000 1410.615000 1164.615000 1815.315000 ;
        RECT 2697.455000 1677.220000 2699.255000 2081.920000 ;
        RECT 2831.300000 0.000000 2834.400000 3470.040000 ;
        RECT 1496.000000 25.460000 1499.360000 3442.540000 ;
        RECT 1632.000000 25.460000 1635.360000 3442.540000 ;
        RECT 2720.000000 25.460000 2723.360000 3442.540000 ;
        RECT 1692.415000 1677.220000 1694.215000 2081.920000 ;
        RECT 2177.595000 1677.220000 2179.395000 2081.920000 ;
        RECT 2212.275000 1677.220000 2214.075000 2081.920000 ;
        RECT 1162.815000 742.260000 1164.615000 1146.960000 ;
        RECT 677.635000 742.260000 679.435000 1146.960000 ;
        RECT 642.955000 742.260000 644.755000 1146.960000 ;
        RECT 157.775000 742.260000 159.575000 1146.960000 ;
        RECT 157.775000 258.110000 159.575000 662.810000 ;
        RECT 544.000000 25.460000 547.360000 259.910000 ;
        RECT 408.000000 25.460000 411.360000 259.910000 ;
        RECT 272.000000 25.460000 275.360000 259.910000 ;
        RECT 272.000000 661.010000 275.360000 744.060000 ;
        RECT 408.000000 661.010000 411.360000 744.060000 ;
        RECT 544.000000 661.010000 547.360000 744.060000 ;
        RECT 1162.815000 258.110000 1164.615000 662.810000 ;
        RECT 677.635000 258.110000 679.435000 662.810000 ;
        RECT 642.955000 258.110000 644.755000 662.810000 ;
        RECT 952.000000 25.460000 955.360000 259.910000 ;
        RECT 816.000000 25.460000 819.360000 259.910000 ;
        RECT 680.000000 25.460000 683.360000 259.910000 ;
        RECT 1088.000000 25.460000 1091.360000 259.910000 ;
        RECT 680.000000 661.010000 683.360000 744.060000 ;
        RECT 816.000000 661.010000 819.360000 744.060000 ;
        RECT 952.000000 661.010000 955.360000 744.060000 ;
        RECT 1088.000000 661.010000 1091.360000 744.060000 ;
        RECT 544.000000 1145.160000 547.360000 1412.415000 ;
        RECT 408.000000 1145.160000 411.360000 1412.415000 ;
        RECT 272.000000 1145.160000 275.360000 1412.415000 ;
        RECT 1088.000000 1145.160000 1091.360000 1412.415000 ;
        RECT 952.000000 1145.160000 955.360000 1412.415000 ;
        RECT 816.000000 1145.160000 819.360000 1412.415000 ;
        RECT 680.000000 1145.160000 683.360000 1412.415000 ;
        RECT 2697.455000 742.260000 2699.255000 1146.960000 ;
        RECT 2212.275000 742.260000 2214.075000 1146.960000 ;
        RECT 2177.595000 742.260000 2179.395000 1146.960000 ;
        RECT 1692.415000 742.260000 1694.215000 1146.960000 ;
        RECT 2212.275000 258.110000 2214.075000 662.810000 ;
        RECT 2177.595000 258.110000 2179.395000 662.810000 ;
        RECT 1692.415000 258.110000 1694.215000 662.810000 ;
        RECT 1768.000000 25.460000 1771.360000 259.910000 ;
        RECT 2176.000000 25.460000 2179.360000 259.910000 ;
        RECT 2040.000000 25.460000 2043.360000 259.910000 ;
        RECT 1904.000000 25.460000 1907.360000 259.910000 ;
        RECT 1768.000000 661.010000 1771.360000 744.060000 ;
        RECT 1904.000000 661.010000 1907.360000 744.060000 ;
        RECT 2040.000000 661.010000 2043.360000 744.060000 ;
        RECT 2176.000000 661.010000 2179.360000 744.060000 ;
        RECT 2697.455000 258.110000 2699.255000 662.810000 ;
        RECT 2584.000000 25.460000 2587.360000 259.910000 ;
        RECT 2448.000000 25.460000 2451.360000 259.910000 ;
        RECT 2312.000000 25.460000 2315.360000 259.910000 ;
        RECT 2312.000000 661.010000 2315.360000 744.060000 ;
        RECT 2448.000000 661.010000 2451.360000 744.060000 ;
        RECT 2584.000000 661.010000 2587.360000 744.060000 ;
        RECT 2212.275000 1213.655000 2214.075000 1618.355000 ;
        RECT 2177.595000 1213.655000 2179.395000 1618.355000 ;
        RECT 1692.415000 1213.655000 1694.215000 1618.355000 ;
        RECT 1768.000000 1145.160000 1771.360000 1215.455000 ;
        RECT 2040.000000 1145.160000 2043.360000 1215.455000 ;
        RECT 1904.000000 1145.160000 1907.360000 1215.455000 ;
        RECT 2176.000000 1145.160000 2179.360000 1215.455000 ;
        RECT 1768.000000 1616.555000 1771.360000 1679.020000 ;
        RECT 2040.000000 1616.555000 2043.360000 1679.020000 ;
        RECT 1904.000000 1616.555000 1907.360000 1679.020000 ;
        RECT 2176.000000 1616.555000 2179.360000 1679.020000 ;
        RECT 2697.455000 1213.655000 2699.255000 1618.355000 ;
        RECT 2448.000000 1145.160000 2451.360000 1215.455000 ;
        RECT 2312.000000 1145.160000 2315.360000 1215.455000 ;
        RECT 2584.000000 1145.160000 2587.360000 1215.455000 ;
        RECT 2448.000000 1616.555000 2451.360000 1679.020000 ;
        RECT 2312.000000 1616.555000 2315.360000 1679.020000 ;
        RECT 2584.000000 1616.555000 2587.360000 1679.020000 ;
        RECT 1088.000000 2562.060000 1091.360000 2648.875000 ;
        RECT 952.000000 2562.060000 955.360000 2648.875000 ;
        RECT 816.000000 2562.060000 819.360000 2648.875000 ;
        RECT 680.000000 2562.060000 683.360000 2648.875000 ;
        RECT 544.000000 2562.060000 547.360000 2648.875000 ;
        RECT 408.000000 2562.060000 411.360000 2648.875000 ;
        RECT 272.000000 2562.060000 275.360000 2648.875000 ;
        RECT 157.775000 2159.160000 159.575000 2563.860000 ;
        RECT 544.000000 1813.515000 547.360000 2160.960000 ;
        RECT 408.000000 1813.515000 411.360000 2160.960000 ;
        RECT 272.000000 1813.515000 275.360000 2160.960000 ;
        RECT 1162.815000 2159.160000 1164.615000 2563.860000 ;
        RECT 677.635000 2159.160000 679.435000 2563.860000 ;
        RECT 642.955000 2159.160000 644.755000 2563.860000 ;
        RECT 952.000000 1813.515000 955.360000 2160.960000 ;
        RECT 816.000000 1813.515000 819.360000 2160.960000 ;
        RECT 680.000000 1813.515000 683.360000 2160.960000 ;
        RECT 1088.000000 1813.515000 1091.360000 2160.960000 ;
        RECT 157.775000 2647.075000 159.575000 3051.775000 ;
        RECT 544.000000 3049.975000 547.360000 3442.540000 ;
        RECT 408.000000 3049.975000 411.360000 3442.540000 ;
        RECT 272.000000 3049.975000 275.360000 3442.540000 ;
        RECT 1162.815000 2647.075000 1164.615000 3051.775000 ;
        RECT 677.635000 2647.075000 679.435000 3051.775000 ;
        RECT 642.955000 2647.075000 644.755000 3051.775000 ;
        RECT 952.000000 3049.975000 955.360000 3442.540000 ;
        RECT 816.000000 3049.975000 819.360000 3442.540000 ;
        RECT 680.000000 3049.975000 683.360000 3442.540000 ;
        RECT 1088.000000 3049.975000 1091.360000 3442.540000 ;
        RECT 2584.000000 2562.060000 2587.360000 2648.875000 ;
        RECT 2448.000000 2562.060000 2451.360000 2648.875000 ;
        RECT 2312.000000 2562.060000 2315.360000 2648.875000 ;
        RECT 2176.000000 2562.060000 2179.360000 2648.875000 ;
        RECT 2040.000000 2562.060000 2043.360000 2648.875000 ;
        RECT 1904.000000 2562.060000 1907.360000 2648.875000 ;
        RECT 1768.000000 2562.060000 1771.360000 2648.875000 ;
        RECT 2212.275000 2159.160000 2214.075000 2563.860000 ;
        RECT 2177.595000 2159.160000 2179.395000 2563.860000 ;
        RECT 1692.415000 2159.160000 1694.215000 2563.860000 ;
        RECT 1768.000000 2080.120000 1771.360000 2160.960000 ;
        RECT 1904.000000 2080.120000 1907.360000 2160.960000 ;
        RECT 2040.000000 2080.120000 2043.360000 2160.960000 ;
        RECT 2176.000000 2080.120000 2179.360000 2160.960000 ;
        RECT 2697.455000 2159.160000 2699.255000 2563.860000 ;
        RECT 2312.000000 2080.120000 2315.360000 2160.960000 ;
        RECT 2448.000000 2080.120000 2451.360000 2160.960000 ;
        RECT 2584.000000 2080.120000 2587.360000 2160.960000 ;
        RECT 2212.275000 2647.075000 2214.075000 3051.775000 ;
        RECT 2177.595000 2647.075000 2179.395000 3051.775000 ;
        RECT 1692.415000 2647.075000 1694.215000 3051.775000 ;
        RECT 1768.000000 3049.975000 1771.360000 3442.540000 ;
        RECT 2176.000000 3049.975000 2179.360000 3442.540000 ;
        RECT 2040.000000 3049.975000 2043.360000 3442.540000 ;
        RECT 1904.000000 3049.975000 1907.360000 3442.540000 ;
        RECT 2697.455000 2647.075000 2699.255000 3051.775000 ;
        RECT 2584.000000 3049.975000 2587.360000 3442.540000 ;
        RECT 2448.000000 3049.975000 2451.360000 3442.540000 ;
        RECT 2312.000000 3049.975000 2315.360000 3442.540000 ;
        RECT 2176.000000 258.110000 2179.395000 259.910000 ;
        RECT 2176.000000 661.010000 2179.395000 662.810000 ;
        RECT 2176.000000 742.260000 2179.395000 744.060000 ;
        RECT 2176.000000 1145.160000 2179.395000 1146.960000 ;
        RECT 2176.000000 1213.655000 2179.395000 1215.455000 ;
        RECT 2176.000000 1616.555000 2179.395000 1618.355000 ;
        RECT 2176.000000 1677.220000 2179.395000 1679.020000 ;
        RECT 2176.000000 2080.120000 2179.395000 2081.920000 ;
        RECT 2176.000000 2159.160000 2179.395000 2160.960000 ;
        RECT 2176.000000 2562.060000 2179.395000 2563.860000 ;
        RECT 2176.000000 2647.075000 2179.395000 2648.875000 ;
        RECT 2176.000000 3049.975000 2179.395000 3051.775000 ;
      LAYER met5 ;
        RECT 0.000000 25.460000 2859.820000 28.560000 ;
        RECT 0.000000 3439.440000 2859.820000 3442.540000 ;
    END
# end of P/G power stripe data as pin

  END vccd1
  OBS
    LAYER li1 ;
      RECT 0.000000 0.000000 2859.820000 3470.040000 ;
    LAYER met1 ;
      RECT 0.000000 0.000000 2859.820000 3470.040000 ;
    LAYER met2 ;
      RECT 2859.480000 3469.275000 2859.820000 3470.040000 ;
      RECT 2749.540000 3469.275000 2858.780000 3470.040000 ;
      RECT 2639.600000 3469.275000 2748.840000 3470.040000 ;
      RECT 2529.660000 3469.275000 2638.900000 3470.040000 ;
      RECT 2419.720000 3469.275000 2528.960000 3470.040000 ;
      RECT 2309.780000 3469.275000 2419.020000 3470.040000 ;
      RECT 2199.840000 3469.275000 2309.080000 3470.040000 ;
      RECT 2089.900000 3469.275000 2199.140000 3470.040000 ;
      RECT 1979.960000 3469.275000 2089.200000 3470.040000 ;
      RECT 1870.020000 3469.275000 1979.260000 3470.040000 ;
      RECT 1760.080000 3469.275000 1869.320000 3470.040000 ;
      RECT 1650.140000 3469.275000 1759.380000 3470.040000 ;
      RECT 1540.200000 3469.275000 1649.440000 3470.040000 ;
      RECT 1429.800000 3469.275000 1539.500000 3470.040000 ;
      RECT 1319.860000 3469.275000 1429.100000 3470.040000 ;
      RECT 1209.920000 3469.275000 1319.160000 3470.040000 ;
      RECT 1099.980000 3469.275000 1209.220000 3470.040000 ;
      RECT 990.040000 3469.275000 1099.280000 3470.040000 ;
      RECT 880.100000 3469.275000 989.340000 3470.040000 ;
      RECT 770.160000 3469.275000 879.400000 3470.040000 ;
      RECT 660.220000 3469.275000 769.460000 3470.040000 ;
      RECT 550.280000 3469.275000 659.520000 3470.040000 ;
      RECT 440.340000 3469.275000 549.580000 3470.040000 ;
      RECT 330.400000 3469.275000 439.640000 3470.040000 ;
      RECT 220.460000 3469.275000 329.700000 3470.040000 ;
      RECT 110.520000 3469.275000 219.760000 3470.040000 ;
      RECT 0.580000 3469.275000 109.820000 3470.040000 ;
      RECT 0.000000 0.765000 2859.820000 3469.275000 ;
      RECT 2854.420000 0.000000 2859.240000 0.765000 ;
      RECT 2848.440000 0.000000 2853.720000 0.765000 ;
      RECT 2842.920000 0.000000 2847.740000 0.765000 ;
      RECT 2836.940000 0.000000 2842.220000 0.765000 ;
      RECT 2830.960000 0.000000 2836.240000 0.765000 ;
      RECT 2825.440000 0.000000 2830.260000 0.765000 ;
      RECT 2819.460000 0.000000 2824.740000 0.765000 ;
      RECT 2813.940000 0.000000 2818.760000 0.765000 ;
      RECT 2807.960000 0.000000 2813.240000 0.765000 ;
      RECT 2801.980000 0.000000 2807.260000 0.765000 ;
      RECT 2796.460000 0.000000 2801.280000 0.765000 ;
      RECT 2790.480000 0.000000 2795.760000 0.765000 ;
      RECT 2784.960000 0.000000 2789.780000 0.765000 ;
      RECT 2778.980000 0.000000 2784.260000 0.765000 ;
      RECT 2773.000000 0.000000 2778.280000 0.765000 ;
      RECT 2767.480000 0.000000 2772.300000 0.765000 ;
      RECT 2761.500000 0.000000 2766.780000 0.765000 ;
      RECT 2755.980000 0.000000 2760.800000 0.765000 ;
      RECT 2750.000000 0.000000 2755.280000 0.765000 ;
      RECT 2744.020000 0.000000 2749.300000 0.765000 ;
      RECT 2738.500000 0.000000 2743.320000 0.765000 ;
      RECT 2732.520000 0.000000 2737.800000 0.765000 ;
      RECT 2727.000000 0.000000 2731.820000 0.765000 ;
      RECT 2721.020000 0.000000 2726.300000 0.765000 ;
      RECT 2715.040000 0.000000 2720.320000 0.765000 ;
      RECT 2709.520000 0.000000 2714.340000 0.765000 ;
      RECT 2703.540000 0.000000 2708.820000 0.765000 ;
      RECT 2697.560000 0.000000 2702.840000 0.765000 ;
      RECT 2692.040000 0.000000 2696.860000 0.765000 ;
      RECT 2686.060000 0.000000 2691.340000 0.765000 ;
      RECT 2680.540000 0.000000 2685.360000 0.765000 ;
      RECT 2674.560000 0.000000 2679.840000 0.765000 ;
      RECT 2668.580000 0.000000 2673.860000 0.765000 ;
      RECT 2663.060000 0.000000 2667.880000 0.765000 ;
      RECT 2657.080000 0.000000 2662.360000 0.765000 ;
      RECT 2651.560000 0.000000 2656.380000 0.765000 ;
      RECT 2645.580000 0.000000 2650.860000 0.765000 ;
      RECT 2639.600000 0.000000 2644.880000 0.765000 ;
      RECT 2634.080000 0.000000 2638.900000 0.765000 ;
      RECT 2628.100000 0.000000 2633.380000 0.765000 ;
      RECT 2622.580000 0.000000 2627.400000 0.765000 ;
      RECT 2616.600000 0.000000 2621.880000 0.765000 ;
      RECT 2610.620000 0.000000 2615.900000 0.765000 ;
      RECT 2605.100000 0.000000 2609.920000 0.765000 ;
      RECT 2599.120000 0.000000 2604.400000 0.765000 ;
      RECT 2593.600000 0.000000 2598.420000 0.765000 ;
      RECT 2587.620000 0.000000 2592.900000 0.765000 ;
      RECT 2581.640000 0.000000 2586.920000 0.765000 ;
      RECT 2576.120000 0.000000 2580.940000 0.765000 ;
      RECT 2570.140000 0.000000 2575.420000 0.765000 ;
      RECT 2564.160000 0.000000 2569.440000 0.765000 ;
      RECT 2558.640000 0.000000 2563.460000 0.765000 ;
      RECT 2552.660000 0.000000 2557.940000 0.765000 ;
      RECT 2547.140000 0.000000 2551.960000 0.765000 ;
      RECT 2541.160000 0.000000 2546.440000 0.765000 ;
      RECT 2535.180000 0.000000 2540.460000 0.765000 ;
      RECT 2529.660000 0.000000 2534.480000 0.765000 ;
      RECT 2523.680000 0.000000 2528.960000 0.765000 ;
      RECT 2518.160000 0.000000 2522.980000 0.765000 ;
      RECT 2512.180000 0.000000 2517.460000 0.765000 ;
      RECT 2506.200000 0.000000 2511.480000 0.765000 ;
      RECT 2500.680000 0.000000 2505.500000 0.765000 ;
      RECT 2494.700000 0.000000 2499.980000 0.765000 ;
      RECT 2489.180000 0.000000 2494.000000 0.765000 ;
      RECT 2483.200000 0.000000 2488.480000 0.765000 ;
      RECT 2477.220000 0.000000 2482.500000 0.765000 ;
      RECT 2471.700000 0.000000 2476.520000 0.765000 ;
      RECT 2465.720000 0.000000 2471.000000 0.765000 ;
      RECT 2460.200000 0.000000 2465.020000 0.765000 ;
      RECT 2454.220000 0.000000 2459.500000 0.765000 ;
      RECT 2448.240000 0.000000 2453.520000 0.765000 ;
      RECT 2442.720000 0.000000 2447.540000 0.765000 ;
      RECT 2436.740000 0.000000 2442.020000 0.765000 ;
      RECT 2430.760000 0.000000 2436.040000 0.765000 ;
      RECT 2425.240000 0.000000 2430.060000 0.765000 ;
      RECT 2419.260000 0.000000 2424.540000 0.765000 ;
      RECT 2413.740000 0.000000 2418.560000 0.765000 ;
      RECT 2407.760000 0.000000 2413.040000 0.765000 ;
      RECT 2401.780000 0.000000 2407.060000 0.765000 ;
      RECT 2396.260000 0.000000 2401.080000 0.765000 ;
      RECT 2390.280000 0.000000 2395.560000 0.765000 ;
      RECT 2384.760000 0.000000 2389.580000 0.765000 ;
      RECT 2378.780000 0.000000 2384.060000 0.765000 ;
      RECT 2372.800000 0.000000 2378.080000 0.765000 ;
      RECT 2367.280000 0.000000 2372.100000 0.765000 ;
      RECT 2361.300000 0.000000 2366.580000 0.765000 ;
      RECT 2355.780000 0.000000 2360.600000 0.765000 ;
      RECT 2349.800000 0.000000 2355.080000 0.765000 ;
      RECT 2343.820000 0.000000 2349.100000 0.765000 ;
      RECT 2338.300000 0.000000 2343.120000 0.765000 ;
      RECT 2332.320000 0.000000 2337.600000 0.765000 ;
      RECT 2326.800000 0.000000 2331.620000 0.765000 ;
      RECT 2320.820000 0.000000 2326.100000 0.765000 ;
      RECT 2314.840000 0.000000 2320.120000 0.765000 ;
      RECT 2309.320000 0.000000 2314.140000 0.765000 ;
      RECT 2303.340000 0.000000 2308.620000 0.765000 ;
      RECT 2297.360000 0.000000 2302.640000 0.765000 ;
      RECT 2291.840000 0.000000 2296.660000 0.765000 ;
      RECT 2285.860000 0.000000 2291.140000 0.765000 ;
      RECT 2280.340000 0.000000 2285.160000 0.765000 ;
      RECT 2274.360000 0.000000 2279.640000 0.765000 ;
      RECT 2268.380000 0.000000 2273.660000 0.765000 ;
      RECT 2262.860000 0.000000 2267.680000 0.765000 ;
      RECT 2256.880000 0.000000 2262.160000 0.765000 ;
      RECT 2251.360000 0.000000 2256.180000 0.765000 ;
      RECT 2245.380000 0.000000 2250.660000 0.765000 ;
      RECT 2239.400000 0.000000 2244.680000 0.765000 ;
      RECT 2233.880000 0.000000 2238.700000 0.765000 ;
      RECT 2227.900000 0.000000 2233.180000 0.765000 ;
      RECT 2222.380000 0.000000 2227.200000 0.765000 ;
      RECT 2216.400000 0.000000 2221.680000 0.765000 ;
      RECT 2210.420000 0.000000 2215.700000 0.765000 ;
      RECT 2204.900000 0.000000 2209.720000 0.765000 ;
      RECT 2198.920000 0.000000 2204.200000 0.765000 ;
      RECT 2193.400000 0.000000 2198.220000 0.765000 ;
      RECT 2187.420000 0.000000 2192.700000 0.765000 ;
      RECT 2181.440000 0.000000 2186.720000 0.765000 ;
      RECT 2175.920000 0.000000 2180.740000 0.765000 ;
      RECT 2169.940000 0.000000 2175.220000 0.765000 ;
      RECT 2163.960000 0.000000 2169.240000 0.765000 ;
      RECT 2158.440000 0.000000 2163.260000 0.765000 ;
      RECT 2152.460000 0.000000 2157.740000 0.765000 ;
      RECT 2146.940000 0.000000 2151.760000 0.765000 ;
      RECT 2140.960000 0.000000 2146.240000 0.765000 ;
      RECT 2134.980000 0.000000 2140.260000 0.765000 ;
      RECT 2129.460000 0.000000 2134.280000 0.765000 ;
      RECT 2123.480000 0.000000 2128.760000 0.765000 ;
      RECT 2117.960000 0.000000 2122.780000 0.765000 ;
      RECT 2111.980000 0.000000 2117.260000 0.765000 ;
      RECT 2106.000000 0.000000 2111.280000 0.765000 ;
      RECT 2100.480000 0.000000 2105.300000 0.765000 ;
      RECT 2094.500000 0.000000 2099.780000 0.765000 ;
      RECT 2088.980000 0.000000 2093.800000 0.765000 ;
      RECT 2083.000000 0.000000 2088.280000 0.765000 ;
      RECT 2077.020000 0.000000 2082.300000 0.765000 ;
      RECT 2071.500000 0.000000 2076.320000 0.765000 ;
      RECT 2065.520000 0.000000 2070.800000 0.765000 ;
      RECT 2060.000000 0.000000 2064.820000 0.765000 ;
      RECT 2054.020000 0.000000 2059.300000 0.765000 ;
      RECT 2048.040000 0.000000 2053.320000 0.765000 ;
      RECT 2042.520000 0.000000 2047.340000 0.765000 ;
      RECT 2036.540000 0.000000 2041.820000 0.765000 ;
      RECT 2030.560000 0.000000 2035.840000 0.765000 ;
      RECT 2025.040000 0.000000 2029.860000 0.765000 ;
      RECT 2019.060000 0.000000 2024.340000 0.765000 ;
      RECT 2013.540000 0.000000 2018.360000 0.765000 ;
      RECT 2007.560000 0.000000 2012.840000 0.765000 ;
      RECT 2001.580000 0.000000 2006.860000 0.765000 ;
      RECT 1996.060000 0.000000 2000.880000 0.765000 ;
      RECT 1990.080000 0.000000 1995.360000 0.765000 ;
      RECT 1984.560000 0.000000 1989.380000 0.765000 ;
      RECT 1978.580000 0.000000 1983.860000 0.765000 ;
      RECT 1972.600000 0.000000 1977.880000 0.765000 ;
      RECT 1967.080000 0.000000 1971.900000 0.765000 ;
      RECT 1961.100000 0.000000 1966.380000 0.765000 ;
      RECT 1955.580000 0.000000 1960.400000 0.765000 ;
      RECT 1949.600000 0.000000 1954.880000 0.765000 ;
      RECT 1943.620000 0.000000 1948.900000 0.765000 ;
      RECT 1938.100000 0.000000 1942.920000 0.765000 ;
      RECT 1932.120000 0.000000 1937.400000 0.765000 ;
      RECT 1926.600000 0.000000 1931.420000 0.765000 ;
      RECT 1920.620000 0.000000 1925.900000 0.765000 ;
      RECT 1914.640000 0.000000 1919.920000 0.765000 ;
      RECT 1909.120000 0.000000 1913.940000 0.765000 ;
      RECT 1903.140000 0.000000 1908.420000 0.765000 ;
      RECT 1897.160000 0.000000 1902.440000 0.765000 ;
      RECT 1891.640000 0.000000 1896.460000 0.765000 ;
      RECT 1885.660000 0.000000 1890.940000 0.765000 ;
      RECT 1880.140000 0.000000 1884.960000 0.765000 ;
      RECT 1874.160000 0.000000 1879.440000 0.765000 ;
      RECT 1868.180000 0.000000 1873.460000 0.765000 ;
      RECT 1862.660000 0.000000 1867.480000 0.765000 ;
      RECT 1856.680000 0.000000 1861.960000 0.765000 ;
      RECT 1851.160000 0.000000 1855.980000 0.765000 ;
      RECT 1845.180000 0.000000 1850.460000 0.765000 ;
      RECT 1839.200000 0.000000 1844.480000 0.765000 ;
      RECT 1833.680000 0.000000 1838.500000 0.765000 ;
      RECT 1827.700000 0.000000 1832.980000 0.765000 ;
      RECT 1822.180000 0.000000 1827.000000 0.765000 ;
      RECT 1816.200000 0.000000 1821.480000 0.765000 ;
      RECT 1810.220000 0.000000 1815.500000 0.765000 ;
      RECT 1804.700000 0.000000 1809.520000 0.765000 ;
      RECT 1798.720000 0.000000 1804.000000 0.765000 ;
      RECT 1793.200000 0.000000 1798.020000 0.765000 ;
      RECT 1787.220000 0.000000 1792.500000 0.765000 ;
      RECT 1781.240000 0.000000 1786.520000 0.765000 ;
      RECT 1775.720000 0.000000 1780.540000 0.765000 ;
      RECT 1769.740000 0.000000 1775.020000 0.765000 ;
      RECT 1763.760000 0.000000 1769.040000 0.765000 ;
      RECT 1758.240000 0.000000 1763.060000 0.765000 ;
      RECT 1752.260000 0.000000 1757.540000 0.765000 ;
      RECT 1746.740000 0.000000 1751.560000 0.765000 ;
      RECT 1740.760000 0.000000 1746.040000 0.765000 ;
      RECT 1734.780000 0.000000 1740.060000 0.765000 ;
      RECT 1729.260000 0.000000 1734.080000 0.765000 ;
      RECT 1723.280000 0.000000 1728.560000 0.765000 ;
      RECT 1717.760000 0.000000 1722.580000 0.765000 ;
      RECT 1711.780000 0.000000 1717.060000 0.765000 ;
      RECT 1705.800000 0.000000 1711.080000 0.765000 ;
      RECT 1700.280000 0.000000 1705.100000 0.765000 ;
      RECT 1694.300000 0.000000 1699.580000 0.765000 ;
      RECT 1688.780000 0.000000 1693.600000 0.765000 ;
      RECT 1682.800000 0.000000 1688.080000 0.765000 ;
      RECT 1676.820000 0.000000 1682.100000 0.765000 ;
      RECT 1671.300000 0.000000 1676.120000 0.765000 ;
      RECT 1665.320000 0.000000 1670.600000 0.765000 ;
      RECT 1659.800000 0.000000 1664.620000 0.765000 ;
      RECT 1653.820000 0.000000 1659.100000 0.765000 ;
      RECT 1647.840000 0.000000 1653.120000 0.765000 ;
      RECT 1642.320000 0.000000 1647.140000 0.765000 ;
      RECT 1636.340000 0.000000 1641.620000 0.765000 ;
      RECT 1630.360000 0.000000 1635.640000 0.765000 ;
      RECT 1624.840000 0.000000 1629.660000 0.765000 ;
      RECT 1618.860000 0.000000 1624.140000 0.765000 ;
      RECT 1613.340000 0.000000 1618.160000 0.765000 ;
      RECT 1607.360000 0.000000 1612.640000 0.765000 ;
      RECT 1601.380000 0.000000 1606.660000 0.765000 ;
      RECT 1595.860000 0.000000 1600.680000 0.765000 ;
      RECT 1589.880000 0.000000 1595.160000 0.765000 ;
      RECT 1584.360000 0.000000 1589.180000 0.765000 ;
      RECT 1578.380000 0.000000 1583.660000 0.765000 ;
      RECT 1572.400000 0.000000 1577.680000 0.765000 ;
      RECT 1566.880000 0.000000 1571.700000 0.765000 ;
      RECT 1560.900000 0.000000 1566.180000 0.765000 ;
      RECT 1555.380000 0.000000 1560.200000 0.765000 ;
      RECT 1549.400000 0.000000 1554.680000 0.765000 ;
      RECT 1543.420000 0.000000 1548.700000 0.765000 ;
      RECT 1537.900000 0.000000 1542.720000 0.765000 ;
      RECT 1531.920000 0.000000 1537.200000 0.765000 ;
      RECT 1526.400000 0.000000 1531.220000 0.765000 ;
      RECT 1520.420000 0.000000 1525.700000 0.765000 ;
      RECT 1514.440000 0.000000 1519.720000 0.765000 ;
      RECT 1508.920000 0.000000 1513.740000 0.765000 ;
      RECT 1502.940000 0.000000 1508.220000 0.765000 ;
      RECT 1496.960000 0.000000 1502.240000 0.765000 ;
      RECT 1491.440000 0.000000 1496.260000 0.765000 ;
      RECT 1485.460000 0.000000 1490.740000 0.765000 ;
      RECT 1479.940000 0.000000 1484.760000 0.765000 ;
      RECT 1473.960000 0.000000 1479.240000 0.765000 ;
      RECT 1467.980000 0.000000 1473.260000 0.765000 ;
      RECT 1462.460000 0.000000 1467.280000 0.765000 ;
      RECT 1456.480000 0.000000 1461.760000 0.765000 ;
      RECT 1450.960000 0.000000 1455.780000 0.765000 ;
      RECT 1444.980000 0.000000 1450.260000 0.765000 ;
      RECT 1439.000000 0.000000 1444.280000 0.765000 ;
      RECT 1433.480000 0.000000 1438.300000 0.765000 ;
      RECT 1427.500000 0.000000 1432.780000 0.765000 ;
      RECT 1421.980000 0.000000 1426.800000 0.765000 ;
      RECT 1416.000000 0.000000 1421.280000 0.765000 ;
      RECT 1410.020000 0.000000 1415.300000 0.765000 ;
      RECT 1404.500000 0.000000 1409.320000 0.765000 ;
      RECT 1398.520000 0.000000 1403.800000 0.765000 ;
      RECT 1393.000000 0.000000 1397.820000 0.765000 ;
      RECT 1387.020000 0.000000 1392.300000 0.765000 ;
      RECT 1381.040000 0.000000 1386.320000 0.765000 ;
      RECT 1375.520000 0.000000 1380.340000 0.765000 ;
      RECT 1369.540000 0.000000 1374.820000 0.765000 ;
      RECT 1364.020000 0.000000 1368.840000 0.765000 ;
      RECT 1358.040000 0.000000 1363.320000 0.765000 ;
      RECT 1352.060000 0.000000 1357.340000 0.765000 ;
      RECT 1346.540000 0.000000 1351.360000 0.765000 ;
      RECT 1340.560000 0.000000 1345.840000 0.765000 ;
      RECT 1334.580000 0.000000 1339.860000 0.765000 ;
      RECT 1329.060000 0.000000 1333.880000 0.765000 ;
      RECT 1323.080000 0.000000 1328.360000 0.765000 ;
      RECT 1317.560000 0.000000 1322.380000 0.765000 ;
      RECT 1311.580000 0.000000 1316.860000 0.765000 ;
      RECT 1305.600000 0.000000 1310.880000 0.765000 ;
      RECT 1300.080000 0.000000 1304.900000 0.765000 ;
      RECT 1294.100000 0.000000 1299.380000 0.765000 ;
      RECT 1288.580000 0.000000 1293.400000 0.765000 ;
      RECT 1282.600000 0.000000 1287.880000 0.765000 ;
      RECT 1276.620000 0.000000 1281.900000 0.765000 ;
      RECT 1271.100000 0.000000 1275.920000 0.765000 ;
      RECT 1265.120000 0.000000 1270.400000 0.765000 ;
      RECT 1259.600000 0.000000 1264.420000 0.765000 ;
      RECT 1253.620000 0.000000 1258.900000 0.765000 ;
      RECT 1247.640000 0.000000 1252.920000 0.765000 ;
      RECT 1242.120000 0.000000 1246.940000 0.765000 ;
      RECT 1236.140000 0.000000 1241.420000 0.765000 ;
      RECT 1230.620000 0.000000 1235.440000 0.765000 ;
      RECT 1224.640000 0.000000 1229.920000 0.765000 ;
      RECT 1218.660000 0.000000 1223.940000 0.765000 ;
      RECT 1213.140000 0.000000 1217.960000 0.765000 ;
      RECT 1207.160000 0.000000 1212.440000 0.765000 ;
      RECT 1201.180000 0.000000 1206.460000 0.765000 ;
      RECT 1195.660000 0.000000 1200.480000 0.765000 ;
      RECT 1189.680000 0.000000 1194.960000 0.765000 ;
      RECT 1184.160000 0.000000 1188.980000 0.765000 ;
      RECT 1178.180000 0.000000 1183.460000 0.765000 ;
      RECT 1172.200000 0.000000 1177.480000 0.765000 ;
      RECT 1166.680000 0.000000 1171.500000 0.765000 ;
      RECT 1160.700000 0.000000 1165.980000 0.765000 ;
      RECT 1155.180000 0.000000 1160.000000 0.765000 ;
      RECT 1149.200000 0.000000 1154.480000 0.765000 ;
      RECT 1143.220000 0.000000 1148.500000 0.765000 ;
      RECT 1137.700000 0.000000 1142.520000 0.765000 ;
      RECT 1131.720000 0.000000 1137.000000 0.765000 ;
      RECT 1126.200000 0.000000 1131.020000 0.765000 ;
      RECT 1120.220000 0.000000 1125.500000 0.765000 ;
      RECT 1114.240000 0.000000 1119.520000 0.765000 ;
      RECT 1108.720000 0.000000 1113.540000 0.765000 ;
      RECT 1102.740000 0.000000 1108.020000 0.765000 ;
      RECT 1097.220000 0.000000 1102.040000 0.765000 ;
      RECT 1091.240000 0.000000 1096.520000 0.765000 ;
      RECT 1085.260000 0.000000 1090.540000 0.765000 ;
      RECT 1079.740000 0.000000 1084.560000 0.765000 ;
      RECT 1073.760000 0.000000 1079.040000 0.765000 ;
      RECT 1067.780000 0.000000 1073.060000 0.765000 ;
      RECT 1062.260000 0.000000 1067.080000 0.765000 ;
      RECT 1056.280000 0.000000 1061.560000 0.765000 ;
      RECT 1050.760000 0.000000 1055.580000 0.765000 ;
      RECT 1044.780000 0.000000 1050.060000 0.765000 ;
      RECT 1038.800000 0.000000 1044.080000 0.765000 ;
      RECT 1033.280000 0.000000 1038.100000 0.765000 ;
      RECT 1027.300000 0.000000 1032.580000 0.765000 ;
      RECT 1021.780000 0.000000 1026.600000 0.765000 ;
      RECT 1015.800000 0.000000 1021.080000 0.765000 ;
      RECT 1009.820000 0.000000 1015.100000 0.765000 ;
      RECT 1004.300000 0.000000 1009.120000 0.765000 ;
      RECT 998.320000 0.000000 1003.600000 0.765000 ;
      RECT 992.800000 0.000000 997.620000 0.765000 ;
      RECT 986.820000 0.000000 992.100000 0.765000 ;
      RECT 980.840000 0.000000 986.120000 0.765000 ;
      RECT 975.320000 0.000000 980.140000 0.765000 ;
      RECT 969.340000 0.000000 974.620000 0.765000 ;
      RECT 963.820000 0.000000 968.640000 0.765000 ;
      RECT 957.840000 0.000000 963.120000 0.765000 ;
      RECT 951.860000 0.000000 957.140000 0.765000 ;
      RECT 946.340000 0.000000 951.160000 0.765000 ;
      RECT 940.360000 0.000000 945.640000 0.765000 ;
      RECT 934.380000 0.000000 939.660000 0.765000 ;
      RECT 928.860000 0.000000 933.680000 0.765000 ;
      RECT 922.880000 0.000000 928.160000 0.765000 ;
      RECT 917.360000 0.000000 922.180000 0.765000 ;
      RECT 911.380000 0.000000 916.660000 0.765000 ;
      RECT 905.400000 0.000000 910.680000 0.765000 ;
      RECT 899.880000 0.000000 904.700000 0.765000 ;
      RECT 893.900000 0.000000 899.180000 0.765000 ;
      RECT 888.380000 0.000000 893.200000 0.765000 ;
      RECT 882.400000 0.000000 887.680000 0.765000 ;
      RECT 876.420000 0.000000 881.700000 0.765000 ;
      RECT 870.900000 0.000000 875.720000 0.765000 ;
      RECT 864.920000 0.000000 870.200000 0.765000 ;
      RECT 859.400000 0.000000 864.220000 0.765000 ;
      RECT 853.420000 0.000000 858.700000 0.765000 ;
      RECT 847.440000 0.000000 852.720000 0.765000 ;
      RECT 841.920000 0.000000 846.740000 0.765000 ;
      RECT 835.940000 0.000000 841.220000 0.765000 ;
      RECT 830.420000 0.000000 835.240000 0.765000 ;
      RECT 824.440000 0.000000 829.720000 0.765000 ;
      RECT 818.460000 0.000000 823.740000 0.765000 ;
      RECT 812.940000 0.000000 817.760000 0.765000 ;
      RECT 806.960000 0.000000 812.240000 0.765000 ;
      RECT 800.980000 0.000000 806.260000 0.765000 ;
      RECT 795.460000 0.000000 800.280000 0.765000 ;
      RECT 789.480000 0.000000 794.760000 0.765000 ;
      RECT 783.960000 0.000000 788.780000 0.765000 ;
      RECT 777.980000 0.000000 783.260000 0.765000 ;
      RECT 772.000000 0.000000 777.280000 0.765000 ;
      RECT 766.480000 0.000000 771.300000 0.765000 ;
      RECT 760.500000 0.000000 765.780000 0.765000 ;
      RECT 754.980000 0.000000 759.800000 0.765000 ;
      RECT 749.000000 0.000000 754.280000 0.765000 ;
      RECT 743.020000 0.000000 748.300000 0.765000 ;
      RECT 737.500000 0.000000 742.320000 0.765000 ;
      RECT 731.520000 0.000000 736.800000 0.765000 ;
      RECT 726.000000 0.000000 730.820000 0.765000 ;
      RECT 720.020000 0.000000 725.300000 0.765000 ;
      RECT 714.040000 0.000000 719.320000 0.765000 ;
      RECT 708.520000 0.000000 713.340000 0.765000 ;
      RECT 702.540000 0.000000 707.820000 0.765000 ;
      RECT 697.020000 0.000000 701.840000 0.765000 ;
      RECT 691.040000 0.000000 696.320000 0.765000 ;
      RECT 685.060000 0.000000 690.340000 0.765000 ;
      RECT 679.540000 0.000000 684.360000 0.765000 ;
      RECT 673.560000 0.000000 678.840000 0.765000 ;
      RECT 667.580000 0.000000 672.860000 0.765000 ;
      RECT 662.060000 0.000000 666.880000 0.765000 ;
      RECT 656.080000 0.000000 661.360000 0.765000 ;
      RECT 650.560000 0.000000 655.380000 0.765000 ;
      RECT 644.580000 0.000000 649.860000 0.765000 ;
      RECT 638.600000 0.000000 643.880000 0.765000 ;
      RECT 633.080000 0.000000 637.900000 0.765000 ;
      RECT 627.100000 0.000000 632.380000 0.765000 ;
      RECT 621.580000 0.000000 626.400000 0.765000 ;
      RECT 615.600000 0.000000 620.880000 0.765000 ;
      RECT 609.620000 0.000000 614.900000 0.765000 ;
      RECT 604.100000 0.000000 608.920000 0.765000 ;
      RECT 598.120000 0.000000 603.400000 0.765000 ;
      RECT 592.600000 0.000000 597.420000 0.765000 ;
      RECT 586.620000 0.000000 591.900000 0.765000 ;
      RECT 580.640000 0.000000 585.920000 0.765000 ;
      RECT 575.120000 0.000000 579.940000 0.765000 ;
      RECT 569.140000 0.000000 574.420000 0.765000 ;
      RECT 563.620000 0.000000 568.440000 0.765000 ;
      RECT 557.640000 0.000000 562.920000 0.765000 ;
      RECT 551.660000 0.000000 556.940000 0.765000 ;
      RECT 546.140000 0.000000 550.960000 0.765000 ;
      RECT 540.160000 0.000000 545.440000 0.765000 ;
      RECT 534.180000 0.000000 539.460000 0.765000 ;
      RECT 528.660000 0.000000 533.480000 0.765000 ;
      RECT 522.680000 0.000000 527.960000 0.765000 ;
      RECT 517.160000 0.000000 521.980000 0.765000 ;
      RECT 511.180000 0.000000 516.460000 0.765000 ;
      RECT 505.200000 0.000000 510.480000 0.765000 ;
      RECT 499.680000 0.000000 504.500000 0.765000 ;
      RECT 493.700000 0.000000 498.980000 0.765000 ;
      RECT 488.180000 0.000000 493.000000 0.765000 ;
      RECT 482.200000 0.000000 487.480000 0.765000 ;
      RECT 476.220000 0.000000 481.500000 0.765000 ;
      RECT 470.700000 0.000000 475.520000 0.765000 ;
      RECT 464.720000 0.000000 470.000000 0.765000 ;
      RECT 459.200000 0.000000 464.020000 0.765000 ;
      RECT 453.220000 0.000000 458.500000 0.765000 ;
      RECT 447.240000 0.000000 452.520000 0.765000 ;
      RECT 441.720000 0.000000 446.540000 0.765000 ;
      RECT 435.740000 0.000000 441.020000 0.765000 ;
      RECT 430.220000 0.000000 435.040000 0.765000 ;
      RECT 424.240000 0.000000 429.520000 0.765000 ;
      RECT 418.260000 0.000000 423.540000 0.765000 ;
      RECT 412.740000 0.000000 417.560000 0.765000 ;
      RECT 406.760000 0.000000 412.040000 0.765000 ;
      RECT 400.780000 0.000000 406.060000 0.765000 ;
      RECT 395.260000 0.000000 400.080000 0.765000 ;
      RECT 389.280000 0.000000 394.560000 0.765000 ;
      RECT 383.760000 0.000000 388.580000 0.765000 ;
      RECT 377.780000 0.000000 383.060000 0.765000 ;
      RECT 371.800000 0.000000 377.080000 0.765000 ;
      RECT 366.280000 0.000000 371.100000 0.765000 ;
      RECT 360.300000 0.000000 365.580000 0.765000 ;
      RECT 354.780000 0.000000 359.600000 0.765000 ;
      RECT 348.800000 0.000000 354.080000 0.765000 ;
      RECT 342.820000 0.000000 348.100000 0.765000 ;
      RECT 337.300000 0.000000 342.120000 0.765000 ;
      RECT 331.320000 0.000000 336.600000 0.765000 ;
      RECT 325.800000 0.000000 330.620000 0.765000 ;
      RECT 319.820000 0.000000 325.100000 0.765000 ;
      RECT 313.840000 0.000000 319.120000 0.765000 ;
      RECT 308.320000 0.000000 313.140000 0.765000 ;
      RECT 302.340000 0.000000 307.620000 0.765000 ;
      RECT 296.820000 0.000000 301.640000 0.765000 ;
      RECT 290.840000 0.000000 296.120000 0.765000 ;
      RECT 284.860000 0.000000 290.140000 0.765000 ;
      RECT 279.340000 0.000000 284.160000 0.765000 ;
      RECT 273.360000 0.000000 278.640000 0.765000 ;
      RECT 267.380000 0.000000 272.660000 0.765000 ;
      RECT 261.860000 0.000000 266.680000 0.765000 ;
      RECT 255.880000 0.000000 261.160000 0.765000 ;
      RECT 250.360000 0.000000 255.180000 0.765000 ;
      RECT 244.380000 0.000000 249.660000 0.765000 ;
      RECT 238.400000 0.000000 243.680000 0.765000 ;
      RECT 232.880000 0.000000 237.700000 0.765000 ;
      RECT 226.900000 0.000000 232.180000 0.765000 ;
      RECT 221.380000 0.000000 226.200000 0.765000 ;
      RECT 215.400000 0.000000 220.680000 0.765000 ;
      RECT 209.420000 0.000000 214.700000 0.765000 ;
      RECT 203.900000 0.000000 208.720000 0.765000 ;
      RECT 197.920000 0.000000 203.200000 0.765000 ;
      RECT 192.400000 0.000000 197.220000 0.765000 ;
      RECT 186.420000 0.000000 191.700000 0.765000 ;
      RECT 180.440000 0.000000 185.720000 0.765000 ;
      RECT 174.920000 0.000000 179.740000 0.765000 ;
      RECT 168.940000 0.000000 174.220000 0.765000 ;
      RECT 163.420000 0.000000 168.240000 0.765000 ;
      RECT 157.440000 0.000000 162.720000 0.765000 ;
      RECT 151.460000 0.000000 156.740000 0.765000 ;
      RECT 145.940000 0.000000 150.760000 0.765000 ;
      RECT 139.960000 0.000000 145.240000 0.765000 ;
      RECT 133.980000 0.000000 139.260000 0.765000 ;
      RECT 128.460000 0.000000 133.280000 0.765000 ;
      RECT 122.480000 0.000000 127.760000 0.765000 ;
      RECT 116.960000 0.000000 121.780000 0.765000 ;
      RECT 110.980000 0.000000 116.260000 0.765000 ;
      RECT 105.000000 0.000000 110.280000 0.765000 ;
      RECT 99.480000 0.000000 104.300000 0.765000 ;
      RECT 93.500000 0.000000 98.780000 0.765000 ;
      RECT 87.980000 0.000000 92.800000 0.765000 ;
      RECT 82.000000 0.000000 87.280000 0.765000 ;
      RECT 76.020000 0.000000 81.300000 0.765000 ;
      RECT 70.500000 0.000000 75.320000 0.765000 ;
      RECT 64.520000 0.000000 69.800000 0.765000 ;
      RECT 59.000000 0.000000 63.820000 0.765000 ;
      RECT 53.020000 0.000000 58.300000 0.765000 ;
      RECT 47.040000 0.000000 52.320000 0.765000 ;
      RECT 41.520000 0.000000 46.340000 0.765000 ;
      RECT 35.540000 0.000000 40.820000 0.765000 ;
      RECT 30.020000 0.000000 34.840000 0.765000 ;
      RECT 24.040000 0.000000 29.320000 0.765000 ;
      RECT 18.060000 0.000000 23.340000 0.765000 ;
      RECT 12.540000 0.000000 17.360000 0.765000 ;
      RECT 6.560000 0.000000 11.840000 0.765000 ;
      RECT 1.040000 0.000000 5.860000 0.765000 ;
      RECT 0.000000 0.000000 0.340000 0.765000 ;
    LAYER met3 ;
      RECT 1.200000 3469.190000 2858.620000 3470.040000 ;
      RECT 0.000000 3391.600000 2859.820000 3469.190000 ;
      RECT 0.000000 3390.500000 2858.620000 3391.600000 ;
      RECT 0.000000 3385.500000 2859.820000 3390.500000 ;
      RECT 1.200000 3384.400000 2859.820000 3385.500000 ;
      RECT 0.000000 3312.910000 2859.820000 3384.400000 ;
      RECT 0.000000 3311.810000 2858.620000 3312.910000 ;
      RECT 0.000000 3300.710000 2859.820000 3311.810000 ;
      RECT 1.200000 3299.610000 2859.820000 3300.710000 ;
      RECT 0.000000 3234.220000 2859.820000 3299.610000 ;
      RECT 0.000000 3233.120000 2858.620000 3234.220000 ;
      RECT 0.000000 3215.920000 2859.820000 3233.120000 ;
      RECT 1.200000 3214.820000 2859.820000 3215.920000 ;
      RECT 0.000000 3154.920000 2859.820000 3214.820000 ;
      RECT 0.000000 3153.820000 2858.620000 3154.920000 ;
      RECT 0.000000 3131.740000 2859.820000 3153.820000 ;
      RECT 1.200000 3130.640000 2859.820000 3131.740000 ;
      RECT 0.000000 3076.230000 2859.820000 3130.640000 ;
      RECT 0.000000 3075.130000 2858.620000 3076.230000 ;
      RECT 0.000000 3046.950000 2859.820000 3075.130000 ;
      RECT 1.200000 3045.850000 2859.820000 3046.950000 ;
      RECT 0.000000 2997.540000 2859.820000 3045.850000 ;
      RECT 0.000000 2996.440000 2858.620000 2997.540000 ;
      RECT 0.000000 2962.160000 2859.820000 2996.440000 ;
      RECT 1.200000 2961.060000 2859.820000 2962.160000 ;
      RECT 0.000000 2918.850000 2859.820000 2961.060000 ;
      RECT 0.000000 2917.750000 2858.620000 2918.850000 ;
      RECT 0.000000 2877.980000 2859.820000 2917.750000 ;
      RECT 1.200000 2876.880000 2859.820000 2877.980000 ;
      RECT 0.000000 2839.550000 2859.820000 2876.880000 ;
      RECT 0.000000 2838.450000 2858.620000 2839.550000 ;
      RECT 0.000000 2793.190000 2859.820000 2838.450000 ;
      RECT 1.200000 2792.090000 2859.820000 2793.190000 ;
      RECT 0.000000 2760.860000 2859.820000 2792.090000 ;
      RECT 0.000000 2759.760000 2858.620000 2760.860000 ;
      RECT 0.000000 2708.400000 2859.820000 2759.760000 ;
      RECT 1.200000 2707.300000 2859.820000 2708.400000 ;
      RECT 0.000000 2682.170000 2859.820000 2707.300000 ;
      RECT 0.000000 2681.070000 2858.620000 2682.170000 ;
      RECT 0.000000 2623.610000 2859.820000 2681.070000 ;
      RECT 1.200000 2622.510000 2859.820000 2623.610000 ;
      RECT 0.000000 2603.480000 2859.820000 2622.510000 ;
      RECT 0.000000 2602.380000 2858.620000 2603.480000 ;
      RECT 0.000000 2539.430000 2859.820000 2602.380000 ;
      RECT 1.200000 2538.330000 2859.820000 2539.430000 ;
      RECT 0.000000 2524.180000 2859.820000 2538.330000 ;
      RECT 0.000000 2523.080000 2858.620000 2524.180000 ;
      RECT 0.000000 2454.640000 2859.820000 2523.080000 ;
      RECT 1.200000 2453.540000 2859.820000 2454.640000 ;
      RECT 0.000000 2445.490000 2859.820000 2453.540000 ;
      RECT 0.000000 2444.390000 2858.620000 2445.490000 ;
      RECT 0.000000 2369.850000 2859.820000 2444.390000 ;
      RECT 1.200000 2368.750000 2859.820000 2369.850000 ;
      RECT 0.000000 2366.800000 2859.820000 2368.750000 ;
      RECT 0.000000 2365.700000 2858.620000 2366.800000 ;
      RECT 0.000000 2288.110000 2859.820000 2365.700000 ;
      RECT 0.000000 2287.010000 2858.620000 2288.110000 ;
      RECT 0.000000 2285.670000 2859.820000 2287.010000 ;
      RECT 1.200000 2284.570000 2859.820000 2285.670000 ;
      RECT 0.000000 2208.810000 2859.820000 2284.570000 ;
      RECT 0.000000 2207.710000 2858.620000 2208.810000 ;
      RECT 0.000000 2200.880000 2859.820000 2207.710000 ;
      RECT 1.200000 2199.780000 2859.820000 2200.880000 ;
      RECT 0.000000 2130.120000 2859.820000 2199.780000 ;
      RECT 0.000000 2129.020000 2858.620000 2130.120000 ;
      RECT 0.000000 2116.090000 2859.820000 2129.020000 ;
      RECT 1.200000 2114.990000 2859.820000 2116.090000 ;
      RECT 0.000000 2051.430000 2859.820000 2114.990000 ;
      RECT 0.000000 2050.330000 2858.620000 2051.430000 ;
      RECT 0.000000 2031.300000 2859.820000 2050.330000 ;
      RECT 1.200000 2030.200000 2859.820000 2031.300000 ;
      RECT 0.000000 1972.740000 2859.820000 2030.200000 ;
      RECT 0.000000 1971.640000 2858.620000 1972.740000 ;
      RECT 0.000000 1947.120000 2859.820000 1971.640000 ;
      RECT 1.200000 1946.020000 2859.820000 1947.120000 ;
      RECT 0.000000 1893.440000 2859.820000 1946.020000 ;
      RECT 0.000000 1892.340000 2858.620000 1893.440000 ;
      RECT 0.000000 1862.330000 2859.820000 1892.340000 ;
      RECT 1.200000 1861.230000 2859.820000 1862.330000 ;
      RECT 0.000000 1814.750000 2859.820000 1861.230000 ;
      RECT 0.000000 1813.650000 2858.620000 1814.750000 ;
      RECT 0.000000 1777.540000 2859.820000 1813.650000 ;
      RECT 1.200000 1776.440000 2859.820000 1777.540000 ;
      RECT 0.000000 1736.060000 2859.820000 1776.440000 ;
      RECT 0.000000 1734.960000 2858.620000 1736.060000 ;
      RECT 0.000000 1693.360000 2859.820000 1734.960000 ;
      RECT 1.200000 1692.260000 2859.820000 1693.360000 ;
      RECT 0.000000 1657.370000 2859.820000 1692.260000 ;
      RECT 0.000000 1656.270000 2858.620000 1657.370000 ;
      RECT 0.000000 1608.570000 2859.820000 1656.270000 ;
      RECT 1.200000 1607.470000 2859.820000 1608.570000 ;
      RECT 0.000000 1578.070000 2859.820000 1607.470000 ;
      RECT 0.000000 1576.970000 2858.620000 1578.070000 ;
      RECT 0.000000 1523.780000 2859.820000 1576.970000 ;
      RECT 1.200000 1522.680000 2859.820000 1523.780000 ;
      RECT 0.000000 1499.380000 2859.820000 1522.680000 ;
      RECT 0.000000 1498.280000 2858.620000 1499.380000 ;
      RECT 0.000000 1439.600000 2859.820000 1498.280000 ;
      RECT 1.200000 1438.500000 2859.820000 1439.600000 ;
      RECT 0.000000 1420.690000 2859.820000 1438.500000 ;
      RECT 0.000000 1419.590000 2858.620000 1420.690000 ;
      RECT 0.000000 1354.810000 2859.820000 1419.590000 ;
      RECT 1.200000 1353.710000 2859.820000 1354.810000 ;
      RECT 0.000000 1342.000000 2859.820000 1353.710000 ;
      RECT 0.000000 1340.900000 2858.620000 1342.000000 ;
      RECT 0.000000 1270.020000 2859.820000 1340.900000 ;
      RECT 1.200000 1268.920000 2859.820000 1270.020000 ;
      RECT 0.000000 1262.700000 2859.820000 1268.920000 ;
      RECT 0.000000 1261.600000 2858.620000 1262.700000 ;
      RECT 0.000000 1185.230000 2859.820000 1261.600000 ;
      RECT 1.200000 1184.130000 2859.820000 1185.230000 ;
      RECT 0.000000 1184.010000 2859.820000 1184.130000 ;
      RECT 0.000000 1182.910000 2858.620000 1184.010000 ;
      RECT 0.000000 1105.320000 2859.820000 1182.910000 ;
      RECT 0.000000 1104.220000 2858.620000 1105.320000 ;
      RECT 0.000000 1101.050000 2859.820000 1104.220000 ;
      RECT 1.200000 1099.950000 2859.820000 1101.050000 ;
      RECT 0.000000 1026.630000 2859.820000 1099.950000 ;
      RECT 0.000000 1025.530000 2858.620000 1026.630000 ;
      RECT 0.000000 1016.260000 2859.820000 1025.530000 ;
      RECT 1.200000 1015.160000 2859.820000 1016.260000 ;
      RECT 0.000000 947.330000 2859.820000 1015.160000 ;
      RECT 0.000000 946.230000 2858.620000 947.330000 ;
      RECT 0.000000 931.470000 2859.820000 946.230000 ;
      RECT 1.200000 930.370000 2859.820000 931.470000 ;
      RECT 0.000000 868.640000 2859.820000 930.370000 ;
      RECT 0.000000 867.540000 2858.620000 868.640000 ;
      RECT 0.000000 847.290000 2859.820000 867.540000 ;
      RECT 1.200000 846.190000 2859.820000 847.290000 ;
      RECT 0.000000 789.950000 2859.820000 846.190000 ;
      RECT 0.000000 788.850000 2858.620000 789.950000 ;
      RECT 0.000000 762.500000 2859.820000 788.850000 ;
      RECT 1.200000 761.400000 2859.820000 762.500000 ;
      RECT 0.000000 711.260000 2859.820000 761.400000 ;
      RECT 0.000000 710.160000 2858.620000 711.260000 ;
      RECT 0.000000 677.710000 2859.820000 710.160000 ;
      RECT 1.200000 676.610000 2859.820000 677.710000 ;
      RECT 0.000000 631.960000 2859.820000 676.610000 ;
      RECT 0.000000 630.860000 2858.620000 631.960000 ;
      RECT 0.000000 592.920000 2859.820000 630.860000 ;
      RECT 1.200000 591.820000 2859.820000 592.920000 ;
      RECT 0.000000 553.270000 2859.820000 591.820000 ;
      RECT 0.000000 552.170000 2858.620000 553.270000 ;
      RECT 0.000000 508.740000 2859.820000 552.170000 ;
      RECT 1.200000 507.640000 2859.820000 508.740000 ;
      RECT 0.000000 474.580000 2859.820000 507.640000 ;
      RECT 0.000000 473.480000 2858.620000 474.580000 ;
      RECT 0.000000 423.950000 2859.820000 473.480000 ;
      RECT 1.200000 422.850000 2859.820000 423.950000 ;
      RECT 0.000000 395.890000 2859.820000 422.850000 ;
      RECT 0.000000 394.790000 2858.620000 395.890000 ;
      RECT 0.000000 339.160000 2859.820000 394.790000 ;
      RECT 1.200000 338.060000 2859.820000 339.160000 ;
      RECT 0.000000 316.590000 2859.820000 338.060000 ;
      RECT 0.000000 315.490000 2858.620000 316.590000 ;
      RECT 0.000000 254.980000 2859.820000 315.490000 ;
      RECT 1.200000 253.880000 2859.820000 254.980000 ;
      RECT 0.000000 237.900000 2859.820000 253.880000 ;
      RECT 0.000000 236.800000 2858.620000 237.900000 ;
      RECT 0.000000 170.190000 2859.820000 236.800000 ;
      RECT 1.200000 169.090000 2859.820000 170.190000 ;
      RECT 0.000000 159.210000 2859.820000 169.090000 ;
      RECT 0.000000 158.110000 2858.620000 159.210000 ;
      RECT 0.000000 85.400000 2859.820000 158.110000 ;
      RECT 1.200000 84.300000 2859.820000 85.400000 ;
      RECT 0.000000 80.520000 2859.820000 84.300000 ;
      RECT 0.000000 79.420000 2858.620000 80.520000 ;
      RECT 0.000000 1.220000 2859.820000 79.420000 ;
      RECT 1.200000 0.120000 2858.620000 1.220000 ;
      RECT 0.000000 0.000000 2859.820000 0.120000 ;
    LAYER met4 ;
      RECT 28.920000 3449.140000 2830.900000 3470.040000 ;
      RECT 2655.760000 3442.940000 2787.600000 3449.140000 ;
      RECT 2519.760000 3442.940000 2651.600000 3449.140000 ;
      RECT 2383.760000 3442.940000 2515.600000 3449.140000 ;
      RECT 2247.760000 3442.940000 2379.600000 3449.140000 ;
      RECT 2111.760000 3442.940000 2243.600000 3449.140000 ;
      RECT 1975.760000 3442.940000 2107.600000 3449.140000 ;
      RECT 1839.760000 3442.940000 1971.600000 3449.140000 ;
      RECT 1703.760000 3442.940000 1835.600000 3449.140000 ;
      RECT 1567.760000 3442.940000 1699.600000 3449.140000 ;
      RECT 1431.760000 3442.940000 1563.600000 3449.140000 ;
      RECT 1295.760000 3442.940000 1427.600000 3449.140000 ;
      RECT 1159.760000 3442.940000 1291.600000 3449.140000 ;
      RECT 1023.760000 3442.940000 1155.600000 3449.140000 ;
      RECT 887.760000 3442.940000 1019.600000 3449.140000 ;
      RECT 751.760000 3442.940000 883.600000 3449.140000 ;
      RECT 615.760000 3442.940000 747.600000 3449.140000 ;
      RECT 479.760000 3442.940000 611.600000 3449.140000 ;
      RECT 343.760000 3442.940000 475.600000 3449.140000 ;
      RECT 207.760000 3442.940000 339.600000 3449.140000 ;
      RECT 71.760000 3442.940000 203.600000 3449.140000 ;
      RECT 2655.760000 3055.775000 2719.600000 3442.940000 ;
      RECT 2179.760000 3055.775000 2243.600000 3442.940000 ;
      RECT 1635.760000 3055.775000 1699.600000 3442.940000 ;
      RECT 1159.760000 3055.775000 1223.600000 3442.940000 ;
      RECT 615.760000 3055.775000 679.600000 3442.940000 ;
      RECT 139.760000 3055.775000 203.600000 3442.940000 ;
      RECT 2655.760000 3053.175000 2700.655000 3055.775000 ;
      RECT 2587.760000 3053.175000 2651.600000 3442.940000 ;
      RECT 2519.760000 3053.175000 2583.600000 3442.940000 ;
      RECT 2451.760000 3053.175000 2515.600000 3442.940000 ;
      RECT 2383.760000 3053.175000 2447.600000 3442.940000 ;
      RECT 2315.760000 3053.175000 2379.600000 3442.940000 ;
      RECT 2247.760000 3053.175000 2311.600000 3442.940000 ;
      RECT 2210.875000 3053.175000 2243.600000 3055.775000 ;
      RECT 2111.760000 3053.175000 2175.600000 3442.940000 ;
      RECT 2043.760000 3053.175000 2107.600000 3442.940000 ;
      RECT 1975.760000 3053.175000 2039.600000 3442.940000 ;
      RECT 1907.760000 3053.175000 1971.600000 3442.940000 ;
      RECT 1839.760000 3053.175000 1903.600000 3442.940000 ;
      RECT 1771.760000 3053.175000 1835.600000 3442.940000 ;
      RECT 1703.760000 3053.175000 1767.600000 3442.940000 ;
      RECT 1691.015000 3053.175000 1699.600000 3055.775000 ;
      RECT 1159.760000 3053.175000 1166.015000 3055.775000 ;
      RECT 1091.760000 3053.175000 1155.600000 3442.940000 ;
      RECT 1023.760000 3053.175000 1087.600000 3442.940000 ;
      RECT 955.760000 3053.175000 1019.600000 3442.940000 ;
      RECT 887.760000 3053.175000 951.600000 3442.940000 ;
      RECT 819.760000 3053.175000 883.600000 3442.940000 ;
      RECT 751.760000 3053.175000 815.600000 3442.940000 ;
      RECT 683.760000 3053.175000 747.600000 3442.940000 ;
      RECT 615.760000 3053.175000 646.155000 3055.775000 ;
      RECT 547.760000 3053.175000 611.600000 3442.940000 ;
      RECT 479.760000 3053.175000 543.600000 3442.940000 ;
      RECT 411.760000 3053.175000 475.600000 3442.940000 ;
      RECT 343.760000 3053.175000 407.600000 3442.940000 ;
      RECT 275.760000 3053.175000 339.600000 3442.940000 ;
      RECT 207.760000 3053.175000 271.600000 3442.940000 ;
      RECT 156.375000 3053.175000 203.600000 3055.775000 ;
      RECT 2587.760000 3052.175000 2700.655000 3053.175000 ;
      RECT 2210.875000 3052.175000 2311.600000 3053.175000 ;
      RECT 2179.760000 3052.175000 2180.795000 3055.775000 ;
      RECT 1691.015000 3052.175000 1767.600000 3053.175000 ;
      RECT 1091.760000 3052.175000 1166.015000 3053.175000 ;
      RECT 676.235000 3052.175000 679.600000 3055.775000 ;
      RECT 547.760000 3052.175000 646.155000 3053.175000 ;
      RECT 156.375000 3052.175000 271.600000 3053.175000 ;
      RECT 2587.760000 3049.575000 2697.055000 3052.175000 ;
      RECT 2451.760000 3049.575000 2583.600000 3053.175000 ;
      RECT 2315.760000 3049.575000 2447.600000 3053.175000 ;
      RECT 2214.475000 3049.575000 2311.600000 3052.175000 ;
      RECT 2043.760000 3049.575000 2175.600000 3053.175000 ;
      RECT 1907.760000 3049.575000 2039.600000 3053.175000 ;
      RECT 1771.760000 3049.575000 1903.600000 3053.175000 ;
      RECT 1694.615000 3049.575000 1767.600000 3052.175000 ;
      RECT 1091.760000 3049.575000 1162.415000 3052.175000 ;
      RECT 955.760000 3049.575000 1087.600000 3053.175000 ;
      RECT 819.760000 3049.575000 951.600000 3053.175000 ;
      RECT 683.760000 3049.575000 815.600000 3053.175000 ;
      RECT 547.760000 3049.575000 642.555000 3052.175000 ;
      RECT 411.760000 3049.575000 543.600000 3053.175000 ;
      RECT 275.760000 3049.575000 407.600000 3053.175000 ;
      RECT 159.975000 3049.575000 271.600000 3052.175000 ;
      RECT 2214.475000 2649.275000 2697.055000 3049.575000 ;
      RECT 1694.615000 2649.275000 2177.195000 3049.575000 ;
      RECT 679.835000 2649.275000 1162.415000 3049.575000 ;
      RECT 159.975000 2649.275000 642.555000 3049.575000 ;
      RECT 2699.655000 2646.675000 2700.655000 3052.175000 ;
      RECT 2587.760000 2646.675000 2697.055000 2649.275000 ;
      RECT 2214.475000 2646.675000 2311.600000 2649.275000 ;
      RECT 2210.875000 2646.675000 2211.875000 3052.175000 ;
      RECT 2179.795000 2646.675000 2180.795000 3052.175000 ;
      RECT 1694.615000 2646.675000 1767.600000 2649.275000 ;
      RECT 1691.015000 2646.675000 1692.015000 3052.175000 ;
      RECT 1165.015000 2646.675000 1166.015000 3052.175000 ;
      RECT 1091.760000 2646.675000 1162.415000 2649.275000 ;
      RECT 676.235000 2646.675000 677.235000 3052.175000 ;
      RECT 645.155000 2646.675000 646.155000 3052.175000 ;
      RECT 547.760000 2646.675000 642.555000 2649.275000 ;
      RECT 159.975000 2646.675000 271.600000 2649.275000 ;
      RECT 156.375000 2646.675000 157.375000 3052.175000 ;
      RECT 2587.760000 2645.675000 2700.655000 2646.675000 ;
      RECT 2451.760000 2645.675000 2583.600000 2649.275000 ;
      RECT 2315.760000 2645.675000 2447.600000 2649.275000 ;
      RECT 2210.875000 2645.675000 2311.600000 2646.675000 ;
      RECT 2043.760000 2645.675000 2175.600000 2649.275000 ;
      RECT 1907.760000 2645.675000 2039.600000 2649.275000 ;
      RECT 1771.760000 2645.675000 1903.600000 2649.275000 ;
      RECT 1691.015000 2645.675000 1767.600000 2646.675000 ;
      RECT 1091.760000 2645.675000 1166.015000 2646.675000 ;
      RECT 955.760000 2645.675000 1087.600000 2649.275000 ;
      RECT 819.760000 2645.675000 951.600000 2649.275000 ;
      RECT 683.760000 2645.675000 815.600000 2649.275000 ;
      RECT 547.760000 2645.675000 646.155000 2646.675000 ;
      RECT 411.760000 2645.675000 543.600000 2649.275000 ;
      RECT 275.760000 2645.675000 407.600000 2649.275000 ;
      RECT 156.375000 2645.675000 271.600000 2646.675000 ;
      RECT 2703.255000 2643.075000 2719.600000 3055.775000 ;
      RECT 2655.760000 2643.075000 2700.655000 2645.675000 ;
      RECT 2210.875000 2643.075000 2243.600000 2645.675000 ;
      RECT 2183.395000 2643.075000 2208.275000 3055.775000 ;
      RECT 2179.760000 2643.075000 2180.795000 2646.675000 ;
      RECT 1691.015000 2643.075000 1699.600000 2645.675000 ;
      RECT 1635.760000 2643.075000 1688.415000 3055.775000 ;
      RECT 1168.615000 2643.075000 1223.600000 3055.775000 ;
      RECT 1159.760000 2643.075000 1166.015000 2645.675000 ;
      RECT 676.235000 2643.075000 679.600000 2646.675000 ;
      RECT 648.755000 2643.075000 673.635000 3055.775000 ;
      RECT 615.760000 2643.075000 646.155000 2645.675000 ;
      RECT 156.375000 2643.075000 203.600000 2645.675000 ;
      RECT 139.760000 2643.075000 153.775000 3055.775000 ;
      RECT 2655.760000 2567.860000 2719.600000 2643.075000 ;
      RECT 2179.760000 2567.860000 2243.600000 2643.075000 ;
      RECT 1635.760000 2567.860000 1699.600000 2643.075000 ;
      RECT 1159.760000 2567.860000 1223.600000 2643.075000 ;
      RECT 615.760000 2567.860000 679.600000 2643.075000 ;
      RECT 139.760000 2567.860000 203.600000 2643.075000 ;
      RECT 2655.760000 2565.260000 2700.655000 2567.860000 ;
      RECT 2587.760000 2565.260000 2651.600000 2645.675000 ;
      RECT 2519.760000 2565.260000 2583.600000 2645.675000 ;
      RECT 2451.760000 2565.260000 2515.600000 2645.675000 ;
      RECT 2383.760000 2565.260000 2447.600000 2645.675000 ;
      RECT 2315.760000 2565.260000 2379.600000 2645.675000 ;
      RECT 2247.760000 2565.260000 2311.600000 2645.675000 ;
      RECT 2210.875000 2565.260000 2243.600000 2567.860000 ;
      RECT 2111.760000 2565.260000 2175.600000 2645.675000 ;
      RECT 2043.760000 2565.260000 2107.600000 2645.675000 ;
      RECT 1975.760000 2565.260000 2039.600000 2645.675000 ;
      RECT 1907.760000 2565.260000 1971.600000 2645.675000 ;
      RECT 1839.760000 2565.260000 1903.600000 2645.675000 ;
      RECT 1771.760000 2565.260000 1835.600000 2645.675000 ;
      RECT 1703.760000 2565.260000 1767.600000 2645.675000 ;
      RECT 1691.015000 2565.260000 1699.600000 2567.860000 ;
      RECT 1159.760000 2565.260000 1166.015000 2567.860000 ;
      RECT 1091.760000 2565.260000 1155.600000 2645.675000 ;
      RECT 1023.760000 2565.260000 1087.600000 2645.675000 ;
      RECT 955.760000 2565.260000 1019.600000 2645.675000 ;
      RECT 887.760000 2565.260000 951.600000 2645.675000 ;
      RECT 819.760000 2565.260000 883.600000 2645.675000 ;
      RECT 751.760000 2565.260000 815.600000 2645.675000 ;
      RECT 683.760000 2565.260000 747.600000 2645.675000 ;
      RECT 615.760000 2565.260000 646.155000 2567.860000 ;
      RECT 547.760000 2565.260000 611.600000 2645.675000 ;
      RECT 479.760000 2565.260000 543.600000 2645.675000 ;
      RECT 411.760000 2565.260000 475.600000 2645.675000 ;
      RECT 343.760000 2565.260000 407.600000 2645.675000 ;
      RECT 275.760000 2565.260000 339.600000 2645.675000 ;
      RECT 207.760000 2565.260000 271.600000 2645.675000 ;
      RECT 156.375000 2565.260000 203.600000 2567.860000 ;
      RECT 2587.760000 2564.260000 2700.655000 2565.260000 ;
      RECT 2210.875000 2564.260000 2311.600000 2565.260000 ;
      RECT 2179.760000 2564.260000 2180.795000 2567.860000 ;
      RECT 1691.015000 2564.260000 1767.600000 2565.260000 ;
      RECT 1091.760000 2564.260000 1166.015000 2565.260000 ;
      RECT 676.235000 2564.260000 679.600000 2567.860000 ;
      RECT 547.760000 2564.260000 646.155000 2565.260000 ;
      RECT 156.375000 2564.260000 271.600000 2565.260000 ;
      RECT 2587.760000 2561.660000 2697.055000 2564.260000 ;
      RECT 2451.760000 2561.660000 2583.600000 2565.260000 ;
      RECT 2315.760000 2561.660000 2447.600000 2565.260000 ;
      RECT 2214.475000 2561.660000 2311.600000 2564.260000 ;
      RECT 2043.760000 2561.660000 2175.600000 2565.260000 ;
      RECT 1907.760000 2561.660000 2039.600000 2565.260000 ;
      RECT 1771.760000 2561.660000 1903.600000 2565.260000 ;
      RECT 1694.615000 2561.660000 1767.600000 2564.260000 ;
      RECT 1091.760000 2561.660000 1162.415000 2564.260000 ;
      RECT 955.760000 2561.660000 1087.600000 2565.260000 ;
      RECT 819.760000 2561.660000 951.600000 2565.260000 ;
      RECT 683.760000 2561.660000 815.600000 2565.260000 ;
      RECT 547.760000 2561.660000 642.555000 2564.260000 ;
      RECT 411.760000 2561.660000 543.600000 2565.260000 ;
      RECT 275.760000 2561.660000 407.600000 2565.260000 ;
      RECT 159.975000 2561.660000 271.600000 2564.260000 ;
      RECT 2214.475000 2161.360000 2697.055000 2561.660000 ;
      RECT 1694.615000 2161.360000 2177.195000 2561.660000 ;
      RECT 679.835000 2161.360000 1162.415000 2561.660000 ;
      RECT 159.975000 2161.360000 642.555000 2561.660000 ;
      RECT 2699.655000 2158.760000 2700.655000 2564.260000 ;
      RECT 2587.760000 2158.760000 2697.055000 2161.360000 ;
      RECT 2214.475000 2158.760000 2311.600000 2161.360000 ;
      RECT 2210.875000 2158.760000 2211.875000 2564.260000 ;
      RECT 2179.795000 2158.760000 2180.795000 2564.260000 ;
      RECT 1694.615000 2158.760000 1767.600000 2161.360000 ;
      RECT 1691.015000 2158.760000 1692.015000 2564.260000 ;
      RECT 1165.015000 2158.760000 1166.015000 2564.260000 ;
      RECT 1091.760000 2158.760000 1162.415000 2161.360000 ;
      RECT 676.235000 2158.760000 677.235000 2564.260000 ;
      RECT 645.155000 2158.760000 646.155000 2564.260000 ;
      RECT 547.760000 2158.760000 642.555000 2161.360000 ;
      RECT 159.975000 2158.760000 271.600000 2161.360000 ;
      RECT 156.375000 2158.760000 157.375000 2564.260000 ;
      RECT 2587.760000 2157.760000 2700.655000 2158.760000 ;
      RECT 2451.760000 2157.760000 2583.600000 2161.360000 ;
      RECT 2315.760000 2157.760000 2447.600000 2161.360000 ;
      RECT 2210.875000 2157.760000 2311.600000 2158.760000 ;
      RECT 2043.760000 2157.760000 2175.600000 2161.360000 ;
      RECT 1907.760000 2157.760000 2039.600000 2161.360000 ;
      RECT 1771.760000 2157.760000 1903.600000 2161.360000 ;
      RECT 1691.015000 2157.760000 1767.600000 2158.760000 ;
      RECT 1091.760000 2157.760000 1166.015000 2158.760000 ;
      RECT 955.760000 2157.760000 1087.600000 2161.360000 ;
      RECT 819.760000 2157.760000 951.600000 2161.360000 ;
      RECT 683.760000 2157.760000 815.600000 2161.360000 ;
      RECT 547.760000 2157.760000 646.155000 2158.760000 ;
      RECT 411.760000 2157.760000 543.600000 2161.360000 ;
      RECT 275.760000 2157.760000 407.600000 2161.360000 ;
      RECT 156.375000 2157.760000 271.600000 2158.760000 ;
      RECT 2703.255000 2155.160000 2719.600000 2567.860000 ;
      RECT 2655.760000 2155.160000 2700.655000 2157.760000 ;
      RECT 2210.875000 2155.160000 2243.600000 2157.760000 ;
      RECT 2183.395000 2155.160000 2208.275000 2567.860000 ;
      RECT 2179.760000 2155.160000 2180.795000 2158.760000 ;
      RECT 1691.015000 2155.160000 1699.600000 2157.760000 ;
      RECT 1635.760000 2155.160000 1688.415000 2567.860000 ;
      RECT 1168.615000 2155.160000 1223.600000 2567.860000 ;
      RECT 1159.760000 2155.160000 1166.015000 2157.760000 ;
      RECT 676.235000 2155.160000 679.600000 2158.760000 ;
      RECT 648.755000 2155.160000 673.635000 2567.860000 ;
      RECT 615.760000 2155.160000 646.155000 2157.760000 ;
      RECT 156.375000 2155.160000 203.600000 2157.760000 ;
      RECT 139.760000 2155.160000 153.775000 2567.860000 ;
      RECT 2655.760000 2085.920000 2719.600000 2155.160000 ;
      RECT 2179.760000 2085.920000 2243.600000 2155.160000 ;
      RECT 1635.760000 2085.920000 1699.600000 2155.160000 ;
      RECT 2655.760000 2083.320000 2700.655000 2085.920000 ;
      RECT 2587.760000 2083.320000 2651.600000 2157.760000 ;
      RECT 2519.760000 2083.320000 2583.600000 2157.760000 ;
      RECT 2451.760000 2083.320000 2515.600000 2157.760000 ;
      RECT 2383.760000 2083.320000 2447.600000 2157.760000 ;
      RECT 2315.760000 2083.320000 2379.600000 2157.760000 ;
      RECT 2247.760000 2083.320000 2311.600000 2157.760000 ;
      RECT 2210.875000 2083.320000 2243.600000 2085.920000 ;
      RECT 2111.760000 2083.320000 2175.600000 2157.760000 ;
      RECT 2043.760000 2083.320000 2107.600000 2157.760000 ;
      RECT 1975.760000 2083.320000 2039.600000 2157.760000 ;
      RECT 1907.760000 2083.320000 1971.600000 2157.760000 ;
      RECT 1839.760000 2083.320000 1903.600000 2157.760000 ;
      RECT 1771.760000 2083.320000 1835.600000 2157.760000 ;
      RECT 1703.760000 2083.320000 1767.600000 2157.760000 ;
      RECT 1691.015000 2083.320000 1699.600000 2085.920000 ;
      RECT 2587.760000 2082.320000 2700.655000 2083.320000 ;
      RECT 2210.875000 2082.320000 2311.600000 2083.320000 ;
      RECT 2179.760000 2082.320000 2180.795000 2085.920000 ;
      RECT 1691.015000 2082.320000 1767.600000 2083.320000 ;
      RECT 2587.760000 2079.720000 2697.055000 2082.320000 ;
      RECT 2451.760000 2079.720000 2583.600000 2083.320000 ;
      RECT 2315.760000 2079.720000 2447.600000 2083.320000 ;
      RECT 2214.475000 2079.720000 2311.600000 2082.320000 ;
      RECT 2043.760000 2079.720000 2175.600000 2083.320000 ;
      RECT 1907.760000 2079.720000 2039.600000 2083.320000 ;
      RECT 1771.760000 2079.720000 1903.600000 2083.320000 ;
      RECT 1694.615000 2079.720000 1767.600000 2082.320000 ;
      RECT 1159.760000 1819.315000 1223.600000 2155.160000 ;
      RECT 615.760000 1819.315000 679.600000 2155.160000 ;
      RECT 139.760000 1819.315000 203.600000 2155.160000 ;
      RECT 1159.760000 1816.715000 1166.015000 1819.315000 ;
      RECT 1091.760000 1816.715000 1155.600000 2157.760000 ;
      RECT 1023.760000 1816.715000 1087.600000 2157.760000 ;
      RECT 955.760000 1816.715000 1019.600000 2157.760000 ;
      RECT 887.760000 1816.715000 951.600000 2157.760000 ;
      RECT 819.760000 1816.715000 883.600000 2157.760000 ;
      RECT 751.760000 1816.715000 815.600000 2157.760000 ;
      RECT 683.760000 1816.715000 747.600000 2157.760000 ;
      RECT 615.760000 1816.715000 646.155000 1819.315000 ;
      RECT 547.760000 1816.715000 611.600000 2157.760000 ;
      RECT 479.760000 1816.715000 543.600000 2157.760000 ;
      RECT 411.760000 1816.715000 475.600000 2157.760000 ;
      RECT 343.760000 1816.715000 407.600000 2157.760000 ;
      RECT 275.760000 1816.715000 339.600000 2157.760000 ;
      RECT 207.760000 1816.715000 271.600000 2157.760000 ;
      RECT 156.375000 1816.715000 203.600000 1819.315000 ;
      RECT 1091.760000 1815.715000 1166.015000 1816.715000 ;
      RECT 676.235000 1815.715000 679.600000 1819.315000 ;
      RECT 547.760000 1815.715000 646.155000 1816.715000 ;
      RECT 156.375000 1815.715000 271.600000 1816.715000 ;
      RECT 1091.760000 1813.115000 1162.415000 1815.715000 ;
      RECT 955.760000 1813.115000 1087.600000 1816.715000 ;
      RECT 819.760000 1813.115000 951.600000 1816.715000 ;
      RECT 683.760000 1813.115000 815.600000 1816.715000 ;
      RECT 547.760000 1813.115000 642.555000 1815.715000 ;
      RECT 411.760000 1813.115000 543.600000 1816.715000 ;
      RECT 275.760000 1813.115000 407.600000 1816.715000 ;
      RECT 159.975000 1813.115000 271.600000 1815.715000 ;
      RECT 2214.475000 1679.420000 2697.055000 2079.720000 ;
      RECT 1694.615000 1679.420000 2177.195000 2079.720000 ;
      RECT 2699.655000 1676.820000 2700.655000 2082.320000 ;
      RECT 2587.760000 1676.820000 2697.055000 1679.420000 ;
      RECT 2214.475000 1676.820000 2311.600000 1679.420000 ;
      RECT 2210.875000 1676.820000 2211.875000 2082.320000 ;
      RECT 2179.795000 1676.820000 2180.795000 2082.320000 ;
      RECT 1694.615000 1676.820000 1767.600000 1679.420000 ;
      RECT 1691.015000 1676.820000 1692.015000 2082.320000 ;
      RECT 2587.760000 1675.820000 2700.655000 1676.820000 ;
      RECT 2451.760000 1675.820000 2583.600000 1679.420000 ;
      RECT 2315.760000 1675.820000 2447.600000 1679.420000 ;
      RECT 2210.875000 1675.820000 2311.600000 1676.820000 ;
      RECT 2043.760000 1675.820000 2175.600000 1679.420000 ;
      RECT 1907.760000 1675.820000 2039.600000 1679.420000 ;
      RECT 1771.760000 1675.820000 1903.600000 1679.420000 ;
      RECT 1691.015000 1675.820000 1767.600000 1676.820000 ;
      RECT 2703.255000 1673.220000 2719.600000 2085.920000 ;
      RECT 2655.760000 1673.220000 2700.655000 1675.820000 ;
      RECT 2210.875000 1673.220000 2243.600000 1675.820000 ;
      RECT 2183.395000 1673.220000 2208.275000 2085.920000 ;
      RECT 2179.760000 1673.220000 2180.795000 1676.820000 ;
      RECT 1691.015000 1673.220000 1699.600000 1675.820000 ;
      RECT 1635.760000 1673.220000 1688.415000 2085.920000 ;
      RECT 2655.760000 1622.355000 2719.600000 1673.220000 ;
      RECT 2179.760000 1622.355000 2243.600000 1673.220000 ;
      RECT 1635.760000 1622.355000 1699.600000 1673.220000 ;
      RECT 2655.760000 1619.755000 2700.655000 1622.355000 ;
      RECT 2587.760000 1619.755000 2651.600000 1675.820000 ;
      RECT 2519.760000 1619.755000 2583.600000 1675.820000 ;
      RECT 2451.760000 1619.755000 2515.600000 1675.820000 ;
      RECT 2383.760000 1619.755000 2447.600000 1675.820000 ;
      RECT 2315.760000 1619.755000 2379.600000 1675.820000 ;
      RECT 2247.760000 1619.755000 2311.600000 1675.820000 ;
      RECT 2210.875000 1619.755000 2243.600000 1622.355000 ;
      RECT 2111.760000 1619.755000 2175.600000 1675.820000 ;
      RECT 2043.760000 1619.755000 2107.600000 1675.820000 ;
      RECT 1975.760000 1619.755000 2039.600000 1675.820000 ;
      RECT 1907.760000 1619.755000 1971.600000 1675.820000 ;
      RECT 1839.760000 1619.755000 1903.600000 1675.820000 ;
      RECT 1771.760000 1619.755000 1835.600000 1675.820000 ;
      RECT 1703.760000 1619.755000 1767.600000 1675.820000 ;
      RECT 1691.015000 1619.755000 1699.600000 1622.355000 ;
      RECT 2587.760000 1618.755000 2700.655000 1619.755000 ;
      RECT 2210.875000 1618.755000 2311.600000 1619.755000 ;
      RECT 2179.760000 1618.755000 2180.795000 1622.355000 ;
      RECT 1691.015000 1618.755000 1767.600000 1619.755000 ;
      RECT 2587.760000 1616.155000 2697.055000 1618.755000 ;
      RECT 2451.760000 1616.155000 2583.600000 1619.755000 ;
      RECT 2315.760000 1616.155000 2447.600000 1619.755000 ;
      RECT 2214.475000 1616.155000 2311.600000 1618.755000 ;
      RECT 2043.760000 1616.155000 2175.600000 1619.755000 ;
      RECT 1907.760000 1616.155000 2039.600000 1619.755000 ;
      RECT 1771.760000 1616.155000 1903.600000 1619.755000 ;
      RECT 1694.615000 1616.155000 1767.600000 1618.755000 ;
      RECT 679.835000 1412.815000 1162.415000 1813.115000 ;
      RECT 159.975000 1412.815000 642.555000 1813.115000 ;
      RECT 1165.015000 1410.215000 1166.015000 1815.715000 ;
      RECT 1091.760000 1410.215000 1162.415000 1412.815000 ;
      RECT 676.235000 1410.215000 677.235000 1815.715000 ;
      RECT 645.155000 1410.215000 646.155000 1815.715000 ;
      RECT 547.760000 1410.215000 642.555000 1412.815000 ;
      RECT 159.975000 1410.215000 271.600000 1412.815000 ;
      RECT 156.375000 1410.215000 157.375000 1815.715000 ;
      RECT 1091.760000 1409.215000 1166.015000 1410.215000 ;
      RECT 955.760000 1409.215000 1087.600000 1412.815000 ;
      RECT 819.760000 1409.215000 951.600000 1412.815000 ;
      RECT 683.760000 1409.215000 815.600000 1412.815000 ;
      RECT 547.760000 1409.215000 646.155000 1410.215000 ;
      RECT 411.760000 1409.215000 543.600000 1412.815000 ;
      RECT 275.760000 1409.215000 407.600000 1412.815000 ;
      RECT 156.375000 1409.215000 271.600000 1410.215000 ;
      RECT 1168.615000 1406.615000 1223.600000 1819.315000 ;
      RECT 1159.760000 1406.615000 1166.015000 1409.215000 ;
      RECT 676.235000 1406.615000 679.600000 1410.215000 ;
      RECT 648.755000 1406.615000 673.635000 1819.315000 ;
      RECT 615.760000 1406.615000 646.155000 1409.215000 ;
      RECT 156.375000 1406.615000 203.600000 1409.215000 ;
      RECT 139.760000 1406.615000 153.775000 1819.315000 ;
      RECT 2214.475000 1215.855000 2697.055000 1616.155000 ;
      RECT 1694.615000 1215.855000 2177.195000 1616.155000 ;
      RECT 2699.655000 1213.255000 2700.655000 1618.755000 ;
      RECT 2587.760000 1213.255000 2697.055000 1215.855000 ;
      RECT 2214.475000 1213.255000 2311.600000 1215.855000 ;
      RECT 2210.875000 1213.255000 2211.875000 1618.755000 ;
      RECT 2179.795000 1213.255000 2180.795000 1618.755000 ;
      RECT 1694.615000 1213.255000 1767.600000 1215.855000 ;
      RECT 1691.015000 1213.255000 1692.015000 1618.755000 ;
      RECT 2587.760000 1212.255000 2700.655000 1213.255000 ;
      RECT 2451.760000 1212.255000 2583.600000 1215.855000 ;
      RECT 2315.760000 1212.255000 2447.600000 1215.855000 ;
      RECT 2210.875000 1212.255000 2311.600000 1213.255000 ;
      RECT 2043.760000 1212.255000 2175.600000 1215.855000 ;
      RECT 1907.760000 1212.255000 2039.600000 1215.855000 ;
      RECT 1771.760000 1212.255000 1903.600000 1215.855000 ;
      RECT 1691.015000 1212.255000 1767.600000 1213.255000 ;
      RECT 2703.255000 1209.655000 2719.600000 1622.355000 ;
      RECT 2655.760000 1209.655000 2700.655000 1212.255000 ;
      RECT 2210.875000 1209.655000 2243.600000 1212.255000 ;
      RECT 2183.395000 1209.655000 2208.275000 1622.355000 ;
      RECT 2179.760000 1209.655000 2180.795000 1213.255000 ;
      RECT 1691.015000 1209.655000 1699.600000 1212.255000 ;
      RECT 1635.760000 1209.655000 1688.415000 1622.355000 ;
      RECT 2655.760000 1150.960000 2719.600000 1209.655000 ;
      RECT 2179.760000 1150.960000 2243.600000 1209.655000 ;
      RECT 1635.760000 1150.960000 1699.600000 1209.655000 ;
      RECT 1159.760000 1150.960000 1223.600000 1406.615000 ;
      RECT 615.760000 1150.960000 679.600000 1406.615000 ;
      RECT 139.760000 1150.960000 203.600000 1406.615000 ;
      RECT 2655.760000 1148.360000 2700.655000 1150.960000 ;
      RECT 2587.760000 1148.360000 2651.600000 1212.255000 ;
      RECT 2519.760000 1148.360000 2583.600000 1212.255000 ;
      RECT 2451.760000 1148.360000 2515.600000 1212.255000 ;
      RECT 2383.760000 1148.360000 2447.600000 1212.255000 ;
      RECT 2315.760000 1148.360000 2379.600000 1212.255000 ;
      RECT 2247.760000 1148.360000 2311.600000 1212.255000 ;
      RECT 2210.875000 1148.360000 2243.600000 1150.960000 ;
      RECT 2111.760000 1148.360000 2175.600000 1212.255000 ;
      RECT 2043.760000 1148.360000 2107.600000 1212.255000 ;
      RECT 1975.760000 1148.360000 2039.600000 1212.255000 ;
      RECT 1907.760000 1148.360000 1971.600000 1212.255000 ;
      RECT 1839.760000 1148.360000 1903.600000 1212.255000 ;
      RECT 1771.760000 1148.360000 1835.600000 1212.255000 ;
      RECT 1703.760000 1148.360000 1767.600000 1212.255000 ;
      RECT 1691.015000 1148.360000 1699.600000 1150.960000 ;
      RECT 1159.760000 1148.360000 1166.015000 1150.960000 ;
      RECT 1091.760000 1148.360000 1155.600000 1409.215000 ;
      RECT 1023.760000 1148.360000 1087.600000 1409.215000 ;
      RECT 955.760000 1148.360000 1019.600000 1409.215000 ;
      RECT 887.760000 1148.360000 951.600000 1409.215000 ;
      RECT 819.760000 1148.360000 883.600000 1409.215000 ;
      RECT 751.760000 1148.360000 815.600000 1409.215000 ;
      RECT 683.760000 1148.360000 747.600000 1409.215000 ;
      RECT 615.760000 1148.360000 646.155000 1150.960000 ;
      RECT 547.760000 1148.360000 611.600000 1409.215000 ;
      RECT 479.760000 1148.360000 543.600000 1409.215000 ;
      RECT 411.760000 1148.360000 475.600000 1409.215000 ;
      RECT 343.760000 1148.360000 407.600000 1409.215000 ;
      RECT 275.760000 1148.360000 339.600000 1409.215000 ;
      RECT 207.760000 1148.360000 271.600000 1409.215000 ;
      RECT 156.375000 1148.360000 203.600000 1150.960000 ;
      RECT 2587.760000 1147.360000 2700.655000 1148.360000 ;
      RECT 2210.875000 1147.360000 2311.600000 1148.360000 ;
      RECT 2179.760000 1147.360000 2180.795000 1150.960000 ;
      RECT 1691.015000 1147.360000 1767.600000 1148.360000 ;
      RECT 1091.760000 1147.360000 1166.015000 1148.360000 ;
      RECT 676.235000 1147.360000 679.600000 1150.960000 ;
      RECT 547.760000 1147.360000 646.155000 1148.360000 ;
      RECT 156.375000 1147.360000 271.600000 1148.360000 ;
      RECT 2587.760000 1144.760000 2697.055000 1147.360000 ;
      RECT 2451.760000 1144.760000 2583.600000 1148.360000 ;
      RECT 2315.760000 1144.760000 2447.600000 1148.360000 ;
      RECT 2214.475000 1144.760000 2311.600000 1147.360000 ;
      RECT 2043.760000 1144.760000 2175.600000 1148.360000 ;
      RECT 1907.760000 1144.760000 2039.600000 1148.360000 ;
      RECT 1771.760000 1144.760000 1903.600000 1148.360000 ;
      RECT 1694.615000 1144.760000 1767.600000 1147.360000 ;
      RECT 1091.760000 1144.760000 1162.415000 1147.360000 ;
      RECT 955.760000 1144.760000 1087.600000 1148.360000 ;
      RECT 819.760000 1144.760000 951.600000 1148.360000 ;
      RECT 683.760000 1144.760000 815.600000 1148.360000 ;
      RECT 547.760000 1144.760000 642.555000 1147.360000 ;
      RECT 411.760000 1144.760000 543.600000 1148.360000 ;
      RECT 275.760000 1144.760000 407.600000 1148.360000 ;
      RECT 159.975000 1144.760000 271.600000 1147.360000 ;
      RECT 2214.475000 744.460000 2697.055000 1144.760000 ;
      RECT 1694.615000 744.460000 2177.195000 1144.760000 ;
      RECT 679.835000 744.460000 1162.415000 1144.760000 ;
      RECT 159.975000 744.460000 642.555000 1144.760000 ;
      RECT 2699.655000 741.860000 2700.655000 1147.360000 ;
      RECT 2587.760000 741.860000 2697.055000 744.460000 ;
      RECT 2214.475000 741.860000 2311.600000 744.460000 ;
      RECT 2210.875000 741.860000 2211.875000 1147.360000 ;
      RECT 2179.795000 741.860000 2180.795000 1147.360000 ;
      RECT 1694.615000 741.860000 1767.600000 744.460000 ;
      RECT 1691.015000 741.860000 1692.015000 1147.360000 ;
      RECT 1165.015000 741.860000 1166.015000 1147.360000 ;
      RECT 1091.760000 741.860000 1162.415000 744.460000 ;
      RECT 676.235000 741.860000 677.235000 1147.360000 ;
      RECT 645.155000 741.860000 646.155000 1147.360000 ;
      RECT 547.760000 741.860000 642.555000 744.460000 ;
      RECT 159.975000 741.860000 271.600000 744.460000 ;
      RECT 156.375000 741.860000 157.375000 1147.360000 ;
      RECT 2587.760000 740.860000 2700.655000 741.860000 ;
      RECT 2451.760000 740.860000 2583.600000 744.460000 ;
      RECT 2315.760000 740.860000 2447.600000 744.460000 ;
      RECT 2210.875000 740.860000 2311.600000 741.860000 ;
      RECT 2043.760000 740.860000 2175.600000 744.460000 ;
      RECT 1907.760000 740.860000 2039.600000 744.460000 ;
      RECT 1771.760000 740.860000 1903.600000 744.460000 ;
      RECT 1691.015000 740.860000 1767.600000 741.860000 ;
      RECT 1091.760000 740.860000 1166.015000 741.860000 ;
      RECT 955.760000 740.860000 1087.600000 744.460000 ;
      RECT 819.760000 740.860000 951.600000 744.460000 ;
      RECT 683.760000 740.860000 815.600000 744.460000 ;
      RECT 547.760000 740.860000 646.155000 741.860000 ;
      RECT 411.760000 740.860000 543.600000 744.460000 ;
      RECT 275.760000 740.860000 407.600000 744.460000 ;
      RECT 156.375000 740.860000 271.600000 741.860000 ;
      RECT 2703.255000 738.260000 2719.600000 1150.960000 ;
      RECT 2655.760000 738.260000 2700.655000 740.860000 ;
      RECT 2210.875000 738.260000 2243.600000 740.860000 ;
      RECT 2183.395000 738.260000 2208.275000 1150.960000 ;
      RECT 2179.760000 738.260000 2180.795000 741.860000 ;
      RECT 1691.015000 738.260000 1699.600000 740.860000 ;
      RECT 1635.760000 738.260000 1688.415000 1150.960000 ;
      RECT 1168.615000 738.260000 1223.600000 1150.960000 ;
      RECT 1159.760000 738.260000 1166.015000 740.860000 ;
      RECT 676.235000 738.260000 679.600000 741.860000 ;
      RECT 648.755000 738.260000 673.635000 1150.960000 ;
      RECT 615.760000 738.260000 646.155000 740.860000 ;
      RECT 156.375000 738.260000 203.600000 740.860000 ;
      RECT 139.760000 738.260000 153.775000 1150.960000 ;
      RECT 2655.760000 666.810000 2719.600000 738.260000 ;
      RECT 2179.760000 666.810000 2243.600000 738.260000 ;
      RECT 1635.760000 666.810000 1699.600000 738.260000 ;
      RECT 1159.760000 666.810000 1223.600000 738.260000 ;
      RECT 615.760000 666.810000 679.600000 738.260000 ;
      RECT 139.760000 666.810000 203.600000 738.260000 ;
      RECT 2655.760000 664.210000 2700.655000 666.810000 ;
      RECT 2587.760000 664.210000 2651.600000 740.860000 ;
      RECT 2519.760000 664.210000 2583.600000 740.860000 ;
      RECT 2451.760000 664.210000 2515.600000 740.860000 ;
      RECT 2383.760000 664.210000 2447.600000 740.860000 ;
      RECT 2315.760000 664.210000 2379.600000 740.860000 ;
      RECT 2247.760000 664.210000 2311.600000 740.860000 ;
      RECT 2210.875000 664.210000 2243.600000 666.810000 ;
      RECT 2111.760000 664.210000 2175.600000 740.860000 ;
      RECT 2043.760000 664.210000 2107.600000 740.860000 ;
      RECT 1975.760000 664.210000 2039.600000 740.860000 ;
      RECT 1907.760000 664.210000 1971.600000 740.860000 ;
      RECT 1839.760000 664.210000 1903.600000 740.860000 ;
      RECT 1771.760000 664.210000 1835.600000 740.860000 ;
      RECT 1703.760000 664.210000 1767.600000 740.860000 ;
      RECT 1691.015000 664.210000 1699.600000 666.810000 ;
      RECT 1159.760000 664.210000 1166.015000 666.810000 ;
      RECT 1091.760000 664.210000 1155.600000 740.860000 ;
      RECT 1023.760000 664.210000 1087.600000 740.860000 ;
      RECT 955.760000 664.210000 1019.600000 740.860000 ;
      RECT 887.760000 664.210000 951.600000 740.860000 ;
      RECT 819.760000 664.210000 883.600000 740.860000 ;
      RECT 751.760000 664.210000 815.600000 740.860000 ;
      RECT 683.760000 664.210000 747.600000 740.860000 ;
      RECT 615.760000 664.210000 646.155000 666.810000 ;
      RECT 547.760000 664.210000 611.600000 740.860000 ;
      RECT 479.760000 664.210000 543.600000 740.860000 ;
      RECT 411.760000 664.210000 475.600000 740.860000 ;
      RECT 343.760000 664.210000 407.600000 740.860000 ;
      RECT 275.760000 664.210000 339.600000 740.860000 ;
      RECT 207.760000 664.210000 271.600000 740.860000 ;
      RECT 156.375000 664.210000 203.600000 666.810000 ;
      RECT 2587.760000 663.210000 2700.655000 664.210000 ;
      RECT 2210.875000 663.210000 2311.600000 664.210000 ;
      RECT 2179.760000 663.210000 2180.795000 666.810000 ;
      RECT 1691.015000 663.210000 1767.600000 664.210000 ;
      RECT 1091.760000 663.210000 1166.015000 664.210000 ;
      RECT 676.235000 663.210000 679.600000 666.810000 ;
      RECT 547.760000 663.210000 646.155000 664.210000 ;
      RECT 156.375000 663.210000 271.600000 664.210000 ;
      RECT 2587.760000 660.610000 2697.055000 663.210000 ;
      RECT 2451.760000 660.610000 2583.600000 664.210000 ;
      RECT 2315.760000 660.610000 2447.600000 664.210000 ;
      RECT 2214.475000 660.610000 2311.600000 663.210000 ;
      RECT 2043.760000 660.610000 2175.600000 664.210000 ;
      RECT 1907.760000 660.610000 2039.600000 664.210000 ;
      RECT 1771.760000 660.610000 1903.600000 664.210000 ;
      RECT 1694.615000 660.610000 1767.600000 663.210000 ;
      RECT 1091.760000 660.610000 1162.415000 663.210000 ;
      RECT 955.760000 660.610000 1087.600000 664.210000 ;
      RECT 819.760000 660.610000 951.600000 664.210000 ;
      RECT 683.760000 660.610000 815.600000 664.210000 ;
      RECT 547.760000 660.610000 642.555000 663.210000 ;
      RECT 411.760000 660.610000 543.600000 664.210000 ;
      RECT 275.760000 660.610000 407.600000 664.210000 ;
      RECT 159.975000 660.610000 271.600000 663.210000 ;
      RECT 2214.475000 260.310000 2697.055000 660.610000 ;
      RECT 1694.615000 260.310000 2177.195000 660.610000 ;
      RECT 679.835000 260.310000 1162.415000 660.610000 ;
      RECT 159.975000 260.310000 642.555000 660.610000 ;
      RECT 2699.655000 257.710000 2700.655000 663.210000 ;
      RECT 2587.760000 257.710000 2697.055000 260.310000 ;
      RECT 2214.475000 257.710000 2311.600000 260.310000 ;
      RECT 2210.875000 257.710000 2211.875000 663.210000 ;
      RECT 2179.795000 257.710000 2180.795000 663.210000 ;
      RECT 1694.615000 257.710000 1767.600000 260.310000 ;
      RECT 1691.015000 257.710000 1692.015000 663.210000 ;
      RECT 1165.015000 257.710000 1166.015000 663.210000 ;
      RECT 1091.760000 257.710000 1162.415000 260.310000 ;
      RECT 676.235000 257.710000 677.235000 663.210000 ;
      RECT 645.155000 257.710000 646.155000 663.210000 ;
      RECT 547.760000 257.710000 642.555000 260.310000 ;
      RECT 159.975000 257.710000 271.600000 260.310000 ;
      RECT 156.375000 257.710000 157.375000 663.210000 ;
      RECT 2587.760000 256.710000 2700.655000 257.710000 ;
      RECT 2451.760000 256.710000 2583.600000 260.310000 ;
      RECT 2315.760000 256.710000 2447.600000 260.310000 ;
      RECT 2210.875000 256.710000 2311.600000 257.710000 ;
      RECT 2043.760000 256.710000 2175.600000 260.310000 ;
      RECT 1907.760000 256.710000 2039.600000 260.310000 ;
      RECT 1771.760000 256.710000 1903.600000 260.310000 ;
      RECT 1691.015000 256.710000 1767.600000 257.710000 ;
      RECT 1091.760000 256.710000 1166.015000 257.710000 ;
      RECT 955.760000 256.710000 1087.600000 260.310000 ;
      RECT 819.760000 256.710000 951.600000 260.310000 ;
      RECT 683.760000 256.710000 815.600000 260.310000 ;
      RECT 547.760000 256.710000 646.155000 257.710000 ;
      RECT 411.760000 256.710000 543.600000 260.310000 ;
      RECT 275.760000 256.710000 407.600000 260.310000 ;
      RECT 156.375000 256.710000 271.600000 257.710000 ;
      RECT 2703.255000 254.110000 2719.600000 666.810000 ;
      RECT 2655.760000 254.110000 2700.655000 256.710000 ;
      RECT 2210.875000 254.110000 2243.600000 256.710000 ;
      RECT 2183.395000 254.110000 2208.275000 666.810000 ;
      RECT 2179.760000 254.110000 2180.795000 257.710000 ;
      RECT 1691.015000 254.110000 1699.600000 256.710000 ;
      RECT 1635.760000 254.110000 1688.415000 666.810000 ;
      RECT 1168.615000 254.110000 1223.600000 666.810000 ;
      RECT 1159.760000 254.110000 1166.015000 256.710000 ;
      RECT 676.235000 254.110000 679.600000 257.710000 ;
      RECT 648.755000 254.110000 673.635000 666.810000 ;
      RECT 615.760000 254.110000 646.155000 256.710000 ;
      RECT 156.375000 254.110000 203.600000 256.710000 ;
      RECT 139.760000 254.110000 153.775000 666.810000 ;
      RECT 2723.760000 25.060000 2787.600000 3442.940000 ;
      RECT 2655.760000 25.060000 2719.600000 254.110000 ;
      RECT 2587.760000 25.060000 2651.600000 256.710000 ;
      RECT 2519.760000 25.060000 2583.600000 256.710000 ;
      RECT 2451.760000 25.060000 2515.600000 256.710000 ;
      RECT 2383.760000 25.060000 2447.600000 256.710000 ;
      RECT 2315.760000 25.060000 2379.600000 256.710000 ;
      RECT 2247.760000 25.060000 2311.600000 256.710000 ;
      RECT 2179.760000 25.060000 2243.600000 254.110000 ;
      RECT 2111.760000 25.060000 2175.600000 256.710000 ;
      RECT 2043.760000 25.060000 2107.600000 256.710000 ;
      RECT 1975.760000 25.060000 2039.600000 256.710000 ;
      RECT 1907.760000 25.060000 1971.600000 256.710000 ;
      RECT 1839.760000 25.060000 1903.600000 256.710000 ;
      RECT 1771.760000 25.060000 1835.600000 256.710000 ;
      RECT 1703.760000 25.060000 1767.600000 256.710000 ;
      RECT 1635.760000 25.060000 1699.600000 254.110000 ;
      RECT 1567.760000 25.060000 1631.600000 3442.940000 ;
      RECT 1499.760000 25.060000 1563.600000 3442.940000 ;
      RECT 1431.760000 25.060000 1495.600000 3442.940000 ;
      RECT 1363.760000 25.060000 1427.600000 3442.940000 ;
      RECT 1295.760000 25.060000 1359.600000 3442.940000 ;
      RECT 1227.760000 25.060000 1291.600000 3442.940000 ;
      RECT 1159.760000 25.060000 1223.600000 254.110000 ;
      RECT 1091.760000 25.060000 1155.600000 256.710000 ;
      RECT 1023.760000 25.060000 1087.600000 256.710000 ;
      RECT 955.760000 25.060000 1019.600000 256.710000 ;
      RECT 887.760000 25.060000 951.600000 256.710000 ;
      RECT 819.760000 25.060000 883.600000 256.710000 ;
      RECT 751.760000 25.060000 815.600000 256.710000 ;
      RECT 683.760000 25.060000 747.600000 256.710000 ;
      RECT 615.760000 25.060000 679.600000 254.110000 ;
      RECT 547.760000 25.060000 611.600000 256.710000 ;
      RECT 479.760000 25.060000 543.600000 256.710000 ;
      RECT 411.760000 25.060000 475.600000 256.710000 ;
      RECT 343.760000 25.060000 407.600000 256.710000 ;
      RECT 275.760000 25.060000 339.600000 256.710000 ;
      RECT 207.760000 25.060000 271.600000 256.710000 ;
      RECT 139.760000 25.060000 203.600000 254.110000 ;
      RECT 71.760000 25.060000 135.600000 3442.940000 ;
      RECT 2791.760000 18.860000 2830.900000 3449.140000 ;
      RECT 2655.760000 18.860000 2787.600000 25.060000 ;
      RECT 2519.760000 18.860000 2651.600000 25.060000 ;
      RECT 2383.760000 18.860000 2515.600000 25.060000 ;
      RECT 2247.760000 18.860000 2379.600000 25.060000 ;
      RECT 2111.760000 18.860000 2243.600000 25.060000 ;
      RECT 1975.760000 18.860000 2107.600000 25.060000 ;
      RECT 1839.760000 18.860000 1971.600000 25.060000 ;
      RECT 1703.760000 18.860000 1835.600000 25.060000 ;
      RECT 1567.760000 18.860000 1699.600000 25.060000 ;
      RECT 1431.760000 18.860000 1563.600000 25.060000 ;
      RECT 1295.760000 18.860000 1427.600000 25.060000 ;
      RECT 1159.760000 18.860000 1291.600000 25.060000 ;
      RECT 1023.760000 18.860000 1155.600000 25.060000 ;
      RECT 887.760000 18.860000 1019.600000 25.060000 ;
      RECT 751.760000 18.860000 883.600000 25.060000 ;
      RECT 615.760000 18.860000 747.600000 25.060000 ;
      RECT 479.760000 18.860000 611.600000 25.060000 ;
      RECT 343.760000 18.860000 475.600000 25.060000 ;
      RECT 207.760000 18.860000 339.600000 25.060000 ;
      RECT 71.760000 18.860000 203.600000 25.060000 ;
      RECT 28.920000 18.860000 67.600000 3449.140000 ;
      RECT 2841.000000 0.000000 2859.820000 3470.040000 ;
      RECT 2834.800000 0.000000 2837.100000 3470.040000 ;
      RECT 28.920000 0.000000 2830.900000 18.860000 ;
      RECT 22.720000 0.000000 25.020000 3470.040000 ;
      RECT 0.000000 0.000000 18.820000 3470.040000 ;
  END
END user_proj_example

END LIBRARY
